VERSION 5.8 ;
BUSBITCHARS "[]" ;
DIVIDERCHAR "/" ;
UNITS
    DATABASE MICRONS 1000 ;
END UNITS

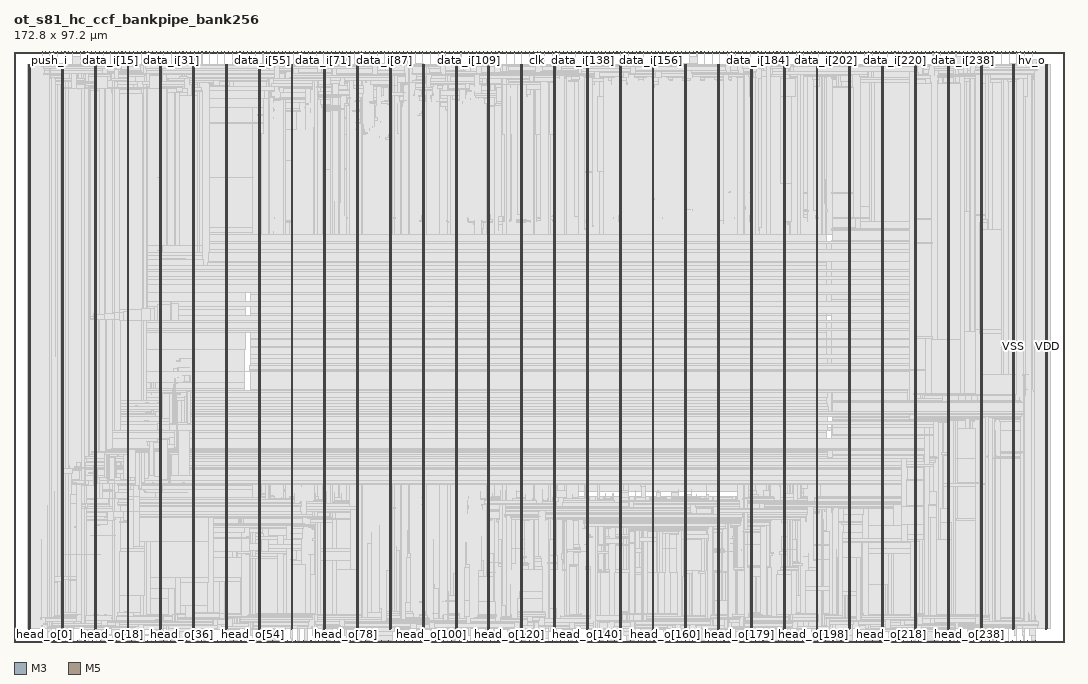
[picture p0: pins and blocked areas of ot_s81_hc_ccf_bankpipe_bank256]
MACRO ot_s81_hc_ccf_bankpipe_bank256
  FOREIGN ot_s81_hc_ccf_bankpipe_bank256 0 0 ;
  CLASS BLOCK ;
  SIZE 172.8 BY 97.2 ;
  PIN clk
    DIRECTION INPUT ;
    USE SIGNAL ;
    PORT
      LAYER M3 ;
        RECT  86.076 97.056 86.094 97.2 ;
    END
  END clk
  PIN data_i[0]
    DIRECTION INPUT ;
    USE SIGNAL ;
    PORT
      LAYER M5 ;
        RECT  6.48 97.008 6.504 97.2 ;
    END
  END data_i[0]
  PIN data_i[100]
    DIRECTION INPUT ;
    USE SIGNAL ;
    PORT
      LAYER M5 ;
        RECT  69.168 97.008 69.192 97.2 ;
    END
  END data_i[100]
  PIN data_i[101]
    DIRECTION INPUT ;
    USE SIGNAL ;
    PORT
      LAYER M3 ;
        RECT  69.804 97.056 69.822 97.2 ;
    END
  END data_i[101]
  PIN data_i[102]
    DIRECTION INPUT ;
    USE SIGNAL ;
    PORT
      LAYER M5 ;
        RECT  70.416 97.008 70.44 97.2 ;
    END
  END data_i[102]
  PIN data_i[103]
    DIRECTION INPUT ;
    USE SIGNAL ;
    PORT
      LAYER M3 ;
        RECT  71.028 97.056 71.046 97.2 ;
    END
  END data_i[103]
  PIN data_i[104]
    DIRECTION INPUT ;
    USE SIGNAL ;
    PORT
      LAYER M5 ;
        RECT  71.664 97.008 71.688 97.2 ;
    END
  END data_i[104]
  PIN data_i[105]
    DIRECTION INPUT ;
    USE SIGNAL ;
    PORT
      LAYER M3 ;
        RECT  72.288 97.056 72.306 97.2 ;
    END
  END data_i[105]
  PIN data_i[106]
    DIRECTION INPUT ;
    USE SIGNAL ;
    PORT
      LAYER M5 ;
        RECT  72.912 97.008 72.936 97.2 ;
    END
  END data_i[106]
  PIN data_i[107]
    DIRECTION INPUT ;
    USE SIGNAL ;
    PORT
      LAYER M3 ;
        RECT  73.548 97.056 73.566 97.2 ;
    END
  END data_i[107]
  PIN data_i[108]
    DIRECTION INPUT ;
    USE SIGNAL ;
    PORT
      LAYER M5 ;
        RECT  74.16 97.008 74.184 97.2 ;
    END
  END data_i[108]
  PIN data_i[109]
    DIRECTION INPUT ;
    USE SIGNAL ;
    PORT
      LAYER M3 ;
        RECT  74.808 97.056 74.826 97.2 ;
    END
  END data_i[109]
  PIN data_i[10]
    DIRECTION INPUT ;
    USE SIGNAL ;
    PORT
      LAYER M5 ;
        RECT  12.768 97.008 12.792 97.2 ;
    END
  END data_i[10]
  PIN data_i[110]
    DIRECTION INPUT ;
    USE SIGNAL ;
    PORT
      LAYER M5 ;
        RECT  75.408 97.008 75.432 97.2 ;
    END
  END data_i[110]
  PIN data_i[111]
    DIRECTION INPUT ;
    USE SIGNAL ;
    PORT
      LAYER M3 ;
        RECT  76.068 97.056 76.086 97.2 ;
    END
  END data_i[111]
  PIN data_i[112]
    DIRECTION INPUT ;
    USE SIGNAL ;
    PORT
      LAYER M5 ;
        RECT  76.656 97.008 76.68 97.2 ;
    END
  END data_i[112]
  PIN data_i[113]
    DIRECTION INPUT ;
    USE SIGNAL ;
    PORT
      LAYER M3 ;
        RECT  77.292 97.056 77.31 97.2 ;
    END
  END data_i[113]
  PIN data_i[114]
    DIRECTION INPUT ;
    USE SIGNAL ;
    PORT
      LAYER M5 ;
        RECT  77.952 97.008 77.976 97.2 ;
    END
  END data_i[114]
  PIN data_i[115]
    DIRECTION INPUT ;
    USE SIGNAL ;
    PORT
      LAYER M3 ;
        RECT  78.552 97.056 78.57 97.2 ;
    END
  END data_i[115]
  PIN data_i[116]
    DIRECTION INPUT ;
    USE SIGNAL ;
    PORT
      LAYER M5 ;
        RECT  79.2 97.008 79.224 97.2 ;
    END
  END data_i[116]
  PIN data_i[117]
    DIRECTION INPUT ;
    USE SIGNAL ;
    PORT
      LAYER M3 ;
        RECT  79.812 97.056 79.83 97.2 ;
    END
  END data_i[117]
  PIN data_i[118]
    DIRECTION INPUT ;
    USE SIGNAL ;
    PORT
      LAYER M5 ;
        RECT  80.448 97.008 80.472 97.2 ;
    END
  END data_i[118]
  PIN data_i[119]
    DIRECTION INPUT ;
    USE SIGNAL ;
    PORT
      LAYER M3 ;
        RECT  81.072 97.056 81.09 97.2 ;
    END
  END data_i[119]
  PIN data_i[11]
    DIRECTION INPUT ;
    USE SIGNAL ;
    PORT
      LAYER M3 ;
        RECT  13.392 97.056 13.41 97.2 ;
    END
  END data_i[11]
  PIN data_i[120]
    DIRECTION INPUT ;
    USE SIGNAL ;
    PORT
      LAYER M5 ;
        RECT  81.696 97.008 81.72 97.2 ;
    END
  END data_i[120]
  PIN data_i[121]
    DIRECTION INPUT ;
    USE SIGNAL ;
    PORT
      LAYER M3 ;
        RECT  82.332 97.056 82.35 97.2 ;
    END
  END data_i[121]
  PIN data_i[122]
    DIRECTION INPUT ;
    USE SIGNAL ;
    PORT
      LAYER M5 ;
        RECT  82.944 97.008 82.968 97.2 ;
    END
  END data_i[122]
  PIN data_i[123]
    DIRECTION INPUT ;
    USE SIGNAL ;
    PORT
      LAYER M3 ;
        RECT  83.556 97.056 83.574 97.2 ;
    END
  END data_i[123]
  PIN data_i[124]
    DIRECTION INPUT ;
    USE SIGNAL ;
    PORT
      LAYER M5 ;
        RECT  84.192 97.008 84.216 97.2 ;
    END
  END data_i[124]
  PIN data_i[125]
    DIRECTION INPUT ;
    USE SIGNAL ;
    PORT
      LAYER M3 ;
        RECT  84.816 97.056 84.834 97.2 ;
    END
  END data_i[125]
  PIN data_i[126]
    DIRECTION INPUT ;
    USE SIGNAL ;
    PORT
      LAYER M5 ;
        RECT  85.44 97.008 85.464 97.2 ;
    END
  END data_i[126]
  PIN data_i[127]
    DIRECTION INPUT ;
    USE SIGNAL ;
    PORT
      LAYER M5 ;
        RECT  86.688 97.008 86.712 97.2 ;
    END
  END data_i[127]
  PIN data_i[128]
    DIRECTION INPUT ;
    USE SIGNAL ;
    PORT
      LAYER M3 ;
        RECT  87.336 97.056 87.354 97.2 ;
    END
  END data_i[128]
  PIN data_i[129]
    DIRECTION INPUT ;
    USE SIGNAL ;
    PORT
      LAYER M5 ;
        RECT  87.936 97.008 87.96 97.2 ;
    END
  END data_i[129]
  PIN data_i[12]
    DIRECTION INPUT ;
    USE SIGNAL ;
    PORT
      LAYER M5 ;
        RECT  14.016 97.008 14.04 97.2 ;
    END
  END data_i[12]
  PIN data_i[130]
    DIRECTION INPUT ;
    USE SIGNAL ;
    PORT
      LAYER M3 ;
        RECT  88.596 97.056 88.614 97.2 ;
    END
  END data_i[130]
  PIN data_i[131]
    DIRECTION INPUT ;
    USE SIGNAL ;
    PORT
      LAYER M5 ;
        RECT  89.184 97.008 89.208 97.2 ;
    END
  END data_i[131]
  PIN data_i[132]
    DIRECTION INPUT ;
    USE SIGNAL ;
    PORT
      LAYER M3 ;
        RECT  89.82 97.056 89.838 97.2 ;
    END
  END data_i[132]
  PIN data_i[133]
    DIRECTION INPUT ;
    USE SIGNAL ;
    PORT
      LAYER M5 ;
        RECT  90.48 97.008 90.504 97.2 ;
    END
  END data_i[133]
  PIN data_i[134]
    DIRECTION INPUT ;
    USE SIGNAL ;
    PORT
      LAYER M3 ;
        RECT  91.08 97.056 91.098 97.2 ;
    END
  END data_i[134]
  PIN data_i[135]
    DIRECTION INPUT ;
    USE SIGNAL ;
    PORT
      LAYER M5 ;
        RECT  91.728 97.008 91.752 97.2 ;
    END
  END data_i[135]
  PIN data_i[136]
    DIRECTION INPUT ;
    USE SIGNAL ;
    PORT
      LAYER M3 ;
        RECT  92.34 97.056 92.358 97.2 ;
    END
  END data_i[136]
  PIN data_i[137]
    DIRECTION INPUT ;
    USE SIGNAL ;
    PORT
      LAYER M5 ;
        RECT  92.976 97.008 93 97.2 ;
    END
  END data_i[137]
  PIN data_i[138]
    DIRECTION INPUT ;
    USE SIGNAL ;
    PORT
      LAYER M3 ;
        RECT  93.6 97.056 93.618 97.2 ;
    END
  END data_i[138]
  PIN data_i[139]
    DIRECTION INPUT ;
    USE SIGNAL ;
    PORT
      LAYER M5 ;
        RECT  94.224 97.008 94.248 97.2 ;
    END
  END data_i[139]
  PIN data_i[13]
    DIRECTION INPUT ;
    USE SIGNAL ;
    PORT
      LAYER M3 ;
        RECT  14.652 97.056 14.67 97.2 ;
    END
  END data_i[13]
  PIN data_i[140]
    DIRECTION INPUT ;
    USE SIGNAL ;
    PORT
      LAYER M3 ;
        RECT  94.86 97.056 94.878 97.2 ;
    END
  END data_i[140]
  PIN data_i[141]
    DIRECTION INPUT ;
    USE SIGNAL ;
    PORT
      LAYER M5 ;
        RECT  95.472 97.008 95.496 97.2 ;
    END
  END data_i[141]
  PIN data_i[142]
    DIRECTION INPUT ;
    USE SIGNAL ;
    PORT
      LAYER M3 ;
        RECT  96.12 97.056 96.138 97.2 ;
    END
  END data_i[142]
  PIN data_i[143]
    DIRECTION INPUT ;
    USE SIGNAL ;
    PORT
      LAYER M5 ;
        RECT  96.72 97.008 96.744 97.2 ;
    END
  END data_i[143]
  PIN data_i[144]
    DIRECTION INPUT ;
    USE SIGNAL ;
    PORT
      LAYER M3 ;
        RECT  97.344 97.056 97.362 97.2 ;
    END
  END data_i[144]
  PIN data_i[145]
    DIRECTION INPUT ;
    USE SIGNAL ;
    PORT
      LAYER M5 ;
        RECT  97.968 97.008 97.992 97.2 ;
    END
  END data_i[145]
  PIN data_i[146]
    DIRECTION INPUT ;
    USE SIGNAL ;
    PORT
      LAYER M3 ;
        RECT  98.604 97.056 98.622 97.2 ;
    END
  END data_i[146]
  PIN data_i[147]
    DIRECTION INPUT ;
    USE SIGNAL ;
    PORT
      LAYER M5 ;
        RECT  99.216 97.008 99.24 97.2 ;
    END
  END data_i[147]
  PIN data_i[148]
    DIRECTION INPUT ;
    USE SIGNAL ;
    PORT
      LAYER M3 ;
        RECT  99.864 97.056 99.882 97.2 ;
    END
  END data_i[148]
  PIN data_i[149]
    DIRECTION INPUT ;
    USE SIGNAL ;
    PORT
      LAYER M5 ;
        RECT  100.464 97.008 100.488 97.2 ;
    END
  END data_i[149]
  PIN data_i[14]
    DIRECTION INPUT ;
    USE SIGNAL ;
    PORT
      LAYER M5 ;
        RECT  15.264 97.008 15.288 97.2 ;
    END
  END data_i[14]
  PIN data_i[150]
    DIRECTION INPUT ;
    USE SIGNAL ;
    PORT
      LAYER M3 ;
        RECT  101.124 97.056 101.142 97.2 ;
    END
  END data_i[150]
  PIN data_i[151]
    DIRECTION INPUT ;
    USE SIGNAL ;
    PORT
      LAYER M5 ;
        RECT  101.76 97.008 101.784 97.2 ;
    END
  END data_i[151]
  PIN data_i[152]
    DIRECTION INPUT ;
    USE SIGNAL ;
    PORT
      LAYER M3 ;
        RECT  102.384 97.056 102.402 97.2 ;
    END
  END data_i[152]
  PIN data_i[153]
    DIRECTION INPUT ;
    USE SIGNAL ;
    PORT
      LAYER M5 ;
        RECT  103.008 97.008 103.032 97.2 ;
    END
  END data_i[153]
  PIN data_i[154]
    DIRECTION INPUT ;
    USE SIGNAL ;
    PORT
      LAYER M3 ;
        RECT  103.608 97.056 103.626 97.2 ;
    END
  END data_i[154]
  PIN data_i[155]
    DIRECTION INPUT ;
    USE SIGNAL ;
    PORT
      LAYER M5 ;
        RECT  104.256 97.008 104.28 97.2 ;
    END
  END data_i[155]
  PIN data_i[156]
    DIRECTION INPUT ;
    USE SIGNAL ;
    PORT
      LAYER M3 ;
        RECT  104.868 97.056 104.886 97.2 ;
    END
  END data_i[156]
  PIN data_i[157]
    DIRECTION INPUT ;
    USE SIGNAL ;
    PORT
      LAYER M5 ;
        RECT  105.504 97.008 105.528 97.2 ;
    END
  END data_i[157]
  PIN data_i[158]
    DIRECTION INPUT ;
    USE SIGNAL ;
    PORT
      LAYER M3 ;
        RECT  106.128 97.056 106.146 97.2 ;
    END
  END data_i[158]
  PIN data_i[159]
    DIRECTION INPUT ;
    USE SIGNAL ;
    PORT
      LAYER M5 ;
        RECT  106.752 97.008 106.776 97.2 ;
    END
  END data_i[159]
  PIN data_i[15]
    DIRECTION INPUT ;
    USE SIGNAL ;
    PORT
      LAYER M3 ;
        RECT  15.912 97.056 15.93 97.2 ;
    END
  END data_i[15]
  PIN data_i[160]
    DIRECTION INPUT ;
    USE SIGNAL ;
    PORT
      LAYER M3 ;
        RECT  107.388 97.056 107.406 97.2 ;
    END
  END data_i[160]
  PIN data_i[161]
    DIRECTION INPUT ;
    USE SIGNAL ;
    PORT
      LAYER M5 ;
        RECT  108 97.008 108.024 97.2 ;
    END
  END data_i[161]
  PIN data_i[162]
    DIRECTION INPUT ;
    USE SIGNAL ;
    PORT
      LAYER M3 ;
        RECT  108.648 97.056 108.666 97.2 ;
    END
  END data_i[162]
  PIN data_i[163]
    DIRECTION INPUT ;
    USE SIGNAL ;
    PORT
      LAYER M5 ;
        RECT  109.248 97.008 109.272 97.2 ;
    END
  END data_i[163]
  PIN data_i[164]
    DIRECTION INPUT ;
    USE SIGNAL ;
    PORT
      LAYER M3 ;
        RECT  109.872 97.056 109.89 97.2 ;
    END
  END data_i[164]
  PIN data_i[165]
    DIRECTION INPUT ;
    USE SIGNAL ;
    PORT
      LAYER M5 ;
        RECT  110.496 97.008 110.52 97.2 ;
    END
  END data_i[165]
  PIN data_i[166]
    DIRECTION INPUT ;
    USE SIGNAL ;
    PORT
      LAYER M3 ;
        RECT  111.132 97.056 111.15 97.2 ;
    END
  END data_i[166]
  PIN data_i[167]
    DIRECTION INPUT ;
    USE SIGNAL ;
    PORT
      LAYER M5 ;
        RECT  111.744 97.008 111.768 97.2 ;
    END
  END data_i[167]
  PIN data_i[168]
    DIRECTION INPUT ;
    USE SIGNAL ;
    PORT
      LAYER M3 ;
        RECT  112.392 97.056 112.41 97.2 ;
    END
  END data_i[168]
  PIN data_i[169]
    DIRECTION INPUT ;
    USE SIGNAL ;
    PORT
      LAYER M5 ;
        RECT  113.04 97.008 113.064 97.2 ;
    END
  END data_i[169]
  PIN data_i[16]
    DIRECTION INPUT ;
    USE SIGNAL ;
    PORT
      LAYER M5 ;
        RECT  16.512 97.008 16.536 97.2 ;
    END
  END data_i[16]
  PIN data_i[170]
    DIRECTION INPUT ;
    USE SIGNAL ;
    PORT
      LAYER M3 ;
        RECT  113.652 97.056 113.67 97.2 ;
    END
  END data_i[170]
  PIN data_i[171]
    DIRECTION INPUT ;
    USE SIGNAL ;
    PORT
      LAYER M5 ;
        RECT  114.288 97.008 114.312 97.2 ;
    END
  END data_i[171]
  PIN data_i[172]
    DIRECTION INPUT ;
    USE SIGNAL ;
    PORT
      LAYER M3 ;
        RECT  114.912 97.056 114.93 97.2 ;
    END
  END data_i[172]
  PIN data_i[173]
    DIRECTION INPUT ;
    USE SIGNAL ;
    PORT
      LAYER M5 ;
        RECT  115.536 97.008 115.56 97.2 ;
    END
  END data_i[173]
  PIN data_i[174]
    DIRECTION INPUT ;
    USE SIGNAL ;
    PORT
      LAYER M3 ;
        RECT  116.136 97.056 116.154 97.2 ;
    END
  END data_i[174]
  PIN data_i[175]
    DIRECTION INPUT ;
    USE SIGNAL ;
    PORT
      LAYER M5 ;
        RECT  116.784 97.008 116.808 97.2 ;
    END
  END data_i[175]
  PIN data_i[176]
    DIRECTION INPUT ;
    USE SIGNAL ;
    PORT
      LAYER M3 ;
        RECT  117.396 97.056 117.414 97.2 ;
    END
  END data_i[176]
  PIN data_i[177]
    DIRECTION INPUT ;
    USE SIGNAL ;
    PORT
      LAYER M5 ;
        RECT  118.032 97.008 118.056 97.2 ;
    END
  END data_i[177]
  PIN data_i[178]
    DIRECTION INPUT ;
    USE SIGNAL ;
    PORT
      LAYER M3 ;
        RECT  118.656 97.056 118.674 97.2 ;
    END
  END data_i[178]
  PIN data_i[179]
    DIRECTION INPUT ;
    USE SIGNAL ;
    PORT
      LAYER M5 ;
        RECT  119.28 97.008 119.304 97.2 ;
    END
  END data_i[179]
  PIN data_i[17]
    DIRECTION INPUT ;
    USE SIGNAL ;
    PORT
      LAYER M3 ;
        RECT  17.172 97.056 17.19 97.2 ;
    END
  END data_i[17]
  PIN data_i[180]
    DIRECTION INPUT ;
    USE SIGNAL ;
    PORT
      LAYER M3 ;
        RECT  119.916 97.056 119.934 97.2 ;
    END
  END data_i[180]
  PIN data_i[181]
    DIRECTION INPUT ;
    USE SIGNAL ;
    PORT
      LAYER M5 ;
        RECT  120.528 97.008 120.552 97.2 ;
    END
  END data_i[181]
  PIN data_i[182]
    DIRECTION INPUT ;
    USE SIGNAL ;
    PORT
      LAYER M3 ;
        RECT  121.176 97.056 121.194 97.2 ;
    END
  END data_i[182]
  PIN data_i[183]
    DIRECTION INPUT ;
    USE SIGNAL ;
    PORT
      LAYER M5 ;
        RECT  121.776 97.008 121.8 97.2 ;
    END
  END data_i[183]
  PIN data_i[184]
    DIRECTION INPUT ;
    USE SIGNAL ;
    PORT
      LAYER M3 ;
        RECT  122.436 97.056 122.454 97.2 ;
    END
  END data_i[184]
  PIN data_i[185]
    DIRECTION INPUT ;
    USE SIGNAL ;
    PORT
      LAYER M5 ;
        RECT  123.024 97.008 123.048 97.2 ;
    END
  END data_i[185]
  PIN data_i[186]
    DIRECTION INPUT ;
    USE SIGNAL ;
    PORT
      LAYER M3 ;
        RECT  123.66 97.056 123.678 97.2 ;
    END
  END data_i[186]
  PIN data_i[187]
    DIRECTION INPUT ;
    USE SIGNAL ;
    PORT
      LAYER M5 ;
        RECT  124.272 97.008 124.296 97.2 ;
    END
  END data_i[187]
  PIN data_i[188]
    DIRECTION INPUT ;
    USE SIGNAL ;
    PORT
      LAYER M3 ;
        RECT  124.92 97.056 124.938 97.2 ;
    END
  END data_i[188]
  PIN data_i[189]
    DIRECTION INPUT ;
    USE SIGNAL ;
    PORT
      LAYER M5 ;
        RECT  125.568 97.008 125.592 97.2 ;
    END
  END data_i[189]
  PIN data_i[18]
    DIRECTION INPUT ;
    USE SIGNAL ;
    PORT
      LAYER M5 ;
        RECT  17.76 97.008 17.784 97.2 ;
    END
  END data_i[18]
  PIN data_i[190]
    DIRECTION INPUT ;
    USE SIGNAL ;
    PORT
      LAYER M3 ;
        RECT  126.18 97.056 126.198 97.2 ;
    END
  END data_i[190]
  PIN data_i[191]
    DIRECTION INPUT ;
    USE SIGNAL ;
    PORT
      LAYER M5 ;
        RECT  126.816 97.008 126.84 97.2 ;
    END
  END data_i[191]
  PIN data_i[192]
    DIRECTION INPUT ;
    USE SIGNAL ;
    PORT
      LAYER M3 ;
        RECT  127.44 97.056 127.458 97.2 ;
    END
  END data_i[192]
  PIN data_i[193]
    DIRECTION INPUT ;
    USE SIGNAL ;
    PORT
      LAYER M5 ;
        RECT  128.064 97.008 128.088 97.2 ;
    END
  END data_i[193]
  PIN data_i[194]
    DIRECTION INPUT ;
    USE SIGNAL ;
    PORT
      LAYER M3 ;
        RECT  128.7 97.056 128.718 97.2 ;
    END
  END data_i[194]
  PIN data_i[195]
    DIRECTION INPUT ;
    USE SIGNAL ;
    PORT
      LAYER M5 ;
        RECT  129.312 97.008 129.336 97.2 ;
    END
  END data_i[195]
  PIN data_i[196]
    DIRECTION INPUT ;
    USE SIGNAL ;
    PORT
      LAYER M3 ;
        RECT  129.924 97.056 129.942 97.2 ;
    END
  END data_i[196]
  PIN data_i[197]
    DIRECTION INPUT ;
    USE SIGNAL ;
    PORT
      LAYER M5 ;
        RECT  130.56 97.008 130.584 97.2 ;
    END
  END data_i[197]
  PIN data_i[198]
    DIRECTION INPUT ;
    USE SIGNAL ;
    PORT
      LAYER M3 ;
        RECT  131.184 97.056 131.202 97.2 ;
    END
  END data_i[198]
  PIN data_i[199]
    DIRECTION INPUT ;
    USE SIGNAL ;
    PORT
      LAYER M5 ;
        RECT  131.808 97.008 131.832 97.2 ;
    END
  END data_i[199]
  PIN data_i[19]
    DIRECTION INPUT ;
    USE SIGNAL ;
    PORT
      LAYER M3 ;
        RECT  18.396 97.056 18.414 97.2 ;
    END
  END data_i[19]
  PIN data_i[1]
    DIRECTION INPUT ;
    USE SIGNAL ;
    PORT
      LAYER M3 ;
        RECT  7.128 97.056 7.146 97.2 ;
    END
  END data_i[1]
  PIN data_i[200]
    DIRECTION INPUT ;
    USE SIGNAL ;
    PORT
      LAYER M3 ;
        RECT  132.444 97.056 132.462 97.2 ;
    END
  END data_i[200]
  PIN data_i[201]
    DIRECTION INPUT ;
    USE SIGNAL ;
    PORT
      LAYER M5 ;
        RECT  133.056 97.008 133.08 97.2 ;
    END
  END data_i[201]
  PIN data_i[202]
    DIRECTION INPUT ;
    USE SIGNAL ;
    PORT
      LAYER M3 ;
        RECT  133.704 97.056 133.722 97.2 ;
    END
  END data_i[202]
  PIN data_i[203]
    DIRECTION INPUT ;
    USE SIGNAL ;
    PORT
      LAYER M5 ;
        RECT  134.304 97.008 134.328 97.2 ;
    END
  END data_i[203]
  PIN data_i[204]
    DIRECTION INPUT ;
    USE SIGNAL ;
    PORT
      LAYER M3 ;
        RECT  134.964 97.056 134.982 97.2 ;
    END
  END data_i[204]
  PIN data_i[205]
    DIRECTION INPUT ;
    USE SIGNAL ;
    PORT
      LAYER M5 ;
        RECT  135.552 97.008 135.576 97.2 ;
    END
  END data_i[205]
  PIN data_i[206]
    DIRECTION INPUT ;
    USE SIGNAL ;
    PORT
      LAYER M3 ;
        RECT  136.188 97.056 136.206 97.2 ;
    END
  END data_i[206]
  PIN data_i[207]
    DIRECTION INPUT ;
    USE SIGNAL ;
    PORT
      LAYER M5 ;
        RECT  136.848 97.008 136.872 97.2 ;
    END
  END data_i[207]
  PIN data_i[208]
    DIRECTION INPUT ;
    USE SIGNAL ;
    PORT
      LAYER M3 ;
        RECT  137.448 97.056 137.466 97.2 ;
    END
  END data_i[208]
  PIN data_i[209]
    DIRECTION INPUT ;
    USE SIGNAL ;
    PORT
      LAYER M5 ;
        RECT  138.096 97.008 138.12 97.2 ;
    END
  END data_i[209]
  PIN data_i[20]
    DIRECTION INPUT ;
    USE SIGNAL ;
    PORT
      LAYER M5 ;
        RECT  19.056 97.008 19.08 97.2 ;
    END
  END data_i[20]
  PIN data_i[210]
    DIRECTION INPUT ;
    USE SIGNAL ;
    PORT
      LAYER M3 ;
        RECT  138.708 97.056 138.726 97.2 ;
    END
  END data_i[210]
  PIN data_i[211]
    DIRECTION INPUT ;
    USE SIGNAL ;
    PORT
      LAYER M5 ;
        RECT  139.344 97.008 139.368 97.2 ;
    END
  END data_i[211]
  PIN data_i[212]
    DIRECTION INPUT ;
    USE SIGNAL ;
    PORT
      LAYER M3 ;
        RECT  139.968 97.056 139.986 97.2 ;
    END
  END data_i[212]
  PIN data_i[213]
    DIRECTION INPUT ;
    USE SIGNAL ;
    PORT
      LAYER M5 ;
        RECT  140.592 97.008 140.616 97.2 ;
    END
  END data_i[213]
  PIN data_i[214]
    DIRECTION INPUT ;
    USE SIGNAL ;
    PORT
      LAYER M3 ;
        RECT  141.228 97.056 141.246 97.2 ;
    END
  END data_i[214]
  PIN data_i[215]
    DIRECTION INPUT ;
    USE SIGNAL ;
    PORT
      LAYER M5 ;
        RECT  141.84 97.008 141.864 97.2 ;
    END
  END data_i[215]
  PIN data_i[216]
    DIRECTION INPUT ;
    USE SIGNAL ;
    PORT
      LAYER M3 ;
        RECT  142.452 97.056 142.47 97.2 ;
    END
  END data_i[216]
  PIN data_i[217]
    DIRECTION INPUT ;
    USE SIGNAL ;
    PORT
      LAYER M5 ;
        RECT  143.088 97.008 143.112 97.2 ;
    END
  END data_i[217]
  PIN data_i[218]
    DIRECTION INPUT ;
    USE SIGNAL ;
    PORT
      LAYER M3 ;
        RECT  143.712 97.056 143.73 97.2 ;
    END
  END data_i[218]
  PIN data_i[219]
    DIRECTION INPUT ;
    USE SIGNAL ;
    PORT
      LAYER M5 ;
        RECT  144.336 97.008 144.36 97.2 ;
    END
  END data_i[219]
  PIN data_i[21]
    DIRECTION INPUT ;
    USE SIGNAL ;
    PORT
      LAYER M3 ;
        RECT  19.656 97.056 19.674 97.2 ;
    END
  END data_i[21]
  PIN data_i[220]
    DIRECTION INPUT ;
    USE SIGNAL ;
    PORT
      LAYER M3 ;
        RECT  144.972 97.056 144.99 97.2 ;
    END
  END data_i[220]
  PIN data_i[221]
    DIRECTION INPUT ;
    USE SIGNAL ;
    PORT
      LAYER M5 ;
        RECT  145.584 97.008 145.608 97.2 ;
    END
  END data_i[221]
  PIN data_i[222]
    DIRECTION INPUT ;
    USE SIGNAL ;
    PORT
      LAYER M3 ;
        RECT  146.232 97.056 146.25 97.2 ;
    END
  END data_i[222]
  PIN data_i[223]
    DIRECTION INPUT ;
    USE SIGNAL ;
    PORT
      LAYER M5 ;
        RECT  146.832 97.008 146.856 97.2 ;
    END
  END data_i[223]
  PIN data_i[224]
    DIRECTION INPUT ;
    USE SIGNAL ;
    PORT
      LAYER M3 ;
        RECT  147.492 97.056 147.51 97.2 ;
    END
  END data_i[224]
  PIN data_i[225]
    DIRECTION INPUT ;
    USE SIGNAL ;
    PORT
      LAYER M5 ;
        RECT  148.128 97.008 148.152 97.2 ;
    END
  END data_i[225]
  PIN data_i[226]
    DIRECTION INPUT ;
    USE SIGNAL ;
    PORT
      LAYER M3 ;
        RECT  148.752 97.056 148.77 97.2 ;
    END
  END data_i[226]
  PIN data_i[227]
    DIRECTION INPUT ;
    USE SIGNAL ;
    PORT
      LAYER M5 ;
        RECT  149.376 97.008 149.4 97.2 ;
    END
  END data_i[227]
  PIN data_i[228]
    DIRECTION INPUT ;
    USE SIGNAL ;
    PORT
      LAYER M3 ;
        RECT  149.976 97.056 149.994 97.2 ;
    END
  END data_i[228]
  PIN data_i[229]
    DIRECTION INPUT ;
    USE SIGNAL ;
    PORT
      LAYER M5 ;
        RECT  150.624 97.008 150.648 97.2 ;
    END
  END data_i[229]
  PIN data_i[22]
    DIRECTION INPUT ;
    USE SIGNAL ;
    PORT
      LAYER M5 ;
        RECT  20.304 97.008 20.328 97.2 ;
    END
  END data_i[22]
  PIN data_i[230]
    DIRECTION INPUT ;
    USE SIGNAL ;
    PORT
      LAYER M3 ;
        RECT  151.236 97.056 151.254 97.2 ;
    END
  END data_i[230]
  PIN data_i[231]
    DIRECTION INPUT ;
    USE SIGNAL ;
    PORT
      LAYER M5 ;
        RECT  151.872 97.008 151.896 97.2 ;
    END
  END data_i[231]
  PIN data_i[232]
    DIRECTION INPUT ;
    USE SIGNAL ;
    PORT
      LAYER M3 ;
        RECT  152.496 97.056 152.514 97.2 ;
    END
  END data_i[232]
  PIN data_i[233]
    DIRECTION INPUT ;
    USE SIGNAL ;
    PORT
      LAYER M5 ;
        RECT  153.12 97.008 153.144 97.2 ;
    END
  END data_i[233]
  PIN data_i[234]
    DIRECTION INPUT ;
    USE SIGNAL ;
    PORT
      LAYER M3 ;
        RECT  153.756 97.056 153.774 97.2 ;
    END
  END data_i[234]
  PIN data_i[235]
    DIRECTION INPUT ;
    USE SIGNAL ;
    PORT
      LAYER M5 ;
        RECT  154.368 97.008 154.392 97.2 ;
    END
  END data_i[235]
  PIN data_i[236]
    DIRECTION INPUT ;
    USE SIGNAL ;
    PORT
      LAYER M3 ;
        RECT  155.016 97.056 155.034 97.2 ;
    END
  END data_i[236]
  PIN data_i[237]
    DIRECTION INPUT ;
    USE SIGNAL ;
    PORT
      LAYER M5 ;
        RECT  155.616 97.008 155.64 97.2 ;
    END
  END data_i[237]
  PIN data_i[238]
    DIRECTION INPUT ;
    USE SIGNAL ;
    PORT
      LAYER M3 ;
        RECT  156.24 97.056 156.258 97.2 ;
    END
  END data_i[238]
  PIN data_i[239]
    DIRECTION INPUT ;
    USE SIGNAL ;
    PORT
      LAYER M5 ;
        RECT  156.864 97.008 156.888 97.2 ;
    END
  END data_i[239]
  PIN data_i[23]
    DIRECTION INPUT ;
    USE SIGNAL ;
    PORT
      LAYER M3 ;
        RECT  20.916 97.056 20.934 97.2 ;
    END
  END data_i[23]
  PIN data_i[240]
    DIRECTION INPUT ;
    USE SIGNAL ;
    PORT
      LAYER M3 ;
        RECT  157.5 97.056 157.518 97.2 ;
    END
  END data_i[240]
  PIN data_i[241]
    DIRECTION INPUT ;
    USE SIGNAL ;
    PORT
      LAYER M5 ;
        RECT  158.112 97.008 158.136 97.2 ;
    END
  END data_i[241]
  PIN data_i[242]
    DIRECTION INPUT ;
    USE SIGNAL ;
    PORT
      LAYER M3 ;
        RECT  158.76 97.056 158.778 97.2 ;
    END
  END data_i[242]
  PIN data_i[243]
    DIRECTION INPUT ;
    USE SIGNAL ;
    PORT
      LAYER M5 ;
        RECT  159.36 97.008 159.384 97.2 ;
    END
  END data_i[243]
  PIN data_i[244]
    DIRECTION INPUT ;
    USE SIGNAL ;
    PORT
      LAYER M3 ;
        RECT  160.02 97.056 160.038 97.2 ;
    END
  END data_i[244]
  PIN data_i[245]
    DIRECTION INPUT ;
    USE SIGNAL ;
    PORT
      LAYER M5 ;
        RECT  160.656 97.008 160.68 97.2 ;
    END
  END data_i[245]
  PIN data_i[246]
    DIRECTION INPUT ;
    USE SIGNAL ;
    PORT
      LAYER M3 ;
        RECT  161.28 97.056 161.298 97.2 ;
    END
  END data_i[246]
  PIN data_i[247]
    DIRECTION INPUT ;
    USE SIGNAL ;
    PORT
      LAYER M5 ;
        RECT  161.904 97.008 161.928 97.2 ;
    END
  END data_i[247]
  PIN data_i[248]
    DIRECTION INPUT ;
    USE SIGNAL ;
    PORT
      LAYER M3 ;
        RECT  162.504 97.056 162.522 97.2 ;
    END
  END data_i[248]
  PIN data_i[249]
    DIRECTION INPUT ;
    USE SIGNAL ;
    PORT
      LAYER M5 ;
        RECT  163.152 97.008 163.176 97.2 ;
    END
  END data_i[249]
  PIN data_i[24]
    DIRECTION INPUT ;
    USE SIGNAL ;
    PORT
      LAYER M5 ;
        RECT  21.552 97.008 21.576 97.2 ;
    END
  END data_i[24]
  PIN data_i[250]
    DIRECTION INPUT ;
    USE SIGNAL ;
    PORT
      LAYER M3 ;
        RECT  163.764 97.056 163.782 97.2 ;
    END
  END data_i[250]
  PIN data_i[251]
    DIRECTION INPUT ;
    USE SIGNAL ;
    PORT
      LAYER M5 ;
        RECT  164.4 97.008 164.424 97.2 ;
    END
  END data_i[251]
  PIN data_i[252]
    DIRECTION INPUT ;
    USE SIGNAL ;
    PORT
      LAYER M3 ;
        RECT  165.024 97.056 165.042 97.2 ;
    END
  END data_i[252]
  PIN data_i[253]
    DIRECTION INPUT ;
    USE SIGNAL ;
    PORT
      LAYER M5 ;
        RECT  165.648 97.008 165.672 97.2 ;
    END
  END data_i[253]
  PIN data_i[254]
    DIRECTION INPUT ;
    USE SIGNAL ;
    PORT
      LAYER M3 ;
        RECT  166.284 97.056 166.302 97.2 ;
    END
  END data_i[254]
  PIN data_i[255]
    DIRECTION INPUT ;
    USE SIGNAL ;
    PORT
      LAYER M5 ;
        RECT  166.896 97.008 166.92 97.2 ;
    END
  END data_i[255]
  PIN data_i[25]
    DIRECTION INPUT ;
    USE SIGNAL ;
    PORT
      LAYER M3 ;
        RECT  22.176 97.056 22.194 97.2 ;
    END
  END data_i[25]
  PIN data_i[26]
    DIRECTION INPUT ;
    USE SIGNAL ;
    PORT
      LAYER M5 ;
        RECT  22.8 97.008 22.824 97.2 ;
    END
  END data_i[26]
  PIN data_i[27]
    DIRECTION INPUT ;
    USE SIGNAL ;
    PORT
      LAYER M3 ;
        RECT  23.436 97.056 23.454 97.2 ;
    END
  END data_i[27]
  PIN data_i[28]
    DIRECTION INPUT ;
    USE SIGNAL ;
    PORT
      LAYER M5 ;
        RECT  24.048 97.008 24.072 97.2 ;
    END
  END data_i[28]
  PIN data_i[29]
    DIRECTION INPUT ;
    USE SIGNAL ;
    PORT
      LAYER M3 ;
        RECT  24.66 97.056 24.678 97.2 ;
    END
  END data_i[29]
  PIN data_i[2]
    DIRECTION INPUT ;
    USE SIGNAL ;
    PORT
      LAYER M5 ;
        RECT  7.776 97.008 7.8 97.2 ;
    END
  END data_i[2]
  PIN data_i[30]
    DIRECTION INPUT ;
    USE SIGNAL ;
    PORT
      LAYER M5 ;
        RECT  25.296 97.008 25.32 97.2 ;
    END
  END data_i[30]
  PIN data_i[31]
    DIRECTION INPUT ;
    USE SIGNAL ;
    PORT
      LAYER M3 ;
        RECT  25.92 97.056 25.938 97.2 ;
    END
  END data_i[31]
  PIN data_i[32]
    DIRECTION INPUT ;
    USE SIGNAL ;
    PORT
      LAYER M5 ;
        RECT  26.544 97.008 26.568 97.2 ;
    END
  END data_i[32]
  PIN data_i[33]
    DIRECTION INPUT ;
    USE SIGNAL ;
    PORT
      LAYER M3 ;
        RECT  27.18 97.056 27.198 97.2 ;
    END
  END data_i[33]
  PIN data_i[34]
    DIRECTION INPUT ;
    USE SIGNAL ;
    PORT
      LAYER M5 ;
        RECT  27.792 97.008 27.816 97.2 ;
    END
  END data_i[34]
  PIN data_i[35]
    DIRECTION INPUT ;
    USE SIGNAL ;
    PORT
      LAYER M3 ;
        RECT  28.44 97.056 28.458 97.2 ;
    END
  END data_i[35]
  PIN data_i[36]
    DIRECTION INPUT ;
    USE SIGNAL ;
    PORT
      LAYER M5 ;
        RECT  29.04 97.008 29.064 97.2 ;
    END
  END data_i[36]
  PIN data_i[37]
    DIRECTION INPUT ;
    USE SIGNAL ;
    PORT
      LAYER M3 ;
        RECT  29.7 97.056 29.718 97.2 ;
    END
  END data_i[37]
  PIN data_i[38]
    DIRECTION INPUT ;
    USE SIGNAL ;
    PORT
      LAYER M5 ;
        RECT  30.288 97.008 30.312 97.2 ;
    END
  END data_i[38]
  PIN data_i[39]
    DIRECTION INPUT ;
    USE SIGNAL ;
    PORT
      LAYER M3 ;
        RECT  30.924 97.056 30.942 97.2 ;
    END
  END data_i[39]
  PIN data_i[3]
    DIRECTION INPUT ;
    USE SIGNAL ;
    PORT
      LAYER M3 ;
        RECT  8.388 97.056 8.406 97.2 ;
    END
  END data_i[3]
  PIN data_i[40]
    DIRECTION INPUT ;
    USE SIGNAL ;
    PORT
      LAYER M5 ;
        RECT  31.584 97.008 31.608 97.2 ;
    END
  END data_i[40]
  PIN data_i[41]
    DIRECTION INPUT ;
    USE SIGNAL ;
    PORT
      LAYER M3 ;
        RECT  32.184 97.056 32.202 97.2 ;
    END
  END data_i[41]
  PIN data_i[42]
    DIRECTION INPUT ;
    USE SIGNAL ;
    PORT
      LAYER M5 ;
        RECT  32.832 97.008 32.856 97.2 ;
    END
  END data_i[42]
  PIN data_i[43]
    DIRECTION INPUT ;
    USE SIGNAL ;
    PORT
      LAYER M3 ;
        RECT  33.444 97.056 33.462 97.2 ;
    END
  END data_i[43]
  PIN data_i[44]
    DIRECTION INPUT ;
    USE SIGNAL ;
    PORT
      LAYER M5 ;
        RECT  34.08 97.008 34.104 97.2 ;
    END
  END data_i[44]
  PIN data_i[45]
    DIRECTION INPUT ;
    USE SIGNAL ;
    PORT
      LAYER M3 ;
        RECT  34.704 97.056 34.722 97.2 ;
    END
  END data_i[45]
  PIN data_i[46]
    DIRECTION INPUT ;
    USE SIGNAL ;
    PORT
      LAYER M5 ;
        RECT  35.328 97.008 35.352 97.2 ;
    END
  END data_i[46]
  PIN data_i[47]
    DIRECTION INPUT ;
    USE SIGNAL ;
    PORT
      LAYER M3 ;
        RECT  35.964 97.056 35.982 97.2 ;
    END
  END data_i[47]
  PIN data_i[48]
    DIRECTION INPUT ;
    USE SIGNAL ;
    PORT
      LAYER M5 ;
        RECT  36.576 97.008 36.6 97.2 ;
    END
  END data_i[48]
  PIN data_i[49]
    DIRECTION INPUT ;
    USE SIGNAL ;
    PORT
      LAYER M3 ;
        RECT  37.188 97.056 37.206 97.2 ;
    END
  END data_i[49]
  PIN data_i[4]
    DIRECTION INPUT ;
    USE SIGNAL ;
    PORT
      LAYER M5 ;
        RECT  9.024 97.008 9.048 97.2 ;
    END
  END data_i[4]
  PIN data_i[50]
    DIRECTION INPUT ;
    USE SIGNAL ;
    PORT
      LAYER M5 ;
        RECT  37.824 97.008 37.848 97.2 ;
    END
  END data_i[50]
  PIN data_i[51]
    DIRECTION INPUT ;
    USE SIGNAL ;
    PORT
      LAYER M3 ;
        RECT  38.448 97.056 38.466 97.2 ;
    END
  END data_i[51]
  PIN data_i[52]
    DIRECTION INPUT ;
    USE SIGNAL ;
    PORT
      LAYER M5 ;
        RECT  39.072 97.008 39.096 97.2 ;
    END
  END data_i[52]
  PIN data_i[53]
    DIRECTION INPUT ;
    USE SIGNAL ;
    PORT
      LAYER M3 ;
        RECT  39.708 97.056 39.726 97.2 ;
    END
  END data_i[53]
  PIN data_i[54]
    DIRECTION INPUT ;
    USE SIGNAL ;
    PORT
      LAYER M5 ;
        RECT  40.32 97.008 40.344 97.2 ;
    END
  END data_i[54]
  PIN data_i[55]
    DIRECTION INPUT ;
    USE SIGNAL ;
    PORT
      LAYER M3 ;
        RECT  40.968 97.056 40.986 97.2 ;
    END
  END data_i[55]
  PIN data_i[56]
    DIRECTION INPUT ;
    USE SIGNAL ;
    PORT
      LAYER M5 ;
        RECT  41.568 97.008 41.592 97.2 ;
    END
  END data_i[56]
  PIN data_i[57]
    DIRECTION INPUT ;
    USE SIGNAL ;
    PORT
      LAYER M3 ;
        RECT  42.228 97.056 42.246 97.2 ;
    END
  END data_i[57]
  PIN data_i[58]
    DIRECTION INPUT ;
    USE SIGNAL ;
    PORT
      LAYER M5 ;
        RECT  42.864 97.008 42.888 97.2 ;
    END
  END data_i[58]
  PIN data_i[59]
    DIRECTION INPUT ;
    USE SIGNAL ;
    PORT
      LAYER M3 ;
        RECT  43.488 97.056 43.506 97.2 ;
    END
  END data_i[59]
  PIN data_i[5]
    DIRECTION INPUT ;
    USE SIGNAL ;
    PORT
      LAYER M3 ;
        RECT  9.648 97.056 9.666 97.2 ;
    END
  END data_i[5]
  PIN data_i[60]
    DIRECTION INPUT ;
    USE SIGNAL ;
    PORT
      LAYER M5 ;
        RECT  44.112 97.008 44.136 97.2 ;
    END
  END data_i[60]
  PIN data_i[61]
    DIRECTION INPUT ;
    USE SIGNAL ;
    PORT
      LAYER M3 ;
        RECT  44.712 97.056 44.73 97.2 ;
    END
  END data_i[61]
  PIN data_i[62]
    DIRECTION INPUT ;
    USE SIGNAL ;
    PORT
      LAYER M5 ;
        RECT  45.36 97.008 45.384 97.2 ;
    END
  END data_i[62]
  PIN data_i[63]
    DIRECTION INPUT ;
    USE SIGNAL ;
    PORT
      LAYER M3 ;
        RECT  45.972 97.056 45.99 97.2 ;
    END
  END data_i[63]
  PIN data_i[64]
    DIRECTION INPUT ;
    USE SIGNAL ;
    PORT
      LAYER M5 ;
        RECT  46.608 97.008 46.632 97.2 ;
    END
  END data_i[64]
  PIN data_i[65]
    DIRECTION INPUT ;
    USE SIGNAL ;
    PORT
      LAYER M3 ;
        RECT  47.232 97.056 47.25 97.2 ;
    END
  END data_i[65]
  PIN data_i[66]
    DIRECTION INPUT ;
    USE SIGNAL ;
    PORT
      LAYER M5 ;
        RECT  47.856 97.008 47.88 97.2 ;
    END
  END data_i[66]
  PIN data_i[67]
    DIRECTION INPUT ;
    USE SIGNAL ;
    PORT
      LAYER M3 ;
        RECT  48.492 97.056 48.51 97.2 ;
    END
  END data_i[67]
  PIN data_i[68]
    DIRECTION INPUT ;
    USE SIGNAL ;
    PORT
      LAYER M5 ;
        RECT  49.104 97.008 49.128 97.2 ;
    END
  END data_i[68]
  PIN data_i[69]
    DIRECTION INPUT ;
    USE SIGNAL ;
    PORT
      LAYER M3 ;
        RECT  49.752 97.056 49.77 97.2 ;
    END
  END data_i[69]
  PIN data_i[6]
    DIRECTION INPUT ;
    USE SIGNAL ;
    PORT
      LAYER M5 ;
        RECT  10.272 97.008 10.296 97.2 ;
    END
  END data_i[6]
  PIN data_i[70]
    DIRECTION INPUT ;
    USE SIGNAL ;
    PORT
      LAYER M5 ;
        RECT  50.352 97.008 50.376 97.2 ;
    END
  END data_i[70]
  PIN data_i[71]
    DIRECTION INPUT ;
    USE SIGNAL ;
    PORT
      LAYER M3 ;
        RECT  50.976 97.056 50.994 97.2 ;
    END
  END data_i[71]
  PIN data_i[72]
    DIRECTION INPUT ;
    USE SIGNAL ;
    PORT
      LAYER M5 ;
        RECT  51.6 97.008 51.624 97.2 ;
    END
  END data_i[72]
  PIN data_i[73]
    DIRECTION INPUT ;
    USE SIGNAL ;
    PORT
      LAYER M3 ;
        RECT  52.236 97.056 52.254 97.2 ;
    END
  END data_i[73]
  PIN data_i[74]
    DIRECTION INPUT ;
    USE SIGNAL ;
    PORT
      LAYER M5 ;
        RECT  52.848 97.008 52.872 97.2 ;
    END
  END data_i[74]
  PIN data_i[75]
    DIRECTION INPUT ;
    USE SIGNAL ;
    PORT
      LAYER M3 ;
        RECT  53.496 97.056 53.514 97.2 ;
    END
  END data_i[75]
  PIN data_i[76]
    DIRECTION INPUT ;
    USE SIGNAL ;
    PORT
      LAYER M5 ;
        RECT  54.096 97.008 54.12 97.2 ;
    END
  END data_i[76]
  PIN data_i[77]
    DIRECTION INPUT ;
    USE SIGNAL ;
    PORT
      LAYER M3 ;
        RECT  54.756 97.056 54.774 97.2 ;
    END
  END data_i[77]
  PIN data_i[78]
    DIRECTION INPUT ;
    USE SIGNAL ;
    PORT
      LAYER M5 ;
        RECT  55.392 97.008 55.416 97.2 ;
    END
  END data_i[78]
  PIN data_i[79]
    DIRECTION INPUT ;
    USE SIGNAL ;
    PORT
      LAYER M3 ;
        RECT  56.016 97.056 56.034 97.2 ;
    END
  END data_i[79]
  PIN data_i[7]
    DIRECTION INPUT ;
    USE SIGNAL ;
    PORT
      LAYER M3 ;
        RECT  10.872 97.056 10.89 97.2 ;
    END
  END data_i[7]
  PIN data_i[80]
    DIRECTION INPUT ;
    USE SIGNAL ;
    PORT
      LAYER M5 ;
        RECT  56.64 97.008 56.664 97.2 ;
    END
  END data_i[80]
  PIN data_i[81]
    DIRECTION INPUT ;
    USE SIGNAL ;
    PORT
      LAYER M3 ;
        RECT  57.24 97.056 57.258 97.2 ;
    END
  END data_i[81]
  PIN data_i[82]
    DIRECTION INPUT ;
    USE SIGNAL ;
    PORT
      LAYER M5 ;
        RECT  57.888 97.008 57.912 97.2 ;
    END
  END data_i[82]
  PIN data_i[83]
    DIRECTION INPUT ;
    USE SIGNAL ;
    PORT
      LAYER M3 ;
        RECT  58.5 97.056 58.518 97.2 ;
    END
  END data_i[83]
  PIN data_i[84]
    DIRECTION INPUT ;
    USE SIGNAL ;
    PORT
      LAYER M5 ;
        RECT  59.136 97.008 59.16 97.2 ;
    END
  END data_i[84]
  PIN data_i[85]
    DIRECTION INPUT ;
    USE SIGNAL ;
    PORT
      LAYER M3 ;
        RECT  59.76 97.056 59.778 97.2 ;
    END
  END data_i[85]
  PIN data_i[86]
    DIRECTION INPUT ;
    USE SIGNAL ;
    PORT
      LAYER M5 ;
        RECT  60.384 97.008 60.408 97.2 ;
    END
  END data_i[86]
  PIN data_i[87]
    DIRECTION INPUT ;
    USE SIGNAL ;
    PORT
      LAYER M3 ;
        RECT  61.02 97.056 61.038 97.2 ;
    END
  END data_i[87]
  PIN data_i[88]
    DIRECTION INPUT ;
    USE SIGNAL ;
    PORT
      LAYER M5 ;
        RECT  61.632 97.008 61.656 97.2 ;
    END
  END data_i[88]
  PIN data_i[89]
    DIRECTION INPUT ;
    USE SIGNAL ;
    PORT
      LAYER M3 ;
        RECT  62.28 97.056 62.298 97.2 ;
    END
  END data_i[89]
  PIN data_i[8]
    DIRECTION INPUT ;
    USE SIGNAL ;
    PORT
      LAYER M5 ;
        RECT  11.52 97.008 11.544 97.2 ;
    END
  END data_i[8]
  PIN data_i[90]
    DIRECTION INPUT ;
    USE SIGNAL ;
    PORT
      LAYER M5 ;
        RECT  62.88 97.008 62.904 97.2 ;
    END
  END data_i[90]
  PIN data_i[91]
    DIRECTION INPUT ;
    USE SIGNAL ;
    PORT
      LAYER M3 ;
        RECT  63.504 97.056 63.522 97.2 ;
    END
  END data_i[91]
  PIN data_i[92]
    DIRECTION INPUT ;
    USE SIGNAL ;
    PORT
      LAYER M5 ;
        RECT  64.128 97.008 64.152 97.2 ;
    END
  END data_i[92]
  PIN data_i[93]
    DIRECTION INPUT ;
    USE SIGNAL ;
    PORT
      LAYER M3 ;
        RECT  64.764 97.056 64.782 97.2 ;
    END
  END data_i[93]
  PIN data_i[94]
    DIRECTION INPUT ;
    USE SIGNAL ;
    PORT
      LAYER M5 ;
        RECT  65.376 97.008 65.4 97.2 ;
    END
  END data_i[94]
  PIN data_i[95]
    DIRECTION INPUT ;
    USE SIGNAL ;
    PORT
      LAYER M3 ;
        RECT  66.024 97.056 66.042 97.2 ;
    END
  END data_i[95]
  PIN data_i[96]
    DIRECTION INPUT ;
    USE SIGNAL ;
    PORT
      LAYER M5 ;
        RECT  66.672 97.008 66.696 97.2 ;
    END
  END data_i[96]
  PIN data_i[97]
    DIRECTION INPUT ;
    USE SIGNAL ;
    PORT
      LAYER M3 ;
        RECT  67.284 97.056 67.302 97.2 ;
    END
  END data_i[97]
  PIN data_i[98]
    DIRECTION INPUT ;
    USE SIGNAL ;
    PORT
      LAYER M5 ;
        RECT  67.92 97.008 67.944 97.2 ;
    END
  END data_i[98]
  PIN data_i[99]
    DIRECTION INPUT ;
    USE SIGNAL ;
    PORT
      LAYER M3 ;
        RECT  68.544 97.056 68.562 97.2 ;
    END
  END data_i[99]
  PIN data_i[9]
    DIRECTION INPUT ;
    USE SIGNAL ;
    PORT
      LAYER M3 ;
        RECT  12.132 97.056 12.15 97.2 ;
    END
  END data_i[9]
  PIN head_o[0]
    DIRECTION OUTPUT ;
    USE SIGNAL ;
    PORT
      LAYER M3 ;
        RECT  4.644 0 4.662 0.144 ;
    END
  END head_o[0]
  PIN head_o[100]
    DIRECTION OUTPUT ;
    USE SIGNAL ;
    PORT
      LAYER M3 ;
        RECT  68.76 0 68.778 0.144 ;
    END
  END head_o[100]
  PIN head_o[101]
    DIRECTION OUTPUT ;
    USE SIGNAL ;
    PORT
      LAYER M5 ;
        RECT  69.408 0 69.432 0.192 ;
    END
  END head_o[101]
  PIN head_o[102]
    DIRECTION OUTPUT ;
    USE SIGNAL ;
    PORT
      LAYER M3 ;
        RECT  70.056 0 70.074 0.144 ;
    END
  END head_o[102]
  PIN head_o[103]
    DIRECTION OUTPUT ;
    USE SIGNAL ;
    PORT
      LAYER M5 ;
        RECT  70.656 0 70.68 0.192 ;
    END
  END head_o[103]
  PIN head_o[104]
    DIRECTION OUTPUT ;
    USE SIGNAL ;
    PORT
      LAYER M3 ;
        RECT  71.316 0 71.334 0.144 ;
    END
  END head_o[104]
  PIN head_o[105]
    DIRECTION OUTPUT ;
    USE SIGNAL ;
    PORT
      LAYER M5 ;
        RECT  71.952 0 71.976 0.192 ;
    END
  END head_o[105]
  PIN head_o[106]
    DIRECTION OUTPUT ;
    USE SIGNAL ;
    PORT
      LAYER M3 ;
        RECT  72.612 0 72.63 0.144 ;
    END
  END head_o[106]
  PIN head_o[107]
    DIRECTION OUTPUT ;
    USE SIGNAL ;
    PORT
      LAYER M5 ;
        RECT  73.248 0 73.272 0.192 ;
    END
  END head_o[107]
  PIN head_o[108]
    DIRECTION OUTPUT ;
    USE SIGNAL ;
    PORT
      LAYER M3 ;
        RECT  73.872 0 73.89 0.144 ;
    END
  END head_o[108]
  PIN head_o[109]
    DIRECTION OUTPUT ;
    USE SIGNAL ;
    PORT
      LAYER M5 ;
        RECT  74.544 0 74.568 0.192 ;
    END
  END head_o[109]
  PIN head_o[10]
    DIRECTION OUTPUT ;
    USE SIGNAL ;
    PORT
      LAYER M3 ;
        RECT  11.052 0 11.07 0.144 ;
    END
  END head_o[10]
  PIN head_o[110]
    DIRECTION OUTPUT ;
    USE SIGNAL ;
    PORT
      LAYER M3 ;
        RECT  75.168 0 75.186 0.144 ;
    END
  END head_o[110]
  PIN head_o[111]
    DIRECTION OUTPUT ;
    USE SIGNAL ;
    PORT
      LAYER M5 ;
        RECT  75.792 0 75.816 0.192 ;
    END
  END head_o[111]
  PIN head_o[112]
    DIRECTION OUTPUT ;
    USE SIGNAL ;
    PORT
      LAYER M3 ;
        RECT  76.464 0 76.482 0.144 ;
    END
  END head_o[112]
  PIN head_o[113]
    DIRECTION OUTPUT ;
    USE SIGNAL ;
    PORT
      LAYER M5 ;
        RECT  77.088 0 77.112 0.192 ;
    END
  END head_o[113]
  PIN head_o[114]
    DIRECTION OUTPUT ;
    USE SIGNAL ;
    PORT
      LAYER M3 ;
        RECT  77.724 0 77.742 0.144 ;
    END
  END head_o[114]
  PIN head_o[115]
    DIRECTION OUTPUT ;
    USE SIGNAL ;
    PORT
      LAYER M5 ;
        RECT  78.384 0 78.408 0.192 ;
    END
  END head_o[115]
  PIN head_o[116]
    DIRECTION OUTPUT ;
    USE SIGNAL ;
    PORT
      LAYER M3 ;
        RECT  79.02 0 79.038 0.144 ;
    END
  END head_o[116]
  PIN head_o[117]
    DIRECTION OUTPUT ;
    USE SIGNAL ;
    PORT
      LAYER M5 ;
        RECT  79.632 0 79.656 0.192 ;
    END
  END head_o[117]
  PIN head_o[118]
    DIRECTION OUTPUT ;
    USE SIGNAL ;
    PORT
      LAYER M3 ;
        RECT  80.316 0 80.334 0.144 ;
    END
  END head_o[118]
  PIN head_o[119]
    DIRECTION OUTPUT ;
    USE SIGNAL ;
    PORT
      LAYER M5 ;
        RECT  80.928 0 80.952 0.192 ;
    END
  END head_o[119]
  PIN head_o[11]
    DIRECTION OUTPUT ;
    USE SIGNAL ;
    PORT
      LAYER M5 ;
        RECT  11.664 0 11.688 0.192 ;
    END
  END head_o[11]
  PIN head_o[120]
    DIRECTION OUTPUT ;
    USE SIGNAL ;
    PORT
      LAYER M3 ;
        RECT  81.576 0 81.594 0.144 ;
    END
  END head_o[120]
  PIN head_o[121]
    DIRECTION OUTPUT ;
    USE SIGNAL ;
    PORT
      LAYER M5 ;
        RECT  82.224 0 82.248 0.192 ;
    END
  END head_o[121]
  PIN head_o[122]
    DIRECTION OUTPUT ;
    USE SIGNAL ;
    PORT
      LAYER M3 ;
        RECT  82.872 0 82.89 0.144 ;
    END
  END head_o[122]
  PIN head_o[123]
    DIRECTION OUTPUT ;
    USE SIGNAL ;
    PORT
      LAYER M5 ;
        RECT  83.52 0 83.544 0.192 ;
    END
  END head_o[123]
  PIN head_o[124]
    DIRECTION OUTPUT ;
    USE SIGNAL ;
    PORT
      LAYER M3 ;
        RECT  84.132 0 84.15 0.144 ;
    END
  END head_o[124]
  PIN head_o[125]
    DIRECTION OUTPUT ;
    USE SIGNAL ;
    PORT
      LAYER M5 ;
        RECT  84.768 0 84.792 0.192 ;
    END
  END head_o[125]
  PIN head_o[126]
    DIRECTION OUTPUT ;
    USE SIGNAL ;
    PORT
      LAYER M3 ;
        RECT  85.428 0 85.446 0.144 ;
    END
  END head_o[126]
  PIN head_o[127]
    DIRECTION OUTPUT ;
    USE SIGNAL ;
    PORT
      LAYER M5 ;
        RECT  86.064 0 86.088 0.192 ;
    END
  END head_o[127]
  PIN head_o[128]
    DIRECTION OUTPUT ;
    USE SIGNAL ;
    PORT
      LAYER M3 ;
        RECT  86.724 0 86.742 0.144 ;
    END
  END head_o[128]
  PIN head_o[129]
    DIRECTION OUTPUT ;
    USE SIGNAL ;
    PORT
      LAYER M5 ;
        RECT  87.36 0 87.384 0.192 ;
    END
  END head_o[129]
  PIN head_o[12]
    DIRECTION OUTPUT ;
    USE SIGNAL ;
    PORT
      LAYER M3 ;
        RECT  12.312 0 12.33 0.144 ;
    END
  END head_o[12]
  PIN head_o[130]
    DIRECTION OUTPUT ;
    USE SIGNAL ;
    PORT
      LAYER M3 ;
        RECT  87.984 0 88.002 0.144 ;
    END
  END head_o[130]
  PIN head_o[131]
    DIRECTION OUTPUT ;
    USE SIGNAL ;
    PORT
      LAYER M5 ;
        RECT  88.656 0 88.68 0.192 ;
    END
  END head_o[131]
  PIN head_o[132]
    DIRECTION OUTPUT ;
    USE SIGNAL ;
    PORT
      LAYER M3 ;
        RECT  89.28 0 89.298 0.144 ;
    END
  END head_o[132]
  PIN head_o[133]
    DIRECTION OUTPUT ;
    USE SIGNAL ;
    PORT
      LAYER M5 ;
        RECT  89.904 0 89.928 0.192 ;
    END
  END head_o[133]
  PIN head_o[134]
    DIRECTION OUTPUT ;
    USE SIGNAL ;
    PORT
      LAYER M3 ;
        RECT  90.576 0 90.594 0.144 ;
    END
  END head_o[134]
  PIN head_o[135]
    DIRECTION OUTPUT ;
    USE SIGNAL ;
    PORT
      LAYER M5 ;
        RECT  91.2 0 91.224 0.192 ;
    END
  END head_o[135]
  PIN head_o[136]
    DIRECTION OUTPUT ;
    USE SIGNAL ;
    PORT
      LAYER M3 ;
        RECT  91.836 0 91.854 0.144 ;
    END
  END head_o[136]
  PIN head_o[137]
    DIRECTION OUTPUT ;
    USE SIGNAL ;
    PORT
      LAYER M5 ;
        RECT  92.496 0 92.52 0.192 ;
    END
  END head_o[137]
  PIN head_o[138]
    DIRECTION OUTPUT ;
    USE SIGNAL ;
    PORT
      LAYER M3 ;
        RECT  93.132 0 93.15 0.144 ;
    END
  END head_o[138]
  PIN head_o[139]
    DIRECTION OUTPUT ;
    USE SIGNAL ;
    PORT
      LAYER M5 ;
        RECT  93.744 0 93.768 0.192 ;
    END
  END head_o[139]
  PIN head_o[13]
    DIRECTION OUTPUT ;
    USE SIGNAL ;
    PORT
      LAYER M5 ;
        RECT  12.96 0 12.984 0.192 ;
    END
  END head_o[13]
  PIN head_o[140]
    DIRECTION OUTPUT ;
    USE SIGNAL ;
    PORT
      LAYER M3 ;
        RECT  94.392 0 94.41 0.144 ;
    END
  END head_o[140]
  PIN head_o[141]
    DIRECTION OUTPUT ;
    USE SIGNAL ;
    PORT
      LAYER M5 ;
        RECT  95.04 0 95.064 0.192 ;
    END
  END head_o[141]
  PIN head_o[142]
    DIRECTION OUTPUT ;
    USE SIGNAL ;
    PORT
      LAYER M3 ;
        RECT  95.688 0 95.706 0.144 ;
    END
  END head_o[142]
  PIN head_o[143]
    DIRECTION OUTPUT ;
    USE SIGNAL ;
    PORT
      LAYER M5 ;
        RECT  96.336 0 96.36 0.192 ;
    END
  END head_o[143]
  PIN head_o[144]
    DIRECTION OUTPUT ;
    USE SIGNAL ;
    PORT
      LAYER M3 ;
        RECT  96.984 0 97.002 0.144 ;
    END
  END head_o[144]
  PIN head_o[145]
    DIRECTION OUTPUT ;
    USE SIGNAL ;
    PORT
      LAYER M5 ;
        RECT  97.632 0 97.656 0.192 ;
    END
  END head_o[145]
  PIN head_o[146]
    DIRECTION OUTPUT ;
    USE SIGNAL ;
    PORT
      LAYER M3 ;
        RECT  98.244 0 98.262 0.144 ;
    END
  END head_o[146]
  PIN head_o[147]
    DIRECTION OUTPUT ;
    USE SIGNAL ;
    PORT
      LAYER M5 ;
        RECT  98.88 0 98.904 0.192 ;
    END
  END head_o[147]
  PIN head_o[148]
    DIRECTION OUTPUT ;
    USE SIGNAL ;
    PORT
      LAYER M3 ;
        RECT  99.54 0 99.558 0.144 ;
    END
  END head_o[148]
  PIN head_o[149]
    DIRECTION OUTPUT ;
    USE SIGNAL ;
    PORT
      LAYER M5 ;
        RECT  100.176 0 100.2 0.192 ;
    END
  END head_o[149]
  PIN head_o[14]
    DIRECTION OUTPUT ;
    USE SIGNAL ;
    PORT
      LAYER M3 ;
        RECT  13.608 0 13.626 0.144 ;
    END
  END head_o[14]
  PIN head_o[150]
    DIRECTION OUTPUT ;
    USE SIGNAL ;
    PORT
      LAYER M3 ;
        RECT  100.836 0 100.854 0.144 ;
    END
  END head_o[150]
  PIN head_o[151]
    DIRECTION OUTPUT ;
    USE SIGNAL ;
    PORT
      LAYER M5 ;
        RECT  101.472 0 101.496 0.192 ;
    END
  END head_o[151]
  PIN head_o[152]
    DIRECTION OUTPUT ;
    USE SIGNAL ;
    PORT
      LAYER M3 ;
        RECT  102.096 0 102.114 0.144 ;
    END
  END head_o[152]
  PIN head_o[153]
    DIRECTION OUTPUT ;
    USE SIGNAL ;
    PORT
      LAYER M5 ;
        RECT  102.72 0 102.744 0.192 ;
    END
  END head_o[153]
  PIN head_o[154]
    DIRECTION OUTPUT ;
    USE SIGNAL ;
    PORT
      LAYER M3 ;
        RECT  103.392 0 103.41 0.144 ;
    END
  END head_o[154]
  PIN head_o[155]
    DIRECTION OUTPUT ;
    USE SIGNAL ;
    PORT
      LAYER M5 ;
        RECT  104.016 0 104.04 0.192 ;
    END
  END head_o[155]
  PIN head_o[156]
    DIRECTION OUTPUT ;
    USE SIGNAL ;
    PORT
      LAYER M3 ;
        RECT  104.652 0 104.67 0.144 ;
    END
  END head_o[156]
  PIN head_o[157]
    DIRECTION OUTPUT ;
    USE SIGNAL ;
    PORT
      LAYER M5 ;
        RECT  105.312 0 105.336 0.192 ;
    END
  END head_o[157]
  PIN head_o[158]
    DIRECTION OUTPUT ;
    USE SIGNAL ;
    PORT
      LAYER M3 ;
        RECT  105.948 0 105.966 0.144 ;
    END
  END head_o[158]
  PIN head_o[159]
    DIRECTION OUTPUT ;
    USE SIGNAL ;
    PORT
      LAYER M5 ;
        RECT  106.608 0 106.632 0.192 ;
    END
  END head_o[159]
  PIN head_o[15]
    DIRECTION OUTPUT ;
    USE SIGNAL ;
    PORT
      LAYER M5 ;
        RECT  14.256 0 14.28 0.192 ;
    END
  END head_o[15]
  PIN head_o[160]
    DIRECTION OUTPUT ;
    USE SIGNAL ;
    PORT
      LAYER M3 ;
        RECT  107.244 0 107.262 0.144 ;
    END
  END head_o[160]
  PIN head_o[161]
    DIRECTION OUTPUT ;
    USE SIGNAL ;
    PORT
      LAYER M5 ;
        RECT  107.856 0 107.88 0.192 ;
    END
  END head_o[161]
  PIN head_o[162]
    DIRECTION OUTPUT ;
    USE SIGNAL ;
    PORT
      LAYER M3 ;
        RECT  108.504 0 108.522 0.144 ;
    END
  END head_o[162]
  PIN head_o[163]
    DIRECTION OUTPUT ;
    USE SIGNAL ;
    PORT
      LAYER M5 ;
        RECT  109.152 0 109.176 0.192 ;
    END
  END head_o[163]
  PIN head_o[164]
    DIRECTION OUTPUT ;
    USE SIGNAL ;
    PORT
      LAYER M3 ;
        RECT  109.8 0 109.818 0.144 ;
    END
  END head_o[164]
  PIN head_o[165]
    DIRECTION OUTPUT ;
    USE SIGNAL ;
    PORT
      LAYER M5 ;
        RECT  110.448 0 110.472 0.192 ;
    END
  END head_o[165]
  PIN head_o[166]
    DIRECTION OUTPUT ;
    USE SIGNAL ;
    PORT
      LAYER M3 ;
        RECT  111.096 0 111.114 0.144 ;
    END
  END head_o[166]
  PIN head_o[167]
    DIRECTION OUTPUT ;
    USE SIGNAL ;
    PORT
      LAYER M5 ;
        RECT  111.696 0 111.72 0.192 ;
    END
  END head_o[167]
  PIN head_o[168]
    DIRECTION OUTPUT ;
    USE SIGNAL ;
    PORT
      LAYER M3 ;
        RECT  112.356 0 112.374 0.144 ;
    END
  END head_o[168]
  PIN head_o[169]
    DIRECTION OUTPUT ;
    USE SIGNAL ;
    PORT
      LAYER M5 ;
        RECT  112.992 0 113.016 0.192 ;
    END
  END head_o[169]
  PIN head_o[16]
    DIRECTION OUTPUT ;
    USE SIGNAL ;
    PORT
      LAYER M3 ;
        RECT  14.904 0 14.922 0.144 ;
    END
  END head_o[16]
  PIN head_o[170]
    DIRECTION OUTPUT ;
    USE SIGNAL ;
    PORT
      LAYER M3 ;
        RECT  113.652 0 113.67 0.144 ;
    END
  END head_o[170]
  PIN head_o[171]
    DIRECTION OUTPUT ;
    USE SIGNAL ;
    PORT
      LAYER M5 ;
        RECT  114.288 0 114.312 0.192 ;
    END
  END head_o[171]
  PIN head_o[172]
    DIRECTION OUTPUT ;
    USE SIGNAL ;
    PORT
      LAYER M3 ;
        RECT  114.912 0 114.93 0.144 ;
    END
  END head_o[172]
  PIN head_o[173]
    DIRECTION OUTPUT ;
    USE SIGNAL ;
    PORT
      LAYER M5 ;
        RECT  115.584 0 115.608 0.192 ;
    END
  END head_o[173]
  PIN head_o[174]
    DIRECTION OUTPUT ;
    USE SIGNAL ;
    PORT
      LAYER M3 ;
        RECT  116.208 0 116.226 0.144 ;
    END
  END head_o[174]
  PIN head_o[175]
    DIRECTION OUTPUT ;
    USE SIGNAL ;
    PORT
      LAYER M5 ;
        RECT  116.832 0 116.856 0.192 ;
    END
  END head_o[175]
  PIN head_o[176]
    DIRECTION OUTPUT ;
    USE SIGNAL ;
    PORT
      LAYER M3 ;
        RECT  117.504 0 117.522 0.144 ;
    END
  END head_o[176]
  PIN head_o[177]
    DIRECTION OUTPUT ;
    USE SIGNAL ;
    PORT
      LAYER M5 ;
        RECT  118.128 0 118.152 0.192 ;
    END
  END head_o[177]
  PIN head_o[178]
    DIRECTION OUTPUT ;
    USE SIGNAL ;
    PORT
      LAYER M3 ;
        RECT  118.764 0 118.782 0.144 ;
    END
  END head_o[178]
  PIN head_o[179]
    DIRECTION OUTPUT ;
    USE SIGNAL ;
    PORT
      LAYER M5 ;
        RECT  119.424 0 119.448 0.192 ;
    END
  END head_o[179]
  PIN head_o[17]
    DIRECTION OUTPUT ;
    USE SIGNAL ;
    PORT
      LAYER M5 ;
        RECT  15.552 0 15.576 0.192 ;
    END
  END head_o[17]
  PIN head_o[180]
    DIRECTION OUTPUT ;
    USE SIGNAL ;
    PORT
      LAYER M3 ;
        RECT  120.06 0 120.078 0.144 ;
    END
  END head_o[180]
  PIN head_o[181]
    DIRECTION OUTPUT ;
    USE SIGNAL ;
    PORT
      LAYER M5 ;
        RECT  120.672 0 120.696 0.192 ;
    END
  END head_o[181]
  PIN head_o[182]
    DIRECTION OUTPUT ;
    USE SIGNAL ;
    PORT
      LAYER M3 ;
        RECT  121.356 0 121.374 0.144 ;
    END
  END head_o[182]
  PIN head_o[183]
    DIRECTION OUTPUT ;
    USE SIGNAL ;
    PORT
      LAYER M5 ;
        RECT  121.968 0 121.992 0.192 ;
    END
  END head_o[183]
  PIN head_o[184]
    DIRECTION OUTPUT ;
    USE SIGNAL ;
    PORT
      LAYER M3 ;
        RECT  122.616 0 122.634 0.144 ;
    END
  END head_o[184]
  PIN head_o[185]
    DIRECTION OUTPUT ;
    USE SIGNAL ;
    PORT
      LAYER M5 ;
        RECT  123.264 0 123.288 0.192 ;
    END
  END head_o[185]
  PIN head_o[186]
    DIRECTION OUTPUT ;
    USE SIGNAL ;
    PORT
      LAYER M3 ;
        RECT  123.912 0 123.93 0.144 ;
    END
  END head_o[186]
  PIN head_o[187]
    DIRECTION OUTPUT ;
    USE SIGNAL ;
    PORT
      LAYER M5 ;
        RECT  124.56 0 124.584 0.192 ;
    END
  END head_o[187]
  PIN head_o[188]
    DIRECTION OUTPUT ;
    USE SIGNAL ;
    PORT
      LAYER M3 ;
        RECT  125.172 0 125.19 0.144 ;
    END
  END head_o[188]
  PIN head_o[189]
    DIRECTION OUTPUT ;
    USE SIGNAL ;
    PORT
      LAYER M5 ;
        RECT  125.808 0 125.832 0.192 ;
    END
  END head_o[189]
  PIN head_o[18]
    DIRECTION OUTPUT ;
    USE SIGNAL ;
    PORT
      LAYER M3 ;
        RECT  16.164 0 16.182 0.144 ;
    END
  END head_o[18]
  PIN head_o[190]
    DIRECTION OUTPUT ;
    USE SIGNAL ;
    PORT
      LAYER M3 ;
        RECT  126.468 0 126.486 0.144 ;
    END
  END head_o[190]
  PIN head_o[191]
    DIRECTION OUTPUT ;
    USE SIGNAL ;
    PORT
      LAYER M5 ;
        RECT  127.104 0 127.128 0.192 ;
    END
  END head_o[191]
  PIN head_o[192]
    DIRECTION OUTPUT ;
    USE SIGNAL ;
    PORT
      LAYER M3 ;
        RECT  127.764 0 127.782 0.144 ;
    END
  END head_o[192]
  PIN head_o[193]
    DIRECTION OUTPUT ;
    USE SIGNAL ;
    PORT
      LAYER M5 ;
        RECT  128.4 0 128.424 0.192 ;
    END
  END head_o[193]
  PIN head_o[194]
    DIRECTION OUTPUT ;
    USE SIGNAL ;
    PORT
      LAYER M3 ;
        RECT  129.024 0 129.042 0.144 ;
    END
  END head_o[194]
  PIN head_o[195]
    DIRECTION OUTPUT ;
    USE SIGNAL ;
    PORT
      LAYER M5 ;
        RECT  129.696 0 129.72 0.192 ;
    END
  END head_o[195]
  PIN head_o[196]
    DIRECTION OUTPUT ;
    USE SIGNAL ;
    PORT
      LAYER M3 ;
        RECT  130.32 0 130.338 0.144 ;
    END
  END head_o[196]
  PIN head_o[197]
    DIRECTION OUTPUT ;
    USE SIGNAL ;
    PORT
      LAYER M5 ;
        RECT  130.944 0 130.968 0.192 ;
    END
  END head_o[197]
  PIN head_o[198]
    DIRECTION OUTPUT ;
    USE SIGNAL ;
    PORT
      LAYER M3 ;
        RECT  131.616 0 131.634 0.144 ;
    END
  END head_o[198]
  PIN head_o[199]
    DIRECTION OUTPUT ;
    USE SIGNAL ;
    PORT
      LAYER M5 ;
        RECT  132.24 0 132.264 0.192 ;
    END
  END head_o[199]
  PIN head_o[19]
    DIRECTION OUTPUT ;
    USE SIGNAL ;
    PORT
      LAYER M5 ;
        RECT  16.8 0 16.824 0.192 ;
    END
  END head_o[19]
  PIN head_o[1]
    DIRECTION OUTPUT ;
    USE SIGNAL ;
    PORT
      LAYER M5 ;
        RECT  5.28 0 5.304 0.192 ;
    END
  END head_o[1]
  PIN head_o[200]
    DIRECTION OUTPUT ;
    USE SIGNAL ;
    PORT
      LAYER M3 ;
        RECT  132.876 0 132.894 0.144 ;
    END
  END head_o[200]
  PIN head_o[201]
    DIRECTION OUTPUT ;
    USE SIGNAL ;
    PORT
      LAYER M5 ;
        RECT  133.536 0 133.56 0.192 ;
    END
  END head_o[201]
  PIN head_o[202]
    DIRECTION OUTPUT ;
    USE SIGNAL ;
    PORT
      LAYER M3 ;
        RECT  134.172 0 134.19 0.144 ;
    END
  END head_o[202]
  PIN head_o[203]
    DIRECTION OUTPUT ;
    USE SIGNAL ;
    PORT
      LAYER M5 ;
        RECT  134.784 0 134.808 0.192 ;
    END
  END head_o[203]
  PIN head_o[204]
    DIRECTION OUTPUT ;
    USE SIGNAL ;
    PORT
      LAYER M3 ;
        RECT  135.432 0 135.45 0.144 ;
    END
  END head_o[204]
  PIN head_o[205]
    DIRECTION OUTPUT ;
    USE SIGNAL ;
    PORT
      LAYER M5 ;
        RECT  136.08 0 136.104 0.192 ;
    END
  END head_o[205]
  PIN head_o[206]
    DIRECTION OUTPUT ;
    USE SIGNAL ;
    PORT
      LAYER M3 ;
        RECT  136.728 0 136.746 0.144 ;
    END
  END head_o[206]
  PIN head_o[207]
    DIRECTION OUTPUT ;
    USE SIGNAL ;
    PORT
      LAYER M5 ;
        RECT  137.376 0 137.4 0.192 ;
    END
  END head_o[207]
  PIN head_o[208]
    DIRECTION OUTPUT ;
    USE SIGNAL ;
    PORT
      LAYER M3 ;
        RECT  138.024 0 138.042 0.144 ;
    END
  END head_o[208]
  PIN head_o[209]
    DIRECTION OUTPUT ;
    USE SIGNAL ;
    PORT
      LAYER M5 ;
        RECT  138.672 0 138.696 0.192 ;
    END
  END head_o[209]
  PIN head_o[20]
    DIRECTION OUTPUT ;
    USE SIGNAL ;
    PORT
      LAYER M3 ;
        RECT  17.46 0 17.478 0.144 ;
    END
  END head_o[20]
  PIN head_o[210]
    DIRECTION OUTPUT ;
    USE SIGNAL ;
    PORT
      LAYER M3 ;
        RECT  139.284 0 139.302 0.144 ;
    END
  END head_o[210]
  PIN head_o[211]
    DIRECTION OUTPUT ;
    USE SIGNAL ;
    PORT
      LAYER M5 ;
        RECT  139.92 0 139.944 0.192 ;
    END
  END head_o[211]
  PIN head_o[212]
    DIRECTION OUTPUT ;
    USE SIGNAL ;
    PORT
      LAYER M3 ;
        RECT  140.58 0 140.598 0.144 ;
    END
  END head_o[212]
  PIN head_o[213]
    DIRECTION OUTPUT ;
    USE SIGNAL ;
    PORT
      LAYER M5 ;
        RECT  141.216 0 141.24 0.192 ;
    END
  END head_o[213]
  PIN head_o[214]
    DIRECTION OUTPUT ;
    USE SIGNAL ;
    PORT
      LAYER M3 ;
        RECT  141.876 0 141.894 0.144 ;
    END
  END head_o[214]
  PIN head_o[215]
    DIRECTION OUTPUT ;
    USE SIGNAL ;
    PORT
      LAYER M5 ;
        RECT  142.512 0 142.536 0.192 ;
    END
  END head_o[215]
  PIN head_o[216]
    DIRECTION OUTPUT ;
    USE SIGNAL ;
    PORT
      LAYER M3 ;
        RECT  143.136 0 143.154 0.144 ;
    END
  END head_o[216]
  PIN head_o[217]
    DIRECTION OUTPUT ;
    USE SIGNAL ;
    PORT
      LAYER M5 ;
        RECT  143.76 0 143.784 0.192 ;
    END
  END head_o[217]
  PIN head_o[218]
    DIRECTION OUTPUT ;
    USE SIGNAL ;
    PORT
      LAYER M3 ;
        RECT  144.432 0 144.45 0.144 ;
    END
  END head_o[218]
  PIN head_o[219]
    DIRECTION OUTPUT ;
    USE SIGNAL ;
    PORT
      LAYER M5 ;
        RECT  145.056 0 145.08 0.192 ;
    END
  END head_o[219]
  PIN head_o[21]
    DIRECTION OUTPUT ;
    USE SIGNAL ;
    PORT
      LAYER M5 ;
        RECT  18.096 0 18.12 0.192 ;
    END
  END head_o[21]
  PIN head_o[220]
    DIRECTION OUTPUT ;
    USE SIGNAL ;
    PORT
      LAYER M3 ;
        RECT  145.692 0 145.71 0.144 ;
    END
  END head_o[220]
  PIN head_o[221]
    DIRECTION OUTPUT ;
    USE SIGNAL ;
    PORT
      LAYER M5 ;
        RECT  146.352 0 146.376 0.192 ;
    END
  END head_o[221]
  PIN head_o[222]
    DIRECTION OUTPUT ;
    USE SIGNAL ;
    PORT
      LAYER M3 ;
        RECT  146.988 0 147.006 0.144 ;
    END
  END head_o[222]
  PIN head_o[223]
    DIRECTION OUTPUT ;
    USE SIGNAL ;
    PORT
      LAYER M5 ;
        RECT  147.648 0 147.672 0.192 ;
    END
  END head_o[223]
  PIN head_o[224]
    DIRECTION OUTPUT ;
    USE SIGNAL ;
    PORT
      LAYER M3 ;
        RECT  148.284 0 148.302 0.144 ;
    END
  END head_o[224]
  PIN head_o[225]
    DIRECTION OUTPUT ;
    USE SIGNAL ;
    PORT
      LAYER M5 ;
        RECT  148.896 0 148.92 0.192 ;
    END
  END head_o[225]
  PIN head_o[226]
    DIRECTION OUTPUT ;
    USE SIGNAL ;
    PORT
      LAYER M3 ;
        RECT  149.544 0 149.562 0.144 ;
    END
  END head_o[226]
  PIN head_o[227]
    DIRECTION OUTPUT ;
    USE SIGNAL ;
    PORT
      LAYER M5 ;
        RECT  150.192 0 150.216 0.192 ;
    END
  END head_o[227]
  PIN head_o[228]
    DIRECTION OUTPUT ;
    USE SIGNAL ;
    PORT
      LAYER M3 ;
        RECT  150.84 0 150.858 0.144 ;
    END
  END head_o[228]
  PIN head_o[229]
    DIRECTION OUTPUT ;
    USE SIGNAL ;
    PORT
      LAYER M5 ;
        RECT  151.488 0 151.512 0.192 ;
    END
  END head_o[229]
  PIN head_o[22]
    DIRECTION OUTPUT ;
    USE SIGNAL ;
    PORT
      LAYER M3 ;
        RECT  18.756 0 18.774 0.144 ;
    END
  END head_o[22]
  PIN head_o[230]
    DIRECTION OUTPUT ;
    USE SIGNAL ;
    PORT
      LAYER M3 ;
        RECT  152.136 0 152.154 0.144 ;
    END
  END head_o[230]
  PIN head_o[231]
    DIRECTION OUTPUT ;
    USE SIGNAL ;
    PORT
      LAYER M5 ;
        RECT  152.736 0 152.76 0.192 ;
    END
  END head_o[231]
  PIN head_o[232]
    DIRECTION OUTPUT ;
    USE SIGNAL ;
    PORT
      LAYER M3 ;
        RECT  153.396 0 153.414 0.144 ;
    END
  END head_o[232]
  PIN head_o[233]
    DIRECTION OUTPUT ;
    USE SIGNAL ;
    PORT
      LAYER M5 ;
        RECT  154.032 0 154.056 0.192 ;
    END
  END head_o[233]
  PIN head_o[234]
    DIRECTION OUTPUT ;
    USE SIGNAL ;
    PORT
      LAYER M3 ;
        RECT  154.692 0 154.71 0.144 ;
    END
  END head_o[234]
  PIN head_o[235]
    DIRECTION OUTPUT ;
    USE SIGNAL ;
    PORT
      LAYER M5 ;
        RECT  155.328 0 155.352 0.192 ;
    END
  END head_o[235]
  PIN head_o[236]
    DIRECTION OUTPUT ;
    USE SIGNAL ;
    PORT
      LAYER M3 ;
        RECT  155.952 0 155.97 0.144 ;
    END
  END head_o[236]
  PIN head_o[237]
    DIRECTION OUTPUT ;
    USE SIGNAL ;
    PORT
      LAYER M5 ;
        RECT  156.624 0 156.648 0.192 ;
    END
  END head_o[237]
  PIN head_o[238]
    DIRECTION OUTPUT ;
    USE SIGNAL ;
    PORT
      LAYER M3 ;
        RECT  157.248 0 157.266 0.144 ;
    END
  END head_o[238]
  PIN head_o[239]
    DIRECTION OUTPUT ;
    USE SIGNAL ;
    PORT
      LAYER M5 ;
        RECT  157.872 0 157.896 0.192 ;
    END
  END head_o[239]
  PIN head_o[23]
    DIRECTION OUTPUT ;
    USE SIGNAL ;
    PORT
      LAYER M5 ;
        RECT  19.392 0 19.416 0.192 ;
    END
  END head_o[23]
  PIN head_o[240]
    DIRECTION OUTPUT ;
    USE SIGNAL ;
    PORT
      LAYER M3 ;
        RECT  158.544 0 158.562 0.144 ;
    END
  END head_o[240]
  PIN head_o[241]
    DIRECTION OUTPUT ;
    USE SIGNAL ;
    PORT
      LAYER M5 ;
        RECT  159.168 0 159.192 0.192 ;
    END
  END head_o[241]
  PIN head_o[242]
    DIRECTION OUTPUT ;
    USE SIGNAL ;
    PORT
      LAYER M3 ;
        RECT  159.804 0 159.822 0.144 ;
    END
  END head_o[242]
  PIN head_o[243]
    DIRECTION OUTPUT ;
    USE SIGNAL ;
    PORT
      LAYER M5 ;
        RECT  160.464 0 160.488 0.192 ;
    END
  END head_o[243]
  PIN head_o[244]
    DIRECTION OUTPUT ;
    USE SIGNAL ;
    PORT
      LAYER M3 ;
        RECT  161.1 0 161.118 0.144 ;
    END
  END head_o[244]
  PIN head_o[245]
    DIRECTION OUTPUT ;
    USE SIGNAL ;
    PORT
      LAYER M5 ;
        RECT  161.712 0 161.736 0.192 ;
    END
  END head_o[245]
  PIN head_o[246]
    DIRECTION OUTPUT ;
    USE SIGNAL ;
    PORT
      LAYER M3 ;
        RECT  162.396 0 162.414 0.144 ;
    END
  END head_o[246]
  PIN head_o[247]
    DIRECTION OUTPUT ;
    USE SIGNAL ;
    PORT
      LAYER M5 ;
        RECT  163.008 0 163.032 0.192 ;
    END
  END head_o[247]
  PIN head_o[248]
    DIRECTION OUTPUT ;
    USE SIGNAL ;
    PORT
      LAYER M3 ;
        RECT  163.656 0 163.674 0.144 ;
    END
  END head_o[248]
  PIN head_o[249]
    DIRECTION OUTPUT ;
    USE SIGNAL ;
    PORT
      LAYER M5 ;
        RECT  164.304 0 164.328 0.192 ;
    END
  END head_o[249]
  PIN head_o[24]
    DIRECTION OUTPUT ;
    USE SIGNAL ;
    PORT
      LAYER M3 ;
        RECT  20.016 0 20.034 0.144 ;
    END
  END head_o[24]
  PIN head_o[250]
    DIRECTION OUTPUT ;
    USE SIGNAL ;
    PORT
      LAYER M3 ;
        RECT  164.952 0 164.97 0.144 ;
    END
  END head_o[250]
  PIN head_o[251]
    DIRECTION OUTPUT ;
    USE SIGNAL ;
    PORT
      LAYER M5 ;
        RECT  165.6 0 165.624 0.192 ;
    END
  END head_o[251]
  PIN head_o[252]
    DIRECTION OUTPUT ;
    USE SIGNAL ;
    PORT
      LAYER M3 ;
        RECT  166.212 0 166.23 0.144 ;
    END
  END head_o[252]
  PIN head_o[253]
    DIRECTION OUTPUT ;
    USE SIGNAL ;
    PORT
      LAYER M5 ;
        RECT  166.848 0 166.872 0.192 ;
    END
  END head_o[253]
  PIN head_o[254]
    DIRECTION OUTPUT ;
    USE SIGNAL ;
    PORT
      LAYER M3 ;
        RECT  167.508 0 167.526 0.144 ;
    END
  END head_o[254]
  PIN head_o[255]
    DIRECTION OUTPUT ;
    USE SIGNAL ;
    PORT
      LAYER M5 ;
        RECT  168.144 0 168.168 0.192 ;
    END
  END head_o[255]
  PIN head_o[25]
    DIRECTION OUTPUT ;
    USE SIGNAL ;
    PORT
      LAYER M5 ;
        RECT  20.64 0 20.664 0.192 ;
    END
  END head_o[25]
  PIN head_o[26]
    DIRECTION OUTPUT ;
    USE SIGNAL ;
    PORT
      LAYER M3 ;
        RECT  21.312 0 21.33 0.144 ;
    END
  END head_o[26]
  PIN head_o[27]
    DIRECTION OUTPUT ;
    USE SIGNAL ;
    PORT
      LAYER M5 ;
        RECT  21.936 0 21.96 0.192 ;
    END
  END head_o[27]
  PIN head_o[28]
    DIRECTION OUTPUT ;
    USE SIGNAL ;
    PORT
      LAYER M3 ;
        RECT  22.572 0 22.59 0.144 ;
    END
  END head_o[28]
  PIN head_o[29]
    DIRECTION OUTPUT ;
    USE SIGNAL ;
    PORT
      LAYER M5 ;
        RECT  23.232 0 23.256 0.192 ;
    END
  END head_o[29]
  PIN head_o[2]
    DIRECTION OUTPUT ;
    USE SIGNAL ;
    PORT
      LAYER M3 ;
        RECT  5.904 0 5.922 0.144 ;
    END
  END head_o[2]
  PIN head_o[30]
    DIRECTION OUTPUT ;
    USE SIGNAL ;
    PORT
      LAYER M3 ;
        RECT  23.868 0 23.886 0.144 ;
    END
  END head_o[30]
  PIN head_o[31]
    DIRECTION OUTPUT ;
    USE SIGNAL ;
    PORT
      LAYER M5 ;
        RECT  24.528 0 24.552 0.192 ;
    END
  END head_o[31]
  PIN head_o[32]
    DIRECTION OUTPUT ;
    USE SIGNAL ;
    PORT
      LAYER M3 ;
        RECT  25.164 0 25.182 0.144 ;
    END
  END head_o[32]
  PIN head_o[33]
    DIRECTION OUTPUT ;
    USE SIGNAL ;
    PORT
      LAYER M5 ;
        RECT  25.776 0 25.8 0.192 ;
    END
  END head_o[33]
  PIN head_o[34]
    DIRECTION OUTPUT ;
    USE SIGNAL ;
    PORT
      LAYER M3 ;
        RECT  26.424 0 26.442 0.144 ;
    END
  END head_o[34]
  PIN head_o[35]
    DIRECTION OUTPUT ;
    USE SIGNAL ;
    PORT
      LAYER M5 ;
        RECT  27.072 0 27.096 0.192 ;
    END
  END head_o[35]
  PIN head_o[36]
    DIRECTION OUTPUT ;
    USE SIGNAL ;
    PORT
      LAYER M3 ;
        RECT  27.72 0 27.738 0.144 ;
    END
  END head_o[36]
  PIN head_o[37]
    DIRECTION OUTPUT ;
    USE SIGNAL ;
    PORT
      LAYER M5 ;
        RECT  28.368 0 28.392 0.192 ;
    END
  END head_o[37]
  PIN head_o[38]
    DIRECTION OUTPUT ;
    USE SIGNAL ;
    PORT
      LAYER M3 ;
        RECT  29.016 0 29.034 0.144 ;
    END
  END head_o[38]
  PIN head_o[39]
    DIRECTION OUTPUT ;
    USE SIGNAL ;
    PORT
      LAYER M5 ;
        RECT  29.616 0 29.64 0.192 ;
    END
  END head_o[39]
  PIN head_o[3]
    DIRECTION OUTPUT ;
    USE SIGNAL ;
    PORT
      LAYER M5 ;
        RECT  6.576 0 6.6 0.192 ;
    END
  END head_o[3]
  PIN head_o[40]
    DIRECTION OUTPUT ;
    USE SIGNAL ;
    PORT
      LAYER M3 ;
        RECT  30.276 0 30.294 0.144 ;
    END
  END head_o[40]
  PIN head_o[41]
    DIRECTION OUTPUT ;
    USE SIGNAL ;
    PORT
      LAYER M5 ;
        RECT  30.912 0 30.936 0.192 ;
    END
  END head_o[41]
  PIN head_o[42]
    DIRECTION OUTPUT ;
    USE SIGNAL ;
    PORT
      LAYER M3 ;
        RECT  31.572 0 31.59 0.144 ;
    END
  END head_o[42]
  PIN head_o[43]
    DIRECTION OUTPUT ;
    USE SIGNAL ;
    PORT
      LAYER M5 ;
        RECT  32.208 0 32.232 0.192 ;
    END
  END head_o[43]
  PIN head_o[44]
    DIRECTION OUTPUT ;
    USE SIGNAL ;
    PORT
      LAYER M3 ;
        RECT  32.832 0 32.85 0.144 ;
    END
  END head_o[44]
  PIN head_o[45]
    DIRECTION OUTPUT ;
    USE SIGNAL ;
    PORT
      LAYER M5 ;
        RECT  33.504 0 33.528 0.192 ;
    END
  END head_o[45]
  PIN head_o[46]
    DIRECTION OUTPUT ;
    USE SIGNAL ;
    PORT
      LAYER M3 ;
        RECT  34.128 0 34.146 0.144 ;
    END
  END head_o[46]
  PIN head_o[47]
    DIRECTION OUTPUT ;
    USE SIGNAL ;
    PORT
      LAYER M5 ;
        RECT  34.752 0 34.776 0.192 ;
    END
  END head_o[47]
  PIN head_o[48]
    DIRECTION OUTPUT ;
    USE SIGNAL ;
    PORT
      LAYER M3 ;
        RECT  35.424 0 35.442 0.144 ;
    END
  END head_o[48]
  PIN head_o[49]
    DIRECTION OUTPUT ;
    USE SIGNAL ;
    PORT
      LAYER M5 ;
        RECT  36.048 0 36.072 0.192 ;
    END
  END head_o[49]
  PIN head_o[4]
    DIRECTION OUTPUT ;
    USE SIGNAL ;
    PORT
      LAYER M3 ;
        RECT  7.2 0 7.218 0.144 ;
    END
  END head_o[4]
  PIN head_o[50]
    DIRECTION OUTPUT ;
    USE SIGNAL ;
    PORT
      LAYER M3 ;
        RECT  36.684 0 36.702 0.144 ;
    END
  END head_o[50]
  PIN head_o[51]
    DIRECTION OUTPUT ;
    USE SIGNAL ;
    PORT
      LAYER M5 ;
        RECT  37.344 0 37.368 0.192 ;
    END
  END head_o[51]
  PIN head_o[52]
    DIRECTION OUTPUT ;
    USE SIGNAL ;
    PORT
      LAYER M3 ;
        RECT  37.98 0 37.998 0.144 ;
    END
  END head_o[52]
  PIN head_o[53]
    DIRECTION OUTPUT ;
    USE SIGNAL ;
    PORT
      LAYER M5 ;
        RECT  38.592 0 38.616 0.192 ;
    END
  END head_o[53]
  PIN head_o[54]
    DIRECTION OUTPUT ;
    USE SIGNAL ;
    PORT
      LAYER M3 ;
        RECT  39.276 0 39.294 0.144 ;
    END
  END head_o[54]
  PIN head_o[55]
    DIRECTION OUTPUT ;
    USE SIGNAL ;
    PORT
      LAYER M5 ;
        RECT  39.888 0 39.912 0.192 ;
    END
  END head_o[55]
  PIN head_o[56]
    DIRECTION OUTPUT ;
    USE SIGNAL ;
    PORT
      LAYER M3 ;
        RECT  40.536 0 40.554 0.144 ;
    END
  END head_o[56]
  PIN head_o[57]
    DIRECTION OUTPUT ;
    USE SIGNAL ;
    PORT
      LAYER M5 ;
        RECT  41.184 0 41.208 0.192 ;
    END
  END head_o[57]
  PIN head_o[58]
    DIRECTION OUTPUT ;
    USE SIGNAL ;
    PORT
      LAYER M3 ;
        RECT  41.832 0 41.85 0.144 ;
    END
  END head_o[58]
  PIN head_o[59]
    DIRECTION OUTPUT ;
    USE SIGNAL ;
    PORT
      LAYER M5 ;
        RECT  42.48 0 42.504 0.192 ;
    END
  END head_o[59]
  PIN head_o[5]
    DIRECTION OUTPUT ;
    USE SIGNAL ;
    PORT
      LAYER M5 ;
        RECT  7.824 0 7.848 0.192 ;
    END
  END head_o[5]
  PIN head_o[60]
    DIRECTION OUTPUT ;
    USE SIGNAL ;
    PORT
      LAYER M3 ;
        RECT  43.092 0 43.11 0.144 ;
    END
  END head_o[60]
  PIN head_o[61]
    DIRECTION OUTPUT ;
    USE SIGNAL ;
    PORT
      LAYER M5 ;
        RECT  43.728 0 43.752 0.192 ;
    END
  END head_o[61]
  PIN head_o[62]
    DIRECTION OUTPUT ;
    USE SIGNAL ;
    PORT
      LAYER M3 ;
        RECT  44.388 0 44.406 0.144 ;
    END
  END head_o[62]
  PIN head_o[63]
    DIRECTION OUTPUT ;
    USE SIGNAL ;
    PORT
      LAYER M5 ;
        RECT  45.024 0 45.048 0.192 ;
    END
  END head_o[63]
  PIN head_o[64]
    DIRECTION OUTPUT ;
    USE SIGNAL ;
    PORT
      LAYER M3 ;
        RECT  45.684 0 45.702 0.144 ;
    END
  END head_o[64]
  PIN head_o[65]
    DIRECTION OUTPUT ;
    USE SIGNAL ;
    PORT
      LAYER M5 ;
        RECT  46.32 0 46.344 0.192 ;
    END
  END head_o[65]
  PIN head_o[66]
    DIRECTION OUTPUT ;
    USE SIGNAL ;
    PORT
      LAYER M3 ;
        RECT  46.944 0 46.962 0.144 ;
    END
  END head_o[66]
  PIN head_o[67]
    DIRECTION OUTPUT ;
    USE SIGNAL ;
    PORT
      LAYER M5 ;
        RECT  47.616 0 47.64 0.192 ;
    END
  END head_o[67]
  PIN head_o[68]
    DIRECTION OUTPUT ;
    USE SIGNAL ;
    PORT
      LAYER M3 ;
        RECT  48.24 0 48.258 0.144 ;
    END
  END head_o[68]
  PIN head_o[69]
    DIRECTION OUTPUT ;
    USE SIGNAL ;
    PORT
      LAYER M5 ;
        RECT  48.864 0 48.888 0.192 ;
    END
  END head_o[69]
  PIN head_o[6]
    DIRECTION OUTPUT ;
    USE SIGNAL ;
    PORT
      LAYER M3 ;
        RECT  8.496 0 8.514 0.144 ;
    END
  END head_o[6]
  PIN head_o[70]
    DIRECTION OUTPUT ;
    USE SIGNAL ;
    PORT
      LAYER M3 ;
        RECT  49.536 0 49.554 0.144 ;
    END
  END head_o[70]
  PIN head_o[71]
    DIRECTION OUTPUT ;
    USE SIGNAL ;
    PORT
      LAYER M5 ;
        RECT  50.16 0 50.184 0.192 ;
    END
  END head_o[71]
  PIN head_o[72]
    DIRECTION OUTPUT ;
    USE SIGNAL ;
    PORT
      LAYER M3 ;
        RECT  50.796 0 50.814 0.144 ;
    END
  END head_o[72]
  PIN head_o[73]
    DIRECTION OUTPUT ;
    USE SIGNAL ;
    PORT
      LAYER M5 ;
        RECT  51.456 0 51.48 0.192 ;
    END
  END head_o[73]
  PIN head_o[74]
    DIRECTION OUTPUT ;
    USE SIGNAL ;
    PORT
      LAYER M3 ;
        RECT  52.092 0 52.11 0.144 ;
    END
  END head_o[74]
  PIN head_o[75]
    DIRECTION OUTPUT ;
    USE SIGNAL ;
    PORT
      LAYER M5 ;
        RECT  52.704 0 52.728 0.192 ;
    END
  END head_o[75]
  PIN head_o[76]
    DIRECTION OUTPUT ;
    USE SIGNAL ;
    PORT
      LAYER M3 ;
        RECT  53.352 0 53.37 0.144 ;
    END
  END head_o[76]
  PIN head_o[77]
    DIRECTION OUTPUT ;
    USE SIGNAL ;
    PORT
      LAYER M5 ;
        RECT  54 0 54.024 0.192 ;
    END
  END head_o[77]
  PIN head_o[78]
    DIRECTION OUTPUT ;
    USE SIGNAL ;
    PORT
      LAYER M3 ;
        RECT  54.648 0 54.666 0.144 ;
    END
  END head_o[78]
  PIN head_o[79]
    DIRECTION OUTPUT ;
    USE SIGNAL ;
    PORT
      LAYER M5 ;
        RECT  55.296 0 55.32 0.192 ;
    END
  END head_o[79]
  PIN head_o[7]
    DIRECTION OUTPUT ;
    USE SIGNAL ;
    PORT
      LAYER M5 ;
        RECT  9.12 0 9.144 0.192 ;
    END
  END head_o[7]
  PIN head_o[80]
    DIRECTION OUTPUT ;
    USE SIGNAL ;
    PORT
      LAYER M3 ;
        RECT  55.944 0 55.962 0.144 ;
    END
  END head_o[80]
  PIN head_o[81]
    DIRECTION OUTPUT ;
    USE SIGNAL ;
    PORT
      LAYER M5 ;
        RECT  56.592 0 56.616 0.192 ;
    END
  END head_o[81]
  PIN head_o[82]
    DIRECTION OUTPUT ;
    USE SIGNAL ;
    PORT
      LAYER M3 ;
        RECT  57.204 0 57.222 0.144 ;
    END
  END head_o[82]
  PIN head_o[83]
    DIRECTION OUTPUT ;
    USE SIGNAL ;
    PORT
      LAYER M5 ;
        RECT  57.84 0 57.864 0.192 ;
    END
  END head_o[83]
  PIN head_o[84]
    DIRECTION OUTPUT ;
    USE SIGNAL ;
    PORT
      LAYER M3 ;
        RECT  58.5 0 58.518 0.144 ;
    END
  END head_o[84]
  PIN head_o[85]
    DIRECTION OUTPUT ;
    USE SIGNAL ;
    PORT
      LAYER M5 ;
        RECT  59.136 0 59.16 0.192 ;
    END
  END head_o[85]
  PIN head_o[86]
    DIRECTION OUTPUT ;
    USE SIGNAL ;
    PORT
      LAYER M3 ;
        RECT  59.796 0 59.814 0.144 ;
    END
  END head_o[86]
  PIN head_o[87]
    DIRECTION OUTPUT ;
    USE SIGNAL ;
    PORT
      LAYER M5 ;
        RECT  60.432 0 60.456 0.192 ;
    END
  END head_o[87]
  PIN head_o[88]
    DIRECTION OUTPUT ;
    USE SIGNAL ;
    PORT
      LAYER M3 ;
        RECT  61.056 0 61.074 0.144 ;
    END
  END head_o[88]
  PIN head_o[89]
    DIRECTION OUTPUT ;
    USE SIGNAL ;
    PORT
      LAYER M5 ;
        RECT  61.68 0 61.704 0.192 ;
    END
  END head_o[89]
  PIN head_o[8]
    DIRECTION OUTPUT ;
    USE SIGNAL ;
    PORT
      LAYER M3 ;
        RECT  9.756 0 9.774 0.144 ;
    END
  END head_o[8]
  PIN head_o[90]
    DIRECTION OUTPUT ;
    USE SIGNAL ;
    PORT
      LAYER M3 ;
        RECT  62.352 0 62.37 0.144 ;
    END
  END head_o[90]
  PIN head_o[91]
    DIRECTION OUTPUT ;
    USE SIGNAL ;
    PORT
      LAYER M5 ;
        RECT  62.976 0 63 0.192 ;
    END
  END head_o[91]
  PIN head_o[92]
    DIRECTION OUTPUT ;
    USE SIGNAL ;
    PORT
      LAYER M3 ;
        RECT  63.612 0 63.63 0.144 ;
    END
  END head_o[92]
  PIN head_o[93]
    DIRECTION OUTPUT ;
    USE SIGNAL ;
    PORT
      LAYER M5 ;
        RECT  64.272 0 64.296 0.192 ;
    END
  END head_o[93]
  PIN head_o[94]
    DIRECTION OUTPUT ;
    USE SIGNAL ;
    PORT
      LAYER M3 ;
        RECT  64.908 0 64.926 0.144 ;
    END
  END head_o[94]
  PIN head_o[95]
    DIRECTION OUTPUT ;
    USE SIGNAL ;
    PORT
      LAYER M5 ;
        RECT  65.568 0 65.592 0.192 ;
    END
  END head_o[95]
  PIN head_o[96]
    DIRECTION OUTPUT ;
    USE SIGNAL ;
    PORT
      LAYER M3 ;
        RECT  66.204 0 66.222 0.144 ;
    END
  END head_o[96]
  PIN head_o[97]
    DIRECTION OUTPUT ;
    USE SIGNAL ;
    PORT
      LAYER M5 ;
        RECT  66.816 0 66.84 0.192 ;
    END
  END head_o[97]
  PIN head_o[98]
    DIRECTION OUTPUT ;
    USE SIGNAL ;
    PORT
      LAYER M3 ;
        RECT  67.464 0 67.482 0.144 ;
    END
  END head_o[98]
  PIN head_o[99]
    DIRECTION OUTPUT ;
    USE SIGNAL ;
    PORT
      LAYER M5 ;
        RECT  68.112 0 68.136 0.192 ;
    END
  END head_o[99]
  PIN head_o[9]
    DIRECTION OUTPUT ;
    USE SIGNAL ;
    PORT
      LAYER M5 ;
        RECT  10.416 0 10.44 0.192 ;
    END
  END head_o[9]
  PIN hv_o
    DIRECTION OUTPUT ;
    USE SIGNAL ;
    PORT
      LAYER M3 ;
        RECT  167.544 97.056 167.562 97.2 ;
    END
  END hv_o
  PIN ovf_o
    DIRECTION OUTPUT ;
    USE SIGNAL ;
    PORT
      LAYER M5 ;
        RECT  168.144 97.008 168.168 97.2 ;
    END
  END ovf_o
  PIN pop_i
    DIRECTION INPUT ;
    USE SIGNAL ;
    PORT
      LAYER M5 ;
        RECT  5.232 97.008 5.256 97.2 ;
    END
  END pop_i
  PIN push_i
    DIRECTION INPUT ;
    USE SIGNAL ;
    PORT
      LAYER M3 ;
        RECT  5.868 97.056 5.886 97.2 ;
    END
  END push_i
  PIN srs
    DIRECTION INPUT ;
    USE SIGNAL ;
    PORT
      LAYER M3 ;
        RECT  4.608 97.056 4.626 97.2 ;
    END
  END srs
  PIN VDD
    DIRECTION INOUT ;
    USE POWER ;
    PORT
      LAYER M5 ;
        RECT  169.992 2.151 170.112 95.049 ;
        RECT  164.592 2.151 164.712 95.049 ;
        RECT  159.192 2.151 159.312 95.049 ;
        RECT  153.792 2.151 153.912 95.049 ;
        RECT  148.392 2.151 148.512 95.049 ;
        RECT  142.992 2.151 143.112 95.049 ;
        RECT  137.592 2.151 137.712 95.049 ;
        RECT  132.192 2.151 132.312 95.049 ;
        RECT  126.792 2.151 126.912 95.049 ;
        RECT  121.392 2.151 121.512 95.049 ;
        RECT  115.992 2.151 116.112 95.049 ;
        RECT  110.592 2.151 110.712 95.049 ;
        RECT  105.192 2.151 105.312 95.049 ;
        RECT  99.792 2.151 99.912 95.049 ;
        RECT  94.392 2.151 94.512 95.049 ;
        RECT  88.992 2.151 89.112 95.049 ;
        RECT  83.592 2.151 83.712 95.049 ;
        RECT  78.192 2.151 78.312 95.049 ;
        RECT  72.792 2.151 72.912 95.049 ;
        RECT  67.392 2.151 67.512 95.049 ;
        RECT  61.992 2.151 62.112 95.049 ;
        RECT  56.592 2.151 56.712 95.049 ;
        RECT  51.192 2.151 51.312 95.049 ;
        RECT  45.792 2.151 45.912 95.049 ;
        RECT  40.392 2.151 40.512 95.049 ;
        RECT  34.992 2.151 35.112 95.049 ;
        RECT  29.592 2.151 29.712 95.049 ;
        RECT  24.192 2.151 24.312 95.049 ;
        RECT  18.792 2.151 18.912 95.049 ;
        RECT  13.392 2.151 13.512 95.049 ;
        RECT  7.992 2.151 8.112 95.049 ;
        RECT  2.592 2.151 2.712 95.049 ;
    END
  END VDD
  PIN VSS
    DIRECTION INOUT ;
    USE GROUND ;
    PORT
      LAYER M5 ;
        RECT  169.8 2.137 169.92 95.063 ;
        RECT  164.4 2.137 164.52 95.063 ;
        RECT  159 2.137 159.12 95.063 ;
        RECT  153.6 2.137 153.72 95.063 ;
        RECT  148.2 2.137 148.32 95.063 ;
        RECT  142.8 2.137 142.92 95.063 ;
        RECT  137.4 2.137 137.52 95.063 ;
        RECT  132 2.137 132.12 95.063 ;
        RECT  126.6 2.137 126.72 95.063 ;
        RECT  121.2 2.137 121.32 95.063 ;
        RECT  115.8 2.137 115.92 95.063 ;
        RECT  110.4 2.137 110.52 95.063 ;
        RECT  105 2.137 105.12 95.063 ;
        RECT  99.6 2.137 99.72 95.063 ;
        RECT  94.2 2.137 94.32 95.063 ;
        RECT  88.8 2.137 88.92 95.063 ;
        RECT  83.4 2.137 83.52 95.063 ;
        RECT  78 2.137 78.12 95.063 ;
        RECT  72.6 2.137 72.72 95.063 ;
        RECT  67.2 2.137 67.32 95.063 ;
        RECT  61.8 2.137 61.92 95.063 ;
        RECT  56.4 2.137 56.52 95.063 ;
        RECT  51 2.137 51.12 95.063 ;
        RECT  45.6 2.137 45.72 95.063 ;
        RECT  40.2 2.137 40.32 95.063 ;
        RECT  34.8 2.137 34.92 95.063 ;
        RECT  29.4 2.137 29.52 95.063 ;
        RECT  24 2.137 24.12 95.063 ;
        RECT  18.6 2.137 18.72 95.063 ;
        RECT  13.2 2.137 13.32 95.063 ;
        RECT  7.8 2.137 7.92 95.063 ;
        RECT  2.4 2.137 2.52 95.063 ;
    END
  END VSS
  OBS
    LAYER RVTN ;
     RECT  2.16 2.16 170.64 2.295 ;
     RECT  2.16 2.565 170.64 2.835 ;
     RECT  2.16 3.105 170.64 3.375 ;
     RECT  2.16 3.645 170.64 3.915 ;
     RECT  2.16 4.185 170.64 4.455 ;
     RECT  2.16 4.725 170.64 4.995 ;
     RECT  2.16 5.265 170.64 5.535 ;
     RECT  2.16 5.805 170.64 6.075 ;
     RECT  2.16 6.345 170.64 6.615 ;
     RECT  2.16 6.885 170.64 7.155 ;
     RECT  2.16 7.425 170.64 7.695 ;
     RECT  2.16 7.965 170.64 8.235 ;
     RECT  2.16 8.505 170.64 8.775 ;
     RECT  2.16 9.045 170.64 9.315 ;
     RECT  2.16 9.585 170.64 9.855 ;
     RECT  2.16 10.125 170.64 10.395 ;
     RECT  2.16 10.665 170.64 10.935 ;
     RECT  2.16 11.205 170.64 11.475 ;
     RECT  2.16 11.745 170.64 12.015 ;
     RECT  2.16 12.285 170.64 12.555 ;
     RECT  2.16 12.825 170.64 13.095 ;
     RECT  2.16 13.365 170.64 13.635 ;
     RECT  2.16 13.905 170.64 14.175 ;
     RECT  2.16 14.445 170.64 14.715 ;
     RECT  2.16 14.985 170.64 15.255 ;
     RECT  2.16 15.525 170.64 15.795 ;
     RECT  2.16 16.065 170.64 16.335 ;
     RECT  2.16 16.605 170.64 16.875 ;
     RECT  2.16 17.145 170.64 17.415 ;
     RECT  2.16 17.685 170.64 17.955 ;
     RECT  2.16 18.225 170.64 18.495 ;
     RECT  2.16 18.765 170.64 19.035 ;
     RECT  2.16 19.305 170.64 19.575 ;
     RECT  2.16 19.845 170.64 20.115 ;
     RECT  2.16 20.385 170.64 20.655 ;
     RECT  2.16 20.925 170.64 21.195 ;
     RECT  2.16 21.465 170.64 21.735 ;
     RECT  2.16 22.005 170.64 22.275 ;
     RECT  2.16 22.545 170.64 22.815 ;
     RECT  2.16 23.085 170.64 23.355 ;
     RECT  2.16 23.625 170.64 23.76 ;
     RECT  2.16 23.76 36.828 23.895 ;
     RECT  135.756 23.76 170.64 23.895 ;
     RECT  2.16 24.165 36.828 24.435 ;
     RECT  135.756 24.165 170.64 24.435 ;
     RECT  2.16 24.705 36.828 24.975 ;
     RECT  135.756 24.705 170.64 24.975 ;
     RECT  2.16 25.245 36.828 25.515 ;
     RECT  135.756 25.245 170.64 25.515 ;
     RECT  2.16 25.785 36.828 26.055 ;
     RECT  135.756 25.785 170.64 26.055 ;
     RECT  2.16 26.325 36.828 26.595 ;
     RECT  135.756 26.325 170.64 26.595 ;
     RECT  2.16 26.865 36.828 27.135 ;
     RECT  135.756 26.865 170.64 27.135 ;
     RECT  2.16 27.405 36.828 27.675 ;
     RECT  135.756 27.405 170.64 27.675 ;
     RECT  2.16 27.945 36.828 28.215 ;
     RECT  135.756 27.945 170.64 28.215 ;
     RECT  2.16 28.485 36.828 28.755 ;
     RECT  135.756 28.485 170.64 28.755 ;
     RECT  2.16 29.025 36.828 29.295 ;
     RECT  135.756 29.025 170.64 29.295 ;
     RECT  2.16 29.565 36.828 29.835 ;
     RECT  135.756 29.565 170.64 29.835 ;
     RECT  2.16 30.105 36.828 30.375 ;
     RECT  135.756 30.105 170.64 30.375 ;
     RECT  2.16 30.645 36.828 30.915 ;
     RECT  135.756 30.645 170.64 30.915 ;
     RECT  2.16 31.185 36.828 31.455 ;
     RECT  135.756 31.185 170.64 31.455 ;
     RECT  2.16 31.725 36.828 31.995 ;
     RECT  135.756 31.725 170.64 31.995 ;
     RECT  2.16 32.265 36.828 32.535 ;
     RECT  135.756 32.265 170.64 32.535 ;
     RECT  2.16 32.805 36.828 33.075 ;
     RECT  135.756 32.805 170.64 33.075 ;
     RECT  2.16 33.345 36.828 33.615 ;
     RECT  135.756 33.345 170.64 33.615 ;
     RECT  2.16 33.885 36.828 34.155 ;
     RECT  135.756 33.885 170.64 34.155 ;
     RECT  2.16 34.425 36.828 34.695 ;
     RECT  135.756 34.425 170.64 34.695 ;
     RECT  2.16 34.965 36.828 35.235 ;
     RECT  135.756 34.965 170.64 35.235 ;
     RECT  2.16 35.505 36.828 35.775 ;
     RECT  135.756 35.505 170.64 35.775 ;
     RECT  2.16 36.045 36.828 36.315 ;
     RECT  135.756 36.045 170.64 36.315 ;
     RECT  2.16 36.585 36.828 36.855 ;
     RECT  135.756 36.585 170.64 36.855 ;
     RECT  2.16 37.125 36.828 37.395 ;
     RECT  135.756 37.125 170.64 37.395 ;
     RECT  2.16 37.665 36.828 37.935 ;
     RECT  135.756 37.665 170.64 37.935 ;
     RECT  2.16 38.205 36.828 38.475 ;
     RECT  135.756 38.205 170.64 38.475 ;
     RECT  2.16 38.745 36.828 39.015 ;
     RECT  135.756 38.745 170.64 39.015 ;
     RECT  2.16 39.285 36.828 39.555 ;
     RECT  135.756 39.285 170.64 39.555 ;
     RECT  2.16 39.825 36.828 40.095 ;
     RECT  135.756 39.825 170.64 40.095 ;
     RECT  2.16 40.365 36.828 40.635 ;
     RECT  135.756 40.365 170.64 40.635 ;
     RECT  2.16 40.905 36.828 41.175 ;
     RECT  135.756 40.905 170.64 41.175 ;
     RECT  2.16 41.445 36.828 41.715 ;
     RECT  135.756 41.445 170.64 41.715 ;
     RECT  2.16 41.985 36.828 42.255 ;
     RECT  135.756 41.985 170.64 42.255 ;
     RECT  2.16 42.525 36.828 42.795 ;
     RECT  135.756 42.525 170.64 42.795 ;
     RECT  2.16 43.065 36.828 43.335 ;
     RECT  135.756 43.065 170.64 43.335 ;
     RECT  2.16 43.605 36.828 43.875 ;
     RECT  135.756 43.605 170.64 43.875 ;
     RECT  2.16 44.145 36.828 44.415 ;
     RECT  135.756 44.145 170.64 44.415 ;
     RECT  2.16 44.685 36.828 44.955 ;
     RECT  135.756 44.685 170.64 44.955 ;
     RECT  2.16 45.225 36.828 45.495 ;
     RECT  135.756 45.225 170.64 45.495 ;
     RECT  2.16 45.765 36.828 46.035 ;
     RECT  135.756 45.765 170.64 46.035 ;
     RECT  2.16 46.305 36.828 46.575 ;
     RECT  135.756 46.305 170.64 46.575 ;
     RECT  2.16 46.845 36.828 47.115 ;
     RECT  135.756 46.845 170.64 47.115 ;
     RECT  2.16 47.385 36.828 47.655 ;
     RECT  135.756 47.385 170.64 47.655 ;
     RECT  2.16 47.925 36.828 48.195 ;
     RECT  135.756 47.925 170.64 48.195 ;
     RECT  2.16 48.465 36.828 48.735 ;
     RECT  135.756 48.465 170.64 48.735 ;
     RECT  2.16 49.005 36.828 49.275 ;
     RECT  135.756 49.005 170.64 49.275 ;
     RECT  2.16 49.545 36.828 49.815 ;
     RECT  135.756 49.545 170.64 49.815 ;
     RECT  2.16 50.085 36.828 50.355 ;
     RECT  135.756 50.085 170.64 50.355 ;
     RECT  2.16 50.625 36.828 50.895 ;
     RECT  135.756 50.625 170.64 50.895 ;
     RECT  2.16 51.165 36.828 51.435 ;
     RECT  135.756 51.165 170.64 51.435 ;
     RECT  2.16 51.705 36.828 51.975 ;
     RECT  135.756 51.705 170.64 51.975 ;
     RECT  2.16 52.245 36.828 52.515 ;
     RECT  135.756 52.245 170.64 52.515 ;
     RECT  2.16 52.785 36.828 53.055 ;
     RECT  135.756 52.785 170.64 53.055 ;
     RECT  2.16 53.325 36.828 53.595 ;
     RECT  135.756 53.325 170.64 53.595 ;
     RECT  2.16 53.865 36.828 54.135 ;
     RECT  135.756 53.865 170.64 54.135 ;
     RECT  2.16 54.405 36.828 54.675 ;
     RECT  135.756 54.405 170.64 54.675 ;
     RECT  2.16 54.945 36.828 55.215 ;
     RECT  135.756 54.945 170.64 55.215 ;
     RECT  2.16 55.485 36.828 55.755 ;
     RECT  135.756 55.485 170.64 55.755 ;
     RECT  2.16 56.025 36.828 56.295 ;
     RECT  135.756 56.025 170.64 56.295 ;
     RECT  2.16 56.565 36.828 56.835 ;
     RECT  135.756 56.565 170.64 56.835 ;
     RECT  2.16 57.105 36.828 57.375 ;
     RECT  135.756 57.105 170.64 57.375 ;
     RECT  2.16 57.645 36.828 57.915 ;
     RECT  135.756 57.645 170.64 57.915 ;
     RECT  2.16 58.185 36.828 58.455 ;
     RECT  135.756 58.185 170.64 58.455 ;
     RECT  2.16 58.725 36.828 58.995 ;
     RECT  135.756 58.725 170.64 58.995 ;
     RECT  2.16 59.265 36.828 59.535 ;
     RECT  135.756 59.265 170.64 59.535 ;
     RECT  2.16 59.805 36.828 60.075 ;
     RECT  135.756 59.805 170.64 60.075 ;
     RECT  2.16 60.345 36.828 60.615 ;
     RECT  135.756 60.345 170.64 60.615 ;
     RECT  2.16 60.885 36.828 61.155 ;
     RECT  135.756 60.885 170.64 61.155 ;
     RECT  2.16 61.425 36.828 61.695 ;
     RECT  135.756 61.425 170.64 61.695 ;
     RECT  2.16 61.965 36.828 62.235 ;
     RECT  135.756 61.965 170.64 62.235 ;
     RECT  2.16 62.505 36.828 62.775 ;
     RECT  135.756 62.505 170.64 62.775 ;
     RECT  2.16 63.045 36.828 63.315 ;
     RECT  135.756 63.045 170.64 63.315 ;
     RECT  2.16 63.585 36.828 63.855 ;
     RECT  135.756 63.585 170.64 63.855 ;
     RECT  2.16 64.125 36.828 64.395 ;
     RECT  135.756 64.125 170.64 64.395 ;
     RECT  2.16 64.665 36.828 64.935 ;
     RECT  135.756 64.665 170.64 64.935 ;
     RECT  2.16 65.205 36.828 65.475 ;
     RECT  135.756 65.205 170.64 65.475 ;
     RECT  2.16 65.745 36.828 66.015 ;
     RECT  135.756 65.745 170.64 66.015 ;
     RECT  2.16 66.285 36.828 66.555 ;
     RECT  135.756 66.285 170.64 66.555 ;
     RECT  2.16 66.825 36.828 67.095 ;
     RECT  135.756 66.825 170.64 67.095 ;
     RECT  2.16 67.365 36.828 67.635 ;
     RECT  135.756 67.365 170.64 67.635 ;
     RECT  2.16 67.905 36.828 68.175 ;
     RECT  135.756 67.905 170.64 68.175 ;
     RECT  2.16 68.445 36.828 68.715 ;
     RECT  135.756 68.445 170.64 68.715 ;
     RECT  2.16 68.985 36.828 69.12 ;
     RECT  135.756 68.985 170.64 69.12 ;
     RECT  2.16 69.12 170.64 69.255 ;
     RECT  2.16 69.525 170.64 69.795 ;
     RECT  2.16 70.065 170.64 70.335 ;
     RECT  2.16 70.605 170.64 70.875 ;
     RECT  2.16 71.145 170.64 71.415 ;
     RECT  2.16 71.685 170.64 71.955 ;
     RECT  2.16 72.225 170.64 72.495 ;
     RECT  2.16 72.765 170.64 73.035 ;
     RECT  2.16 73.305 170.64 73.575 ;
     RECT  2.16 73.845 170.64 74.115 ;
     RECT  2.16 74.385 170.64 74.655 ;
     RECT  2.16 74.925 170.64 75.195 ;
     RECT  2.16 75.465 170.64 75.735 ;
     RECT  2.16 76.005 170.64 76.275 ;
     RECT  2.16 76.545 170.64 76.815 ;
     RECT  2.16 77.085 170.64 77.355 ;
     RECT  2.16 77.625 170.64 77.895 ;
     RECT  2.16 78.165 170.64 78.435 ;
     RECT  2.16 78.705 170.64 78.975 ;
     RECT  2.16 79.245 170.64 79.515 ;
     RECT  2.16 79.785 170.64 80.055 ;
     RECT  2.16 80.325 170.64 80.595 ;
     RECT  2.16 80.865 170.64 81.135 ;
     RECT  2.16 81.405 170.64 81.675 ;
     RECT  2.16 81.945 170.64 82.215 ;
     RECT  2.16 82.485 170.64 82.755 ;
     RECT  2.16 83.025 170.64 83.295 ;
     RECT  2.16 83.565 170.64 83.835 ;
     RECT  2.16 84.105 170.64 84.375 ;
     RECT  2.16 84.645 170.64 84.915 ;
     RECT  2.16 85.185 170.64 85.455 ;
     RECT  2.16 85.725 170.64 85.995 ;
     RECT  2.16 86.265 170.64 86.535 ;
     RECT  2.16 86.805 170.64 87.075 ;
     RECT  2.16 87.345 170.64 87.615 ;
     RECT  2.16 87.885 170.64 88.155 ;
     RECT  2.16 88.425 170.64 88.695 ;
     RECT  2.16 88.965 170.64 89.235 ;
     RECT  2.16 89.505 170.64 89.775 ;
     RECT  2.16 90.045 170.64 90.315 ;
     RECT  2.16 90.585 170.64 90.855 ;
     RECT  2.16 91.125 170.64 91.395 ;
     RECT  2.16 91.665 170.64 91.935 ;
     RECT  2.16 92.205 170.64 92.475 ;
     RECT  2.16 92.745 170.64 93.015 ;
     RECT  2.16 93.285 170.64 93.555 ;
     RECT  2.16 93.825 170.64 94.095 ;
     RECT  2.16 94.365 170.64 94.635 ;
     RECT  2.16 94.905 170.64 95.04 ;
    LAYER RVTP ;
     RECT  2.16 2.295 170.64 2.565 ;
     RECT  2.16 2.835 170.64 3.105 ;
     RECT  2.16 3.375 170.64 3.645 ;
     RECT  2.16 3.915 170.64 4.185 ;
     RECT  2.16 4.455 170.64 4.725 ;
     RECT  2.16 4.995 170.64 5.265 ;
     RECT  2.16 5.535 170.64 5.805 ;
     RECT  2.16 6.075 170.64 6.345 ;
     RECT  2.16 6.615 170.64 6.885 ;
     RECT  2.16 7.155 170.64 7.425 ;
     RECT  2.16 7.695 170.64 7.965 ;
     RECT  2.16 8.235 170.64 8.505 ;
     RECT  2.16 8.775 170.64 9.045 ;
     RECT  2.16 9.315 170.64 9.585 ;
     RECT  2.16 9.855 170.64 10.125 ;
     RECT  2.16 10.395 170.64 10.665 ;
     RECT  2.16 10.935 170.64 11.205 ;
     RECT  2.16 11.475 170.64 11.745 ;
     RECT  2.16 12.015 170.64 12.285 ;
     RECT  2.16 12.555 170.64 12.825 ;
     RECT  2.16 13.095 170.64 13.365 ;
     RECT  2.16 13.635 170.64 13.905 ;
     RECT  2.16 14.175 170.64 14.445 ;
     RECT  2.16 14.715 170.64 14.985 ;
     RECT  2.16 15.255 170.64 15.525 ;
     RECT  2.16 15.795 170.64 16.065 ;
     RECT  2.16 16.335 170.64 16.605 ;
     RECT  2.16 16.875 170.64 17.145 ;
     RECT  2.16 17.415 170.64 17.685 ;
     RECT  2.16 17.955 170.64 18.225 ;
     RECT  2.16 18.495 170.64 18.765 ;
     RECT  2.16 19.035 170.64 19.305 ;
     RECT  2.16 19.575 170.64 19.845 ;
     RECT  2.16 20.115 170.64 20.385 ;
     RECT  2.16 20.655 170.64 20.925 ;
     RECT  2.16 21.195 170.64 21.465 ;
     RECT  2.16 21.735 170.64 22.005 ;
     RECT  2.16 22.275 170.64 22.545 ;
     RECT  2.16 22.815 170.64 23.085 ;
     RECT  2.16 23.355 170.64 23.625 ;
     RECT  2.16 23.895 36.828 24.165 ;
     RECT  135.756 23.895 170.64 24.165 ;
     RECT  2.16 24.435 36.828 24.705 ;
     RECT  135.756 24.435 170.64 24.705 ;
     RECT  2.16 24.975 36.828 25.245 ;
     RECT  135.756 24.975 170.64 25.245 ;
     RECT  2.16 25.515 36.828 25.785 ;
     RECT  135.756 25.515 170.64 25.785 ;
     RECT  2.16 26.055 36.828 26.325 ;
     RECT  135.756 26.055 170.64 26.325 ;
     RECT  2.16 26.595 36.828 26.865 ;
     RECT  135.756 26.595 170.64 26.865 ;
     RECT  2.16 27.135 36.828 27.405 ;
     RECT  135.756 27.135 170.64 27.405 ;
     RECT  2.16 27.675 36.828 27.945 ;
     RECT  135.756 27.675 170.64 27.945 ;
     RECT  2.16 28.215 36.828 28.485 ;
     RECT  135.756 28.215 170.64 28.485 ;
     RECT  2.16 28.755 36.828 29.025 ;
     RECT  135.756 28.755 170.64 29.025 ;
     RECT  2.16 29.295 36.828 29.565 ;
     RECT  135.756 29.295 170.64 29.565 ;
     RECT  2.16 29.835 36.828 30.105 ;
     RECT  135.756 29.835 170.64 30.105 ;
     RECT  2.16 30.375 36.828 30.645 ;
     RECT  135.756 30.375 170.64 30.645 ;
     RECT  2.16 30.915 36.828 31.185 ;
     RECT  135.756 30.915 170.64 31.185 ;
     RECT  2.16 31.455 36.828 31.725 ;
     RECT  135.756 31.455 170.64 31.725 ;
     RECT  2.16 31.995 36.828 32.265 ;
     RECT  135.756 31.995 170.64 32.265 ;
     RECT  2.16 32.535 36.828 32.805 ;
     RECT  135.756 32.535 170.64 32.805 ;
     RECT  2.16 33.075 36.828 33.345 ;
     RECT  135.756 33.075 170.64 33.345 ;
     RECT  2.16 33.615 36.828 33.885 ;
     RECT  135.756 33.615 170.64 33.885 ;
     RECT  2.16 34.155 36.828 34.425 ;
     RECT  135.756 34.155 170.64 34.425 ;
     RECT  2.16 34.695 36.828 34.965 ;
     RECT  135.756 34.695 170.64 34.965 ;
     RECT  2.16 35.235 36.828 35.505 ;
     RECT  135.756 35.235 170.64 35.505 ;
     RECT  2.16 35.775 36.828 36.045 ;
     RECT  135.756 35.775 170.64 36.045 ;
     RECT  2.16 36.315 36.828 36.585 ;
     RECT  135.756 36.315 170.64 36.585 ;
     RECT  2.16 36.855 36.828 37.125 ;
     RECT  135.756 36.855 170.64 37.125 ;
     RECT  2.16 37.395 36.828 37.665 ;
     RECT  135.756 37.395 170.64 37.665 ;
     RECT  2.16 37.935 36.828 38.205 ;
     RECT  135.756 37.935 170.64 38.205 ;
     RECT  2.16 38.475 36.828 38.745 ;
     RECT  135.756 38.475 170.64 38.745 ;
     RECT  2.16 39.015 36.828 39.285 ;
     RECT  135.756 39.015 170.64 39.285 ;
     RECT  2.16 39.555 36.828 39.825 ;
     RECT  135.756 39.555 170.64 39.825 ;
     RECT  2.16 40.095 36.828 40.365 ;
     RECT  135.756 40.095 170.64 40.365 ;
     RECT  2.16 40.635 36.828 40.905 ;
     RECT  135.756 40.635 170.64 40.905 ;
     RECT  2.16 41.175 36.828 41.445 ;
     RECT  135.756 41.175 170.64 41.445 ;
     RECT  2.16 41.715 36.828 41.985 ;
     RECT  135.756 41.715 170.64 41.985 ;
     RECT  2.16 42.255 36.828 42.525 ;
     RECT  135.756 42.255 170.64 42.525 ;
     RECT  2.16 42.795 36.828 43.065 ;
     RECT  135.756 42.795 170.64 43.065 ;
     RECT  2.16 43.335 36.828 43.605 ;
     RECT  135.756 43.335 170.64 43.605 ;
     RECT  2.16 43.875 36.828 44.145 ;
     RECT  135.756 43.875 170.64 44.145 ;
     RECT  2.16 44.415 36.828 44.685 ;
     RECT  135.756 44.415 170.64 44.685 ;
     RECT  2.16 44.955 36.828 45.225 ;
     RECT  135.756 44.955 170.64 45.225 ;
     RECT  2.16 45.495 36.828 45.765 ;
     RECT  135.756 45.495 170.64 45.765 ;
     RECT  2.16 46.035 36.828 46.305 ;
     RECT  135.756 46.035 170.64 46.305 ;
     RECT  2.16 46.575 36.828 46.845 ;
     RECT  135.756 46.575 170.64 46.845 ;
     RECT  2.16 47.115 36.828 47.385 ;
     RECT  135.756 47.115 170.64 47.385 ;
     RECT  2.16 47.655 36.828 47.925 ;
     RECT  135.756 47.655 170.64 47.925 ;
     RECT  2.16 48.195 36.828 48.465 ;
     RECT  135.756 48.195 170.64 48.465 ;
     RECT  2.16 48.735 36.828 49.005 ;
     RECT  135.756 48.735 170.64 49.005 ;
     RECT  2.16 49.275 36.828 49.545 ;
     RECT  135.756 49.275 170.64 49.545 ;
     RECT  2.16 49.815 36.828 50.085 ;
     RECT  135.756 49.815 170.64 50.085 ;
     RECT  2.16 50.355 36.828 50.625 ;
     RECT  135.756 50.355 170.64 50.625 ;
     RECT  2.16 50.895 36.828 51.165 ;
     RECT  135.756 50.895 170.64 51.165 ;
     RECT  2.16 51.435 36.828 51.705 ;
     RECT  135.756 51.435 170.64 51.705 ;
     RECT  2.16 51.975 36.828 52.245 ;
     RECT  135.756 51.975 170.64 52.245 ;
     RECT  2.16 52.515 36.828 52.785 ;
     RECT  135.756 52.515 170.64 52.785 ;
     RECT  2.16 53.055 36.828 53.325 ;
     RECT  135.756 53.055 170.64 53.325 ;
     RECT  2.16 53.595 36.828 53.865 ;
     RECT  135.756 53.595 170.64 53.865 ;
     RECT  2.16 54.135 36.828 54.405 ;
     RECT  135.756 54.135 170.64 54.405 ;
     RECT  2.16 54.675 36.828 54.945 ;
     RECT  135.756 54.675 170.64 54.945 ;
     RECT  2.16 55.215 36.828 55.485 ;
     RECT  135.756 55.215 170.64 55.485 ;
     RECT  2.16 55.755 36.828 56.025 ;
     RECT  135.756 55.755 170.64 56.025 ;
     RECT  2.16 56.295 36.828 56.565 ;
     RECT  135.756 56.295 170.64 56.565 ;
     RECT  2.16 56.835 36.828 57.105 ;
     RECT  135.756 56.835 170.64 57.105 ;
     RECT  2.16 57.375 36.828 57.645 ;
     RECT  135.756 57.375 170.64 57.645 ;
     RECT  2.16 57.915 36.828 58.185 ;
     RECT  135.756 57.915 170.64 58.185 ;
     RECT  2.16 58.455 36.828 58.725 ;
     RECT  135.756 58.455 170.64 58.725 ;
     RECT  2.16 58.995 36.828 59.265 ;
     RECT  135.756 58.995 170.64 59.265 ;
     RECT  2.16 59.535 36.828 59.805 ;
     RECT  135.756 59.535 170.64 59.805 ;
     RECT  2.16 60.075 36.828 60.345 ;
     RECT  135.756 60.075 170.64 60.345 ;
     RECT  2.16 60.615 36.828 60.885 ;
     RECT  135.756 60.615 170.64 60.885 ;
     RECT  2.16 61.155 36.828 61.425 ;
     RECT  135.756 61.155 170.64 61.425 ;
     RECT  2.16 61.695 36.828 61.965 ;
     RECT  135.756 61.695 170.64 61.965 ;
     RECT  2.16 62.235 36.828 62.505 ;
     RECT  135.756 62.235 170.64 62.505 ;
     RECT  2.16 62.775 36.828 63.045 ;
     RECT  135.756 62.775 170.64 63.045 ;
     RECT  2.16 63.315 36.828 63.585 ;
     RECT  135.756 63.315 170.64 63.585 ;
     RECT  2.16 63.855 36.828 64.125 ;
     RECT  135.756 63.855 170.64 64.125 ;
     RECT  2.16 64.395 36.828 64.665 ;
     RECT  135.756 64.395 170.64 64.665 ;
     RECT  2.16 64.935 36.828 65.205 ;
     RECT  135.756 64.935 170.64 65.205 ;
     RECT  2.16 65.475 36.828 65.745 ;
     RECT  135.756 65.475 170.64 65.745 ;
     RECT  2.16 66.015 36.828 66.285 ;
     RECT  135.756 66.015 170.64 66.285 ;
     RECT  2.16 66.555 36.828 66.825 ;
     RECT  135.756 66.555 170.64 66.825 ;
     RECT  2.16 67.095 36.828 67.365 ;
     RECT  135.756 67.095 170.64 67.365 ;
     RECT  2.16 67.635 36.828 67.905 ;
     RECT  135.756 67.635 170.64 67.905 ;
     RECT  2.16 68.175 36.828 68.445 ;
     RECT  135.756 68.175 170.64 68.445 ;
     RECT  2.16 68.715 36.828 68.985 ;
     RECT  135.756 68.715 170.64 68.985 ;
     RECT  2.16 69.255 170.64 69.525 ;
     RECT  2.16 69.795 170.64 70.065 ;
     RECT  2.16 70.335 170.64 70.605 ;
     RECT  2.16 70.875 170.64 71.145 ;
     RECT  2.16 71.415 170.64 71.685 ;
     RECT  2.16 71.955 170.64 72.225 ;
     RECT  2.16 72.495 170.64 72.765 ;
     RECT  2.16 73.035 170.64 73.305 ;
     RECT  2.16 73.575 170.64 73.845 ;
     RECT  2.16 74.115 170.64 74.385 ;
     RECT  2.16 74.655 170.64 74.925 ;
     RECT  2.16 75.195 170.64 75.465 ;
     RECT  2.16 75.735 170.64 76.005 ;
     RECT  2.16 76.275 170.64 76.545 ;
     RECT  2.16 76.815 170.64 77.085 ;
     RECT  2.16 77.355 170.64 77.625 ;
     RECT  2.16 77.895 170.64 78.165 ;
     RECT  2.16 78.435 170.64 78.705 ;
     RECT  2.16 78.975 170.64 79.245 ;
     RECT  2.16 79.515 170.64 79.785 ;
     RECT  2.16 80.055 170.64 80.325 ;
     RECT  2.16 80.595 170.64 80.865 ;
     RECT  2.16 81.135 170.64 81.405 ;
     RECT  2.16 81.675 170.64 81.945 ;
     RECT  2.16 82.215 170.64 82.485 ;
     RECT  2.16 82.755 170.64 83.025 ;
     RECT  2.16 83.295 170.64 83.565 ;
     RECT  2.16 83.835 170.64 84.105 ;
     RECT  2.16 84.375 170.64 84.645 ;
     RECT  2.16 84.915 170.64 85.185 ;
     RECT  2.16 85.455 170.64 85.725 ;
     RECT  2.16 85.995 170.64 86.265 ;
     RECT  2.16 86.535 170.64 86.805 ;
     RECT  2.16 87.075 170.64 87.345 ;
     RECT  2.16 87.615 170.64 87.885 ;
     RECT  2.16 88.155 170.64 88.425 ;
     RECT  2.16 88.695 170.64 88.965 ;
     RECT  2.16 89.235 170.64 89.505 ;
     RECT  2.16 89.775 170.64 90.045 ;
     RECT  2.16 90.315 170.64 90.585 ;
     RECT  2.16 90.855 170.64 91.125 ;
     RECT  2.16 91.395 170.64 91.665 ;
     RECT  2.16 91.935 170.64 92.205 ;
     RECT  2.16 92.475 170.64 92.745 ;
     RECT  2.16 93.015 170.64 93.285 ;
     RECT  2.16 93.555 170.64 93.825 ;
     RECT  2.16 94.095 170.64 94.365 ;
     RECT  2.16 94.635 170.64 94.905 ;
    LAYER M1 ;
     RECT  2.16 2.151 170.64 23.769 ;
     RECT  38.88 25.92 133.704 66.984 ;
     RECT  2.16 23.769 36.828 69.111 ;
     RECT  135.756 23.769 170.64 69.111 ;
     RECT  2.16 69.111 170.64 95.049 ;
    LAYER M2 ;
     RECT  2.16 2.151 5.899 95.049 ;
     RECT  5.899 1.728 6.107 95.049 ;
     RECT  6.107 2.151 7.195 95.049 ;
     RECT  7.195 2.106 7.583 95.049 ;
     RECT  7.583 2.151 8.491 95.049 ;
     RECT  8.491 2.106 9.023 95.049 ;
     RECT  9.023 2.151 11.047 95.049 ;
     RECT  11.047 2.106 11.579 95.049 ;
     RECT  11.579 2.151 12.307 95.049 ;
     RECT  12.307 1.728 12.443 95.049 ;
     RECT  12.443 2.151 13.603 95.049 ;
     RECT  13.603 2.106 14.063 95.049 ;
     RECT  14.063 2.151 16.159 95.049 ;
     RECT  16.159 1.728 16.475 95.049 ;
     RECT  16.475 2.151 17.455 95.049 ;
     RECT  17.455 2.106 17.771 95.049 ;
     RECT  17.771 2.151 21.379 95.049 ;
     RECT  21.307 0.144 21.407 0.162 ;
     RECT  21.379 2.106 21.839 95.049 ;
     RECT  21.839 2.151 22.567 95.049 ;
     RECT  22.567 2.106 22.955 95.049 ;
     RECT  22.955 2.151 25.159 95.049 ;
     RECT  25.159 1.728 25.403 95.049 ;
     RECT  25.403 2.151 26.419 95.049 ;
     RECT  26.419 1.728 26.519 95.049 ;
     RECT  26.519 2.151 27.715 95.049 ;
     RECT  27.715 2.106 28.031 95.049 ;
     RECT  28.031 2.151 30.271 95.049 ;
     RECT  30.271 1.728 30.515 95.049 ;
     RECT  30.515 2.151 32.827 95.049 ;
     RECT  32.827 2.106 35.051 95.049 ;
     RECT  35.051 2.151 36.679 95.049 ;
     RECT  36.679 2.106 36.828 95.049 ;
     RECT  36.828 33.012 36.851 34.956 ;
     RECT  36.828 46.746 36.851 48.186 ;
     RECT  36.828 62.82 36.851 64.89 ;
     RECT  36.828 29.61 36.887 31.446 ;
     RECT  36.851 46.746 36.887 46.908 ;
     RECT  36.851 33.246 36.923 34.956 ;
     RECT  36.887 30.078 36.959 31.446 ;
     RECT  36.851 62.82 36.959 64.152 ;
     RECT  36.959 62.901 36.995 64.152 ;
     RECT  36.828 57.276 37.067 60.408 ;
     RECT  36.828 2.106 37.175 28.782 ;
     RECT  37.175 2.151 37.247 28.782 ;
     RECT  37.067 57.276 37.247 57.294 ;
     RECT  36.887 46.746 37.283 46.764 ;
     RECT  36.828 61.506 37.355 61.569 ;
     RECT  36.828 49.284 37.391 50.454 ;
     RECT  36.828 66.636 37.427 95.049 ;
     RECT  37.247 2.151 37.463 28.746 ;
     RECT  36.828 45.036 37.463 45.684 ;
     RECT  37.391 49.284 37.499 49.878 ;
     RECT  36.828 51.606 37.535 51.624 ;
     RECT  36.828 42.192 37.643 42.21 ;
     RECT  36.995 62.982 37.643 64.152 ;
     RECT  37.643 62.982 37.715 63.729 ;
     RECT  37.499 49.284 37.787 49.302 ;
     RECT  37.067 58.158 37.795 60.408 ;
     RECT  37.795 58.158 37.823 60.57 ;
     RECT  37.463 45.036 37.859 45.054 ;
     RECT  36.828 36.252 37.867 36.648 ;
     RECT  36.828 37.476 37.867 38.97 ;
     RECT  36.828 39.996 37.895 41.094 ;
     RECT  37.615 57.006 37.895 57.096 ;
     RECT  37.823 60.318 37.895 60.57 ;
     RECT  36.959 30.456 37.903 31.446 ;
     RECT  37.895 57.006 37.967 57.024 ;
     RECT  37.895 39.996 38.039 40.626 ;
     RECT  36.851 48.168 38.147 48.186 ;
     RECT  37.715 62.982 38.191 63.306 ;
     RECT  36.923 33.246 38.227 33.984 ;
     RECT  37.427 66.726 38.515 95.049 ;
     RECT  37.463 27.576 38.695 28.746 ;
     RECT  37.463 2.151 38.88 26.784 ;
     RECT  38.695 27.576 38.88 28.818 ;
     RECT  37.903 30.15 38.88 31.446 ;
     RECT  38.227 33.048 38.88 33.984 ;
     RECT  36.923 34.938 38.88 34.956 ;
     RECT  37.867 36.252 38.88 38.97 ;
     RECT  38.039 39.996 38.88 40.014 ;
     RECT  38.695 44.622 38.88 44.64 ;
     RECT  36.828 52.722 38.88 52.974 ;
     RECT  36.828 53.766 38.88 53.784 ;
     RECT  37.823 58.158 38.88 59.562 ;
     RECT  37.895 60.318 38.88 60.336 ;
     RECT  37.355 61.551 38.88 61.569 ;
     RECT  38.191 62.676 38.88 63.306 ;
     RECT  37.867 64.98 38.88 64.998 ;
     RECT  38.515 66.681 38.88 95.049 ;
     RECT  38.88 2.151 39.271 95.049 ;
     RECT  39.271 2.106 40.531 95.049 ;
     RECT  40.531 1.728 40.775 95.049 ;
     RECT  40.775 2.151 41.827 95.049 ;
     RECT  41.827 1.728 42.071 95.049 ;
     RECT  42.071 2.151 44.383 95.049 ;
     RECT  44.383 2.106 44.735 95.049 ;
     RECT  45.679 0.144 45.779 0.162 ;
     RECT  44.735 2.151 49.531 95.049 ;
     RECT  49.531 2.106 49.955 95.049 ;
     RECT  49.955 2.151 50.791 95.049 ;
     RECT  50.791 1.728 50.999 95.049 ;
     RECT  50.999 2.151 52.087 95.049 ;
     RECT  52.087 1.728 52.403 95.049 ;
     RECT  52.403 2.151 53.347 95.049 ;
     RECT  53.347 1.728 53.519 95.049 ;
     RECT  53.519 2.151 54.643 95.049 ;
     RECT  54.643 2.106 55.211 95.049 ;
     RECT  55.211 2.151 57.199 95.049 ;
     RECT  57.199 1.728 57.299 95.049 ;
     RECT  57.299 2.151 62.347 95.049 ;
     RECT  62.347 1.728 62.699 95.049 ;
     RECT  62.699 2.151 63.607 95.049 ;
     RECT  63.607 1.728 63.743 95.049 ;
     RECT  63.743 2.151 64.903 95.049 ;
     RECT  64.903 2.106 65.039 95.049 ;
     RECT  65.039 2.151 67.279 95.049 ;
     RECT  67.279 2.151 67.379 95.13 ;
     RECT  67.379 2.151 67.459 95.049 ;
     RECT  67.459 2.106 67.955 95.049 ;
     RECT  67.955 2.151 70.051 95.049 ;
     RECT  70.051 2.106 71.311 95.049 ;
     RECT  71.311 1.728 71.771 95.049 ;
     RECT  71.771 2.151 72.607 95.049 ;
     RECT  72.607 2.07 73.067 95.049 ;
     RECT  73.067 2.151 77.719 95.049 ;
     RECT  77.719 1.728 77.927 95.049 ;
     RECT  77.927 2.151 79.015 95.049 ;
     RECT  79.015 1.728 79.115 95.049 ;
     RECT  79.115 2.151 80.311 95.049 ;
     RECT  80.311 2.106 81.023 95.049 ;
     RECT  81.023 2.151 85.423 95.049 ;
     RECT  85.423 2.106 85.595 95.049 ;
     RECT  85.595 2.151 87.979 95.049 ;
     RECT  87.979 1.728 88.295 95.049 ;
     RECT  88.295 2.151 90.571 95.049 ;
     RECT  90.571 2.106 90.887 95.049 ;
     RECT  90.887 2.151 92.975 95.049 ;
     RECT  92.975 2.151 94.387 23.958 ;
     RECT  94.387 1.728 94.523 23.958 ;
     RECT  94.523 2.151 95.683 23.958 ;
     RECT  95.683 2.106 95.963 23.958 ;
     RECT  95.963 2.151 96.979 23.958 ;
     RECT  96.979 1.728 97.223 23.958 ;
     RECT  97.223 2.151 100.831 23.958 ;
     RECT  100.831 2.106 101.219 23.958 ;
     RECT  101.219 2.151 102.091 23.958 ;
     RECT  102.091 1.728 102.299 23.958 ;
     RECT  102.299 2.151 103.387 23.958 ;
     RECT  103.387 1.728 103.595 23.958 ;
     RECT  103.595 2.151 104.647 23.958 ;
     RECT  104.647 1.728 104.891 23.958 ;
     RECT  104.891 2.151 105.943 23.958 ;
     RECT  105.943 2.106 106.223 23.958 ;
     RECT  106.223 2.151 108.499 23.958 ;
     RECT  108.499 1.728 108.707 23.958 ;
     RECT  108.707 2.151 109.795 23.958 ;
     RECT  109.795 1.728 109.831 23.958 ;
     RECT  109.831 1.728 109.895 23.994 ;
     RECT  109.895 2.151 111.091 23.994 ;
     RECT  111.091 2.106 111.191 23.994 ;
     RECT  111.191 2.151 113.647 23.994 ;
     RECT  113.647 2.106 114.107 23.994 ;
     RECT  114.107 2.151 114.907 23.994 ;
     RECT  114.907 1.728 115.079 23.994 ;
     RECT  115.079 2.151 116.203 23.994 ;
     RECT  116.203 2.106 116.555 23.994 ;
     RECT  116.555 2.151 117.499 23.994 ;
     RECT  117.499 1.728 117.635 23.994 ;
     RECT  117.635 2.151 118.759 23.994 ;
     RECT  118.759 1.728 118.967 23.994 ;
     RECT  118.967 2.151 119.083 23.994 ;
     RECT  92.975 24.786 119.083 95.049 ;
     RECT  119.083 2.151 120.055 95.049 ;
     RECT  120.055 1.728 120.263 95.049 ;
     RECT  120.263 2.151 121.351 95.049 ;
     RECT  121.351 2.106 121.955 95.049 ;
     RECT  121.955 2.151 123.907 95.049 ;
     RECT  123.907 2.106 124.475 95.049 ;
     RECT  124.475 2.151 127.687 95.049 ;
     RECT  127.687 1.728 127.787 95.049 ;
     RECT  127.787 2.151 129.019 95.049 ;
     RECT  129.019 2.106 129.443 95.049 ;
     RECT  129.443 2.151 132.871 95.049 ;
     RECT  132.871 1.728 133.115 95.049 ;
     RECT  133.115 2.151 133.704 95.049 ;
     RECT  133.704 29.466 133.835 33.174 ;
     RECT  133.704 34.776 134.491 35.334 ;
     RECT  133.704 37.566 134.527 52.884 ;
     RECT  133.704 53.676 134.527 65.844 ;
     RECT  134.491 34.776 134.563 35.874 ;
     RECT  134.527 37.566 134.563 65.934 ;
     RECT  133.704 2.151 134.671 27.09 ;
     RECT  133.835 29.466 134.779 29.484 ;
     RECT  134.779 29.466 134.815 29.628 ;
     RECT  133.835 30.42 134.815 33.174 ;
     RECT  134.563 37.566 134.995 66.078 ;
     RECT  133.704 67.032 134.995 95.049 ;
     RECT  134.995 37.566 135.247 95.049 ;
     RECT  135.247 37.026 135.319 95.049 ;
     RECT  134.815 29.466 135.715 33.174 ;
     RECT  134.563 34.056 135.715 35.874 ;
     RECT  134.671 2.151 135.756 27.234 ;
     RECT  135.715 29.466 135.756 35.874 ;
     RECT  135.319 36.792 135.756 95.049 ;
     RECT  135.756 2.151 136.723 95.049 ;
     RECT  136.723 2.106 136.859 95.049 ;
     RECT  136.859 2.151 137.443 95.049 ;
     RECT  137.443 2.151 137.579 95.13 ;
     RECT  137.579 2.151 139.279 95.049 ;
     RECT  139.279 2.106 139.703 95.049 ;
     RECT  139.703 2.151 140.575 95.049 ;
     RECT  140.575 2.106 141.071 95.049 ;
     RECT  141.071 2.151 143.131 95.049 ;
     RECT  143.131 1.728 143.375 95.049 ;
     RECT  143.375 2.151 144.427 95.049 ;
     RECT  144.427 1.728 144.743 95.049 ;
     RECT  144.743 2.151 146.983 95.049 ;
     RECT  146.983 2.106 147.443 95.049 ;
     RECT  147.443 2.151 148.279 95.049 ;
     RECT  148.279 1.728 148.379 95.049 ;
     RECT  148.379 2.151 149.539 95.049 ;
     RECT  149.539 1.728 149.819 95.049 ;
     RECT  149.819 2.151 152.131 95.049 ;
     RECT  152.131 2.106 152.735 95.049 ;
     RECT  152.735 2.151 154.687 95.049 ;
     RECT  154.687 1.728 154.895 95.049 ;
     RECT  154.895 2.151 157.243 95.049 ;
     RECT  157.243 2.106 157.415 95.049 ;
     RECT  157.415 2.151 159.799 95.049 ;
     RECT  159.799 2.106 160.331 95.049 ;
     RECT  160.331 2.151 161.095 95.049 ;
     RECT  161.095 1.728 161.303 95.049 ;
     RECT  161.303 2.151 162.391 95.049 ;
     RECT  162.391 2.106 162.923 95.049 ;
     RECT  163.651 0.144 163.751 0.162 ;
     RECT  162.923 2.151 166.207 95.049 ;
     RECT  166.207 1.728 166.343 95.049 ;
     RECT  166.343 2.151 167.503 95.049 ;
     RECT  167.503 2.106 167.891 95.049 ;
     RECT  167.891 2.151 170.64 95.049 ;
    LAYER M3 ;
     RECT  21.312 0.108 21.33 0.139 ;
     RECT  45.684 0.108 45.702 0.139 ;
     RECT  163.656 0.108 163.674 0.139 ;
     RECT  21.312 0.139 21.402 0.167 ;
     RECT  163.656 0.139 163.746 0.167 ;
     RECT  5.904 0.108 5.922 0.187 ;
     RECT  9.756 0.108 9.774 0.187 ;
     RECT  11.052 0.108 11.07 0.187 ;
     RECT  14.904 0.108 14.922 0.187 ;
     RECT  16.164 0.108 16.182 0.187 ;
     RECT  17.46 0.108 17.478 0.187 ;
     RECT  18.756 0.108 18.774 0.187 ;
     RECT  20.016 0.108 20.034 0.187 ;
     RECT  23.868 0.108 23.886 0.187 ;
     RECT  25.164 0.108 25.182 0.187 ;
     RECT  26.424 0.108 26.442 0.187 ;
     RECT  27.72 0.108 27.738 0.187 ;
     RECT  29.016 0.108 29.034 0.187 ;
     RECT  31.572 0.108 31.59 0.187 ;
     RECT  32.832 0.108 32.85 0.187 ;
     RECT  35.424 0.108 35.442 0.187 ;
     RECT  36.684 0.108 36.702 0.187 ;
     RECT  40.536 0.108 40.554 0.187 ;
     RECT  41.832 0.108 41.85 0.187 ;
     RECT  43.092 0.108 43.11 0.187 ;
     RECT  44.388 0.108 44.406 0.187 ;
     RECT  46.944 0.108 46.962 0.187 ;
     RECT  48.24 0.108 48.258 0.187 ;
     RECT  52.092 0.108 52.11 0.187 ;
     RECT  55.944 0.108 55.962 0.187 ;
     RECT  57.204 0.108 57.222 0.187 ;
     RECT  58.5 0.108 58.518 0.187 ;
     RECT  59.796 0.108 59.814 0.187 ;
     RECT  61.056 0.108 61.074 0.187 ;
     RECT  62.352 0.108 62.37 0.187 ;
     RECT  67.464 0.108 67.482 0.187 ;
     RECT  72.612 0.108 72.63 0.187 ;
     RECT  81.576 0.108 81.594 0.187 ;
     RECT  82.872 0.108 82.89 0.187 ;
     RECT  84.132 0.108 84.15 0.187 ;
     RECT  86.724 0.108 86.742 0.187 ;
     RECT  91.836 0.108 91.854 0.187 ;
     RECT  96.984 0.108 97.002 0.187 ;
     RECT  98.244 0.108 98.262 0.187 ;
     RECT  99.54 0.108 99.558 0.187 ;
     RECT  100.836 0.108 100.854 0.187 ;
     RECT  102.096 0.108 102.114 0.187 ;
     RECT  103.392 0.108 103.41 0.187 ;
     RECT  107.244 0.108 107.262 0.187 ;
     RECT  113.652 0.108 113.67 0.187 ;
     RECT  123.912 0.108 123.93 0.187 ;
     RECT  125.172 0.108 125.19 0.187 ;
     RECT  126.468 0.108 126.486 0.187 ;
     RECT  127.764 0.108 127.782 0.187 ;
     RECT  129.024 0.108 129.042 0.187 ;
     RECT  131.616 0.108 131.634 0.187 ;
     RECT  132.876 0.108 132.894 0.187 ;
     RECT  134.172 0.108 134.19 0.187 ;
     RECT  135.432 0.108 135.45 0.187 ;
     RECT  136.728 0.108 136.746 0.187 ;
     RECT  138.024 0.108 138.042 0.187 ;
     RECT  140.58 0.108 140.598 0.187 ;
     RECT  141.876 0.108 141.894 0.187 ;
     RECT  143.136 0.108 143.154 0.187 ;
     RECT  144.432 0.108 144.45 0.187 ;
     RECT  148.284 0.108 148.302 0.187 ;
     RECT  150.84 0.108 150.858 0.187 ;
     RECT  152.136 0.108 152.154 0.187 ;
     RECT  167.508 0.108 167.526 0.187 ;
     RECT  7.2 0.108 7.218 0.523 ;
     RECT  8.496 0.108 8.514 0.523 ;
     RECT  27.72 0.187 29.034 0.571 ;
     RECT  45.684 0.139 45.774 0.571 ;
     RECT  86.436 0.187 86.742 0.571 ;
     RECT  87.984 0.108 88.002 0.571 ;
     RECT  104.652 0.108 104.67 0.571 ;
     RECT  118.764 0.108 118.782 0.571 ;
     RECT  120.06 0.108 120.078 0.571 ;
     RECT  122.616 0.108 122.634 0.571 ;
     RECT  143.892 0.187 144.45 0.571 ;
     RECT  145.692 0.108 145.71 0.571 ;
     RECT  7.2 0.523 8.514 1.147 ;
     RECT  12.312 0.108 12.33 1.147 ;
     RECT  13.608 0.108 13.626 1.147 ;
     RECT  16.164 0.187 17.478 1.147 ;
     RECT  18.756 0.187 20.034 1.147 ;
     RECT  21.384 0.167 21.402 1.147 ;
     RECT  22.572 0.108 22.59 1.147 ;
     RECT  23.868 0.187 25.182 1.147 ;
     RECT  34.128 0.108 34.146 1.147 ;
     RECT  35.424 0.187 36.702 1.147 ;
     RECT  37.98 0.108 37.998 1.147 ;
     RECT  39.276 0.108 39.294 1.147 ;
     RECT  49.536 0.108 49.554 1.147 ;
     RECT  50.796 0.108 50.814 1.147 ;
     RECT  53.352 0.108 53.37 1.147 ;
     RECT  54.648 0.108 54.666 1.147 ;
     RECT  59.796 0.187 62.37 1.147 ;
     RECT  63.612 0.108 63.63 1.147 ;
     RECT  64.908 0.108 64.926 1.147 ;
     RECT  66.204 0.108 66.222 1.147 ;
     RECT  67.176 0.187 67.482 1.147 ;
     RECT  68.76 0.108 68.778 1.147 ;
     RECT  70.056 0.108 70.074 1.147 ;
     RECT  71.316 0.108 71.334 1.147 ;
     RECT  73.872 0.108 73.89 1.147 ;
     RECT  75.168 0.108 75.186 1.147 ;
     RECT  76.464 0.108 76.482 1.147 ;
     RECT  77.724 0.108 77.742 1.147 ;
     RECT  79.02 0.108 79.038 1.147 ;
     RECT  80.316 0.108 80.334 1.147 ;
     RECT  85.428 0.108 85.446 1.147 ;
     RECT  89.28 0.108 89.298 1.147 ;
     RECT  90.576 0.108 90.594 1.147 ;
     RECT  93.132 0.108 93.15 1.147 ;
     RECT  95.688 0.108 95.706 1.147 ;
     RECT  100.836 0.187 102.114 1.147 ;
     RECT  105.948 0.108 105.966 1.147 ;
     RECT  108.504 0.108 108.522 1.147 ;
     RECT  109.8 0.108 109.818 1.147 ;
     RECT  111.096 0.108 111.114 1.147 ;
     RECT  112.356 0.108 112.374 1.147 ;
     RECT  114.912 0.108 114.93 1.147 ;
     RECT  116.208 0.108 116.226 1.147 ;
     RECT  117.504 0.108 117.522 1.147 ;
     RECT  118.764 0.571 120.078 1.147 ;
     RECT  121.356 0.108 121.374 1.147 ;
     RECT  130.32 0.108 130.338 1.147 ;
     RECT  131.616 0.187 134.19 1.147 ;
     RECT  135.432 0.187 138.042 1.147 ;
     RECT  139.284 0.108 139.302 1.147 ;
     RECT  146.988 0.108 147.006 1.147 ;
     RECT  149.544 0.108 149.562 1.147 ;
     RECT  154.692 0.108 154.71 1.147 ;
     RECT  155.952 0.108 155.97 1.147 ;
     RECT  157.248 0.108 157.266 1.147 ;
     RECT  158.544 0.108 158.562 1.147 ;
     RECT  159.804 0.108 159.822 1.147 ;
     RECT  161.1 0.108 161.118 1.147 ;
     RECT  162.396 0.108 162.414 1.147 ;
     RECT  163.728 0.167 163.746 1.147 ;
     RECT  164.952 0.108 164.97 1.147 ;
     RECT  166.212 0.108 166.23 1.147 ;
     RECT  167.508 0.187 168.174 1.147 ;
     RECT  5.436 0.187 5.922 1.723 ;
     RECT  12.132 1.147 12.33 1.723 ;
     RECT  13.104 1.147 13.626 1.723 ;
     RECT  23.436 1.147 25.182 1.723 ;
     RECT  25.956 0.187 26.442 1.723 ;
     RECT  27.216 0.571 29.034 1.723 ;
     RECT  30.276 0.108 30.294 1.723 ;
     RECT  31.212 0.187 31.59 1.723 ;
     RECT  40.176 0.187 40.554 1.723 ;
     RECT  41.364 0.187 44.406 1.723 ;
     RECT  50.76 1.147 50.814 1.723 ;
     RECT  51.624 0.187 52.11 1.723 ;
     RECT  53.28 1.147 53.37 1.723 ;
     RECT  56.736 0.187 57.222 1.723 ;
     RECT  57.996 0.187 58.518 1.723 ;
     RECT  59.4 1.147 62.37 1.723 ;
     RECT  63.432 1.147 63.63 1.723 ;
     RECT  64.404 1.147 64.926 1.723 ;
     RECT  71.208 1.147 71.334 1.723 ;
     RECT  72.18 0.187 72.63 1.723 ;
     RECT  77.652 1.147 77.742 1.723 ;
     RECT  78.84 1.147 79.038 1.723 ;
     RECT  86.436 0.571 88.002 1.723 ;
     RECT  88.956 1.147 89.298 1.723 ;
     RECT  94.392 0.108 94.41 1.723 ;
     RECT  95.472 1.147 95.706 1.723 ;
     RECT  96.48 0.187 97.002 1.723 ;
     RECT  97.848 0.187 99.558 1.723 ;
     RECT  100.368 1.147 102.114 1.723 ;
     RECT  103.032 0.187 103.41 1.723 ;
     RECT  104.22 0.571 104.67 1.723 ;
     RECT  108.432 1.147 108.522 1.723 ;
     RECT  109.62 1.147 109.818 1.723 ;
     RECT  114.696 1.147 114.93 1.723 ;
     RECT  115.776 1.147 116.226 1.723 ;
     RECT  117.072 1.147 117.522 1.723 ;
     RECT  118.692 1.147 120.078 1.723 ;
     RECT  120.888 1.147 121.374 1.723 ;
     RECT  140.112 0.187 143.154 1.723 ;
     RECT  143.892 0.571 145.71 1.723 ;
     RECT  147.996 0.187 148.302 1.723 ;
     RECT  149.508 1.147 149.562 1.723 ;
     RECT  150.372 0.187 152.154 1.723 ;
     RECT  153.396 0.108 153.414 1.723 ;
     RECT  154.584 1.147 154.71 1.723 ;
     RECT  161.028 1.147 161.118 1.723 ;
     RECT  165.996 1.147 166.23 1.723 ;
     RECT  23.436 1.723 29.034 1.751 ;
     RECT  86.436 1.723 89.298 1.751 ;
     RECT  71.208 1.723 72.63 2.065 ;
     RECT  73.764 1.147 73.89 2.065 ;
     RECT  6.84 1.147 8.514 2.101 ;
     RECT  9.288 0.187 9.774 2.101 ;
     RECT  10.728 0.187 11.07 2.101 ;
     RECT  12.132 1.723 13.626 2.101 ;
     RECT  14.4 0.187 14.922 2.101 ;
     RECT  16.092 1.147 17.478 2.101 ;
     RECT  21.312 1.147 21.402 2.101 ;
     RECT  22.284 1.147 22.59 2.101 ;
     RECT  23.436 1.751 24.534 2.101 ;
     RECT  32.328 0.187 32.85 2.101 ;
     RECT  34.128 1.147 36.702 2.101 ;
     RECT  38.988 1.147 39.294 2.101 ;
     RECT  40.176 1.723 44.406 2.101 ;
     RECT  49.068 1.147 49.554 2.101 ;
     RECT  54.324 1.147 54.666 2.101 ;
     RECT  55.764 0.187 55.962 2.101 ;
     RECT  63.432 1.723 64.926 2.101 ;
     RECT  66.204 1.147 67.482 2.101 ;
     RECT  68.508 1.147 68.778 2.101 ;
     RECT  69.66 1.147 70.074 2.101 ;
     RECT  71.208 2.065 73.89 2.101 ;
     RECT  80.172 1.147 80.334 2.101 ;
     RECT  81.252 0.187 81.594 2.101 ;
     RECT  84.924 1.147 85.446 2.101 ;
     RECT  90.288 1.147 90.594 2.101 ;
     RECT  91.584 0.187 91.854 2.101 ;
     RECT  94.392 1.723 95.706 2.101 ;
     RECT  96.48 1.723 99.558 2.101 ;
     RECT  105.732 1.147 105.966 2.101 ;
     RECT  106.812 0.187 107.262 2.101 ;
     RECT  110.808 1.147 111.114 2.101 ;
     RECT  113.112 0.187 113.67 2.101 ;
     RECT  114.696 1.723 116.226 2.101 ;
     RECT  117.072 1.723 117.63 2.101 ;
     RECT  118.692 1.723 121.374 2.101 ;
     RECT  122.292 0.571 122.634 2.101 ;
     RECT  123.588 0.187 123.93 2.101 ;
     RECT  124.776 0.187 126.486 2.101 ;
     RECT  128.772 0.187 129.042 2.101 ;
     RECT  130.032 1.147 130.338 2.101 ;
     RECT  139.104 1.147 139.302 2.101 ;
     RECT  140.112 1.723 145.71 2.101 ;
     RECT  146.7 1.147 147.006 2.101 ;
     RECT  147.996 1.723 148.374 2.101 ;
     RECT  149.508 1.723 152.154 2.101 ;
     RECT  153.396 1.723 154.89 2.101 ;
     RECT  156.924 1.147 157.266 2.101 ;
     RECT  158.004 1.147 158.562 2.101 ;
     RECT  159.66 1.147 159.822 2.101 ;
     RECT  161.028 1.723 161.298 2.101 ;
     RECT  162.036 1.147 162.414 2.101 ;
     RECT  32.328 2.101 37.17 2.129 ;
     RECT  49.068 2.101 49.95 2.129 ;
     RECT  139.104 2.101 145.71 2.129 ;
     RECT  25.38 1.751 29.034 2.143 ;
     RECT  54.324 2.101 55.962 2.143 ;
     RECT  56.736 1.723 58.518 2.143 ;
     RECT  77.652 1.723 77.922 2.143 ;
     RECT  82.44 0.187 82.89 2.143 ;
     RECT  83.628 0.187 84.15 2.143 ;
     RECT  94.392 2.101 99.558 2.143 ;
     RECT  100.368 1.723 102.294 2.143 ;
     RECT  103.032 1.723 104.886 2.143 ;
     RECT  105.732 2.101 107.262 2.143 ;
     RECT  109.62 1.723 109.89 2.143 ;
     RECT  110.808 2.101 111.186 2.143 ;
     RECT  123.588 2.101 126.486 2.143 ;
     RECT  127.332 0.187 127.782 2.143 ;
     RECT  156.924 2.101 158.562 2.143 ;
     RECT  159.66 2.101 161.298 2.143 ;
     RECT  163.656 1.147 163.746 2.143 ;
     RECT  164.736 1.147 164.97 2.143 ;
     RECT  53.28 1.723 53.514 2.191 ;
     RECT  54.324 2.143 58.518 2.191 ;
     RECT  78.84 1.723 79.11 2.191 ;
     RECT  80.172 2.101 81.594 2.191 ;
     RECT  88.272 1.751 89.298 2.191 ;
     RECT  90.288 2.101 91.854 2.191 ;
     RECT  113.112 2.101 117.63 2.191 ;
     RECT  118.692 2.101 122.634 2.191 ;
     RECT  165.996 1.723 166.338 2.191 ;
     RECT  167.076 1.147 168.174 2.191 ;
     RECT  38.988 2.101 44.73 2.219 ;
     RECT  66.204 2.101 68.778 2.219 ;
     RECT  82.44 2.143 84.15 2.219 ;
     RECT  84.924 2.101 85.59 2.219 ;
     RECT  88.272 2.191 91.854 2.219 ;
     RECT  94.215 2.143 102.294 2.219 ;
     RECT  113.112 2.191 122.634 2.219 ;
     RECT  128.772 2.101 130.338 2.219 ;
     RECT  140.904 2.129 145.71 2.219 ;
     RECT  149.508 2.101 154.89 2.219 ;
     RECT  30.24 1.723 31.59 2.227 ;
     RECT  32.328 2.129 33.426 2.227 ;
     RECT  46.656 0.187 46.962 2.227 ;
     RECT  47.772 0.187 48.258 2.227 ;
     RECT  83.232 2.219 84.15 2.227 ;
     RECT  84.924 2.219 85.554 2.227 ;
     RECT  86.436 1.751 87.39 2.227 ;
     RECT  162.036 2.101 162.918 2.227 ;
     RECT  163.656 2.143 164.97 2.227 ;
     RECT  5.436 1.723 6.102 2.263 ;
     RECT  6.84 2.101 9.774 2.263 ;
     RECT  25.38 2.143 29.505 2.263 ;
     RECT  30.24 2.227 33.426 2.263 ;
     RECT  34.2 2.129 37.17 2.263 ;
     RECT  37.908 1.147 37.998 2.263 ;
     RECT  50.76 1.723 52.398 2.263 ;
     RECT  53.28 2.191 58.518 2.263 ;
     RECT  63.432 2.101 65.034 2.263 ;
     RECT  69.66 2.101 73.89 2.263 ;
     RECT  75.924 1.147 76.482 2.263 ;
     RECT  77.652 2.143 78.105 2.263 ;
     RECT  78.84 2.191 81.594 2.263 ;
     RECT  108.432 1.723 108.702 2.263 ;
     RECT  118.008 2.219 122.634 2.263 ;
     RECT  123.588 2.143 127.782 2.263 ;
     RECT  129.024 2.219 130.338 2.263 ;
     RECT  131.256 1.147 134.19 2.263 ;
     RECT  146.7 2.101 148.374 2.263 ;
     RECT  165.996 2.191 168.174 2.263 ;
     RECT  69.156 2.263 73.89 2.299 ;
     RECT  10.728 2.101 14.922 2.335 ;
     RECT  16.092 2.101 17.766 2.335 ;
     RECT  18.504 1.147 20.034 2.335 ;
     RECT  49.068 2.129 49.086 2.335 ;
     RECT  59.4 1.723 62.694 2.335 ;
     RECT  63.432 2.263 65.178 2.335 ;
     RECT  74.88 1.147 75.186 2.335 ;
     RECT  75.924 2.263 81.594 2.335 ;
     RECT  92.916 1.147 93.15 2.335 ;
     RECT  103.032 2.143 107.262 2.335 ;
     RECT  108.324 2.263 108.702 2.335 ;
     RECT  144.252 2.219 145.71 2.335 ;
     RECT  149.508 2.219 154.746 2.335 ;
     RECT  155.628 1.147 155.97 2.335 ;
     RECT  156.924 2.143 161.298 2.335 ;
     RECT  10.728 2.335 14.958 2.371 ;
     RECT  15.948 2.335 20.034 2.371 ;
     RECT  50.76 2.263 58.518 2.371 ;
     RECT  59.4 2.335 65.178 2.371 ;
     RECT  69.156 2.299 74.106 2.371 ;
     RECT  74.88 2.335 81.594 2.371 ;
     RECT  82.332 2.227 82.35 2.371 ;
     RECT  92.916 2.335 93.222 2.371 ;
     RECT  102.312 2.335 107.262 2.371 ;
     RECT  118.008 2.263 127.782 2.371 ;
     RECT  144.252 2.335 145.746 2.371 ;
     RECT  146.7 2.263 148.554 2.371 ;
     RECT  155.484 2.335 155.97 2.371 ;
     RECT  156.78 2.335 161.298 2.371 ;
     RECT  162.036 2.227 164.97 2.371 ;
     RECT  2.415 2.143 2.505 2.413 ;
     RECT  45.504 0.571 45.774 2.413 ;
     RECT  169.815 2.143 169.905 2.413 ;
     RECT  5.436 2.263 9.774 2.461 ;
     RECT  118.008 2.371 127.89 2.461 ;
     RECT  5.436 2.461 9.918 2.489 ;
     RECT  10.728 2.371 20.034 2.489 ;
     RECT  34.2 2.263 38.538 2.489 ;
     RECT  49.032 2.335 49.086 2.489 ;
     RECT  50.76 2.371 65.178 2.489 ;
     RECT  98.64 2.219 101.466 2.489 ;
     RECT  118.008 2.461 128.142 2.489 ;
     RECT  129.024 2.263 134.19 2.489 ;
     RECT  140.904 2.219 143.442 2.489 ;
     RECT  133.2 2.489 134.19 2.561 ;
     RECT  6.3 2.489 9.918 2.569 ;
     RECT  10.728 2.489 16.686 2.569 ;
     RECT  133.272 2.561 134.19 2.597 ;
     RECT  4.644 0.108 4.662 2.605 ;
     RECT  17.424 2.489 20.034 2.605 ;
     RECT  39.348 2.219 44.73 2.605 ;
     RECT  45.504 2.413 45.897 2.605 ;
     RECT  46.656 2.227 48.258 2.605 ;
     RECT  86.328 2.227 87.39 2.605 ;
     RECT  88.272 2.219 91.458 2.605 ;
     RECT  112.248 1.147 112.374 2.605 ;
     RECT  155.484 2.371 164.97 2.605 ;
     RECT  21.312 2.101 24.534 2.641 ;
     RECT  25.38 2.263 33.426 2.641 ;
     RECT  39.348 2.605 45.897 2.641 ;
     RECT  46.656 2.605 48.546 2.641 ;
     RECT  49.824 2.129 49.95 2.641 ;
     RECT  50.76 2.489 53.694 2.641 ;
     RECT  102.312 2.371 107.586 2.641 ;
     RECT  108.324 2.335 108.81 2.641 ;
     RECT  109.62 2.143 111.186 2.641 ;
     RECT  112.14 2.605 112.374 2.641 ;
     RECT  113.112 2.219 116.946 2.641 ;
     RECT  144.252 2.371 148.554 2.641 ;
     RECT  149.4 2.335 154.746 2.641 ;
     RECT  165.996 2.263 168.39 2.641 ;
     RECT  92.196 2.371 93.222 2.731 ;
     RECT  94.215 2.219 95.346 2.731 ;
     RECT  139.104 2.129 140.13 2.731 ;
     RECT  155.484 2.605 165.006 2.731 ;
     RECT  165.96 2.641 168.57 2.731 ;
     RECT  4.572 2.605 4.662 2.759 ;
     RECT  6.3 2.569 16.686 2.759 ;
     RECT  21.312 2.641 33.426 2.759 ;
     RECT  49.824 2.641 53.694 2.759 ;
     RECT  86.328 2.605 91.458 2.759 ;
     RECT  112.14 2.641 116.946 2.759 ;
     RECT  133.272 2.597 133.47 2.759 ;
     RECT  144.252 2.641 154.746 2.759 ;
     RECT  83.232 2.227 85.554 2.795 ;
     RECT  146.556 2.759 154.746 2.831 ;
     RECT  155.484 2.731 168.57 2.861 ;
     RECT  66.204 2.219 68.418 2.875 ;
     RECT  102.312 2.641 108.81 2.875 ;
     RECT  109.62 2.641 111.33 2.875 ;
     RECT  135.144 1.147 138.042 2.875 ;
     RECT  5.436 2.489 5.49 2.911 ;
     RECT  17.424 2.605 20.538 2.911 ;
     RECT  21.312 2.759 32.67 2.911 ;
     RECT  34.2 2.489 35.19 2.911 ;
     RECT  49.824 2.759 53.622 2.911 ;
     RECT  102.312 2.875 111.33 2.911 ;
     RECT  112.14 2.759 114.678 2.911 ;
     RECT  134.244 2.605 134.334 2.911 ;
     RECT  135.144 2.875 138.186 2.911 ;
     RECT  138.96 2.731 140.13 2.911 ;
     RECT  140.904 2.489 143.406 2.911 ;
     RECT  54.432 2.489 65.178 3.001 ;
     RECT  66.168 2.875 68.418 3.001 ;
     RECT  4.932 2.911 5.49 3.029 ;
     RECT  6.3 2.759 14.454 3.029 ;
     RECT  35.928 2.489 38.538 3.029 ;
     RECT  69.156 2.371 82.35 3.029 ;
     RECT  92.196 2.731 95.346 3.029 ;
     RECT  120.204 2.489 128.142 3.029 ;
     RECT  149.472 2.831 154.746 3.029 ;
     RECT  155.484 2.861 158.202 3.029 ;
     RECT  75.204 3.029 82.35 3.145 ;
     RECT  83.232 2.795 83.754 3.145 ;
     RECT  84.492 2.795 85.554 3.145 ;
     RECT  86.328 2.759 86.382 3.145 ;
     RECT  120.456 3.029 128.142 3.145 ;
     RECT  144.252 2.759 145.818 3.145 ;
     RECT  37.296 3.029 38.538 3.181 ;
     RECT  39.348 2.641 48.546 3.181 ;
     RECT  54.432 3.001 68.418 3.181 ;
     RECT  69.156 3.029 74.394 3.181 ;
     RECT  87.336 2.759 91.458 3.181 ;
     RECT  92.196 3.029 94.497 3.181 ;
     RECT  96.3 2.219 97.722 3.181 ;
     RECT  98.856 2.489 101.466 3.181 ;
     RECT  118.008 2.489 119.466 3.181 ;
     RECT  120.456 3.145 128.178 3.181 ;
     RECT  151.56 3.029 154.746 3.181 ;
     RECT  155.484 3.029 158.166 3.181 ;
     RECT  15.408 2.759 16.686 3.271 ;
     RECT  17.424 2.911 32.67 3.271 ;
     RECT  6.3 3.029 10.998 3.299 ;
     RECT  49.536 2.911 53.622 3.299 ;
     RECT  84.492 3.145 86.382 3.299 ;
     RECT  95.292 3.029 95.346 3.299 ;
     RECT  158.94 2.861 168.57 3.299 ;
     RECT  54.432 3.181 74.394 3.307 ;
     RECT  98.856 3.181 101.502 3.307 ;
     RECT  102.312 2.911 114.678 3.307 ;
     RECT  134.244 2.911 138.186 3.307 ;
     RECT  138.96 2.911 143.406 3.307 ;
     RECT  6.3 3.299 10.458 3.335 ;
     RECT  75.204 3.145 83.754 3.335 ;
     RECT  161.316 3.299 168.354 3.335 ;
     RECT  15.408 3.271 32.67 3.371 ;
     RECT  54.396 3.307 74.394 3.371 ;
     RECT  96.3 3.181 97.938 3.379 ;
     RECT  120.456 3.181 128.286 3.379 ;
     RECT  129.024 2.489 129.978 3.379 ;
     RECT  130.752 2.489 132.297 3.379 ;
     RECT  37.296 3.181 48.546 3.403 ;
     RECT  5.256 3.029 5.49 3.415 ;
     RECT  6.3 3.335 10.206 3.415 ;
     RECT  96.12 3.379 97.938 3.451 ;
     RECT  98.784 3.307 114.678 3.451 ;
     RECT  120.456 3.379 132.354 3.451 ;
     RECT  85.248 3.299 86.382 3.541 ;
     RECT  96.12 3.451 114.678 3.541 ;
     RECT  144.216 3.145 145.818 3.541 ;
     RECT  146.556 2.831 148.698 3.541 ;
     RECT  15.408 3.371 26.154 3.569 ;
     RECT  61.164 3.371 74.394 3.569 ;
     RECT  95.616 3.541 114.678 3.569 ;
     RECT  134.244 3.307 143.406 3.569 ;
     RECT  167.004 3.335 168.354 3.569 ;
     RECT  61.164 3.569 68.31 3.605 ;
     RECT  120.456 3.451 132.39 3.605 ;
     RECT  161.316 3.335 165.978 3.605 ;
     RECT  167.004 3.569 168.138 3.605 ;
     RECT  11.772 3.029 14.454 3.613 ;
     RECT  15.408 3.569 16.182 3.613 ;
     RECT  49.968 3.299 53.622 3.685 ;
     RECT  54.396 3.371 60.426 3.685 ;
     RECT  80.064 3.335 83.754 3.685 ;
     RECT  84.492 3.299 84.51 3.685 ;
     RECT  104.076 3.569 114.678 3.685 ;
     RECT  115.74 2.759 116.946 3.685 ;
     RECT  117.792 3.181 119.466 3.685 ;
     RECT  139.428 3.569 143.406 3.685 ;
     RECT  144.216 3.541 148.698 3.685 ;
     RECT  158.94 3.299 160.578 3.685 ;
     RECT  26.928 3.371 32.67 3.721 ;
     RECT  33.444 2.911 35.19 3.721 ;
     RECT  37.296 3.403 48.582 3.721 ;
     RECT  115.74 3.685 119.466 3.721 ;
     RECT  61.236 3.605 68.31 3.749 ;
     RECT  26.928 3.721 35.262 3.811 ;
     RECT  36.036 3.029 36.234 3.811 ;
     RECT  5.256 3.415 10.206 3.839 ;
     RECT  26.928 3.811 36.234 3.839 ;
     RECT  61.236 3.749 63.666 3.839 ;
     RECT  64.404 3.749 68.31 3.839 ;
     RECT  71.46 3.569 74.394 3.839 ;
     RECT  75.204 3.335 79.29 3.839 ;
     RECT  87.336 3.181 94.497 3.839 ;
     RECT  104.076 3.685 114.858 3.839 ;
     RECT  167.004 3.605 167.166 3.839 ;
     RECT  167.976 3.605 168.138 3.839 ;
     RECT  149.472 3.029 150.822 3.847 ;
     RECT  151.56 3.181 158.166 3.847 ;
     RECT  5.256 3.839 5.562 3.875 ;
     RECT  61.236 3.839 63.594 3.875 ;
     RECT  69.084 3.569 70.722 3.875 ;
     RECT  80.064 3.685 84.51 3.875 ;
     RECT  87.336 3.839 89.262 3.875 ;
     RECT  104.076 3.839 113.886 3.875 ;
     RECT  90 3.839 94.497 3.883 ;
     RECT  114.66 3.839 114.858 3.883 ;
     RECT  115.704 3.721 119.466 3.883 ;
     RECT  134.244 3.569 138.69 3.883 ;
     RECT  162.396 3.605 165.978 3.911 ;
     RECT  133.38 2.759 133.398 3.931 ;
     RECT  134.208 3.883 138.69 3.931 ;
     RECT  80.064 3.875 81.882 3.983 ;
     RECT  114.66 3.883 119.502 3.983 ;
     RECT  161.316 3.605 161.514 3.983 ;
     RECT  162.396 3.911 165.69 3.983 ;
     RECT  37.296 3.721 49.194 3.991 ;
     RECT  85.248 3.541 86.562 3.991 ;
     RECT  87.336 3.875 87.426 3.991 ;
     RECT  4.32 3.721 4.482 4.013 ;
     RECT  6.336 3.839 10.206 4.081 ;
     RECT  34.56 3.839 36.234 4.081 ;
     RECT  36.972 3.991 49.194 4.081 ;
     RECT  128.124 3.605 132.39 4.081 ;
     RECT  5.4 3.875 5.562 4.109 ;
     RECT  6.336 4.081 10.278 4.109 ;
     RECT  26.928 3.839 33.786 4.109 ;
     RECT  49.968 3.685 60.426 4.109 ;
     RECT  64.404 3.839 68.202 4.109 ;
     RECT  75.852 3.839 79.29 4.109 ;
     RECT  114.66 3.983 117.45 4.109 ;
     RECT  120.456 3.605 127.386 4.109 ;
     RECT  133.38 3.931 138.69 4.109 ;
     RECT  139.428 3.685 148.698 4.109 ;
     RECT  158.904 3.685 160.578 4.109 ;
     RECT  162.432 3.983 165.69 4.109 ;
     RECT  74.124 3.839 74.394 4.123 ;
     RECT  6.516 4.109 10.278 4.145 ;
     RECT  16.92 3.569 26.154 4.145 ;
     RECT  34.56 4.081 49.194 4.145 ;
     RECT  80.172 3.983 81.882 4.145 ;
     RECT  74.124 4.123 74.898 4.157 ;
     RECT  90 3.883 94.806 4.217 ;
     RECT  148.215 4.109 148.698 4.225 ;
     RECT  149.472 3.847 158.166 4.225 ;
     RECT  158.904 4.109 160.542 4.225 ;
     RECT  104.076 3.875 113.778 4.253 ;
     RECT  120.888 4.109 127.386 4.253 ;
     RECT  137.232 4.109 138.69 4.253 ;
     RECT  76.356 4.109 79.29 4.261 ;
     RECT  82.908 3.875 84.51 4.261 ;
     RECT  85.248 3.991 87.426 4.261 ;
     RECT  118.188 3.983 119.502 4.261 ;
     RECT  148.215 4.225 148.734 4.261 ;
     RECT  149.472 4.225 160.542 4.261 ;
     RECT  167.004 3.839 167.13 4.261 ;
     RECT  90 4.217 90.018 4.289 ;
     RECT  95.616 3.569 100.098 4.289 ;
     RECT  114.696 4.109 117.45 4.289 ;
     RECT  11.772 3.613 16.182 4.301 ;
     RECT  76.356 4.261 79.362 4.301 ;
     RECT  95.616 4.289 98.01 4.301 ;
     RECT  17.1 4.145 26.154 4.379 ;
     RECT  38.412 4.145 49.194 4.379 ;
     RECT  66.744 4.109 68.058 4.379 ;
     RECT  71.46 3.839 73.386 4.379 ;
     RECT  90.792 4.217 94.806 4.379 ;
     RECT  95.616 4.301 95.742 4.379 ;
     RECT  98.856 4.289 100.098 4.379 ;
     RECT  110.088 4.253 113.778 4.379 ;
     RECT  133.38 4.109 136.386 4.379 ;
     RECT  148.215 4.261 160.542 4.379 ;
     RECT  166.968 4.261 167.13 4.379 ;
     RECT  167.976 3.839 168.102 4.379 ;
     RECT  61.308 3.875 63.594 4.397 ;
     RECT  6.66 4.145 10.278 4.415 ;
     RECT  17.1 4.379 20.934 4.415 ;
     RECT  21.852 4.379 26.154 4.415 ;
     RECT  70.596 3.875 70.722 4.415 ;
     RECT  90.792 4.379 93.366 4.415 ;
     RECT  95.616 4.379 95.634 4.415 ;
     RECT  110.088 4.379 110.79 4.415 ;
     RECT  111.528 4.379 113.778 4.415 ;
     RECT  120.888 4.253 124.614 4.415 ;
     RECT  136.296 4.379 136.386 4.415 ;
     RECT  139.428 4.109 147.474 4.415 ;
     RECT  148.215 4.379 150.966 4.415 ;
     RECT  151.776 4.379 160.47 4.415 ;
     RECT  167.976 4.379 167.994 4.415 ;
     RECT  7.74 4.415 10.278 4.423 ;
     RECT  49.968 4.109 57.186 4.423 ;
     RECT  166.968 4.379 167.058 4.445 ;
     RECT  7.74 4.423 10.458 4.451 ;
     RECT  21.852 4.415 25.362 4.451 ;
     RECT  76.5 4.301 79.362 4.451 ;
     RECT  71.46 4.379 73.35 4.459 ;
     RECT  120.888 4.415 123.21 4.487 ;
     RECT  128.124 4.081 132.462 4.487 ;
     RECT  133.38 4.379 135.486 4.487 ;
     RECT  140.544 4.415 147.474 4.487 ;
     RECT  148.215 4.415 149.706 4.487 ;
     RECT  151.776 4.415 159.297 4.487 ;
     RECT  160.452 4.415 160.47 4.487 ;
     RECT  38.556 4.379 49.194 4.495 ;
     RECT  49.932 4.423 57.186 4.495 ;
     RECT  100.944 3.569 101.25 4.495 ;
     RECT  102.024 3.569 103.338 4.495 ;
     RECT  125.424 4.253 127.386 4.495 ;
     RECT  128.124 4.487 132.297 4.495 ;
     RECT  99.615 4.379 100.098 4.507 ;
     RECT  100.944 4.495 103.338 4.507 ;
     RECT  38.556 4.495 57.186 4.523 ;
     RECT  139.428 4.415 139.806 4.523 ;
     RECT  7.815 4.451 10.458 4.531 ;
     RECT  26.136 4.415 26.154 4.531 ;
     RECT  26.928 4.109 28.242 4.531 ;
     RECT  99.615 4.507 103.338 4.531 ;
     RECT  104.076 4.253 109.134 4.531 ;
     RECT  38.556 4.523 56.754 4.541 ;
     RECT  82.908 4.261 87.426 4.541 ;
     RECT  91.476 4.415 93.366 4.541 ;
     RECT  114.84 4.289 117.45 4.541 ;
     RECT  118.188 4.261 120.15 4.541 ;
     RECT  125.424 4.495 132.297 4.541 ;
     RECT  140.544 4.487 143.946 4.541 ;
     RECT  7.815 4.531 11.178 4.559 ;
     RECT  26.136 4.531 28.242 4.559 ;
     RECT  34.56 4.145 37.494 4.559 ;
     RECT  38.556 4.541 52.398 4.559 ;
     RECT  53.136 4.541 56.754 4.559 ;
     RECT  66.744 4.379 67.914 4.559 ;
     RECT  70.74 4.459 73.35 4.559 ;
     RECT  81.684 4.145 81.882 4.559 ;
     RECT  133.38 4.487 134.226 4.603 ;
     RECT  29.304 4.109 33.786 4.648 ;
     RECT  34.56 4.559 37.206 4.648 ;
     RECT  39.672 4.559 49.626 4.649 ;
     RECT  61.308 4.397 63.486 4.649 ;
     RECT  64.404 4.109 65.718 4.649 ;
     RECT  67.176 4.559 67.842 4.649 ;
     RECT  71.46 4.559 73.35 4.649 ;
     RECT  93.276 4.541 93.366 4.649 ;
     RECT  99.615 4.531 109.134 4.649 ;
     RECT  118.188 4.541 118.314 4.649 ;
     RECT  128.664 4.541 132.297 4.649 ;
     RECT  133.056 4.603 134.226 4.649 ;
     RECT  139.536 4.523 139.806 4.649 ;
     RECT  69.084 3.875 69.822 4.651 ;
     RECT  26.352 4.559 28.242 4.685 ;
     RECT  29.304 4.648 37.206 4.685 ;
     RECT  39.672 4.649 47.934 4.685 ;
     RECT  64.404 4.649 65.61 4.685 ;
     RECT  71.46 4.649 73.278 4.685 ;
     RECT  93.276 4.649 93.294 4.685 ;
     RECT  118.188 4.649 118.206 4.685 ;
     RECT  120.888 4.487 122.886 4.685 ;
     RECT  128.664 4.649 129.402 4.685 ;
     RECT  166.968 4.445 167.022 4.685 ;
     RECT  68.868 4.651 69.822 4.691 ;
     RECT  102.204 4.649 105.297 4.721 ;
     RECT  107.748 4.649 109.134 4.721 ;
     RECT  148.215 4.487 149.67 4.721 ;
     RECT  71.46 4.685 72.99 4.733 ;
     RECT  7.815 4.559 10.278 4.793 ;
     RECT  17.1 4.415 20.898 4.793 ;
     RECT  128.7 4.685 129.402 4.793 ;
     RECT  58.248 4.109 60.426 4.829 ;
     RECT  167.004 4.685 167.022 4.829 ;
     RECT  121.032 4.685 122.886 4.877 ;
     RECT  29.304 4.685 33.786 4.919 ;
     RECT  82.908 4.541 87.39 4.919 ;
     RECT  99.615 4.649 101.25 4.919 ;
     RECT  82.908 4.919 87.282 4.955 ;
     RECT  99.615 4.919 101.142 4.955 ;
     RECT  61.308 4.649 63.378 4.973 ;
     RECT  64.404 4.685 65.574 4.973 ;
     RECT  67.176 4.649 67.77 4.973 ;
     RECT  88.164 3.875 89.262 5.459 ;
     RECT  60.12 4.829 60.426 5.495 ;
     RECT  38.808 4.559 38.862 5.611 ;
     RECT  27.324 4.685 28.242 5.971 ;
     RECT  29.304 4.919 31.914 5.971 ;
     RECT  80.172 4.145 80.838 6.029 ;
     RECT  67.176 4.973 67.497 6.523 ;
     RECT  64.404 4.973 65.178 6.575 ;
     RECT  76.5 4.451 79.254 6.605 ;
     RECT  66.708 6.523 67.497 6.653 ;
     RECT  70.596 6.619 70.614 6.656 ;
     RECT  71.46 4.733 72.897 6.691 ;
     RECT  74.196 4.157 74.898 6.817 ;
     RECT  70.956 6.691 72.897 6.845 ;
     RECT  115.272 4.541 117.45 6.845 ;
     RECT  82.908 4.955 86.922 7.151 ;
     RECT  22.536 4.451 25.362 7.159 ;
     RECT  136.296 4.415 136.35 7.663 ;
     RECT  137.232 4.253 138.654 7.663 ;
     RECT  128.808 4.793 129.402 7.691 ;
     RECT  17.424 4.793 20.898 7.699 ;
     RECT  71.46 6.845 72.897 7.727 ;
     RECT  83.124 7.151 86.922 8.267 ;
     RECT  136.296 7.663 138.654 8.267 ;
     RECT  71.46 7.727 71.478 8.303 ;
     RECT  130.212 4.649 132.297 8.401 ;
     RECT  133.2 4.649 134.226 8.401 ;
     RECT  22.5 7.159 25.362 8.815 ;
     RECT  26.352 4.685 26.37 8.815 ;
     RECT  22.5 8.815 26.37 8.851 ;
     RECT  69.048 4.691 69.822 8.879 ;
     RECT  130.212 8.401 134.226 9.113 ;
     RECT  81.684 4.559 81.702 9.389 ;
     RECT  140.544 4.541 143.097 9.391 ;
     RECT  143.82 4.541 143.946 9.391 ;
     RECT  69.048 8.879 69.174 9.419 ;
     RECT  6.66 4.415 6.678 9.751 ;
     RECT  27.324 5.971 31.914 9.751 ;
     RECT  6.66 9.751 7.074 9.895 ;
     RECT  7.815 4.793 8.097 9.895 ;
     RECT  32.76 4.919 33.786 9.931 ;
     RECT  34.632 4.685 37.206 9.931 ;
     RECT  9.252 4.793 10.278 10.201 ;
     RECT  8.928 10.201 10.278 10.253 ;
     RECT  22.5 8.851 26.55 10.633 ;
     RECT  27.324 9.751 31.986 10.633 ;
     RECT  32.76 9.931 37.206 10.669 ;
     RECT  6.66 9.895 8.097 10.733 ;
     RECT  76.5 6.605 78.93 10.733 ;
     RECT  121.032 4.877 121.497 10.831 ;
     RECT  122.22 4.877 122.886 10.831 ;
     RECT  110.088 4.415 110.754 10.859 ;
     RECT  48.744 4.649 49.626 11.129 ;
     RECT  102.204 4.721 103.338 11.129 ;
     RECT  125.424 4.541 127.926 11.129 ;
     RECT  72.396 7.727 72.897 11.201 ;
     RECT  110.196 10.859 110.754 11.245 ;
     RECT  111.528 4.415 111.726 11.245 ;
     RECT  112.896 4.415 113.778 11.245 ;
     RECT  78.015 10.733 78.93 11.365 ;
     RECT  98.856 4.379 98.874 11.399 ;
     RECT  102.24 11.129 103.338 11.399 ;
     RECT  106.02 4.649 106.974 11.399 ;
     RECT  108.036 4.721 109.134 11.399 ;
     RECT  78.015 11.365 79.254 11.405 ;
     RECT  99.615 4.955 101.106 11.407 ;
     RECT  115.272 6.845 116.37 11.443 ;
     RECT  117.108 6.845 117.45 11.443 ;
     RECT  96.588 4.301 98.01 11.515 ;
     RECT  99.615 11.407 101.25 11.515 ;
     RECT  104.292 4.721 105.297 11.515 ;
     RECT  106.776 11.399 106.974 11.515 ;
     RECT  108.036 11.399 108.99 11.515 ;
     RECT  96.156 11.515 98.01 11.669 ;
     RECT  112.716 11.245 113.778 11.669 ;
     RECT  115.272 11.443 117.45 11.669 ;
     RECT  130.212 9.113 132.297 11.705 ;
     RECT  76.5 10.733 77.238 11.741 ;
     RECT  61.308 4.973 62.097 11.777 ;
     RECT  125.676 11.129 127.926 11.777 ;
     RECT  96.156 11.669 96.606 11.785 ;
     RECT  115.272 11.669 116.406 11.785 ;
     RECT  119.088 4.541 120.15 11.785 ;
     RECT  90.72 11.749 90.738 11.821 ;
     RECT  110.196 11.245 111.726 11.821 ;
     RECT  112.716 11.669 113.166 11.821 ;
     RECT  126.108 11.777 127.926 11.821 ;
     RECT  128.808 7.691 129.15 11.821 ;
     RECT  53.136 4.559 56.697 11.939 ;
     RECT  83.415 8.267 86.922 11.939 ;
     RECT  90.324 11.821 90.738 11.939 ;
     RECT  96.084 11.785 96.606 11.939 ;
     RECT  97.344 11.669 98.01 11.939 ;
     RECT  98.964 11.515 101.25 11.939 ;
     RECT  88.164 5.459 89.097 11.947 ;
     RECT  96.084 11.939 96.174 11.947 ;
     RECT  118.512 11.785 120.15 11.947 ;
     RECT  126.108 11.821 129.15 11.975 ;
     RECT  94.215 4.379 94.806 11.983 ;
     RECT  56.34 11.939 56.697 12.119 ;
     RECT  102.24 11.399 103.302 12.209 ;
     RECT  118.476 11.947 120.15 12.209 ;
     RECT  123.948 4.415 124.614 12.209 ;
     RECT  126.18 11.975 129.15 12.209 ;
     RECT  74.124 6.817 74.898 12.281 ;
     RECT  130.788 11.705 132.297 12.281 ;
     RECT  121.032 10.831 122.886 12.289 ;
     RECT  120.78 12.289 122.886 12.451 ;
     RECT  85.716 11.939 86.922 12.479 ;
     RECT  94.068 11.983 94.806 12.479 ;
     RECT  117.432 11.669 117.45 12.479 ;
     RECT  118.476 12.209 119.106 12.479 ;
     RECT  123.948 12.209 124.398 12.479 ;
     RECT  126.252 12.209 129.15 12.479 ;
     RECT  80.172 6.029 80.19 12.487 ;
     RECT  91.476 4.541 92.502 12.487 ;
     RECT  120.78 12.451 122.922 12.509 ;
     RECT  91.476 12.487 92.61 12.523 ;
     RECT  118.476 12.479 118.53 12.523 ;
     RECT  128.088 12.479 129.15 12.523 ;
     RECT  83.415 11.939 84.69 12.631 ;
     RECT  83.376 12.631 84.69 12.749 ;
     RECT  91.476 12.523 92.862 12.749 ;
     RECT  74.268 12.281 74.898 12.797 ;
     RECT  45.615 4.685 47.934 12.821 ;
     RECT  81.828 11.947 81.846 12.865 ;
     RECT  90.324 11.939 90.342 12.865 ;
     RECT  79.776 12.487 80.19 12.901 ;
     RECT  83.415 12.749 84.69 12.901 ;
     RECT  83.415 12.901 84.798 12.941 ;
     RECT  128.088 12.523 129.726 12.941 ;
     RECT  88.164 11.947 89.406 12.955 ;
     RECT  78.015 11.405 78.93 13.003 ;
     RECT  79.704 12.901 80.19 13.003 ;
     RECT  83.415 12.941 84.582 13.019 ;
     RECT  87.804 12.955 89.406 13.019 ;
     RECT  128.088 12.941 129.51 13.019 ;
     RECT  78.015 13.003 80.19 13.055 ;
     RECT  83.415 13.019 84.438 13.091 ;
     RECT  128.088 13.019 129.366 13.091 ;
     RECT  85.716 12.479 86.886 13.289 ;
     RECT  128.088 13.091 129.15 13.289 ;
     RECT  76.932 11.741 77.238 13.373 ;
     RECT  132.015 12.281 132.297 13.405 ;
     RECT  45.615 12.821 47.25 13.433 ;
     RECT  50.436 4.559 52.398 13.441 ;
     RECT  53.136 11.939 55.422 13.441 ;
     RECT  131.58 13.405 132.297 13.525 ;
     RECT  133.2 9.113 134.226 13.525 ;
     RECT  45.615 13.433 46.458 13.531 ;
     RECT  131.58 13.525 134.226 13.565 ;
     RECT  45.504 13.531 46.458 13.568 ;
     RECT  90.324 12.865 90.378 13.627 ;
     RECT  85.716 13.289 86.778 13.661 ;
     RECT  38.736 5.611 38.862 13.675 ;
     RECT  39.672 4.685 43.434 13.675 ;
     RECT  83.415 13.091 84.078 13.801 ;
     RECT  32.76 10.669 37.386 13.829 ;
     RECT  83.304 13.801 84.078 13.853 ;
     RECT  136.332 8.267 138.654 13.945 ;
     RECT  139.536 4.649 139.554 13.945 ;
     RECT  74.268 12.797 74.394 13.949 ;
     RECT  64.656 6.575 65.178 13.973 ;
     RECT  135.36 4.487 135.486 13.973 ;
     RECT  83.415 13.853 84.078 13.981 ;
     RECT  83.415 13.981 84.402 14.045 ;
     RECT  130.788 12.281 130.806 14.071 ;
     RECT  130.212 14.071 130.806 14.107 ;
     RECT  38.736 13.675 43.434 14.135 ;
     RECT  129.888 14.107 130.806 14.141 ;
     RECT  85.716 13.661 86.706 14.144 ;
     RECT  129.888 14.141 129.906 14.144 ;
     RECT  88.164 13.019 89.406 14.171 ;
     RECT  124.308 12.479 124.398 14.203 ;
     RECT  7.815 10.733 8.097 14.341 ;
     RECT  9.252 10.253 10.278 14.341 ;
     RECT  38.736 14.135 38.862 14.341 ;
     RECT  48.744 11.129 48.762 14.341 ;
     RECT  49.608 11.129 49.626 14.341 ;
     RECT  126.252 12.479 127.35 14.341 ;
     RECT  7.815 14.341 10.278 14.347 ;
     RECT  11.16 4.559 11.178 14.347 ;
     RECT  7.815 14.347 11.178 14.381 ;
     RECT  48.42 14.341 49.626 14.381 ;
     RECT  125.964 14.341 127.35 14.381 ;
     RECT  38.7 14.341 38.862 14.413 ;
     RECT  44.316 4.685 44.766 14.413 ;
     RECT  48.42 14.381 48.438 14.429 ;
     RECT  9.252 14.381 11.178 14.477 ;
     RECT  36.72 13.829 37.386 14.485 ;
     RECT  38.124 14.413 38.862 14.485 ;
     RECT  44.28 14.413 44.766 14.485 ;
     RECT  95.976 11.947 96.174 14.485 ;
     RECT  97.344 11.939 97.902 14.485 ;
     RECT  39.672 14.135 43.434 14.521 ;
     RECT  44.208 14.485 44.766 14.521 ;
     RECT  140.544 9.391 143.946 14.521 ;
     RECT  144.684 4.487 147.474 14.521 ;
     RECT  78.015 13.055 78.93 14.525 ;
     RECT  64.8 13.973 65.178 14.549 ;
     RECT  130.788 14.141 130.806 14.549 ;
     RECT  124.308 14.203 124.902 14.635 ;
     RECT  90.144 13.627 90.378 14.639 ;
     RECT  124.308 14.635 125.046 14.675 ;
     RECT  92.052 12.749 92.862 14.755 ;
     RECT  102.24 12.209 102.258 14.755 ;
     RECT  102.996 12.209 103.302 14.755 ;
     RECT  115.092 11.785 116.406 14.755 ;
     RECT  92.052 14.755 93.15 14.791 ;
     RECT  115.092 14.755 116.874 14.791 ;
     RECT  50.436 13.441 55.422 14.819 ;
     RECT  91.116 14.791 91.134 14.827 ;
     RECT  92.052 14.791 93.258 14.827 ;
     RECT  91.116 14.827 93.258 14.872 ;
     RECT  94.215 12.479 94.497 14.872 ;
     RECT  115.092 14.791 116.946 14.872 ;
     RECT  118.368 12.523 118.53 14.872 ;
     RECT  32.76 13.829 35.982 14.881 ;
     RECT  36.72 14.485 38.862 14.881 ;
     RECT  17.424 7.699 21.402 14.909 ;
     RECT  32.76 14.881 38.862 14.909 ;
     RECT  39.672 14.521 44.766 14.909 ;
     RECT  91.116 14.872 94.497 14.909 ;
     RECT  95.976 14.485 97.902 14.909 ;
     RECT  115.092 14.872 118.53 14.909 ;
     RECT  32.76 14.909 37.962 14.945 ;
     RECT  126 14.381 127.35 14.957 ;
     RECT  38.736 14.909 38.862 15.025 ;
     RECT  39.672 14.909 40.662 15.025 ;
     RECT  115.092 14.909 116.946 15.053 ;
     RECT  45.615 13.568 46.458 15.061 ;
     RECT  47.232 13.433 47.25 15.061 ;
     RECT  63 4.973 63.378 15.089 ;
     RECT  126.252 14.957 127.35 15.151 ;
     RECT  128.088 13.289 128.826 15.151 ;
     RECT  94.215 14.909 94.497 15.163 ;
     RECT  115.092 15.053 116.874 15.179 ;
     RECT  119.7 15.019 119.718 15.179 ;
     RECT  135.36 13.973 135.378 15.179 ;
     RECT  126.252 15.151 128.826 15.197 ;
     RECT  91.116 14.909 93.258 15.215 ;
     RECT  91.116 15.215 93.222 15.245 ;
     RECT  94.215 15.163 94.626 15.293 ;
     RECT  91.548 15.245 93.222 15.296 ;
     RECT  81.828 12.865 82.566 15.331 ;
     RECT  83.415 14.045 84.078 15.331 ;
     RECT  102.24 14.755 103.302 15.341 ;
     RECT  115.092 15.179 116.802 15.341 ;
     RECT  41.832 14.909 44.766 15.355 ;
     RECT  45.615 15.061 47.25 15.355 ;
     RECT  81.828 15.331 84.078 15.389 ;
     RECT  106.776 11.515 107.19 15.403 ;
     RECT  107.928 11.515 108.99 15.403 ;
     RECT  50.436 14.819 55.314 15.437 ;
     RECT  17.496 14.909 21.402 15.449 ;
     RECT  92.052 15.296 93.222 15.449 ;
     RECT  106.776 15.403 108.99 15.449 ;
     RECT  140.544 14.521 147.474 15.449 ;
     RECT  92.052 15.449 93.15 15.485 ;
     RECT  19.656 15.449 21.402 15.719 ;
     RECT  63 15.089 63.018 15.755 ;
     RECT  95.976 14.909 96.606 15.961 ;
     RECT  97.344 14.909 97.902 15.961 ;
     RECT  98.964 11.939 100.278 15.961 ;
     RECT  101.124 11.939 101.142 15.961 ;
     RECT  131.58 13.565 132.297 15.961 ;
     RECT  133.2 13.565 134.226 15.961 ;
     RECT  119.988 15.331 120.006 15.979 ;
     RECT  120.78 12.509 122.886 15.979 ;
     RECT  92.052 15.485 93.078 16.013 ;
     RECT  131.58 15.961 134.226 16.013 ;
     RECT  94.215 15.293 94.497 16.024 ;
     RECT  41.832 15.355 47.25 16.025 ;
     RECT  119.988 15.979 122.886 16.025 ;
     RECT  95.976 15.961 97.902 16.027 ;
     RECT  93.924 16.024 94.497 16.061 ;
     RECT  95.976 16.027 98.01 16.061 ;
     RECT  98.964 15.961 101.142 16.061 ;
     RECT  117.468 16.024 117.486 16.061 ;
     RECT  119.988 16.025 120.006 16.061 ;
     RECT  118.44 14.909 118.53 16.141 ;
     RECT  117.936 16.141 118.53 16.205 ;
     RECT  97.344 16.061 98.01 16.219 ;
     RECT  98.964 16.061 100.278 16.219 ;
     RECT  101.124 16.061 101.142 16.231 ;
     RECT  102.24 15.341 102.258 16.231 ;
     RECT  38.736 15.025 40.662 16.259 ;
     RECT  58.248 4.829 58.914 16.259 ;
     RECT  94.176 16.061 94.497 16.301 ;
     RECT  101.124 16.231 102.258 16.301 ;
     RECT  74.376 13.949 74.394 16.331 ;
     RECT  136.332 13.945 139.554 16.375 ;
     RECT  140.616 15.449 147.474 16.375 ;
     RECT  102.06 16.301 102.258 16.445 ;
     RECT  102.996 15.341 103.302 16.501 ;
     RECT  104.256 11.515 105.786 16.501 ;
     RECT  113.904 11.785 113.922 16.501 ;
     RECT  20.592 15.719 21.402 16.537 ;
     RECT  22.5 10.633 31.986 16.537 ;
     RECT  136.332 16.375 147.474 16.537 ;
     RECT  148.215 4.721 148.986 16.537 ;
     RECT  136.332 16.537 148.986 16.565 ;
     RECT  113.904 16.501 113.994 16.681 ;
     RECT  49.608 14.381 49.626 16.771 ;
     RECT  110.196 11.821 113.166 16.795 ;
     RECT  83.415 15.389 84.078 16.807 ;
     RECT  147.024 16.565 148.986 16.807 ;
     RECT  4.464 4.013 4.482 16.835 ;
     RECT  44.388 16.025 47.25 16.835 ;
     RECT  88.164 14.171 89.334 16.835 ;
     RECT  109.908 16.795 113.166 16.835 ;
     RECT  39.672 16.259 40.662 16.843 ;
     RECT  69.048 9.419 69.066 16.871 ;
     RECT  128.088 15.197 128.826 16.871 ;
     RECT  151.776 4.487 154.206 16.871 ;
     RECT  39.672 16.843 40.806 16.915 ;
     RECT  41.832 16.025 43.434 16.915 ;
     RECT  79.776 13.055 80.19 16.925 ;
     RECT  118.368 16.205 118.53 16.951 ;
     RECT  117.9 16.951 118.53 17.032 ;
     RECT  49.068 16.771 49.626 17.035 ;
     RECT  110.196 16.835 113.166 17.035 ;
     RECT  113.904 16.681 114.282 17.035 ;
     RECT  32.76 14.945 37.386 17.041 ;
     RECT  38.736 16.259 38.862 17.041 ;
     RECT  94.215 16.301 94.497 17.041 ;
     RECT  97.344 16.219 100.278 17.041 ;
     RECT  101.124 16.301 101.142 17.041 ;
     RECT  117.9 17.032 118.566 17.069 ;
     RECT  49.068 17.035 49.698 17.075 ;
     RECT  97.344 17.041 101.142 17.075 ;
     RECT  49.068 17.075 49.626 17.105 ;
     RECT  117.9 17.069 118.53 17.105 ;
     RECT  136.332 16.565 146.034 17.105 ;
     RECT  45.615 16.835 47.25 17.113 ;
     RECT  32.76 17.041 38.862 17.117 ;
     RECT  98.928 17.075 101.142 17.117 ;
     RECT  102.996 16.501 105.786 17.117 ;
     RECT  94.215 17.041 94.626 17.185 ;
     RECT  94.215 17.185 94.95 17.275 ;
     RECT  98.964 17.117 101.142 17.275 ;
     RECT  94.215 17.275 95.13 17.339 ;
     RECT  97.344 17.075 98.082 17.339 ;
     RECT  98.964 17.275 101.286 17.339 ;
     RECT  49.392 17.105 49.626 17.375 ;
     RECT  97.344 17.339 98.01 17.375 ;
     RECT  118.224 17.105 118.53 17.375 ;
     RECT  38.34 17.117 38.862 17.405 ;
     RECT  39.672 16.915 43.434 17.405 ;
     RECT  76.932 13.373 76.95 17.411 ;
     RECT  126.252 15.197 127.35 17.411 ;
     RECT  67.176 6.653 67.497 17.447 ;
     RECT  41.832 17.405 43.434 17.455 ;
     RECT  44.388 16.835 44.766 17.455 ;
     RECT  94.215 17.339 94.95 17.609 ;
     RECT  107.928 15.449 108.99 17.611 ;
     RECT  147.024 16.807 149.598 17.617 ;
     RECT  94.215 17.609 94.806 17.645 ;
     RECT  98.964 17.339 101.142 17.645 ;
     RECT  110.196 17.035 114.282 17.693 ;
     RECT  45.615 17.113 47.43 17.851 ;
     RECT  39.672 17.405 41.022 17.879 ;
     RECT  45.504 17.851 47.43 17.888 ;
     RECT  106.776 15.449 107.19 17.923 ;
     RECT  107.928 17.611 109.314 17.923 ;
     RECT  58.896 16.259 58.914 17.951 ;
     RECT  136.332 17.105 139.662 17.951 ;
     RECT  38.736 17.405 38.862 17.959 ;
     RECT  39.672 17.879 40.878 17.959 ;
     RECT  115.092 15.341 116.406 17.959 ;
     RECT  32.76 17.117 37.386 18.031 ;
     RECT  120.78 16.025 122.886 18.091 ;
     RECT  101.124 17.645 101.142 18.121 ;
     RECT  102.24 16.445 102.258 18.121 ;
     RECT  106.74 17.923 109.314 18.121 ;
     RECT  118.44 17.375 118.53 18.121 ;
     RECT  133.2 16.013 134.226 18.149 ;
     RECT  106.74 18.121 109.458 18.157 ;
     RECT  120.384 18.091 122.886 18.187 ;
     RECT  119.952 18.187 122.886 18.227 ;
     RECT  104.256 17.117 105.786 18.265 ;
     RECT  106.596 18.157 109.458 18.265 ;
     RECT  104.256 18.265 109.458 18.301 ;
     RECT  110.196 17.693 113.958 18.301 ;
     RECT  64.8 14.549 64.818 18.329 ;
     RECT  101.124 18.121 102.258 18.379 ;
     RECT  102.996 17.117 103.302 18.379 ;
     RECT  133.2 18.149 133.686 18.419 ;
     RECT  101.124 18.379 103.302 18.427 ;
     RECT  104.256 18.301 113.958 18.427 ;
     RECT  120.06 18.227 122.886 18.455 ;
     RECT  115.092 17.959 116.658 18.463 ;
     RECT  101.124 18.427 113.958 18.535 ;
     RECT  49.608 17.375 49.626 18.571 ;
     RECT  101.124 18.535 114.102 18.571 ;
     RECT  115.092 18.463 116.694 18.571 ;
     RECT  94.215 17.645 94.497 18.619 ;
     RECT  45.615 17.888 47.43 18.661 ;
     RECT  101.124 18.571 114.174 18.661 ;
     RECT  97.344 17.375 97.902 18.667 ;
     RECT  115.092 18.571 116.766 18.667 ;
     RECT  93.636 18.619 94.497 18.689 ;
     RECT  38.736 17.959 40.878 18.697 ;
     RECT  41.832 17.455 44.766 18.697 ;
     RECT  49.104 18.571 49.626 18.697 ;
     RECT  115.092 18.667 117.45 18.725 ;
     RECT  32.76 18.031 37.926 18.769 ;
     RECT  79.776 16.925 79.794 18.769 ;
     RECT  93.96 18.689 94.497 18.769 ;
     RECT  97.344 18.667 98.226 18.769 ;
     RECT  98.964 17.645 100.278 18.769 ;
     RECT  118.404 18.121 118.53 18.769 ;
     RECT  79.704 18.769 79.794 18.797 ;
     RECT  32.76 18.769 37.962 18.805 ;
     RECT  38.736 18.697 44.766 18.805 ;
     RECT  48.888 18.697 49.626 18.805 ;
     RECT  32.76 18.805 37.998 18.841 ;
     RECT  38.736 18.805 44.874 18.841 ;
     RECT  97.344 18.769 100.278 18.841 ;
     RECT  101.124 18.661 114.246 18.841 ;
     RECT  117.864 18.769 118.53 18.907 ;
     RECT  95.976 16.061 96.174 18.931 ;
     RECT  117.864 18.907 118.962 18.931 ;
     RECT  120.78 18.455 122.886 18.967 ;
     RECT  95.652 18.931 96.174 19.003 ;
     RECT  97.344 18.841 114.246 19.003 ;
     RECT  93.96 18.769 94.626 19.039 ;
     RECT  95.652 19.003 114.246 19.039 ;
     RECT  45.615 18.661 47.718 19.075 ;
     RECT  48.528 18.805 49.626 19.075 ;
     RECT  93.96 19.039 114.246 19.075 ;
     RECT  115.092 18.725 117.09 19.075 ;
     RECT  32.76 18.841 44.874 19.111 ;
     RECT  45.615 19.075 49.626 19.111 ;
     RECT  117.864 18.931 119.25 19.195 ;
     RECT  120.78 18.967 123.498 19.201 ;
     RECT  124.308 14.675 124.398 19.201 ;
     RECT  60.12 5.495 60.138 19.229 ;
     RECT  140.616 17.105 146.034 19.229 ;
     RECT  32.76 19.111 49.626 19.265 ;
     RECT  146.016 19.229 146.034 19.345 ;
     RECT  146.988 17.617 149.598 19.345 ;
     RECT  136.476 17.951 139.662 19.387 ;
     RECT  32.76 19.265 47.826 19.499 ;
     RECT  93.96 19.075 117.09 19.543 ;
     RECT  32.76 19.499 47.43 19.571 ;
     RECT  93.78 19.543 117.09 19.579 ;
     RECT  117.864 19.195 119.502 19.579 ;
     RECT  17.496 15.449 18.897 19.651 ;
     RECT  48.78 19.265 49.626 19.651 ;
     RECT  50.436 15.437 52.398 19.651 ;
     RECT  93.78 19.579 119.502 19.651 ;
     RECT  120.78 19.201 124.398 19.651 ;
     RECT  136.188 19.387 139.662 19.651 ;
     RECT  152.532 16.871 154.206 19.679 ;
     RECT  79.704 18.797 79.722 19.741 ;
     RECT  126.615 17.411 127.35 19.741 ;
     RECT  135.864 19.651 139.662 19.769 ;
     RECT  93.78 19.651 119.61 19.777 ;
     RECT  17.424 19.651 18.897 19.805 ;
     RECT  120.708 19.651 124.398 19.813 ;
     RECT  90.324 14.639 90.378 19.849 ;
     RECT  120.708 19.813 124.47 19.849 ;
     RECT  130.284 19.813 130.302 19.849 ;
     RECT  135.72 19.813 135.738 19.853 ;
     RECT  79.524 19.741 79.722 19.885 ;
     RECT  130.284 19.849 130.41 19.885 ;
     RECT  11.988 4.301 16.182 19.921 ;
     RECT  90.324 19.849 90.918 19.921 ;
     RECT  92.052 16.013 92.862 19.921 ;
     RECT  93.78 19.777 119.682 19.921 ;
     RECT  78.015 14.525 78.297 20.011 ;
     RECT  128.088 16.871 128.574 20.011 ;
     RECT  155.016 4.487 158.166 20.039 ;
     RECT  161.388 3.983 161.514 20.039 ;
     RECT  83.34 16.807 84.078 20.047 ;
     RECT  84.852 20.011 84.87 20.047 ;
     RECT  120.672 19.849 124.47 20.047 ;
     RECT  79.488 19.885 79.722 20.083 ;
     RECT  88.815 16.835 89.334 20.083 ;
     RECT  90.324 19.921 90.954 20.083 ;
     RECT  91.944 19.921 92.862 20.083 ;
     RECT  85.716 14.144 86.274 20.119 ;
     RECT  88.596 20.083 89.334 20.119 ;
     RECT  90.324 20.083 92.862 20.119 ;
     RECT  126.252 19.741 127.35 20.119 ;
     RECT  128.088 20.011 129.258 20.119 ;
     RECT  88.596 20.119 92.862 20.149 ;
     RECT  120.672 20.047 124.614 20.152 ;
     RECT  81.828 15.389 82.566 20.155 ;
     RECT  83.34 20.047 84.87 20.155 ;
     RECT  11.988 19.921 16.362 20.191 ;
     RECT  48.78 19.651 52.398 20.191 ;
     RECT  53.136 15.437 55.314 20.191 ;
     RECT  78.015 20.011 78.57 20.191 ;
     RECT  81.828 20.155 84.87 20.191 ;
     RECT  85.716 20.119 86.31 20.191 ;
     RECT  87.516 20.011 87.534 20.191 ;
     RECT  88.596 20.149 92.934 20.191 ;
     RECT  93.78 19.921 119.718 20.191 ;
     RECT  120.672 20.152 124.974 20.191 ;
     RECT  126.252 20.119 129.258 20.191 ;
     RECT  130.248 19.885 130.41 20.191 ;
     RECT  133.2 18.419 133.218 20.219 ;
     RECT  78.015 20.191 78.75 20.281 ;
     RECT  79.488 20.083 79.938 20.281 ;
     RECT  87.516 20.191 87.822 20.281 ;
     RECT  88.596 20.191 119.718 20.281 ;
     RECT  32.76 19.571 36.954 20.299 ;
     RECT  37.692 19.571 47.43 20.299 ;
     RECT  155.124 20.039 158.166 20.309 ;
     RECT  48.78 20.191 55.314 20.381 ;
     RECT  48.78 20.381 52.254 20.389 ;
     RECT  32.76 20.299 47.43 20.425 ;
     RECT  48.276 20.389 52.254 20.425 ;
     RECT  120.672 20.191 129.474 20.425 ;
     RECT  130.212 20.191 130.41 20.425 ;
     RECT  150.48 4.415 150.786 20.425 ;
     RECT  151.776 16.871 151.794 20.425 ;
     RECT  20.592 16.537 31.986 20.461 ;
     RECT  32.76 20.425 52.254 20.461 ;
     RECT  20.592 20.461 52.254 20.489 ;
     RECT  81.828 20.191 86.31 20.539 ;
     RECT  87.516 20.281 119.718 20.539 ;
     RECT  11.988 20.191 16.65 20.573 ;
     RECT  81.756 20.539 86.31 20.581 ;
     RECT  20.592 20.489 51.93 20.615 ;
     RECT  81.756 20.581 86.67 20.621 ;
     RECT  81.756 20.621 86.31 20.623 ;
     RECT  80.82 20.539 80.838 20.659 ;
     RECT  120.672 20.425 130.41 20.695 ;
     RECT  80.676 20.659 80.838 20.717 ;
     RECT  80.712 20.717 80.838 20.731 ;
     RECT  80.712 20.731 80.982 20.821 ;
     RECT  81.72 20.623 86.31 20.821 ;
     RECT  120.672 20.695 130.446 20.929 ;
     RECT  136.584 19.769 139.662 20.929 ;
     RECT  20.592 20.615 49.158 20.957 ;
     RECT  80.712 20.821 86.31 21.029 ;
     RECT  87.516 20.539 119.934 21.029 ;
     RECT  120.672 20.929 130.59 21.029 ;
     RECT  87.516 21.029 114.858 21.119 ;
     RECT  131.58 16.013 132.297 21.127 ;
     RECT  76.968 21.091 76.986 21.191 ;
     RECT  49.896 20.615 51.93 21.235 ;
     RECT  49.896 21.235 52.002 21.271 ;
     RECT  52.992 20.381 55.314 21.271 ;
     RECT  131.58 21.127 132.426 21.271 ;
     RECT  11.988 20.573 16.182 21.355 ;
     RECT  115.815 21.029 119.934 21.361 ;
     RECT  120.672 21.029 130.518 21.361 ;
     RECT  131.58 21.271 132.534 21.361 ;
     RECT  87.516 21.119 111.546 21.389 ;
     RECT  11.988 21.355 16.722 21.395 ;
     RECT  78.015 20.281 79.938 21.397 ;
     RECT  20.592 20.957 47.358 21.425 ;
     RECT  134.532 21.259 134.55 21.437 ;
     RECT  80.964 21.029 86.31 21.505 ;
     RECT  133.776 21.199 133.794 21.505 ;
     RECT  48.168 20.957 49.158 21.541 ;
     RECT  49.896 21.271 55.314 21.541 ;
     RECT  131.58 21.361 132.606 21.541 ;
     RECT  77.904 21.397 79.938 21.631 ;
     RECT  80.964 21.505 86.526 21.643 ;
     RECT  87.516 21.389 111.366 21.643 ;
     RECT  77.832 21.631 79.938 21.725 ;
     RECT  134.568 21.631 134.586 21.739 ;
     RECT  115.815 21.361 130.518 21.787 ;
     RECT  48.168 21.541 55.314 21.811 ;
     RECT  56.415 12.119 56.697 21.811 ;
     RECT  115.815 21.787 130.554 21.811 ;
     RECT  131.58 21.541 132.642 21.811 ;
     RECT  133.38 21.505 133.794 21.811 ;
     RECT  11.16 14.477 11.178 21.901 ;
     RECT  11.988 21.395 16.182 21.901 ;
     RECT  80.964 21.643 111.366 21.901 ;
     RECT  115.815 21.811 130.662 21.901 ;
     RECT  74.664 21.163 74.682 21.931 ;
     RECT  136.584 20.929 139.77 21.937 ;
     RECT  140.616 19.229 144.81 21.937 ;
     RECT  115.776 21.901 130.662 21.965 ;
     RECT  152.532 19.679 153.897 21.965 ;
     RECT  61.815 11.777 62.097 21.979 ;
     RECT  134.568 21.739 134.838 21.979 ;
     RECT  115.776 21.965 120.006 22.001 ;
     RECT  120.744 21.965 130.662 22.001 ;
     RECT  112.284 21.119 114.858 22.027 ;
     RECT  135.72 21.937 135.738 22.027 ;
     RECT  136.584 21.937 144.81 22.027 ;
     RECT  115.776 22.001 119.322 22.045 ;
     RECT  123.444 22.001 130.662 22.073 ;
     RECT  112.284 22.027 114.894 22.081 ;
     RECT  61.815 21.979 62.73 22.109 ;
     RECT  134.568 21.979 134.91 22.171 ;
     RECT  135.72 22.027 144.81 22.171 ;
     RECT  80.82 21.901 111.366 22.199 ;
     RECT  131.58 21.811 133.794 22.207 ;
     RECT  134.568 22.171 144.81 22.207 ;
     RECT  74.664 21.931 74.754 22.219 ;
     RECT  112.212 22.081 114.894 22.219 ;
     RECT  115.704 22.045 119.322 22.219 ;
     RECT  123.552 22.073 130.662 22.219 ;
     RECT  48.168 21.811 56.697 22.235 ;
     RECT  48.168 22.235 55.278 22.243 ;
     RECT  74.664 22.219 74.79 22.243 ;
     RECT  11.16 21.901 16.182 22.271 ;
     RECT  146.016 19.345 149.598 22.271 ;
     RECT  20.592 21.425 47.178 22.279 ;
     RECT  80.82 22.199 101.142 22.307 ;
     RECT  48.096 22.243 55.278 22.343 ;
     RECT  123.552 22.219 130.806 22.363 ;
     RECT  131.58 22.207 144.81 22.363 ;
     RECT  20.592 22.279 47.322 22.441 ;
     RECT  150.48 20.425 151.794 22.469 ;
     RECT  74.664 22.243 74.862 22.493 ;
     RECT  77.04 21.787 77.058 22.507 ;
     RECT  17.496 19.805 18.897 22.513 ;
     RECT  146.916 22.271 149.598 22.513 ;
     RECT  5.544 4.109 5.562 22.541 ;
     RECT  17.172 22.513 18.897 22.549 ;
     RECT  123.552 22.363 144.81 22.549 ;
     RECT  146.016 22.271 146.034 22.549 ;
     RECT  11.16 22.271 15.714 22.577 ;
     RECT  150.552 22.469 151.794 22.577 ;
     RECT  67.215 17.447 67.497 22.585 ;
     RECT  76.968 22.507 77.058 22.621 ;
     RECT  77.904 21.725 79.938 22.621 ;
     RECT  80.82 22.307 89.298 22.621 ;
     RECT  56.304 22.235 56.697 22.637 ;
     RECT  67.104 22.585 67.497 22.637 ;
     RECT  76.968 22.621 89.298 22.637 ;
     RECT  101.916 22.199 111.366 22.699 ;
     RECT  112.212 22.219 119.322 22.699 ;
     RECT  48.096 22.343 55.206 22.775 ;
     RECT  77.508 22.637 89.298 22.775 ;
     RECT  11.16 22.577 13.497 22.781 ;
     RECT  20.592 22.441 47.358 22.783 ;
     RECT  101.916 22.699 119.322 22.783 ;
     RECT  120.744 22.001 122.634 22.795 ;
     RECT  123.552 22.549 146.034 22.795 ;
     RECT  20.592 22.783 47.394 22.811 ;
     RECT  48.204 22.775 55.206 22.811 ;
     RECT  9.252 14.477 10.278 22.819 ;
     RECT  77.508 22.775 86.094 22.847 ;
     RECT  90.216 22.307 101.142 22.883 ;
     RECT  120.744 22.795 146.034 22.891 ;
     RECT  17.1 22.549 18.897 22.919 ;
     RECT  20.592 22.811 46.242 22.919 ;
     RECT  52.452 22.811 55.206 22.925 ;
     RECT  47.016 22.811 47.394 23.009 ;
     RECT  90.432 22.883 101.142 23.009 ;
     RECT  47.088 23.009 47.394 23.045 ;
     RECT  52.488 22.925 55.206 23.045 ;
     RECT  120.708 22.891 146.034 23.069 ;
     RECT  47.16 23.045 47.394 23.081 ;
     RECT  48.204 22.811 51.354 23.081 ;
     RECT  47.196 23.081 47.358 23.117 ;
     RECT  52.56 23.045 55.206 23.117 ;
     RECT  47.34 23.117 47.358 23.153 ;
     RECT  48.276 23.081 51.354 23.153 ;
     RECT  52.596 23.117 55.206 23.153 ;
     RECT  87.012 22.775 89.298 23.161 ;
     RECT  99.576 23.009 101.142 23.161 ;
     RECT  101.916 22.783 119.394 23.161 ;
     RECT  87.012 23.161 89.658 23.165 ;
     RECT  48.78 23.153 51.354 23.189 ;
     RECT  99.576 23.161 119.394 23.189 ;
     RECT  49.212 23.189 51.354 23.279 ;
     RECT  52.74 23.153 55.206 23.279 ;
     RECT  77.508 22.847 85.95 23.279 ;
     RECT  90.432 23.009 98.838 23.279 ;
     RECT  99.615 23.189 119.394 23.279 ;
     RECT  120.708 23.069 130.626 23.279 ;
     RECT  87.012 23.165 87.966 23.309 ;
     RECT  54.684 23.279 55.062 23.315 ;
     RECT  102.24 23.279 119.394 23.315 ;
     RECT  125.964 23.279 130.626 23.315 ;
     RECT  49.356 23.279 51.354 23.351 ;
     RECT  81.828 23.279 85.878 23.351 ;
     RECT  87.012 23.309 87.93 23.351 ;
     RECT  115.74 23.315 119.394 23.351 ;
     RECT  74.664 22.493 74.682 23.357 ;
     RECT  77.508 23.279 81.09 23.357 ;
     RECT  84.96 23.351 85.878 23.357 ;
     RECT  90.432 23.279 95.202 23.357 ;
     RECT  95.976 23.279 98.766 23.357 ;
     RECT  102.24 23.315 114.966 23.357 ;
     RECT  120.708 23.279 125.154 23.357 ;
     RECT  126 23.315 128.286 23.357 ;
     RECT  19.656 15.719 19.674 23.371 ;
     RECT  20.592 22.919 46.206 23.387 ;
     RECT  49.428 23.351 51.354 23.387 ;
     RECT  87.012 23.351 87.066 23.387 ;
     RECT  17.172 22.919 18.897 23.395 ;
     RECT  19.62 23.371 19.674 23.395 ;
     RECT  49.536 23.387 51.354 23.423 ;
     RECT  85.32 23.357 85.878 23.423 ;
     RECT  115.74 23.351 119.106 23.423 ;
     RECT  77.508 23.357 80.01 23.431 ;
     RECT  87.84 23.351 87.93 23.459 ;
     RECT  95.976 23.357 98.586 23.459 ;
     RECT  104.688 23.357 114.318 23.459 ;
     RECT  56.415 22.637 56.697 23.507 ;
     RECT  61.815 22.109 62.097 23.507 ;
     RECT  67.215 22.637 67.497 23.507 ;
     RECT  72.615 11.201 72.897 23.507 ;
     RECT  11.988 22.781 13.497 23.521 ;
     RECT  14.256 22.577 15.714 23.521 ;
     RECT  76.824 23.431 80.01 23.549 ;
     RECT  82.044 23.351 84.222 23.549 ;
     RECT  85.32 23.423 85.338 23.549 ;
     RECT  95.976 23.459 96.354 23.549 ;
     RECT  108.216 23.459 114.318 23.549 ;
     RECT  118.98 23.423 119.106 23.549 ;
     RECT  104.688 23.459 107.442 23.585 ;
     RECT  119.916 23.371 119.934 23.585 ;
     RECT  11.988 23.521 15.714 23.597 ;
     RECT  76.824 23.549 77.166 23.597 ;
     RECT  77.904 23.549 80.01 23.597 ;
     RECT  90.432 23.357 94.698 23.597 ;
     RECT  120.708 23.357 125.082 23.611 ;
     RECT  129.024 23.315 130.626 23.645 ;
     RECT  42.156 23.387 46.206 23.657 ;
     RECT  87.84 23.459 87.858 23.657 ;
     RECT  43.992 23.657 46.206 23.693 ;
     RECT  90.432 23.597 92.97 23.693 ;
     RECT  97.272 23.459 98.586 23.693 ;
     RECT  119.988 23.611 125.082 23.693 ;
     RECT  129.096 23.645 130.626 23.693 ;
     RECT  131.688 23.069 146.034 23.693 ;
     RECT  88.704 23.165 89.658 23.701 ;
     RECT  90.432 23.693 90.846 23.701 ;
     RECT  52.74 23.279 53.838 23.729 ;
     RECT  104.832 23.585 107.442 23.729 ;
     RECT  108.288 23.549 112.914 23.729 ;
     RECT  115.74 23.423 118.206 23.729 ;
     RECT  120.06 23.693 125.082 23.729 ;
     RECT  131.76 23.693 146.034 23.729 ;
     RECT  43.992 23.693 44.01 23.741 ;
     RECT  93.816 23.597 94.698 23.741 ;
     RECT  104.832 23.729 106.614 23.741 ;
     RECT  107.424 23.729 107.442 23.741 ;
     RECT  120.06 23.729 125.01 23.741 ;
     RECT  51.015 23.423 51.354 23.777 ;
     RECT  61.815 23.507 61.905 23.777 ;
     RECT  72.615 23.507 72.705 23.777 ;
     RECT  78.015 23.597 80.01 23.777 ;
     RECT  82.728 23.549 84.222 23.777 ;
     RECT  93.816 23.741 94.305 23.777 ;
     RECT  99.615 23.279 101.142 23.777 ;
     RECT  105.015 23.741 106.614 23.777 ;
     RECT  115.74 23.729 115.905 23.777 ;
     RECT  126.144 23.357 128.286 23.777 ;
     RECT  132.015 23.729 146.034 23.777 ;
     RECT  91.944 23.693 92.97 23.789 ;
     RECT  98.1 23.693 98.586 23.789 ;
     RECT  45.324 23.693 46.206 23.791 ;
     RECT  56.415 23.507 56.61 23.791 ;
     RECT  67.215 23.507 67.41 23.791 ;
     RECT  129.636 23.693 130.626 23.818 ;
     RECT  20.592 23.387 41.382 23.819 ;
     RECT  102.24 23.357 103.878 23.819 ;
     RECT  120.708 23.741 125.01 23.819 ;
     RECT  40.536 23.819 41.382 23.837 ;
     RECT  56.304 23.791 56.61 23.837 ;
     RECT  67.104 23.791 67.41 23.837 ;
     RECT  88.704 23.701 90.846 23.837 ;
     RECT  20.592 23.819 39.69 23.855 ;
     RECT  105.804 23.777 106.614 23.855 ;
     RECT  108.288 23.729 112.302 23.855 ;
     RECT  116.856 23.729 118.206 23.855 ;
     RECT  40.68 23.837 41.382 23.885 ;
     RECT  42.156 23.657 42.93 23.885 ;
     RECT  45.324 23.791 46.242 23.885 ;
     RECT  116.892 23.855 118.206 23.885 ;
     RECT  45.324 23.885 45.414 23.891 ;
     RECT  74.736 23.629 74.826 23.891 ;
     RECT  78.588 23.777 80.01 23.891 ;
     RECT  117.576 23.885 118.098 23.891 ;
     RECT  120.816 23.819 125.01 23.891 ;
     RECT  42.156 23.885 42.894 23.927 ;
     RECT  45.396 23.891 45.414 23.927 ;
     RECT  74.808 23.891 74.826 23.927 ;
     RECT  78.588 23.891 78.714 23.927 ;
     RECT  120.888 23.891 125.01 23.927 ;
     RECT  129.636 23.818 130.662 23.927 ;
     RECT  132.48 23.777 146.034 23.927 ;
     RECT  17.172 23.395 19.674 23.936 ;
     RECT  79.56 23.891 80.01 23.963 ;
     RECT  118.08 23.891 118.098 23.963 ;
     RECT  49.644 23.423 50.094 23.981 ;
     RECT  129.636 23.927 130.518 23.981 ;
     RECT  108.288 23.855 111.438 23.999 ;
     RECT  42.156 23.927 42.786 24.173 ;
     RECT  113.976 23.549 114.318 24.221 ;
     RECT  9.252 22.819 10.35 24.233 ;
     RECT  92.952 23.789 92.97 24.233 ;
     RECT  119.088 23.549 119.106 24.233 ;
     RECT  40.716 23.885 41.382 24.269 ;
     RECT  91.944 23.789 91.962 24.269 ;
     RECT  112.284 23.855 112.302 24.269 ;
     RECT  120.888 23.927 122.454 24.269 ;
     RECT  84.204 23.777 84.222 24.314 ;
     RECT  120.924 24.269 122.454 24.314 ;
     RECT  110.304 23.999 111.438 24.317 ;
     RECT  80.928 23.357 81.09 24.359 ;
     RECT  78.696 23.927 78.714 24.365 ;
     RECT  97.272 23.693 97.29 24.365 ;
     RECT  126.936 23.777 128.286 24.395 ;
     RECT  49.644 23.981 49.662 24.413 ;
     RECT  98.568 23.789 98.586 24.413 ;
     RECT  53.82 23.729 53.838 24.431 ;
     RECT  46.188 23.885 46.206 24.467 ;
     RECT  40.86 24.269 41.382 24.503 ;
     RECT  52.74 23.729 52.758 24.539 ;
     RECT  99.756 23.777 101.142 24.557 ;
     RECT  105.804 23.855 106.362 24.557 ;
     RECT  108.288 23.999 109.422 24.557 ;
     RECT  110.304 24.317 110.322 24.557 ;
     RECT  129.636 23.981 129.978 24.665 ;
     RECT  51.336 23.777 51.354 24.715 ;
     RECT  82.728 23.777 83.394 24.737 ;
     RECT  14.508 23.597 15.714 24.745 ;
     RECT  108.828 24.557 109.422 24.749 ;
     RECT  76.824 23.597 76.842 24.773 ;
     RECT  14.508 24.745 15.966 24.781 ;
     RECT  6.66 10.733 6.678 24.809 ;
     RECT  51.336 24.715 51.426 24.809 ;
     RECT  150.624 22.577 151.794 24.809 ;
     RECT  89.352 23.837 90.846 24.854 ;
     RECT  123.408 23.927 124.398 24.854 ;
     RECT  14.508 24.781 16.11 24.859 ;
     RECT  80.928 24.359 80.946 24.893 ;
     RECT  99.792 24.557 101.142 24.893 ;
     RECT  14.508 24.859 16.29 24.899 ;
     RECT  90.432 24.854 90.846 24.899 ;
     RECT  120.924 24.314 122.13 24.899 ;
     RECT  123.66 24.854 124.398 24.935 ;
     RECT  90.504 24.899 90.846 24.941 ;
     RECT  102.24 23.819 102.258 24.941 ;
     RECT  14.508 24.899 16.11 24.971 ;
     RECT  79.992 23.963 80.01 24.971 ;
     RECT  90.828 24.941 90.846 24.989 ;
     RECT  105.984 24.557 106.002 24.989 ;
     RECT  82.728 24.737 82.746 25.007 ;
     RECT  87.012 23.387 87.03 25.037 ;
     RECT  109.404 24.749 109.422 25.037 ;
     RECT  20.592 23.855 39.33 25.043 ;
     RECT  44.46 24.811 44.478 25.043 ;
     RECT  17.172 23.936 18.897 25.045 ;
     RECT  19.656 23.936 19.674 25.045 ;
     RECT  17.172 25.045 19.674 25.085 ;
     RECT  111.42 24.317 111.438 25.133 ;
     RECT  20.592 25.043 39.258 25.141 ;
     RECT  14.508 24.971 15.966 25.169 ;
     RECT  129.672 24.665 129.978 25.195 ;
     RECT  103.32 23.819 103.878 25.555 ;
     RECT  126.144 23.777 126.162 25.555 ;
     RECT  152.964 21.965 153.897 25.555 ;
     RECT  155.196 20.309 158.166 25.555 ;
     RECT  19.656 25.085 19.674 25.675 ;
     RECT  20.556 25.141 39.258 25.675 ;
     RECT  160.416 25.675 160.434 25.715 ;
     RECT  17.172 25.085 18.897 25.717 ;
     RECT  11.16 22.781 11.178 25.753 ;
     RECT  11.988 23.597 13.497 25.753 ;
     RECT  158.94 4.487 159.297 25.861 ;
     RECT  19.656 25.675 39.258 25.92 ;
     RECT  41.364 24.503 41.382 25.92 ;
     RECT  42.156 24.173 42.174 25.92 ;
     RECT  47.304 25.555 47.322 25.92 ;
     RECT  89.352 24.854 89.37 25.92 ;
     RECT  93.816 23.777 94.122 25.92 ;
     RECT  96.048 23.549 96.354 25.92 ;
     RECT  100.26 24.893 101.142 25.92 ;
     RECT  103.14 25.555 103.878 25.92 ;
     RECT  113.976 24.221 113.994 25.92 ;
     RECT  115.74 23.777 115.758 25.92 ;
     RECT  120.924 24.899 121.554 25.92 ;
     RECT  124.236 24.935 124.398 25.92 ;
     RECT  125.964 25.555 126.162 25.92 ;
     RECT  126.936 24.395 127.314 25.92 ;
     RECT  128.052 24.395 128.286 25.92 ;
     RECT  129.672 25.195 130.554 25.92 ;
     RECT  132.804 23.927 146.034 25.92 ;
     RECT  9.396 24.233 10.35 25.963 ;
     RECT  11.16 25.753 13.497 25.963 ;
     RECT  16.992 25.717 18.897 25.963 ;
     RECT  19.656 25.92 146.034 25.963 ;
     RECT  158.94 25.861 159.894 25.979 ;
     RECT  152.964 25.555 158.166 26.015 ;
     RECT  155.196 26.015 158.166 26.059 ;
     RECT  158.94 25.979 159.786 26.059 ;
     RECT  155.196 26.059 159.786 26.123 ;
     RECT  9.396 25.963 13.497 26.131 ;
     RECT  14.508 25.169 15.714 26.131 ;
     RECT  16.992 25.963 146.034 26.131 ;
     RECT  155.196 26.123 159.297 26.237 ;
     RECT  9.396 26.131 146.034 26.555 ;
     RECT  9.396 26.555 19.134 26.627 ;
     RECT  146.916 22.513 149.706 26.635 ;
     RECT  9.396 26.627 10.854 26.699 ;
     RECT  146.844 26.635 149.706 26.765 ;
     RECT  161.424 20.039 161.514 26.797 ;
     RECT  19.908 26.555 146.034 27.329 ;
     RECT  11.808 26.627 19.134 27.355 ;
     RECT  19.908 27.329 25.794 27.355 ;
     RECT  7.815 14.381 8.097 27.715 ;
     RECT  7.815 27.715 8.586 27.773 ;
     RECT  9.396 26.699 10.782 28.219 ;
     RECT  11.808 27.355 25.794 28.315 ;
     RECT  26.532 27.329 146.034 28.315 ;
     RECT  9.396 28.219 10.962 28.409 ;
     RECT  10.008 28.409 10.962 28.561 ;
     RECT  11.808 28.315 146.034 28.561 ;
     RECT  10.008 28.561 146.034 28.751 ;
     RECT  146.988 26.765 149.706 28.795 ;
     RECT  146.952 28.795 149.706 28.891 ;
     RECT  150.624 24.809 151.29 28.891 ;
     RECT  10.008 28.751 10.962 28.949 ;
     RECT  9.144 28.507 9.162 28.985 ;
     RECT  11.7 28.751 146.034 28.985 ;
     RECT  146.952 28.891 151.29 29.219 ;
     RECT  10.26 28.949 10.962 29.489 ;
     RECT  11.7 28.985 17.514 29.489 ;
     RECT  150.624 29.219 151.29 29.611 ;
     RECT  146.952 29.219 149.85 29.645 ;
     RECT  11.916 29.489 17.514 29.767 ;
     RECT  18.252 28.985 146.034 29.767 ;
     RECT  150.624 29.611 151.614 29.911 ;
     RECT  161.352 26.797 161.514 30.037 ;
     RECT  155.196 26.237 158.166 30.181 ;
     RECT  161.352 30.037 161.55 30.181 ;
     RECT  155.16 30.181 158.166 30.221 ;
     RECT  11.916 29.767 146.034 30.235 ;
     RECT  146.952 29.645 149.706 30.235 ;
     RECT  150.624 29.911 151.65 30.235 ;
     RECT  161.28 30.181 161.55 30.235 ;
     RECT  162.432 4.109 165.654 30.235 ;
     RECT  11.808 30.235 149.706 30.269 ;
     RECT  150.624 30.235 151.974 30.299 ;
     RECT  161.28 30.235 165.654 30.335 ;
     RECT  160.164 30.427 160.182 30.568 ;
     RECT  150.624 30.299 151.794 30.569 ;
     RECT  161.352 30.335 165.654 30.569 ;
     RECT  11.808 30.269 133.938 30.605 ;
     RECT  150.624 30.569 151.65 30.605 ;
     RECT  160.128 30.568 160.182 30.605 ;
     RECT  134.676 30.269 149.706 30.653 ;
     RECT  161.352 30.569 161.694 30.677 ;
     RECT  152.964 26.015 153.897 30.685 ;
     RECT  160.164 30.605 160.182 30.749 ;
     RECT  161.424 30.677 161.694 30.755 ;
     RECT  134.784 30.653 149.706 30.811 ;
     RECT  152.784 30.685 153.897 30.811 ;
     RECT  12.42 30.605 133.938 30.893 ;
     RECT  162.432 30.569 165.654 30.991 ;
     RECT  152.676 30.811 153.897 31.145 ;
     RECT  12.672 30.893 133.938 31.217 ;
     RECT  162.432 30.991 165.87 31.243 ;
     RECT  12.816 31.217 133.938 31.289 ;
     RECT  162.432 31.243 166.194 31.289 ;
     RECT  162.432 31.289 165.942 31.379 ;
     RECT  13.176 31.289 133.938 31.415 ;
     RECT  162.432 31.379 165.87 31.415 ;
     RECT  14.976 31.415 133.938 31.483 ;
     RECT  134.784 30.811 149.778 31.483 ;
     RECT  14.976 31.483 149.778 31.649 ;
     RECT  15.048 31.649 149.778 31.685 ;
     RECT  15.12 31.685 149.778 31.757 ;
     RECT  15.984 31.757 149.778 31.793 ;
     RECT  16.236 31.793 149.778 33.437 ;
     RECT  134.568 33.437 149.778 34.051 ;
     RECT  150.624 30.605 151.29 34.051 ;
     RECT  134.568 34.051 151.29 34.079 ;
     RECT  134.784 34.079 151.29 34.151 ;
     RECT  16.236 33.437 133.704 34.555 ;
     RECT  15.12 31.757 15.21 34.735 ;
     RECT  16.236 34.555 133.794 34.747 ;
     RECT  161.424 30.755 161.514 34.771 ;
     RECT  162.432 31.415 165.654 34.771 ;
     RECT  16.236 34.747 133.974 34.799 ;
     RECT  158.94 26.237 159.297 34.861 ;
     RECT  161.352 34.771 161.514 34.889 ;
     RECT  155.196 30.221 158.166 35.069 ;
     RECT  157.68 35.069 158.166 35.159 ;
     RECT  134.784 34.151 149.886 35.275 ;
     RECT  150.624 34.151 151.29 35.275 ;
     RECT  17.496 34.799 133.938 35.851 ;
     RECT  134.784 35.275 151.29 35.851 ;
     RECT  152.964 31.145 153.897 36.085 ;
     RECT  152.208 35.947 152.226 36.121 ;
     RECT  152.964 36.085 153.99 36.121 ;
     RECT  161.352 34.889 161.37 36.211 ;
     RECT  17.496 35.851 151.29 36.221 ;
     RECT  134.784 36.221 151.29 36.235 ;
     RECT  152.208 36.121 153.99 36.235 ;
     RECT  157.68 35.159 157.698 36.319 ;
     RECT  162.36 34.771 165.654 36.319 ;
     RECT  157.68 36.319 157.914 36.355 ;
     RECT  134.784 36.235 153.99 36.391 ;
     RECT  157.68 36.355 158.13 36.391 ;
     RECT  134.784 36.391 154.458 36.481 ;
     RECT  155.196 35.069 156.582 36.481 ;
     RECT  134.784 36.481 156.582 36.545 ;
     RECT  161.352 36.211 161.478 36.553 ;
     RECT  162.252 36.319 165.654 36.553 ;
     RECT  157.464 36.391 158.13 36.661 ;
     RECT  158.94 34.861 159.354 36.661 ;
     RECT  161.352 36.553 165.654 36.787 ;
     RECT  148.215 36.545 156.582 36.823 ;
     RECT  157.464 36.661 159.354 36.823 ;
     RECT  161.208 36.787 165.654 36.895 ;
     RECT  148.215 36.823 159.354 36.907 ;
     RECT  161.1 36.895 165.654 36.931 ;
     RECT  134.784 36.545 147.294 36.955 ;
     RECT  160.632 36.931 165.654 37.003 ;
     RECT  148.215 36.907 159.678 37.021 ;
     RECT  17.496 36.221 133.866 37.051 ;
     RECT  134.676 36.955 147.294 37.051 ;
     RECT  160.488 37.003 165.654 37.057 ;
     RECT  148.215 37.021 159.75 37.165 ;
     RECT  160.488 37.057 165.726 37.165 ;
     RECT  17.496 37.051 147.294 37.435 ;
     RECT  148.215 37.165 165.726 37.435 ;
     RECT  17.496 37.435 166.266 37.589 ;
     RECT  17.496 37.589 166.194 37.901 ;
     RECT  17.496 37.901 134.046 38.237 ;
     RECT  17.496 38.237 134.01 38.777 ;
     RECT  17.496 38.777 133.938 39.197 ;
     RECT  134.784 37.901 166.194 39.479 ;
     RECT  134.784 39.479 165.726 39.623 ;
     RECT  153.615 39.623 165.726 39.629 ;
     RECT  17.496 39.197 133.794 39.749 ;
     RECT  134.784 39.623 152.838 39.749 ;
     RECT  153.615 39.629 165.618 39.749 ;
     RECT  153.615 39.749 157.626 39.785 ;
     RECT  158.58 39.749 165.546 39.785 ;
     RECT  156.276 39.785 157.626 39.821 ;
     RECT  148.215 39.749 152.838 40.019 ;
     RECT  165.528 39.785 165.546 40.289 ;
     RECT  21.744 39.749 133.794 40.315 ;
     RECT  149.904 40.019 152.838 40.507 ;
     RECT  153.615 39.785 155.394 40.507 ;
     RECT  149.904 40.507 155.394 40.531 ;
     RECT  149.904 40.531 155.718 40.555 ;
     RECT  156.636 39.821 157.626 40.555 ;
     RECT  149.904 40.555 157.626 40.603 ;
     RECT  158.58 39.785 164.754 40.603 ;
     RECT  149.904 40.603 164.754 40.667 ;
     RECT  166.5 40.531 166.518 40.675 ;
     RECT  166.176 40.675 166.518 40.733 ;
     RECT  148.215 40.019 149.166 40.795 ;
     RECT  148.068 40.795 149.166 40.801 ;
     RECT  149.904 40.667 158.166 40.801 ;
     RECT  159.015 40.667 164.754 40.801 ;
     RECT  148.068 40.801 158.166 40.829 ;
     RECT  148.068 40.829 155.718 40.835 ;
     RECT  148.215 40.835 155.718 40.973 ;
     RECT  21.744 40.315 133.938 41.071 ;
     RECT  134.784 39.749 147.042 41.071 ;
     RECT  21.744 41.071 147.042 41.309 ;
     RECT  167.796 41.251 167.814 41.369 ;
     RECT  21.744 41.309 38.034 41.405 ;
     RECT  166.5 40.733 166.518 41.485 ;
     RECT  166.5 41.485 166.842 41.549 ;
     RECT  38.88 41.309 147.042 41.611 ;
     RECT  21.744 41.405 37.962 41.747 ;
     RECT  23.256 41.747 37.962 41.789 ;
     RECT  21.744 41.747 22.446 42.727 ;
     RECT  23.256 41.789 37.926 42.727 ;
     RECT  166.5 41.549 166.518 43.915 ;
     RECT  165.924 43.915 166.518 43.951 ;
     RECT  159.015 40.801 164.934 43.979 ;
     RECT  165.924 43.951 166.878 44.069 ;
     RECT  165.924 44.069 166.518 44.105 ;
     RECT  21.744 42.727 37.926 44.443 ;
     RECT  38.88 41.611 147.33 44.443 ;
     RECT  21.744 44.443 147.33 44.573 ;
     RECT  38.7 44.573 147.33 44.645 ;
     RECT  38.736 44.645 147.33 44.761 ;
     RECT  148.215 40.973 149.994 44.761 ;
     RECT  38.736 44.761 149.994 44.813 ;
     RECT  38.772 44.813 149.994 44.879 ;
     RECT  38.772 44.879 147.33 45.581 ;
     RECT  38.88 45.581 147.33 45.869 ;
     RECT  38.88 45.869 133.83 46.645 ;
     RECT  134.568 45.869 147.33 46.645 ;
     RECT  38.88 46.645 147.33 47.261 ;
     RECT  21.744 44.573 37.926 48.163 ;
     RECT  38.88 47.261 133.794 48.541 ;
     RECT  134.532 47.261 147.33 48.541 ;
     RECT  38.88 48.541 147.33 48.605 ;
     RECT  38.88 48.605 133.794 49.711 ;
     RECT  134.532 48.605 147.33 49.711 ;
     RECT  150.912 40.973 155.718 49.811 ;
     RECT  148.215 44.879 149.994 49.891 ;
     RECT  150.912 49.811 151.11 49.891 ;
     RECT  38.88 49.711 147.33 49.949 ;
     RECT  148.215 49.891 151.11 50.279 ;
     RECT  159.015 43.979 162.486 50.701 ;
     RECT  21.744 48.163 38.142 50.971 ;
     RECT  38.88 49.949 133.794 50.971 ;
     RECT  156.456 40.829 158.166 51.089 ;
     RECT  21.744 50.971 133.794 51.241 ;
     RECT  134.532 49.949 147.33 51.241 ;
     RECT  158.148 51.089 158.166 51.355 ;
     RECT  158.976 50.701 162.486 51.355 ;
     RECT  158.148 51.355 162.486 51.395 ;
     RECT  21.744 51.241 147.33 51.581 ;
     RECT  21.744 51.581 133.794 52.591 ;
     RECT  134.532 51.581 147.33 52.591 ;
     RECT  21.744 52.591 147.33 52.925 ;
     RECT  17.496 39.749 21.006 52.987 ;
     RECT  17.352 52.987 21.006 53.021 ;
     RECT  13.176 31.415 13.914 53.035 ;
     RECT  12.6 53.035 13.914 53.563 ;
     RECT  15.048 34.735 15.21 53.563 ;
     RECT  14.976 53.563 15.21 53.611 ;
     RECT  14.832 53.611 15.21 53.659 ;
     RECT  21.744 52.925 133.704 53.659 ;
     RECT  14.832 53.659 15.282 53.789 ;
     RECT  21.744 53.659 133.794 53.789 ;
     RECT  14.832 53.789 15.21 53.981 ;
     RECT  38.88 53.789 133.794 54.067 ;
     RECT  134.532 52.925 147.33 54.067 ;
     RECT  16.236 34.799 16.578 54.091 ;
     RECT  14.868 53.981 15.21 54.125 ;
     RECT  17.352 53.021 17.37 54.187 ;
     RECT  18.108 53.021 21.006 54.187 ;
     RECT  16.164 54.091 16.578 54.269 ;
     RECT  21.744 53.789 38.142 54.749 ;
     RECT  17.352 54.187 21.006 54.763 ;
     RECT  21.924 54.749 38.142 55.291 ;
     RECT  38.88 54.067 147.33 55.291 ;
     RECT  21.924 55.291 147.33 56.021 ;
     RECT  21.924 56.021 133.794 56.045 ;
     RECT  134.532 56.021 147.33 56.399 ;
     RECT  38.88 56.045 133.794 57.181 ;
     RECT  134.568 56.399 147.33 57.181 ;
     RECT  21.924 56.045 38.142 57.499 ;
     RECT  38.88 57.181 147.33 57.499 ;
     RECT  21.924 57.499 147.33 58.877 ;
     RECT  21.924 58.877 133.794 59.605 ;
     RECT  134.532 58.877 147.33 59.605 ;
     RECT  21.924 59.605 147.33 60.221 ;
     RECT  21.924 60.221 133.794 61.045 ;
     RECT  134.532 60.221 147.33 61.045 ;
     RECT  21.924 61.045 147.33 61.277 ;
     RECT  21.924 61.277 133.794 61.901 ;
     RECT  31.896 61.901 133.794 62.381 ;
     RECT  32.004 62.381 133.794 62.683 ;
     RECT  134.532 61.277 147.33 62.683 ;
     RECT  21.924 61.901 31.122 63.005 ;
     RECT  21.924 63.005 31.05 63.533 ;
     RECT  21.924 63.533 30.978 64.121 ;
     RECT  32.004 62.683 147.33 64.157 ;
     RECT  32.256 64.157 147.33 64.541 ;
     RECT  21.924 64.121 30.222 65.179 ;
     RECT  30.96 64.121 30.978 65.179 ;
     RECT  21.924 65.179 30.978 65.213 ;
     RECT  21.924 65.213 26.37 65.261 ;
     RECT  27.288 65.213 30.978 65.309 ;
     RECT  148.215 50.279 151.074 65.611 ;
     RECT  32.256 64.541 133.794 65.641 ;
     RECT  134.532 64.541 147.33 65.641 ;
     RECT  148.215 65.611 151.182 65.669 ;
     RECT  32.256 65.641 147.33 65.885 ;
     RECT  134.532 65.885 147.33 65.939 ;
     RECT  134.568 65.939 147.33 66.083 ;
     RECT  32.256 65.885 133.704 66.984 ;
     RECT  32.256 66.984 39.33 67.397 ;
     RECT  42.66 66.984 42.678 67.514 ;
     RECT  122.652 66.984 122.67 67.756 ;
     RECT  134.784 66.083 147.33 67.756 ;
     RECT  158.976 51.395 162.486 67.853 ;
     RECT  134.568 67.756 147.33 67.909 ;
     RECT  134.532 67.909 147.33 68.009 ;
     RECT  134.532 68.009 138.438 68.054 ;
     RECT  93.852 67.819 93.978 68.093 ;
     RECT  77.004 66.984 77.022 68.107 ;
     RECT  134.676 68.054 138.438 68.135 ;
     RECT  122.58 67.756 122.67 68.143 ;
     RECT  32.256 67.397 39.222 68.237 ;
     RECT  90.648 67.819 90.666 68.573 ;
     RECT  95.256 68.395 95.382 68.573 ;
     RECT  79.776 67.771 79.794 68.635 ;
     RECT  75.816 66.984 75.834 68.719 ;
     RECT  83.664 68.059 83.682 68.971 ;
     RECT  75.564 68.719 75.834 69.025 ;
     RECT  76.968 68.107 77.31 69.025 ;
     RECT  158.976 67.853 160.218 69.053 ;
     RECT  44.712 66.984 45.306 69.103 ;
     RECT  76.968 69.025 77.382 69.103 ;
     RECT  78.768 69.025 78.786 69.103 ;
     RECT  82.728 69.025 82.746 69.103 ;
     RECT  83.664 68.971 84.222 69.103 ;
     RECT  93.852 68.093 93.87 69.103 ;
     RECT  127.368 68.719 127.386 69.103 ;
     RECT  44.712 69.103 45.705 69.151 ;
     RECT  56.415 69.103 56.505 69.151 ;
     RECT  67.215 69.103 67.305 69.151 ;
     RECT  88.815 69.103 88.905 69.151 ;
     RECT  99.615 69.103 99.705 69.151 ;
     RECT  110.415 69.103 110.505 69.151 ;
     RECT  121.215 69.103 121.305 69.151 ;
     RECT  132.015 69.103 132.105 69.163 ;
     RECT  71.46 68.971 71.478 69.179 ;
     RECT  74.772 69.025 75.834 69.179 ;
     RECT  81.072 66.984 81.09 69.179 ;
     RECT  74.772 69.179 74.862 69.187 ;
     RECT  82.728 69.103 84.222 69.187 ;
     RECT  84.96 68.971 84.978 69.187 ;
     RECT  139.284 68.009 147.33 69.197 ;
     RECT  79.776 68.635 80.334 69.211 ;
     RECT  76.968 69.103 78.786 69.215 ;
     RECT  76.968 69.215 77.166 69.251 ;
     RECT  79.776 69.211 80.658 69.251 ;
     RECT  67.104 69.151 67.41 69.259 ;
     RECT  71.352 69.223 71.37 69.259 ;
     RECT  126.615 69.103 127.386 69.259 ;
     RECT  74.664 69.187 74.862 69.287 ;
     RECT  75.816 69.179 75.834 69.287 ;
     RECT  71.208 69.259 71.37 69.296 ;
     RECT  77.004 69.251 77.166 69.323 ;
     RECT  85.932 69.259 85.95 69.331 ;
     RECT  66.744 69.259 67.41 69.359 ;
     RECT  71.28 69.296 71.37 69.359 ;
     RECT  77.148 69.323 77.166 69.359 ;
     RECT  82.728 69.187 84.978 69.359 ;
     RECT  40.215 69.103 40.305 69.373 ;
     RECT  44.712 69.151 45.81 69.373 ;
     RECT  51.015 69.103 51.105 69.373 ;
     RECT  56.304 69.151 56.61 69.373 ;
     RECT  61.815 69.103 61.905 69.373 ;
     RECT  67.104 69.359 67.41 69.373 ;
     RECT  72.615 69.103 72.705 69.373 ;
     RECT  88.704 69.151 89.01 69.373 ;
     RECT  93.852 69.103 94.305 69.373 ;
     RECT  99.504 69.151 99.81 69.373 ;
     RECT  105.015 69.103 105.105 69.373 ;
     RECT  110.304 69.151 110.646 69.373 ;
     RECT  115.815 69.103 115.905 69.373 ;
     RECT  116.748 68.923 116.766 69.373 ;
     RECT  121.104 69.151 121.41 69.373 ;
     RECT  132.015 69.163 132.21 69.373 ;
     RECT  81.504 69.211 81.774 69.403 ;
     RECT  77.904 69.215 78.786 69.485 ;
     RECT  82.728 69.359 84.402 69.485 ;
     RECT  77.904 69.485 78.75 69.521 ;
     RECT  83.415 69.485 84.402 69.521 ;
     RECT  77.904 69.521 78.678 69.533 ;
     RECT  81.504 69.403 81.954 69.533 ;
     RECT  159.015 69.053 160.218 69.533 ;
     RECT  88.704 69.373 89.097 69.547 ;
     RECT  83.415 69.521 83.79 69.581 ;
     RECT  148.215 65.669 151.074 69.593 ;
     RECT  148.215 69.593 150.966 69.629 ;
     RECT  61.815 69.373 62.097 69.691 ;
     RECT  85.932 69.331 86.598 69.691 ;
     RECT  110.304 69.373 110.697 69.691 ;
     RECT  130.536 69.163 130.554 69.691 ;
     RECT  132.015 69.373 132.297 69.691 ;
     RECT  134.784 68.135 138.438 69.691 ;
     RECT  139.284 69.197 140.814 69.691 ;
     RECT  74.664 69.287 74.754 69.719 ;
     RECT  54.792 69.691 54.81 69.727 ;
     RECT  56.304 69.373 56.697 69.727 ;
     RECT  98.676 69.691 98.694 69.727 ;
     RECT  99.504 69.373 99.897 69.727 ;
     RECT  131.904 69.691 132.297 69.727 ;
     RECT  42.804 69.691 42.822 69.791 ;
     RECT  54.72 69.727 54.81 69.791 ;
     RECT  61.815 69.691 62.766 69.791 ;
     RECT  85.932 69.691 86.706 69.791 ;
     RECT  98.604 69.727 98.694 69.791 ;
     RECT  106.668 69.691 106.686 69.791 ;
     RECT  110.304 69.691 110.718 69.791 ;
     RECT  118.62 69.691 118.638 69.791 ;
     RECT  130.536 69.691 130.626 69.799 ;
     RECT  54.72 69.791 54.738 69.863 ;
     RECT  56.304 69.727 56.754 69.863 ;
     RECT  98.604 69.791 98.622 69.863 ;
     RECT  99.504 69.727 99.954 69.863 ;
     RECT  131.904 69.727 132.354 69.863 ;
     RECT  134.784 69.691 140.814 69.863 ;
     RECT  74.664 69.719 74.682 69.899 ;
     RECT  77.904 69.533 78.39 69.899 ;
     RECT  79.776 69.251 79.794 70.069 ;
     RECT  80.64 69.251 80.658 70.069 ;
     RECT  92.952 67.819 92.97 70.069 ;
     RECT  79.776 70.069 80.658 70.097 ;
     RECT  88.308 69.547 89.097 70.097 ;
     RECT  51.015 69.373 51.297 70.123 ;
     RECT  158.148 51.395 158.166 70.123 ;
     RECT  159.015 69.533 159.894 70.123 ;
     RECT  56.304 69.863 56.697 70.169 ;
     RECT  67.104 69.373 67.497 70.169 ;
     RECT  77.904 69.899 78.354 70.169 ;
     RECT  88.704 70.097 89.097 70.169 ;
     RECT  99.504 69.863 99.897 70.169 ;
     RECT  110.304 69.791 110.697 70.169 ;
     RECT  121.104 69.373 121.497 70.169 ;
     RECT  131.904 69.863 132.297 70.169 ;
     RECT  50.832 70.123 51.297 70.267 ;
     RECT  158.148 70.123 159.894 70.301 ;
     RECT  83.415 69.581 83.697 70.375 ;
     RECT  129.888 69.799 130.626 70.375 ;
     RECT  50.724 70.267 51.297 70.397 ;
     RECT  78.015 70.169 78.354 70.403 ;
     RECT  129.888 70.375 130.662 70.843 ;
     RECT  133.56 66.984 133.578 70.843 ;
     RECT  156.456 51.089 157.194 70.877 ;
     RECT  132.015 70.169 132.297 70.951 ;
     RECT  129.888 70.843 130.698 70.973 ;
     RECT  111.672 71.041 111.69 71.117 ;
     RECT  110.415 70.169 110.697 71.131 ;
     RECT  129.888 70.973 130.662 71.165 ;
     RECT  133.56 70.843 133.902 71.165 ;
     RECT  110.415 71.131 111.402 71.249 ;
     RECT  120.42 71.131 120.438 71.581 ;
     RECT  120.132 71.581 120.438 71.609 ;
     RECT  139.284 69.863 140.814 71.609 ;
     RECT  120.132 71.609 120.15 71.645 ;
     RECT  133.56 71.165 133.614 72.121 ;
     RECT  52.704 66.984 52.722 72.419 ;
     RECT  105.015 69.373 105.297 72.811 ;
     RECT  105.015 72.811 105.426 72.959 ;
     RECT  106.668 72.907 106.686 72.959 ;
     RECT  129.888 71.165 129.906 73.819 ;
     RECT  130.644 71.165 130.662 73.819 ;
     RECT  134.784 69.863 138.222 73.867 ;
     RECT  119.088 73.819 119.106 73.949 ;
     RECT  129.888 73.819 130.662 73.949 ;
     RECT  117.828 73.915 117.846 74.011 ;
     RECT  121.215 70.169 121.497 74.011 ;
     RECT  134.532 73.867 138.222 74.045 ;
     RECT  117.54 74.011 117.846 74.048 ;
     RECT  121.104 74.011 121.497 74.048 ;
     RECT  117.828 74.048 117.846 74.093 ;
     RECT  126.615 69.259 127.962 75.397 ;
     RECT  133.38 72.121 133.614 76.045 ;
     RECT  32.256 68.237 39.186 76.441 ;
     RECT  32.256 76.441 39.402 76.493 ;
     RECT  93.852 69.373 94.497 77.287 ;
     RECT  95.256 68.573 95.274 77.287 ;
     RECT  93.852 77.287 95.274 77.357 ;
     RECT  96.408 66.984 96.966 77.431 ;
     RECT  51.015 70.397 51.297 77.791 ;
     RECT  54.432 70.123 54.45 77.803 ;
     RECT  51.015 77.791 51.894 77.837 ;
     RECT  54.432 77.803 54.738 77.933 ;
     RECT  53.64 72.391 53.658 77.971 ;
     RECT  53.424 77.971 53.658 78.077 ;
     RECT  44.712 69.373 45.897 79.243 ;
     RECT  61.815 69.791 62.097 82.687 ;
     RECT  61.092 82.687 62.097 82.949 ;
     RECT  60.156 83.101 60.174 83.165 ;
     RECT  54.432 77.933 54.45 83.467 ;
     RECT  61.56 82.949 62.097 83.489 ;
     RECT  88.815 70.169 89.097 83.497 ;
     RECT  80.208 70.097 80.658 83.525 ;
     RECT  85.932 69.791 86.598 83.533 ;
     RECT  57.564 83.533 57.582 83.56 ;
     RECT  81.756 69.533 81.846 83.561 ;
     RECT  54.432 83.467 54.738 83.597 ;
     RECT  40.215 69.373 40.497 83.605 ;
     RECT  57.564 83.56 57.87 83.641 ;
     RECT  63.18 83.605 63.198 83.759 ;
     RECT  57.564 83.641 58.194 83.789 ;
     RECT  56.415 70.169 56.697 84.271 ;
     RECT  56.232 84.271 56.697 84.317 ;
     RECT  57.564 83.789 57.726 84.365 ;
     RECT  44.604 79.243 45.897 84.379 ;
     RECT  58.536 84.145 58.554 84.569 ;
     RECT  49.284 66.984 49.302 84.641 ;
     RECT  58.968 84.685 58.986 84.839 ;
     RECT  57.564 84.365 57.582 85.109 ;
     RECT  32.256 76.493 39.186 85.261 ;
     RECT  40.215 83.605 41.13 85.261 ;
     RECT  56.415 84.317 56.697 85.261 ;
     RECT  32.256 85.261 41.13 85.415 ;
     RECT  56.415 85.261 57.042 85.459 ;
     RECT  56.124 85.459 57.042 85.517 ;
     RECT  60.336 85.531 60.354 85.649 ;
     RECT  59.328 84.883 59.346 85.801 ;
     RECT  56.415 85.517 57.042 85.919 ;
     RECT  54.432 83.597 54.45 86.197 ;
     RECT  54.432 86.197 54.738 86.297 ;
     RECT  59.328 85.801 59.742 86.297 ;
     RECT  42.732 86.197 42.75 86.369 ;
     RECT  59.328 86.297 59.562 86.459 ;
     RECT  66.456 86.575 66.474 86.611 ;
     RECT  67.215 70.169 67.497 86.611 ;
     RECT  66.456 86.611 67.497 86.621 ;
     RECT  51.015 77.837 51.297 86.635 ;
     RECT  40.215 85.415 41.13 86.728 ;
     RECT  40.032 86.728 41.13 86.765 ;
     RECT  42.048 86.809 42.066 86.881 ;
     RECT  47.952 84.379 47.97 86.881 ;
     RECT  41.976 86.881 42.066 86.909 ;
     RECT  47.916 86.881 47.97 86.999 ;
     RECT  66.708 86.621 67.497 86.999 ;
     RECT  67.068 86.999 67.497 87.269 ;
     RECT  50.976 86.635 51.297 87.313 ;
     RECT  52.128 84.613 52.146 87.313 ;
     RECT  53.64 78.077 53.658 87.313 ;
     RECT  44.604 84.379 46.53 87.349 ;
     RECT  56.415 85.919 56.97 87.349 ;
     RECT  42.768 87.349 42.786 87.403 ;
     RECT  50.976 87.313 52.146 87.421 ;
     RECT  44.604 87.349 47.07 87.449 ;
     RECT  50.976 87.421 52.47 87.511 ;
     RECT  53.388 87.313 53.658 87.511 ;
     RECT  55.728 87.349 56.97 87.539 ;
     RECT  42.768 87.403 42.894 87.581 ;
     RECT  50.976 87.511 53.658 87.655 ;
     RECT  54.432 86.297 54.45 87.655 ;
     RECT  56.415 87.539 56.97 87.691 ;
     RECT  71.172 87.511 71.19 87.691 ;
     RECT  47.952 86.999 47.97 87.781 ;
     RECT  50.976 87.655 54.45 87.781 ;
     RECT  41.976 86.909 41.994 87.809 ;
     RECT  44.604 87.449 46.998 87.809 ;
     RECT  48.78 87.151 48.798 87.809 ;
     RECT  50.904 87.781 54.45 87.809 ;
     RECT  50.904 87.809 53.658 87.883 ;
     RECT  47.952 87.781 48.006 87.925 ;
     RECT  32.256 85.415 39.186 87.961 ;
     RECT  40.215 86.765 41.13 87.961 ;
     RECT  47.808 87.925 48.006 87.965 ;
     RECT  42.768 87.581 42.786 87.989 ;
     RECT  50.58 87.883 53.658 88.051 ;
     RECT  78.015 70.403 78.297 88.171 ;
     RECT  70.128 88.123 70.146 88.195 ;
     RECT  70.956 87.691 71.298 88.195 ;
     RECT  54.432 87.809 54.45 88.219 ;
     RECT  80.208 83.525 80.226 88.231 ;
     RECT  78.015 88.171 78.966 88.321 ;
     RECT  79.884 88.231 80.226 88.321 ;
     RECT  50.544 88.051 53.658 88.349 ;
     RECT  78.015 88.321 80.226 88.349 ;
     RECT  54.432 88.219 54.99 88.357 ;
     RECT  59.328 86.459 59.49 88.357 ;
     RECT  47.952 87.965 48.006 88.393 ;
     RECT  50.544 88.349 52.146 88.393 ;
     RECT  61.815 83.489 62.097 88.465 ;
     RECT  61.416 88.465 62.097 88.591 ;
     RECT  61.02 88.591 62.097 88.603 ;
     RECT  47.952 88.393 48.402 88.619 ;
     RECT  54.432 88.357 55.062 88.619 ;
     RECT  63.108 83.911 63.126 88.619 ;
     RECT  79.236 88.349 80.226 88.619 ;
     RECT  78.015 88.349 78.297 88.663 ;
     RECT  54.684 88.619 55.062 88.691 ;
     RECT  59.328 88.357 59.634 88.699 ;
     RECT  63.864 88.159 63.882 88.735 ;
     RECT  58.716 88.699 59.634 88.747 ;
     RECT  44.604 87.809 46.926 88.771 ;
     RECT  47.952 88.619 47.97 88.771 ;
     RECT  58.536 88.747 59.634 88.771 ;
     RECT  70.128 88.195 71.298 88.771 ;
     RECT  58.464 88.771 59.634 88.889 ;
     RECT  73.872 88.699 73.89 88.889 ;
     RECT  79.416 88.619 80.226 88.889 ;
     RECT  56.415 87.691 57.042 88.891 ;
     RECT  70.128 88.771 71.334 88.891 ;
     RECT  72.615 69.373 72.897 88.891 ;
     RECT  60.444 88.603 62.097 88.925 ;
     RECT  56.088 88.891 57.042 88.931 ;
     RECT  69.48 88.891 71.334 88.931 ;
     RECT  63.864 88.735 64.134 88.933 ;
     RECT  56.232 88.931 57.042 88.969 ;
     RECT  67.176 87.269 67.497 88.969 ;
     RECT  68.688 88.933 68.706 89.005 ;
     RECT  42.768 88.771 42.786 89.041 ;
     RECT  63.504 88.933 64.134 89.041 ;
     RECT  72.615 88.891 72.954 89.041 ;
     RECT  59.22 88.889 59.634 89.131 ;
     RECT  67.176 88.969 67.698 89.131 ;
     RECT  56.232 88.969 57.078 89.159 ;
     RECT  61.02 88.925 62.097 89.159 ;
     RECT  63.504 89.041 64.602 89.159 ;
     RECT  50.4 88.393 52.146 89.203 ;
     RECT  42.768 89.041 43.794 89.239 ;
     RECT  42.768 89.239 43.83 89.311 ;
     RECT  44.604 88.771 47.97 89.311 ;
     RECT  72.615 89.041 73.386 89.311 ;
     RECT  68.652 89.005 68.706 89.401 ;
     RECT  77.436 88.663 78.297 89.401 ;
     RECT  32.256 87.961 41.13 89.419 ;
     RECT  42.768 89.311 47.97 89.429 ;
     RECT  70.02 88.931 71.334 89.429 ;
     RECT  75.06 89.239 75.078 89.429 ;
     RECT  32.256 89.419 41.67 89.465 ;
     RECT  42.768 89.429 42.822 89.473 ;
     RECT  54.684 88.691 54.918 89.473 ;
     RECT  74.124 89.437 74.142 89.501 ;
     RECT  42.624 89.473 42.822 89.545 ;
     RECT  50.184 89.203 52.146 89.545 ;
     RECT  56.376 89.159 57.078 89.545 ;
     RECT  76.5 89.437 76.518 89.545 ;
     RECT  77.256 89.401 78.297 89.545 ;
     RECT  76.5 89.545 78.297 89.563 ;
     RECT  59.22 89.131 59.67 89.573 ;
     RECT  50.184 89.545 52.182 89.581 ;
     RECT  53.388 88.349 53.658 89.581 ;
     RECT  76.032 89.563 78.297 89.581 ;
     RECT  79.416 88.889 79.434 89.581 ;
     RECT  43.74 89.429 47.97 89.609 ;
     RECT  54.684 89.473 55.314 89.609 ;
     RECT  41.976 89.545 42.822 89.735 ;
     RECT  66.708 89.131 67.698 89.743 ;
     RECT  166.104 44.105 166.518 89.743 ;
     RECT  81.756 83.561 81.774 89.771 ;
     RECT  96.012 77.431 96.966 89.771 ;
     RECT  121.215 74.048 121.497 89.779 ;
     RECT  41.976 89.735 42.786 89.807 ;
     RECT  50.184 89.581 53.658 89.815 ;
     RECT  126.216 75.397 127.962 89.815 ;
     RECT  63.504 89.159 64.134 89.851 ;
     RECT  50.184 89.815 53.874 89.941 ;
     RECT  54.684 89.609 55.17 89.941 ;
     RECT  61.56 89.159 62.097 89.941 ;
     RECT  63.252 89.851 64.134 89.941 ;
     RECT  27.288 65.309 30.222 89.969 ;
     RECT  41.976 89.807 42.318 89.969 ;
     RECT  66.636 89.743 67.698 89.969 ;
     RECT  68.58 89.401 68.706 89.969 ;
     RECT  65.844 89.941 65.862 89.977 ;
     RECT  70.128 89.429 71.334 89.995 ;
     RECT  72.108 89.311 73.386 89.995 ;
     RECT  60.444 89.815 60.462 90.013 ;
     RECT  67.068 89.969 67.698 90.013 ;
     RECT  76.032 89.581 79.434 90.013 ;
     RECT  50.184 89.941 55.17 90.041 ;
     RECT  65.7 89.977 65.862 90.077 ;
     RECT  74.268 89.509 74.286 90.085 ;
     RECT  84.42 89.743 84.438 90.121 ;
     RECT  16.164 54.269 16.254 90.239 ;
     RECT  17.352 54.763 21.078 90.239 ;
     RECT  68.904 90.013 69.03 90.239 ;
     RECT  75.78 90.013 79.434 90.239 ;
     RECT  56.376 89.545 57.294 90.283 ;
     RECT  16.164 90.239 16.182 90.391 ;
     RECT  61.56 89.941 64.134 90.391 ;
     RECT  25.2 65.261 26.37 90.481 ;
     RECT  27.288 89.969 28.494 90.481 ;
     RECT  43.776 89.609 47.97 90.509 ;
     RECT  61.56 90.391 64.458 90.509 ;
     RECT  50.184 90.041 52.182 90.545 ;
     RECT  75.78 90.239 75.798 90.581 ;
     RECT  29.232 89.969 30.222 90.619 ;
     RECT  30.96 65.309 30.978 90.619 ;
     RECT  42.192 89.969 42.318 90.625 ;
     RECT  74.268 90.085 74.394 90.625 ;
     RECT  75.312 90.589 75.33 90.625 ;
     RECT  74.268 90.625 75.33 90.689 ;
     RECT  12.6 53.563 14.058 90.751 ;
     RECT  32.256 89.465 41.202 90.751 ;
     RECT  42.192 90.625 42.822 90.751 ;
     RECT  67.068 90.013 67.842 90.751 ;
     RECT  68.904 90.239 68.922 90.751 ;
     RECT  29.232 90.619 30.978 90.779 ;
     RECT  53.388 90.041 55.17 90.779 ;
     RECT  65.844 90.077 65.862 90.779 ;
     RECT  70.128 89.995 73.386 90.779 ;
     RECT  74.268 90.689 75.078 90.779 ;
     RECT  77.004 90.239 79.434 90.779 ;
     RECT  53.46 90.779 55.17 90.823 ;
     RECT  67.068 90.751 68.922 90.823 ;
     RECT  48.816 88.771 48.834 90.895 ;
     RECT  66.78 90.823 68.922 90.895 ;
     RECT  71.532 90.779 73.386 90.907 ;
     RECT  74.268 90.779 75.042 90.907 ;
     RECT  43.632 90.661 43.65 90.931 ;
     RECT  84.42 90.121 84.978 90.931 ;
     RECT  85.824 83.533 86.598 90.931 ;
     RECT  17.352 90.239 21.042 90.959 ;
     RECT  53.46 90.823 55.206 90.959 ;
     RECT  59.22 89.573 59.634 90.998 ;
     RECT  10.584 90.931 10.602 91.021 ;
     RECT  14.868 54.125 14.994 91.021 ;
     RECT  16.056 90.391 16.182 91.049 ;
     RECT  25.2 90.481 28.494 91.049 ;
     RECT  71.532 90.907 75.042 91.049 ;
     RECT  44.388 90.509 47.97 91.057 ;
     RECT  48.816 90.895 49.122 91.057 ;
     RECT  56.376 90.283 57.474 91.093 ;
     RECT  70.128 90.779 70.578 91.093 ;
     RECT  17.352 90.959 18.897 91.165 ;
     RECT  21.924 65.261 24.297 91.165 ;
     RECT  25.2 91.049 27.99 91.165 ;
     RECT  105.015 72.959 105.297 91.195 ;
     RECT  134.784 74.045 138.222 91.229 ;
     RECT  60.444 90.013 60.786 91.285 ;
     RECT  61.56 90.509 62.097 91.285 ;
     RECT  50.436 90.545 52.182 91.291 ;
     RECT  79.236 90.779 79.434 91.291 ;
     RECT  80.208 88.889 80.226 91.291 ;
     RECT  19.728 90.959 21.042 91.319 ;
     RECT  29.232 90.779 30.906 91.319 ;
     RECT  66.024 90.895 68.922 91.319 ;
     RECT  43.56 90.931 43.65 91.327 ;
     RECT  44.388 91.057 49.122 91.327 ;
     RECT  49.86 91.291 52.182 91.355 ;
     RECT  10.512 91.021 10.602 91.363 ;
     RECT  68.616 91.319 68.922 91.363 ;
     RECT  32.256 90.751 42.822 91.427 ;
     RECT  10.512 91.363 11.142 91.435 ;
     RECT  36.18 91.427 42.822 91.435 ;
     RECT  43.56 91.327 49.122 91.435 ;
     RECT  10.512 91.435 11.178 91.471 ;
     RECT  12.564 90.751 14.058 91.471 ;
     RECT  14.868 91.021 15.282 91.471 ;
     RECT  21.924 91.165 27.99 91.471 ;
     RECT  59.22 90.998 59.67 91.471 ;
     RECT  60.444 91.285 62.097 91.471 ;
     RECT  131.544 70.951 132.297 91.471 ;
     RECT  36.18 91.435 49.122 91.472 ;
     RECT  134.784 91.229 138.042 91.499 ;
     RECT  59.22 91.471 62.097 91.531 ;
     RECT  63.036 90.509 63.054 91.531 ;
     RECT  77.004 90.779 78.462 91.531 ;
     RECT  10.512 91.471 11.322 91.561 ;
     RECT  12.564 91.471 15.282 91.561 ;
     RECT  69.768 91.093 70.578 91.579 ;
     RECT  16.164 91.049 16.182 91.589 ;
     RECT  32.256 91.427 35.406 91.589 ;
     RECT  53.46 90.959 54.81 91.589 ;
     RECT  59.22 91.531 63.054 91.589 ;
     RECT  75.816 91.435 75.834 91.589 ;
     RECT  63.864 90.509 64.134 91.597 ;
     RECT  55.836 91.093 57.474 91.661 ;
     RECT  59.22 91.589 62.097 91.669 ;
     RECT  76.896 91.531 78.462 91.669 ;
     RECT  79.236 91.291 80.226 91.669 ;
     RECT  82.908 70.375 83.697 91.669 ;
     RECT  84.42 90.931 86.598 91.669 ;
     RECT  68.616 91.363 68.994 91.675 ;
     RECT  69.768 91.579 70.686 91.675 ;
     RECT  17.064 91.165 18.897 91.705 ;
     RECT  19.728 91.319 20.358 91.705 ;
     RECT  29.232 91.319 30.258 91.705 ;
     RECT  50.184 91.355 52.182 91.705 ;
     RECT  68.616 91.675 70.686 91.705 ;
     RECT  71.532 91.049 74.286 91.705 ;
     RECT  76.896 91.669 80.226 91.705 ;
     RECT  81.756 91.201 81.774 91.705 ;
     RECT  82.908 91.669 86.598 91.705 ;
     RECT  76.896 91.705 80.838 91.723 ;
     RECT  81.756 91.705 86.598 91.723 ;
     RECT  17.064 91.705 20.358 91.741 ;
     RECT  21.816 91.471 27.99 91.741 ;
     RECT  32.256 91.589 32.886 91.741 ;
     RECT  75.024 91.049 75.042 91.741 ;
     RECT  76.896 91.723 86.598 91.741 ;
     RECT  76.68 91.741 86.598 91.757 ;
     RECT  50.184 91.705 52.326 91.769 ;
     RECT  6.804 47.011 6.822 91.771 ;
     RECT  7.815 27.773 8.097 91.771 ;
     RECT  95.256 77.357 95.274 91.771 ;
     RECT  105.015 91.195 105.426 91.771 ;
     RECT  63.864 91.597 64.278 91.819 ;
     RECT  63.864 91.819 64.926 91.831 ;
     RECT  42.3 91.472 49.122 91.859 ;
     RECT  66.024 91.319 67.842 91.859 ;
     RECT  76.68 91.757 80.19 91.859 ;
     RECT  148.215 69.629 150.93 91.859 ;
     RECT  151.992 49.811 155.718 91.859 ;
     RECT  159.015 70.301 159.894 91.859 ;
     RECT  68.616 91.705 74.286 91.867 ;
     RECT  75.024 91.741 75.762 91.867 ;
     RECT  151.992 91.859 155.61 91.931 ;
     RECT  76.68 91.859 77.022 91.963 ;
     RECT  32.184 91.741 32.886 91.975 ;
     RECT  52.02 91.769 52.326 91.975 ;
     RECT  53.46 91.589 53.622 91.975 ;
     RECT  54.432 91.589 54.81 91.975 ;
     RECT  10.512 91.561 15.282 91.991 ;
     RECT  9.504 92.005 9.522 92.011 ;
     RECT  10.296 91.991 15.282 92.011 ;
     RECT  31.932 91.975 32.886 92.011 ;
     RECT  54.432 91.975 54.882 92.011 ;
     RECT  63.036 91.589 63.054 92.011 ;
     RECT  63.864 91.831 65.142 92.011 ;
     RECT  66.024 91.859 67.698 92.011 ;
     RECT  81.324 91.757 86.598 92.011 ;
     RECT  88.2 83.497 89.097 92.011 ;
     RECT  161.064 67.853 162.486 92.011 ;
     RECT  28.944 91.705 30.258 92.059 ;
     RECT  31.248 92.011 32.886 92.059 ;
     RECT  139.32 71.609 140.814 92.101 ;
     RECT  141.552 69.197 147.33 92.101 ;
     RECT  63.036 92.011 67.698 92.129 ;
     RECT  100.872 91.771 100.89 92.129 ;
     RECT  150.768 91.859 150.93 92.129 ;
     RECT  153 91.931 155.61 92.129 ;
     RECT  76.536 91.963 77.022 92.237 ;
     RECT  81.324 92.011 86.634 92.237 ;
     RECT  17.028 91.741 20.358 92.245 ;
     RECT  21.204 91.741 27.99 92.245 ;
     RECT  36.18 91.472 41.526 92.245 ;
     RECT  85.68 92.237 86.634 92.245 ;
     RECT  87.804 92.011 89.097 92.245 ;
     RECT  6.804 91.771 8.097 92.281 ;
     RECT  9.504 92.011 15.354 92.281 ;
     RECT  33.84 91.589 35.406 92.281 ;
     RECT  36.18 92.245 41.67 92.281 ;
     RECT  54.432 92.011 54.918 92.281 ;
     RECT  91.332 92.245 91.35 92.281 ;
     RECT  92.304 70.069 92.97 92.281 ;
     RECT  95.256 91.771 95.49 92.281 ;
     RECT  96.408 89.771 96.966 92.281 ;
     RECT  98.28 91.771 98.298 92.281 ;
     RECT  105.015 91.771 106.038 92.281 ;
     RECT  136.116 91.499 138.042 92.281 ;
     RECT  156.456 70.877 156.834 92.281 ;
     RECT  163.728 43.979 164.934 92.281 ;
     RECT  68.616 91.867 75.762 92.309 ;
     RECT  91.332 92.281 92.97 92.333 ;
     RECT  98.28 92.281 98.406 92.347 ;
     RECT  99.615 70.169 99.897 92.347 ;
     RECT  100.8 92.281 100.818 92.347 ;
     RECT  110.415 71.249 110.697 92.347 ;
     RECT  115.815 69.373 116.766 92.347 ;
     RECT  6.804 92.281 15.354 92.371 ;
     RECT  16.524 92.245 27.99 92.371 ;
     RECT  28.944 92.059 32.886 92.371 ;
     RECT  33.84 92.281 41.67 92.371 ;
     RECT  42.624 91.859 49.122 92.371 ;
     RECT  50.184 91.769 51.297 92.371 ;
     RECT  65.556 92.129 67.698 92.399 ;
     RECT  151.992 91.931 152.01 92.399 ;
     RECT  65.664 92.399 67.698 92.435 ;
     RECT  52.02 91.975 53.622 92.443 ;
     RECT  54.432 92.281 54.99 92.443 ;
     RECT  55.836 91.661 57.186 92.443 ;
     RECT  57.924 92.011 57.942 92.443 ;
     RECT  58.716 91.669 62.097 92.443 ;
     RECT  54.432 92.443 57.942 92.479 ;
     RECT  58.716 92.443 62.19 92.479 ;
     RECT  148.215 91.859 149.994 92.515 ;
     RECT  66.024 92.435 67.698 92.543 ;
     RECT  81.324 92.237 84.906 92.551 ;
     RECT  91.692 92.333 92.97 92.551 ;
     RECT  102.78 92.347 102.798 92.551 ;
     RECT  103.536 92.347 103.554 92.551 ;
     RECT  107.856 92.347 108.342 92.551 ;
     RECT  112.968 92.347 113.634 92.551 ;
     RECT  115.632 92.347 116.766 92.551 ;
     RECT  117.72 92.347 118.062 92.551 ;
     RECT  131.544 91.471 132.534 92.551 ;
     RECT  134.784 91.499 135.306 92.551 ;
     RECT  163.584 92.281 164.934 92.551 ;
     RECT  167.616 41.521 167.634 92.551 ;
     RECT  139.32 92.101 147.33 92.641 ;
     RECT  160.668 92.011 162.486 92.641 ;
     RECT  163.584 92.551 165.366 92.641 ;
     RECT  6.804 92.371 27.99 92.669 ;
     RECT  42.624 92.371 51.297 92.669 ;
     RECT  68.616 92.309 71.046 92.669 ;
     RECT  95.256 92.281 96.966 92.669 ;
     RECT  110.016 92.347 111.366 92.669 ;
     RECT  122.58 68.143 123.03 92.669 ;
     RECT  126.216 89.815 128.538 92.669 ;
     RECT  148.14 92.515 149.994 92.669 ;
     RECT  6.804 92.669 10.638 92.677 ;
     RECT  6.768 92.677 10.638 92.713 ;
     RECT  156.456 92.281 157.194 92.713 ;
     RECT  119.088 83.497 119.106 92.749 ;
     RECT  126.216 92.669 126.897 92.749 ;
     RECT  134.712 92.551 135.306 92.749 ;
     RECT  160.668 92.641 165.366 92.749 ;
     RECT  166.104 89.743 166.806 92.749 ;
     RECT  28.944 92.371 41.67 92.785 ;
     RECT  42.624 92.669 42.858 92.785 ;
     RECT  76.608 92.237 77.022 92.785 ;
     RECT  77.796 91.859 80.19 92.785 ;
     RECT  81.18 92.551 84.906 92.785 ;
     RECT  148.176 92.669 149.994 92.785 ;
     RECT  150.768 92.129 150.786 92.785 ;
     RECT  156.384 92.713 157.194 92.785 ;
     RECT  158.148 70.301 158.166 92.785 ;
     RECT  167.616 92.551 167.706 92.785 ;
     RECT  5.976 92.677 5.994 92.821 ;
     RECT  6.732 92.713 10.638 92.821 ;
     RECT  28.944 92.785 42.858 92.821 ;
     RECT  93.852 77.357 94.497 92.821 ;
     RECT  95.256 92.669 95.562 92.821 ;
     RECT  96.408 92.669 96.966 92.821 ;
     RECT  97.812 92.347 98.406 92.821 ;
     RECT  117.648 92.551 118.062 92.821 ;
     RECT  119.088 92.749 119.142 92.821 ;
     RECT  120.06 92.347 120.078 92.821 ;
     RECT  121.068 89.779 121.497 92.821 ;
     RECT  133.38 76.045 133.722 92.821 ;
     RECT  134.568 92.749 135.306 92.821 ;
     RECT  159.015 91.859 159.297 92.821 ;
     RECT  167.58 92.785 167.706 92.821 ;
     RECT  45.288 92.669 51.297 92.909 ;
     RECT  45.615 92.909 51.297 92.911 ;
     RECT  52.02 92.443 53.694 92.911 ;
     RECT  54.432 92.479 62.19 92.911 ;
     RECT  85.68 92.245 89.097 92.911 ;
     RECT  89.82 92.749 89.838 92.911 ;
     RECT  96.408 92.821 98.406 92.911 ;
     RECT  102.78 92.551 103.554 92.911 ;
     RECT  105.015 92.281 106.11 92.911 ;
     RECT  107.784 92.551 108.45 92.911 ;
     RECT  110.016 92.669 110.697 92.911 ;
     RECT  115.344 92.551 116.766 92.911 ;
     RECT  153 92.129 154.602 92.911 ;
     RECT  104.868 92.911 106.11 92.923 ;
     RECT  107.352 92.911 108.45 92.923 ;
     RECT  112.896 92.551 113.634 92.923 ;
     RECT  114.804 92.911 116.766 92.923 ;
     RECT  99.615 92.347 100.818 92.939 ;
     RECT  104.868 92.923 106.614 92.939 ;
     RECT  121.068 92.821 122.13 92.939 ;
     RECT  139.32 92.641 147.402 92.939 ;
     RECT  127.764 92.669 128.538 92.947 ;
     RECT  133.308 92.821 133.722 92.947 ;
     RECT  152.928 92.911 154.602 92.947 ;
     RECT  107.352 92.923 108.99 92.971 ;
     RECT  109.728 92.911 110.697 92.971 ;
     RECT  121.068 92.939 121.698 92.971 ;
     RECT  71.82 92.309 75.762 92.983 ;
     RECT  127.764 92.947 128.718 92.983 ;
     RECT  133.308 92.947 133.794 92.983 ;
     RECT  134.532 92.821 135.306 92.983 ;
     RECT  155.592 92.129 155.61 92.983 ;
     RECT  156.384 92.785 158.166 92.983 ;
     RECT  63.18 92.129 64.422 93.055 ;
     RECT  66.24 92.543 67.698 93.055 ;
     RECT  122.94 92.669 123.03 93.055 ;
     RECT  129.888 73.949 129.906 93.055 ;
     RECT  130.644 73.949 130.662 93.055 ;
     RECT  131.4 92.551 132.534 93.055 ;
     RECT  139.32 92.939 140.49 93.055 ;
     RECT  90.684 92.713 90.702 93.091 ;
     RECT  91.692 92.551 93.042 93.091 ;
     RECT  93.852 92.821 95.562 93.091 ;
     RECT  96.408 92.911 98.802 93.091 ;
     RECT  99.615 92.939 100.314 93.091 ;
     RECT  102.168 92.911 104.13 93.091 ;
     RECT  104.868 92.939 105.57 93.091 ;
     RECT  106.524 92.939 106.614 93.091 ;
     RECT  107.352 92.971 110.697 93.091 ;
     RECT  111.636 92.923 111.654 93.091 ;
     RECT  112.896 92.923 116.766 93.091 ;
     RECT  117.648 92.821 118.134 93.091 ;
     RECT  118.98 92.821 120.078 93.091 ;
     RECT  121.032 92.971 121.698 93.091 ;
     RECT  122.94 93.055 123.714 93.091 ;
     RECT  126.108 92.749 126.897 93.091 ;
     RECT  129.888 93.055 132.534 93.091 ;
     RECT  133.308 92.983 135.306 93.091 ;
     RECT  152.028 92.947 154.602 93.091 ;
     RECT  155.592 92.983 158.166 93.091 ;
     RECT  85.68 92.911 89.838 93.181 ;
     RECT  90.684 93.091 93.042 93.181 ;
     RECT  85.68 93.181 93.042 93.211 ;
     RECT  93.78 93.091 95.562 93.211 ;
     RECT  148.176 92.785 150.786 93.211 ;
     RECT  45.615 92.911 62.19 93.245 ;
     RECT  148.176 93.211 150.858 93.251 ;
     RECT  152.028 93.091 158.166 93.251 ;
     RECT  5.976 92.821 10.638 93.253 ;
     RECT  71.82 92.983 75.798 93.253 ;
     RECT  53.028 93.245 62.19 93.289 ;
     RECT  63.144 93.055 64.422 93.289 ;
     RECT  68.688 92.669 71.046 93.289 ;
     RECT  71.82 93.253 75.834 93.289 ;
     RECT  76.608 92.785 84.906 93.289 ;
     RECT  85.68 93.211 95.562 93.289 ;
     RECT  159.015 92.821 159.426 93.289 ;
     RECT  129.888 93.091 135.306 93.307 ;
     RECT  136.044 92.281 138.042 93.307 ;
     RECT  68.688 93.289 75.834 93.325 ;
     RECT  76.608 93.289 95.562 93.325 ;
     RECT  111.636 93.091 116.766 93.325 ;
     RECT  129.888 93.307 138.042 93.325 ;
     RECT  152.208 93.251 158.166 93.325 ;
     RECT  159.015 93.289 159.462 93.325 ;
     RECT  160.668 92.749 166.806 93.325 ;
     RECT  68.688 93.325 95.562 93.353 ;
     RECT  124.632 93.091 126.897 93.353 ;
     RECT  148.176 93.251 150.57 93.353 ;
     RECT  152.208 93.325 166.806 93.353 ;
     RECT  111.636 93.325 116.91 93.361 ;
     RECT  117.648 93.091 120.078 93.361 ;
     RECT  120.924 93.091 121.698 93.361 ;
     RECT  127.764 92.983 128.934 93.361 ;
     RECT  129.888 93.325 138.222 93.361 ;
     RECT  167.58 92.821 167.742 93.361 ;
     RECT  53.028 93.289 64.422 93.389 ;
     RECT  66.24 93.055 67.806 93.403 ;
     RECT  68.688 93.353 70.29 93.403 ;
     RECT  4.86 93.445 4.878 93.451 ;
     RECT  11.412 92.669 27.558 93.451 ;
     RECT  28.404 92.821 42.858 93.451 ;
     RECT  66.24 93.403 70.29 93.451 ;
     RECT  101.052 92.971 101.178 93.451 ;
     RECT  102.096 93.091 105.57 93.451 ;
     RECT  124.848 93.353 126.897 93.451 ;
     RECT  127.764 93.361 138.33 93.451 ;
     RECT  139.176 93.055 140.49 93.451 ;
     RECT  155.448 93.353 166.806 93.451 ;
     RECT  167.58 93.361 167.814 93.451 ;
     RECT  11.412 93.451 42.858 93.479 ;
     RECT  45.615 93.245 52.254 93.479 ;
     RECT  53.028 93.389 59.022 93.479 ;
     RECT  59.868 93.389 64.422 93.479 ;
     RECT  65.628 93.451 70.29 93.479 ;
     RECT  71.028 93.353 95.562 93.479 ;
     RECT  101.052 93.451 105.57 93.479 ;
     RECT  111.636 93.361 121.698 93.479 ;
     RECT  149.544 93.353 150.534 93.479 ;
     RECT  152.208 93.353 154.674 93.479 ;
     RECT  155.448 93.451 167.958 93.479 ;
     RECT  4.86 93.451 5.022 93.485 ;
     RECT  65.628 93.479 67.497 93.487 ;
     RECT  15.408 93.479 42.858 93.502 ;
     RECT  65.484 93.487 67.497 93.533 ;
     RECT  155.448 93.479 157.41 93.533 ;
     RECT  46.764 93.479 52.254 93.551 ;
     RECT  106.524 93.091 110.697 93.595 ;
     RECT  5.832 93.253 10.638 93.631 ;
     RECT  11.412 93.479 14.49 93.631 ;
     RECT  43.668 92.669 44.514 93.631 ;
     RECT  111.636 93.479 119.286 93.631 ;
     RECT  43.668 93.631 44.622 93.691 ;
     RECT  120.132 93.479 121.698 93.691 ;
     RECT  96.408 93.091 100.314 93.721 ;
     RECT  101.052 93.479 101.394 93.721 ;
     RECT  15.408 93.502 21.114 93.749 ;
     RECT  68.364 93.479 70.29 93.749 ;
     RECT  76.932 93.479 92.682 93.749 ;
     RECT  111.564 93.631 119.286 93.749 ;
     RECT  148.176 93.353 148.806 93.749 ;
     RECT  43.668 93.691 44.838 93.785 ;
     RECT  46.872 93.551 52.254 93.785 ;
     RECT  80.1 93.749 85.878 93.821 ;
     RECT  141.372 92.939 147.402 93.865 ;
     RECT  148.176 93.749 148.698 93.865 ;
     RECT  43.704 93.785 44.838 93.901 ;
     RECT  45.615 93.479 45.99 93.901 ;
     RECT  93.42 93.479 95.562 93.901 ;
     RECT  96.408 93.721 101.394 93.901 ;
     RECT  102.24 93.479 105.57 93.901 ;
     RECT  106.524 93.595 110.754 93.901 ;
     RECT  120.132 93.691 122.022 93.901 ;
     RECT  124.848 93.451 140.49 93.901 ;
     RECT  141.372 93.865 148.698 93.901 ;
     RECT  71.028 93.479 76.194 93.917 ;
     RECT  15.408 93.749 20.934 93.929 ;
     RECT  86.652 93.749 92.682 93.929 ;
     RECT  124.848 93.901 148.698 93.929 ;
     RECT  5.004 93.485 5.022 93.991 ;
     RECT  5.796 93.631 14.49 93.991 ;
     RECT  17.676 93.929 20.934 94.019 ;
     RECT  21.852 93.502 42.858 94.019 ;
     RECT  43.704 93.901 45.99 94.019 ;
     RECT  59.868 93.479 64.314 94.019 ;
     RECT  81.396 93.821 85.878 94.019 ;
     RECT  111.564 93.749 117.234 94.019 ;
     RECT  122.94 93.091 123.858 94.019 ;
     RECT  156.996 93.533 157.41 94.019 ;
     RECT  102.24 93.901 110.754 94.027 ;
     RECT  111.564 94.019 117.126 94.027 ;
     RECT  151.416 93.289 151.434 94.027 ;
     RECT  152.208 93.479 154.602 94.027 ;
     RECT  71.028 93.917 74.25 94.055 ;
     RECT  117.972 93.749 119.286 94.055 ;
     RECT  158.148 93.479 167.958 94.055 ;
     RECT  158.22 94.055 167.958 94.099 ;
     RECT  86.976 93.929 92.682 94.127 ;
     RECT  155.448 93.533 156.186 94.135 ;
     RECT  149.724 93.479 150.534 94.171 ;
     RECT  158.22 94.099 168.426 94.171 ;
     RECT  158.22 94.171 168.462 94.289 ;
     RECT  5.004 93.991 14.49 94.405 ;
     RECT  15.408 93.929 16.83 94.405 ;
     RECT  21.852 94.019 42.102 94.405 ;
     RECT  43.74 94.019 45.99 94.405 ;
     RECT  46.872 93.785 49.878 94.405 ;
     RECT  50.616 93.785 52.254 94.405 ;
     RECT  53.064 93.479 59.022 94.405 ;
     RECT  68.364 93.749 70.218 94.405 ;
     RECT  90.072 94.127 92.682 94.405 ;
     RECT  93.42 93.901 101.394 94.405 ;
     RECT  120.132 93.901 122.202 94.405 ;
     RECT  122.94 94.019 123.39 94.405 ;
     RECT  124.848 93.929 127.53 94.405 ;
     RECT  151.416 94.027 154.602 94.405 ;
     RECT  155.34 94.135 156.186 94.405 ;
     RECT  158.22 94.289 168.426 94.559 ;
     RECT  158.22 94.559 168.318 94.595 ;
     RECT  75.204 93.917 76.194 94.675 ;
     RECT  4.932 94.405 16.83 94.711 ;
     RECT  17.676 94.019 20.754 94.711 ;
     RECT  42.84 94.019 42.858 94.711 ;
     RECT  43.74 94.405 49.878 94.711 ;
     RECT  50.616 94.405 59.022 94.711 ;
     RECT  65.628 93.533 67.497 94.711 ;
     RECT  68.22 94.405 70.218 94.711 ;
     RECT  75.132 94.675 76.194 94.711 ;
     RECT  76.932 93.749 79.038 94.711 ;
     RECT  80.1 93.821 80.37 94.711 ;
     RECT  81.396 94.019 85.806 94.711 ;
     RECT  86.976 94.127 89.334 94.711 ;
     RECT  90.072 94.405 101.466 94.711 ;
     RECT  102.24 94.027 117.126 94.711 ;
     RECT  124.56 94.405 127.53 94.711 ;
     RECT  128.304 93.929 148.698 94.711 ;
     RECT  149.724 94.171 150.606 94.711 ;
     RECT  151.416 94.405 156.186 94.711 ;
     RECT  156.996 94.019 157.338 94.711 ;
     RECT  2.415 2.413 2.697 94.787 ;
     RECT  169.815 2.413 170.097 94.787 ;
     RECT  4.572 94.711 20.754 94.829 ;
     RECT  124.56 94.711 148.878 94.829 ;
     RECT  151.344 94.711 156.186 94.829 ;
     RECT  81.18 94.711 85.806 94.865 ;
     RECT  4.608 94.829 20.754 94.945 ;
     RECT  21.672 94.405 42.102 94.945 ;
     RECT  42.84 94.711 43.002 94.945 ;
     RECT  43.74 94.711 59.022 94.945 ;
     RECT  59.868 94.019 60.246 94.945 ;
     RECT  61.128 94.019 64.314 94.945 ;
     RECT  65.484 94.711 70.218 94.945 ;
     RECT  71.028 94.055 73.926 94.945 ;
     RECT  75.132 94.711 79.038 94.945 ;
     RECT  79.92 94.711 80.37 94.945 ;
     RECT  81.18 94.865 85.734 94.945 ;
     RECT  86.652 94.711 89.334 94.945 ;
     RECT  90.072 94.711 117.126 94.945 ;
     RECT  117.972 94.055 119.106 94.945 ;
     RECT  119.844 94.405 123.39 94.945 ;
     RECT  134.964 94.829 148.878 94.945 ;
     RECT  149.652 94.711 150.606 94.945 ;
     RECT  151.992 94.829 156.186 94.945 ;
     RECT  156.96 94.711 157.338 94.945 ;
     RECT  158.22 94.595 168.246 94.945 ;
     RECT  4.608 94.945 85.734 95.009 ;
     RECT  86.472 94.945 123.678 95.009 ;
     RECT  4.608 95.009 63.882 95.021 ;
     RECT  64.764 95.009 85.482 95.021 ;
     RECT  87.336 95.009 123.678 95.021 ;
     RECT  124.56 94.829 132.93 95.021 ;
     RECT  133.704 94.829 134.226 95.021 ;
     RECT  134.964 94.945 151.254 95.021 ;
     RECT  151.992 94.945 168.246 95.021 ;
     RECT  2.415 94.787 2.505 95.057 ;
     RECT  13.215 95.021 13.41 95.057 ;
     RECT  18.396 95.021 18.705 95.057 ;
     RECT  29.415 95.021 29.718 95.057 ;
     RECT  34.704 95.021 34.905 95.057 ;
     RECT  45.615 95.021 45.99 95.057 ;
     RECT  50.976 95.021 51.105 95.057 ;
     RECT  61.815 95.021 62.298 95.057 ;
     RECT  83.415 95.021 83.574 95.057 ;
     RECT  88.596 95.021 88.905 95.057 ;
     RECT  99.615 95.021 99.882 95.057 ;
     RECT  104.868 95.021 105.105 95.057 ;
     RECT  115.815 95.021 116.154 95.057 ;
     RECT  121.176 95.021 121.305 95.057 ;
     RECT  132.015 95.021 132.462 95.057 ;
     RECT  153.615 95.021 153.774 95.057 ;
     RECT  169.815 94.787 169.905 95.057 ;
     RECT  66.024 95.021 67.374 95.135 ;
     RECT  136.188 95.021 137.574 95.135 ;
     RECT  56.016 95.021 57.258 95.165 ;
     RECT  126.18 95.021 127.458 95.165 ;
     RECT  142.452 95.021 143.73 95.165 ;
     RECT  147.492 95.021 148.77 95.165 ;
     RECT  158.76 95.021 160.038 95.165 ;
     RECT  7.128 95.021 8.406 95.213 ;
     RECT  23.436 95.021 24.678 95.213 ;
     RECT  39.708 95.021 40.986 95.213 ;
     RECT  47.232 95.021 48.51 95.213 ;
     RECT  59.76 95.021 61.038 95.213 ;
     RECT  66.024 95.135 67.302 95.213 ;
     RECT  72.288 95.021 73.566 95.213 ;
     RECT  77.292 95.021 79.83 95.213 ;
     RECT  91.08 95.021 92.358 95.213 ;
     RECT  93.6 95.021 94.878 95.213 ;
     RECT  109.872 95.021 112.41 95.213 ;
     RECT  163.764 95.021 165.042 95.213 ;
     RECT  167.544 95.021 168.246 95.789 ;
     RECT  9.648 95.021 10.89 96.365 ;
     RECT  86.472 95.009 86.49 96.365 ;
     RECT  111.132 95.213 112.41 96.365 ;
     RECT  117.396 95.021 118.674 96.365 ;
     RECT  136.188 95.135 137.466 96.365 ;
     RECT  155.016 95.021 156.258 96.365 ;
     RECT  4.608 95.021 4.626 97.068 ;
     RECT  5.868 95.021 5.886 97.068 ;
     RECT  7.128 95.213 7.146 97.068 ;
     RECT  8.388 95.213 8.406 97.068 ;
     RECT  9.648 96.365 9.666 97.068 ;
     RECT  10.872 96.365 10.89 97.068 ;
     RECT  12.132 95.021 12.15 97.068 ;
     RECT  13.392 95.057 13.41 97.068 ;
     RECT  14.652 95.021 14.67 97.068 ;
     RECT  15.912 95.021 15.93 97.068 ;
     RECT  17.172 95.021 17.19 97.068 ;
     RECT  18.396 95.057 18.414 97.068 ;
     RECT  19.656 95.021 19.674 97.068 ;
     RECT  20.916 95.021 20.934 97.068 ;
     RECT  22.176 95.021 22.194 97.068 ;
     RECT  23.436 95.213 23.454 97.068 ;
     RECT  24.66 95.213 24.678 97.068 ;
     RECT  25.92 95.021 25.938 97.068 ;
     RECT  27.18 95.021 27.198 97.068 ;
     RECT  28.44 95.021 28.458 97.068 ;
     RECT  29.7 95.057 29.718 97.068 ;
     RECT  30.924 95.021 30.942 97.068 ;
     RECT  32.184 95.021 32.202 97.068 ;
     RECT  33.444 95.021 33.462 97.068 ;
     RECT  34.704 95.057 34.722 97.068 ;
     RECT  35.964 95.021 35.982 97.068 ;
     RECT  37.188 95.021 37.206 97.068 ;
     RECT  38.448 95.021 38.466 97.068 ;
     RECT  39.708 95.213 39.726 97.068 ;
     RECT  40.968 95.213 40.986 97.068 ;
     RECT  42.228 95.021 42.246 97.068 ;
     RECT  43.488 95.021 43.506 97.068 ;
     RECT  44.712 95.021 44.73 97.068 ;
     RECT  45.972 95.057 45.99 97.068 ;
     RECT  47.232 95.213 47.25 97.068 ;
     RECT  48.492 95.213 48.51 97.068 ;
     RECT  49.752 95.021 49.77 97.068 ;
     RECT  50.976 95.057 50.994 97.068 ;
     RECT  52.236 95.021 52.254 97.068 ;
     RECT  53.496 95.021 53.514 97.068 ;
     RECT  54.756 95.021 54.774 97.068 ;
     RECT  56.016 95.165 56.034 97.068 ;
     RECT  57.24 95.165 57.258 97.068 ;
     RECT  58.5 95.021 58.518 97.068 ;
     RECT  59.76 95.213 59.778 97.068 ;
     RECT  61.02 95.213 61.038 97.068 ;
     RECT  62.28 95.057 62.298 97.068 ;
     RECT  63.504 95.021 63.522 97.068 ;
     RECT  64.764 95.021 64.782 97.068 ;
     RECT  66.024 95.213 66.042 97.068 ;
     RECT  67.284 95.213 67.302 97.068 ;
     RECT  68.544 95.021 68.562 97.068 ;
     RECT  69.804 95.021 69.822 97.068 ;
     RECT  71.028 95.021 71.046 97.068 ;
     RECT  72.288 95.213 72.306 97.068 ;
     RECT  73.548 95.213 73.566 97.068 ;
     RECT  74.808 95.021 74.826 97.068 ;
     RECT  76.068 95.021 76.086 97.068 ;
     RECT  77.292 95.213 77.31 97.068 ;
     RECT  78.552 95.213 78.57 97.068 ;
     RECT  79.812 95.213 79.83 97.068 ;
     RECT  81.072 95.021 81.09 97.068 ;
     RECT  82.332 95.021 82.35 97.068 ;
     RECT  83.556 95.057 83.574 97.068 ;
     RECT  84.816 95.021 84.834 97.068 ;
     RECT  86.076 96.955 86.094 97.068 ;
     RECT  87.336 95.021 87.354 97.068 ;
     RECT  88.596 95.057 88.614 97.068 ;
     RECT  89.82 95.021 89.838 97.068 ;
     RECT  91.08 95.213 91.098 97.068 ;
     RECT  92.34 95.213 92.358 97.068 ;
     RECT  93.6 95.213 93.618 97.068 ;
     RECT  94.86 95.213 94.878 97.068 ;
     RECT  96.12 95.021 96.138 97.068 ;
     RECT  97.344 95.021 97.362 97.068 ;
     RECT  98.604 95.021 98.622 97.068 ;
     RECT  99.864 95.057 99.882 97.068 ;
     RECT  101.124 95.021 101.142 97.068 ;
     RECT  102.384 95.021 102.402 97.068 ;
     RECT  103.608 95.021 103.626 97.068 ;
     RECT  104.868 95.057 104.886 97.068 ;
     RECT  106.128 95.021 106.146 97.068 ;
     RECT  107.388 95.021 107.406 97.068 ;
     RECT  108.648 95.021 108.666 97.068 ;
     RECT  109.872 95.213 109.89 97.068 ;
     RECT  111.132 96.365 111.15 97.068 ;
     RECT  112.392 96.365 112.41 97.068 ;
     RECT  113.652 95.021 113.67 97.068 ;
     RECT  114.912 95.021 114.93 97.068 ;
     RECT  116.136 95.057 116.154 97.068 ;
     RECT  117.396 96.365 117.414 97.068 ;
     RECT  118.656 96.365 118.674 97.068 ;
     RECT  119.916 95.021 119.934 97.068 ;
     RECT  121.176 95.057 121.194 97.068 ;
     RECT  122.436 95.021 122.454 97.068 ;
     RECT  123.66 95.021 123.678 97.068 ;
     RECT  124.92 95.021 124.938 97.068 ;
     RECT  126.18 95.165 126.198 97.068 ;
     RECT  127.44 95.165 127.458 97.068 ;
     RECT  128.7 95.021 128.718 97.068 ;
     RECT  129.924 95.021 129.942 97.068 ;
     RECT  131.184 95.021 131.202 97.068 ;
     RECT  132.444 95.057 132.462 97.068 ;
     RECT  133.704 95.021 133.722 97.068 ;
     RECT  134.964 95.021 134.982 97.068 ;
     RECT  136.188 96.365 136.206 97.068 ;
     RECT  137.448 96.365 137.466 97.068 ;
     RECT  138.708 95.021 138.726 97.068 ;
     RECT  139.968 95.021 139.986 97.068 ;
     RECT  141.228 95.021 141.246 97.068 ;
     RECT  142.452 95.165 142.47 97.068 ;
     RECT  143.712 95.165 143.73 97.068 ;
     RECT  144.972 95.021 144.99 97.068 ;
     RECT  146.232 95.021 146.25 97.068 ;
     RECT  147.492 95.165 147.51 97.068 ;
     RECT  148.752 95.165 148.77 97.068 ;
     RECT  149.976 95.021 149.994 97.068 ;
     RECT  151.236 95.021 151.254 97.068 ;
     RECT  152.496 95.021 152.514 97.068 ;
     RECT  153.756 95.057 153.774 97.068 ;
     RECT  155.016 96.365 155.034 97.068 ;
     RECT  156.24 96.365 156.258 97.068 ;
     RECT  157.5 95.021 157.518 97.068 ;
     RECT  158.76 95.165 158.778 97.068 ;
     RECT  160.02 95.165 160.038 97.068 ;
     RECT  161.28 95.021 161.298 97.068 ;
     RECT  162.504 95.021 162.522 97.068 ;
     RECT  163.764 95.213 163.782 97.068 ;
     RECT  165.024 95.213 165.042 97.068 ;
     RECT  166.284 95.021 166.302 97.068 ;
     RECT  167.544 95.789 167.562 97.068 ;
    LAYER M4 ;
     RECT  2.408 2.148 2.512 95.052 ;
     RECT  2.512 2.418 2.704 94.782 ;
     RECT  5.221 94.992 5.308 95.016 ;
     RECT  5.269 0.192 5.465 0.216 ;
     RECT  4.849 93.456 5.821 93.48 ;
     RECT  5.821 93.456 5.948 94.248 ;
     RECT  5.948 92.688 6.035 94.248 ;
     RECT  4.309 3.984 6.505 4.008 ;
     RECT  6.505 3.984 6.545 4.104 ;
     RECT  6.469 94.992 6.581 95.016 ;
     RECT  6.565 1.152 6.869 1.176 ;
     RECT  7.405 91.776 7.669 91.8 ;
     RECT  6.545 4.08 7.808 4.104 ;
     RECT  7.369 10.704 7.808 10.728 ;
     RECT  7.669 91.152 7.808 91.8 ;
     RECT  6.035 93.216 7.808 93.336 ;
     RECT  7.724 95.184 7.808 95.208 ;
     RECT  7.808 2.148 7.811 95.208 ;
     RECT  7.765 0.528 7.859 0.552 ;
     RECT  7.811 2.148 7.912 95.052 ;
     RECT  7.912 2.418 8.104 94.782 ;
     RECT  8.104 10.224 9.001 10.728 ;
     RECT  8.917 94.992 9.059 95.016 ;
     RECT  8.104 3.936 9.065 3.96 ;
     RECT  8.104 92.736 9.107 93.528 ;
     RECT  9.109 0.192 9.317 0.216 ;
     RECT  8.104 91.152 9.493 91.176 ;
     RECT  9.107 92.736 9.493 93.48 ;
     RECT  9.596 26.64 9.637 26.664 ;
     RECT  9.637 26.208 9.683 26.664 ;
     RECT  8.104 27.744 9.683 28.536 ;
     RECT  9.877 18.912 9.889 18.936 ;
     RECT  9.745 3.168 9.923 3.192 ;
     RECT  9.205 4.512 9.923 4.536 ;
     RECT  8.104 14.352 10.213 14.376 ;
     RECT  9.001 10.704 10.259 10.728 ;
     RECT  9.889 18.816 10.259 18.936 ;
     RECT  9.683 26.208 10.259 26.232 ;
     RECT  9.683 28.512 10.289 28.536 ;
     RECT  10.213 14.352 10.297 14.808 ;
     RECT  10.177 96.336 10.307 96.36 ;
     RECT  9.493 91.152 10.325 93.48 ;
     RECT  10.325 92.736 10.397 93.432 ;
     RECT  10.405 0.192 10.757 0.216 ;
     RECT  10.297 14.352 10.865 14.472 ;
     RECT  11.401 94.992 11.555 95.016 ;
     RECT  10.933 25.968 11.653 25.992 ;
     RECT  10.325 91.152 11.653 91.752 ;
     RECT  10.397 92.736 11.653 92.76 ;
     RECT  11.653 22.176 11.689 22.2 ;
     RECT  11.653 91.152 11.689 92.76 ;
     RECT  11.689 91.152 11.699 93.48 ;
     RECT  11.653 25.968 11.837 26.808 ;
     RECT  11.701 28.704 11.837 28.728 ;
     RECT  11.701 30.24 11.837 30.264 ;
     RECT  11.756 4.272 11.843 4.296 ;
     RECT  11.689 22.176 12.053 22.776 ;
     RECT  11.837 25.968 12.193 26.616 ;
     RECT  11.699 92.208 12.233 93.48 ;
     RECT  12.193 27.84 12.301 27.864 ;
     RECT  11.699 91.152 12.62 91.176 ;
     RECT  12.589 53.04 12.625 53.064 ;
     RECT  12.625 53.04 13.052 53.304 ;
     RECT  12.301 27.792 13.093 27.864 ;
     RECT  12.193 25.68 13.129 26.616 ;
     RECT  13.093 27.792 13.129 28.008 ;
     RECT  11.653 1.152 13.133 1.176 ;
     RECT  13.129 25.68 13.165 28.008 ;
     RECT  13.129 29.04 13.165 29.064 ;
     RECT  13.093 4.512 13.208 4.536 ;
     RECT  10.865 14.448 13.208 14.472 ;
     RECT  12.661 17.472 13.208 17.496 ;
     RECT  12.053 22.752 13.208 22.776 ;
     RECT  13.165 25.68 13.208 29.064 ;
     RECT  12.409 30.864 13.208 30.888 ;
     RECT  13.052 53.04 13.208 54.12 ;
     RECT  12.62 91.104 13.208 91.176 ;
     RECT  12.233 92.208 13.208 93 ;
     RECT  12.697 94.992 13.208 95.016 ;
     RECT  13.208 2.148 13.312 95.052 ;
     RECT  13.312 2.418 13.504 95.016 ;
     RECT  13.504 53.04 13.619 54.12 ;
     RECT  13.504 26.112 13.745 28.536 ;
     RECT  13.504 4.512 13.955 4.536 ;
     RECT  13.504 19.104 13.996 19.416 ;
     RECT  13.504 94.992 14.051 95.016 ;
     RECT  13.745 26.112 14.099 27.144 ;
     RECT  13.504 14.448 14.243 14.472 ;
     RECT  13.504 17.472 14.284 17.592 ;
     RECT  14.245 0.192 14.429 0.216 ;
     RECT  13.504 30.192 14.821 31.128 ;
     RECT  13.745 28.512 14.849 28.536 ;
     RECT  14.821 29.76 14.849 31.128 ;
     RECT  14.099 27.12 14.857 27.144 ;
     RECT  14.849 28.512 14.857 31.128 ;
     RECT  13.619 53.04 14.857 53.976 ;
     RECT  14.857 27.12 14.915 31.128 ;
     RECT  14.929 20.544 14.965 20.568 ;
     RECT  14.965 20.496 15.145 20.568 ;
     RECT  14.929 4.512 15.203 4.536 ;
     RECT  14.915 27.12 15.289 30.792 ;
     RECT  15.181 94.992 15.299 95.016 ;
     RECT  15.289 26.832 15.361 30.792 ;
     RECT  13.504 91.152 15.365 93.096 ;
     RECT  13.996 19.344 15.397 19.416 ;
     RECT  15.145 20.496 15.397 21.432 ;
     RECT  15.397 19.344 15.443 21.432 ;
     RECT  15.361 26.208 15.473 30.792 ;
     RECT  13.504 22.752 15.587 23.592 ;
     RECT  15.533 25.104 15.617 25.128 ;
     RECT  15.473 26.736 15.689 30.792 ;
     RECT  15.365 92.4 15.925 93.096 ;
     RECT  15.925 92.4 16.012 93.528 ;
     RECT  16.009 3.936 16.093 3.96 ;
     RECT  15.541 1.152 16.121 1.176 ;
     RECT  15.443 19.968 16.373 21.432 ;
     RECT  15.689 26.736 16.469 30.312 ;
     RECT  16.021 24.864 16.547 24.888 ;
     RECT  16.441 94.992 16.547 95.016 ;
     RECT  14.857 53.04 16.549 54.12 ;
     RECT  16.469 26.208 16.553 30.312 ;
     RECT  16.012 92.688 16.597 93.528 ;
     RECT  15.587 23.568 16.693 23.592 ;
     RECT  16.553 27.072 16.697 30.312 ;
     RECT  14.284 17.472 16.739 17.496 ;
     RECT  16.697 27.072 16.805 29.592 ;
     RECT  16.757 0.192 16.841 0.216 ;
     RECT  16.805 27.072 16.949 29.064 ;
     RECT  17.017 30.576 17.089 30.6 ;
     RECT  17.089 30.576 17.125 30.744 ;
     RECT  16.597 92.688 17.129 94.248 ;
     RECT  16.549 53.04 17.341 54.264 ;
     RECT  16.949 27.072 17.521 27.672 ;
     RECT  17.129 94.224 17.665 94.248 ;
     RECT  16.373 20.544 17.941 21.432 ;
     RECT  17.521 26.784 17.941 27.672 ;
     RECT  16.949 28.944 17.941 29.064 ;
     RECT  17.341 52.992 18.025 54.264 ;
     RECT  17.941 26.784 18.085 29.064 ;
     RECT  17.125 30.576 18.085 30.84 ;
     RECT  18.085 1.152 18.533 1.176 ;
     RECT  18.14 5.04 18.608 5.064 ;
     RECT  17.941 19.92 18.608 21.432 ;
     RECT  16.693 23.568 18.608 24.552 ;
     RECT  18.085 26.784 18.608 30.84 ;
     RECT  18.025 52.992 18.608 54.36 ;
     RECT  15.365 91.152 18.608 91.176 ;
     RECT  17.129 92.688 18.608 92.952 ;
     RECT  17.665 94.224 18.608 95.016 ;
     RECT  18.608 2.148 18.712 95.052 ;
     RECT  18.712 2.418 18.904 95.016 ;
     RECT  18.904 94.992 19.132 95.016 ;
     RECT  18.904 25.056 19.235 25.992 ;
     RECT  19.381 0.192 19.469 0.216 ;
     RECT  18.904 4.272 19.667 4.824 ;
     RECT  18.904 23.376 19.693 23.928 ;
     RECT  18.904 37.632 19.757 37.656 ;
     RECT  18.904 91.152 19.957 91.176 ;
     RECT  18.904 92.256 20.003 93.048 ;
     RECT  19.235 25.68 20.005 25.992 ;
     RECT  18.904 27.12 20.005 31.656 ;
     RECT  20.005 25.68 20.051 31.656 ;
     RECT  19.957 91.104 20.081 91.176 ;
     RECT  20.005 37.584 20.092 37.608 ;
     RECT  20.113 2.832 20.197 2.856 ;
     RECT  20.005 38.928 20.261 38.952 ;
     RECT  20.252 94.992 20.339 95.016 ;
     RECT  19.693 23.904 20.435 23.928 ;
     RECT  20.051 25.68 20.677 31.224 ;
     RECT  20.545 37.056 20.771 37.08 ;
     RECT  20.677 25.296 20.909 31.224 ;
     RECT  18.904 52.848 20.941 54.696 ;
     RECT  20.941 52.848 21.049 54.792 ;
     RECT  21.308 24.864 21.395 24.888 ;
     RECT  20.909 26.208 21.395 31.224 ;
     RECT  20.003 92.304 21.517 93.048 ;
     RECT  21.541 94.992 21.628 95.016 ;
     RECT  21.625 37.68 21.685 37.704 ;
     RECT  21.517 39.216 21.685 39.24 ;
     RECT  21.685 39.216 21.731 39.48 ;
     RECT  21.517 92.304 21.805 93.24 ;
     RECT  18.904 21.408 21.827 21.432 ;
     RECT  21.445 24.624 21.827 24.84 ;
     RECT  21.877 33.024 22.021 33.048 ;
     RECT  21.395 26.928 22.061 31.224 ;
     RECT  20.653 4.272 22.067 4.296 ;
     RECT  21.731 39.456 22.133 39.48 ;
     RECT  21.517 36.48 22.211 36.504 ;
     RECT  20.081 91.152 22.237 91.176 ;
     RECT  21.805 92.304 22.237 93.48 ;
     RECT  22.237 91.152 22.277 93.48 ;
     RECT  22.061 27.408 22.345 31.224 ;
     RECT  22.021 32.304 22.345 33.048 ;
     RECT  21.049 52.848 22.489 54.888 ;
     RECT  21.685 37.68 22.597 37.848 ;
     RECT  22.556 35.424 22.643 35.448 ;
     RECT  22.556 40.8 22.643 40.824 ;
     RECT  22.597 37.68 22.889 38.136 ;
     RECT  22.789 94.992 22.889 95.016 ;
     RECT  22.633 3.36 22.931 3.384 ;
     RECT  22.844 26.208 23.027 26.232 ;
     RECT  22.345 27.408 23.027 33.048 ;
     RECT  23.027 27.408 23.033 31.752 ;
     RECT  22.489 52.848 23.173 54.936 ;
     RECT  23.033 27.408 23.18 31.416 ;
     RECT  21.827 24.624 23.221 24.648 ;
     RECT  22.889 37.68 23.269 37.992 ;
     RECT  20.629 1.152 23.465 1.176 ;
     RECT  23.173 52.848 23.641 55.224 ;
     RECT  23.027 32.832 23.677 33.048 ;
     RECT  23.653 35.952 23.677 35.976 ;
     RECT  22.277 91.152 23.893 93.24 ;
     RECT  23.276 3.744 23.965 3.768 ;
     RECT  23.965 3.744 24.008 4.536 ;
     RECT  23.221 23.808 24.008 24.648 ;
     RECT  23.18 27.264 24.008 31.416 ;
     RECT  23.677 32.832 24.008 33.288 ;
     RECT  23.677 34.992 24.008 35.976 ;
     RECT  23.269 37.056 24.008 37.992 ;
     RECT  23.633 39.36 24.008 39.384 ;
     RECT  23.641 52.848 24.008 55.464 ;
     RECT  23.564 64.368 24.008 64.392 ;
     RECT  23.605 76.464 24.008 76.488 ;
     RECT  23.893 91.152 24.008 94.152 ;
     RECT  24.008 2.148 24.037 95.052 ;
     RECT  24.037 2.148 24.112 95.208 ;
     RECT  24.112 2.418 24.185 95.208 ;
     RECT  24.185 2.418 24.304 94.782 ;
     RECT  24.304 3.312 24.419 4.536 ;
     RECT  24.304 34.992 24.419 35.016 ;
     RECT  24.304 64.32 24.419 65.256 ;
     RECT  24.304 92.304 24.473 94.152 ;
     RECT  24.304 24.624 24.515 25.704 ;
     RECT  24.304 36.864 24.515 41.016 ;
     RECT  24.505 0.192 24.589 0.216 ;
     RECT  24.419 3.312 24.659 4.296 ;
     RECT  24.515 25.68 25.085 25.704 ;
     RECT  24.473 92.304 25.091 93.384 ;
     RECT  24.659 3.312 25.229 3.336 ;
     RECT  24.304 26.784 25.229 33.384 ;
     RECT  25.285 94.992 25.372 95.016 ;
     RECT  25.091 92.544 25.373 92.712 ;
     RECT  25.229 26.784 25.477 31.512 ;
     RECT  25.513 34.8 25.541 34.824 ;
     RECT  25.229 32.496 25.585 33.384 ;
     RECT  25.541 34.8 25.585 35.352 ;
     RECT  24.515 36.864 25.585 40.968 ;
     RECT  25.477 26.112 25.589 31.512 ;
     RECT  25.585 34.8 25.625 40.968 ;
     RECT  25.589 26.112 25.763 30.84 ;
     RECT  24.304 52.848 25.765 55.512 ;
     RECT  25.763 27.408 25.841 30.84 ;
     RECT  25.765 0.192 25.985 0.216 ;
     RECT  25.765 52.848 25.985 55.848 ;
     RECT  25.625 35.904 26.125 40.968 ;
     RECT  25.763 26.112 26.129 26.136 ;
     RECT  26.017 44.448 26.195 44.472 ;
     RECT  26.125 35.904 26.245 41.64 ;
     RECT  26.125 4.512 26.339 4.536 ;
     RECT  26.245 35.904 26.341 42.456 ;
     RECT  25.585 32.496 26.377 33.576 ;
     RECT  26.377 31.968 26.413 33.576 ;
     RECT  25.625 34.8 26.413 34.872 ;
     RECT  26.341 35.904 26.449 43.032 ;
     RECT  26.449 35.904 26.579 43.368 ;
     RECT  25.373 92.688 26.593 92.712 ;
     RECT  26.579 42.48 26.627 43.368 ;
     RECT  26.533 94.992 26.633 95.016 ;
     RECT  26.413 31.968 26.701 34.872 ;
     RECT  26.579 35.904 26.701 40.824 ;
     RECT  26.701 31.968 26.705 40.824 ;
     RECT  24.304 91.152 26.773 91.176 ;
     RECT  26.627 42.48 26.893 42.504 ;
     RECT  26.233 44.592 26.953 45.048 ;
     RECT  26.705 31.968 26.957 39.768 ;
     RECT  24.419 65.232 27.025 65.256 ;
     RECT  26.953 44.592 27.037 45.24 ;
     RECT  26.965 43.584 27.052 43.608 ;
     RECT  25.841 27.408 27.097 30.792 ;
     RECT  26.957 31.968 27.097 34.824 ;
     RECT  25.985 52.848 27.133 55.704 ;
     RECT  27.061 0.576 27.245 0.6 ;
     RECT  26.593 92.688 27.277 92.808 ;
     RECT  26.125 93.984 27.281 94.008 ;
     RECT  26.773 46.224 27.313 46.248 ;
     RECT  26.705 40.8 27.347 40.824 ;
     RECT  27.313 46.224 27.425 46.68 ;
     RECT  26.957 36.096 27.497 39.768 ;
     RECT  27.253 3.696 27.533 3.72 ;
     RECT  26.773 90.576 27.677 91.176 ;
     RECT  27.677 91.056 27.724 91.176 ;
     RECT  27.673 4.512 27.757 4.536 ;
     RECT  27.709 94.992 27.827 95.016 ;
     RECT  27.961 41.424 28.067 41.448 ;
     RECT  27.961 42.864 28.069 42.888 ;
     RECT  27.781 43.872 28.069 43.896 ;
     RECT  27.497 36.192 28.105 39.768 ;
     RECT  27.685 26.208 28.109 26.232 ;
     RECT  24.304 63.024 28.177 63.048 ;
     RECT  27.425 46.608 28.217 46.68 ;
     RECT  28.357 0.192 28.441 0.216 ;
     RECT  28.105 36.192 28.465 40.392 ;
     RECT  24.515 24.624 28.537 24.648 ;
     RECT  28.465 36.192 28.549 41.208 ;
     RECT  27.277 92.688 28.604 93 ;
     RECT  27.025 65.184 28.753 65.256 ;
     RECT  27.097 27.408 28.825 34.824 ;
     RECT  27.037 45.216 28.844 45.24 ;
     RECT  28.069 42.864 28.885 43.896 ;
     RECT  26.629 59.712 29.005 59.736 ;
     RECT  28.549 35.952 29.077 41.208 ;
     RECT  29.077 35.952 29.113 41.304 ;
     RECT  28.885 42.72 29.113 43.896 ;
     RECT  28.217 46.608 29.221 46.632 ;
     RECT  28.604 92.688 29.249 93.72 ;
     RECT  28.537 24.624 29.269 25.08 ;
     RECT  28.825 26.88 29.269 34.824 ;
     RECT  29.113 35.952 29.269 43.896 ;
     RECT  29.221 46.608 29.269 46.824 ;
     RECT  29.113 3.936 29.408 3.96 ;
     RECT  29.269 24.384 29.408 25.08 ;
     RECT  29.269 26.112 29.408 43.896 ;
     RECT  28.844 45.216 29.408 45.528 ;
     RECT  29.269 46.608 29.408 47.112 ;
     RECT  25.477 48.72 29.408 48.744 ;
     RECT  28.885 50.16 29.408 50.184 ;
     RECT  27.133 52.848 29.408 56.424 ;
     RECT  29.005 59.712 29.408 60.696 ;
     RECT  28.177 62.496 29.408 63.048 ;
     RECT  28.753 64.656 29.408 65.256 ;
     RECT  24.304 76.464 29.408 76.488 ;
     RECT  27.724 91.056 29.408 91.08 ;
     RECT  29.249 92.304 29.408 93.72 ;
     RECT  28.969 94.992 29.408 95.016 ;
     RECT  29.408 2.148 29.512 95.052 ;
     RECT  29.512 2.148 29.605 95.016 ;
     RECT  29.605 1.728 29.704 95.016 ;
     RECT  29.704 90.576 30.133 93.432 ;
     RECT  29.704 3.744 30.241 4.536 ;
     RECT  29.704 1.728 30.269 1.752 ;
     RECT  30.133 90.624 30.275 93.432 ;
     RECT  29.704 94.992 30.323 95.016 ;
     RECT  29.704 50.592 30.563 50.616 ;
     RECT  30.275 90.624 30.601 90.648 ;
     RECT  30.241 3.744 30.611 3.768 ;
     RECT  30.275 92.064 30.629 93.432 ;
     RECT  29.704 24.624 30.769 41.976 ;
     RECT  29.704 52.848 30.769 56.28 ;
     RECT  30.629 93.216 30.769 93.432 ;
     RECT  30.769 93.216 30.805 93.528 ;
     RECT  29.704 64.656 30.809 65.304 ;
     RECT  30.629 92.064 30.809 92.088 ;
     RECT  30.769 52.848 30.949 56.328 ;
     RECT  29.704 62.496 31.021 63.048 ;
     RECT  29.704 43.584 31.052 47.16 ;
     RECT  31.052 43.344 31.093 47.16 ;
     RECT  30.769 23.904 31.309 41.976 ;
     RECT  31.093 43.152 31.309 47.16 ;
     RECT  31.021 62.496 31.345 63.528 ;
     RECT  31.237 5.04 31.427 5.064 ;
     RECT  31.309 23.904 31.457 47.16 ;
     RECT  31.457 23.904 31.477 40.296 ;
     RECT  30.949 52.848 31.489 56.424 ;
     RECT  31.457 41.472 31.493 47.16 ;
     RECT  31.453 3.408 31.537 3.432 ;
     RECT  30.805 93.216 31.573 94.056 ;
     RECT  31.573 93.216 31.66 95.016 ;
     RECT  31.66 93.216 31.709 94.056 ;
     RECT  31.493 41.472 31.715 42.744 ;
     RECT  31.477 23.856 31.849 40.296 ;
     RECT  31.489 52.56 32.065 56.424 ;
     RECT  31.849 23.232 32.245 40.296 ;
     RECT  31.709 93.216 32.285 93.24 ;
     RECT  30.901 0.192 32.357 0.216 ;
     RECT  32.245 23.136 32.435 40.296 ;
     RECT  32.053 22.08 32.485 22.104 ;
     RECT  29.704 59.712 32.485 60.696 ;
     RECT  32.435 35.52 32.497 40.296 ;
     RECT  31.715 41.472 32.497 42.312 ;
     RECT  31.237 92.016 32.501 92.04 ;
     RECT  32.485 21.936 32.713 22.104 ;
     RECT  32.435 23.136 32.713 34.488 ;
     RECT  32.485 58.752 32.773 60.696 ;
     RECT  32.725 51.168 32.821 51.192 ;
     RECT  32.065 52.56 32.821 56.712 ;
     RECT  32.713 21.36 32.867 34.488 ;
     RECT  32.78 94.992 32.867 95.016 ;
     RECT  32.821 51.168 32.929 56.712 ;
     RECT  32.821 3.936 32.933 3.96 ;
     RECT  32.785 70.128 32.965 70.728 ;
     RECT  32.867 21.936 33.041 34.488 ;
     RECT  32.773 58.704 33.061 60.696 ;
     RECT  33.041 21.936 33.113 32.664 ;
     RECT  32.497 35.52 33.181 42.312 ;
     RECT  31.493 43.872 33.221 47.16 ;
     RECT  33.061 57.84 33.289 60.696 ;
     RECT  31.345 61.872 33.289 63.528 ;
     RECT  33.113 22.032 33.293 32.664 ;
     RECT  32.929 51.168 33.325 56.808 ;
     RECT  33.325 50.88 33.361 56.808 ;
     RECT  33.041 33.744 33.395 34.488 ;
     RECT  32.149 18.192 33.397 18.216 ;
     RECT  33.361 50.64 33.397 56.808 ;
     RECT  33.181 35.52 33.433 42.744 ;
     RECT  33.221 43.872 33.433 46.824 ;
     RECT  33.349 20.736 33.437 20.856 ;
     RECT  32.965 70.128 33.445 71.448 ;
     RECT  33.433 35.52 33.517 46.824 ;
     RECT  33.397 50.112 33.577 56.808 ;
     RECT  32.857 69.024 33.589 69.048 ;
     RECT  33.445 70.032 33.589 71.448 ;
     RECT  33.577 50.112 33.613 56.856 ;
     RECT  33.289 57.84 33.613 63.528 ;
     RECT  33.613 4.512 33.697 4.536 ;
     RECT  29.704 48.72 33.721 48.744 ;
     RECT  33.721 47.904 33.829 48.744 ;
     RECT  33.613 50.112 33.829 63.528 ;
     RECT  33.517 44.016 33.833 46.824 ;
     RECT  33.395 34.032 33.836 34.488 ;
     RECT  33.517 35.52 33.836 42.984 ;
     RECT  32.725 67.824 34.021 67.848 ;
     RECT  33.589 69.024 34.021 71.448 ;
     RECT  33.445 10.128 34.069 10.152 ;
     RECT  33.397 18.192 34.22 18.792 ;
     RECT  33.589 19.776 34.22 19.8 ;
     RECT  33.833 44.064 34.369 46.824 ;
     RECT  33.829 47.904 34.369 63.528 ;
     RECT  34.021 67.824 34.477 71.448 ;
     RECT  34.369 91.344 34.477 91.368 ;
     RECT  34.22 18.192 34.513 19.8 ;
     RECT  33.437 20.832 34.513 20.856 ;
     RECT  33.493 1.728 34.517 1.752 ;
     RECT  32.533 12.768 34.549 12.792 ;
     RECT  32.581 13.92 34.549 13.944 ;
     RECT  33.836 34.032 34.621 42.984 ;
     RECT  34.477 67.296 34.693 71.448 ;
     RECT  33.505 93.408 34.693 93.432 ;
     RECT  33.293 22.032 34.765 32.52 ;
     RECT  34.621 33.6 34.765 42.984 ;
     RECT  34.513 18.192 34.801 20.856 ;
     RECT  34.765 22.032 34.801 42.984 ;
     RECT  34.477 4.656 34.808 4.68 ;
     RECT  34.069 9.36 34.808 10.152 ;
     RECT  34.549 12.768 34.808 13.944 ;
     RECT  34.801 18.192 34.808 42.984 ;
     RECT  34.369 44.064 34.808 63.528 ;
     RECT  30.809 64.656 34.808 65.256 ;
     RECT  34.693 67.056 34.808 71.448 ;
     RECT  29.704 76.464 34.808 76.488 ;
     RECT  34.309 83.328 34.808 83.352 ;
     RECT  34.477 91.344 34.808 91.608 ;
     RECT  34.693 92.688 34.808 93.432 ;
     RECT  34.069 94.992 34.808 95.016 ;
     RECT  34.721 1.152 34.825 1.176 ;
     RECT  34.808 2.148 34.912 95.052 ;
     RECT  34.912 2.418 35.104 95.016 ;
     RECT  35.104 9.36 35.201 10.152 ;
     RECT  35.104 83.328 35.201 83.496 ;
     RECT  35.104 4.656 35.315 4.68 ;
     RECT  35.104 16.896 35.353 42.408 ;
     RECT  35.353 16.896 35.363 42.168 ;
     RECT  35.104 94.992 35.417 95.016 ;
     RECT  35.363 16.896 35.489 42.072 ;
     RECT  35.489 16.896 35.651 41.16 ;
     RECT  35.104 91.056 35.939 92.712 ;
     RECT  35.104 76.464 36.133 76.488 ;
     RECT  36.037 0.192 36.137 0.216 ;
     RECT  35.939 92.304 36.169 92.712 ;
     RECT  35.104 93.744 36.169 93.768 ;
     RECT  36.14 4.272 36.227 4.296 ;
     RECT  35.651 16.896 36.227 40.728 ;
     RECT  35.104 44.064 36.457 65.496 ;
     RECT  36.227 18.432 36.467 40.728 ;
     RECT  36.169 92.304 36.677 93.768 ;
     RECT  36.565 94.992 36.677 95.016 ;
     RECT  36.133 76.368 36.709 76.488 ;
     RECT  35.201 83.472 36.901 83.496 ;
     RECT  36.467 33.6 36.949 40.728 ;
     RECT  35.939 91.056 36.949 91.08 ;
     RECT  36.949 91.056 36.997 91.224 ;
     RECT  36.677 92.304 36.997 93.48 ;
     RECT  36.457 44.064 37.237 65.544 ;
     RECT  36.949 33.6 37.249 41.64 ;
     RECT  37.237 43.104 37.249 65.544 ;
     RECT  36.997 91.056 37.333 93.48 ;
     RECT  36.467 18.432 37.433 32.568 ;
     RECT  37.433 18.816 37.573 32.568 ;
     RECT  37.249 33.6 37.573 65.544 ;
     RECT  37.333 90.624 37.865 93.48 ;
     RECT  37.813 94.992 37.9 95.016 ;
     RECT  37.573 18.816 37.909 65.544 ;
     RECT  35.104 12.768 37.933 14.52 ;
     RECT  37.909 18.816 37.945 65.88 ;
     RECT  37.861 88.08 37.957 88.104 ;
     RECT  35.104 89.424 37.957 89.448 ;
     RECT  37.957 88.08 38.053 89.448 ;
     RECT  35.104 86.736 38.245 86.76 ;
     RECT  38.053 87.936 38.245 89.448 ;
     RECT  37.945 18.912 38.485 65.88 ;
     RECT  37.465 4.512 38.617 4.536 ;
     RECT  38.617 3.936 38.627 4.536 ;
     RECT  38.485 18.912 38.723 65.976 ;
     RECT  35.104 67.056 38.773 71.352 ;
     RECT  38.723 19.296 38.952 65.976 ;
     RECT  38.773 67.008 38.952 71.352 ;
     RECT  37.865 90.624 39.013 92.808 ;
     RECT  38.005 94.032 39.013 94.152 ;
     RECT  37.333 1.152 39.017 1.176 ;
     RECT  39.013 90.624 39.061 94.152 ;
     RECT  36.709 76.368 39.089 77.352 ;
     RECT  39.061 90.624 39.161 95.016 ;
     RECT  36.227 16.896 39.349 17.4 ;
     RECT  39.877 0.192 40.205 0.216 ;
     RECT  38.627 3.936 40.208 4.296 ;
     RECT  35.104 6 40.208 6.6 ;
     RECT  35.201 9.36 40.208 10.056 ;
     RECT  37.933 12.768 40.208 14.856 ;
     RECT  39.349 16.896 40.208 18.168 ;
     RECT  38.952 19.296 40.208 71.352 ;
     RECT  39.089 76.464 40.208 77.352 ;
     RECT  36.901 83.472 40.208 84.312 ;
     RECT  38.245 86.736 40.208 89.448 ;
     RECT  39.161 90.624 40.208 94.152 ;
     RECT  40.208 2.148 40.309 95.052 ;
     RECT  40.309 2.148 40.312 95.208 ;
     RECT  40.312 2.418 40.396 95.208 ;
     RECT  40.396 2.418 40.504 94.782 ;
     RECT  40.504 19.44 41.219 71.352 ;
     RECT  41.173 0.192 41.393 0.216 ;
     RECT  40.504 87.408 41.411 89.928 ;
     RECT  40.504 91.2 41.465 93.768 ;
     RECT  40.504 3.936 41.507 4.296 ;
     RECT  41.465 91.2 41.573 92.712 ;
     RECT  41.516 94.992 41.603 95.016 ;
     RECT  41.507 4.272 41.681 4.296 ;
     RECT  41.411 87.408 41.681 89.448 ;
     RECT  40.504 12.768 41.969 15.384 ;
     RECT  41.219 19.632 42.181 71.352 ;
     RECT  42.181 19.488 42.325 71.352 ;
     RECT  42.469 0.192 42.581 0.216 ;
     RECT  40.504 16.896 42.685 17.88 ;
     RECT  42.325 19.056 42.685 71.352 ;
     RECT  41.465 93.744 42.685 93.768 ;
     RECT  41.681 87.408 42.757 88.776 ;
     RECT  41.573 91.2 42.797 92.472 ;
     RECT  42.793 94.992 42.899 95.016 ;
     RECT  42.757 87.408 42.905 89.496 ;
     RECT  42.685 16.848 42.949 71.352 ;
     RECT  43.004 4.512 43.091 4.536 ;
     RECT  43.045 3.36 43.193 3.384 ;
     RECT  42.949 16.512 43.337 71.352 ;
     RECT  43.337 16.512 43.477 18.696 ;
     RECT  42.797 91.344 43.625 92.472 ;
     RECT  43.477 15.984 43.715 18.696 ;
     RECT  43.625 91.344 43.733 92.328 ;
     RECT  42.685 93.744 43.733 94.008 ;
     RECT  43.685 0.192 43.769 0.216 ;
     RECT  42.905 87.552 43.805 89.496 ;
     RECT  41.969 12.768 44.089 14.76 ;
     RECT  43.715 15.984 44.089 18.264 ;
     RECT  44.101 94.992 44.188 95.016 ;
     RECT  44.089 12.768 44.524 18.264 ;
     RECT  43.573 79.248 44.633 79.272 ;
     RECT  43.733 93.744 44.809 93.768 ;
     RECT  43.733 91.344 45.013 91.992 ;
     RECT  44.809 93.696 45.013 93.768 ;
     RECT  43.337 19.872 45.205 71.352 ;
     RECT  45.205 19.872 45.452 71.4 ;
     RECT  45.452 19.872 45.493 71.832 ;
     RECT  45.385 90 45.493 90.024 ;
     RECT  45.013 91.344 45.493 93.768 ;
     RECT  45.013 0.576 45.533 0.6 ;
     RECT  44.629 3.696 45.608 3.72 ;
     RECT  40.504 6 45.608 6.6 ;
     RECT  40.504 9.36 45.608 10.056 ;
     RECT  44.524 12.768 45.608 15.384 ;
     RECT  44.524 16.896 45.608 18.264 ;
     RECT  45.493 19.344 45.608 71.832 ;
     RECT  40.504 77.328 45.608 77.352 ;
     RECT  40.504 83.472 45.608 84.312 ;
     RECT  43.805 87.552 45.608 88.776 ;
     RECT  45.493 90 45.608 93.768 ;
     RECT  45.308 94.992 45.608 95.016 ;
     RECT  45.608 2.148 45.712 95.052 ;
     RECT  45.712 2.418 45.904 95.016 ;
     RECT  45.904 87.552 46.019 92.184 ;
     RECT  45.904 3.168 46.403 3.192 ;
     RECT  45.904 4.272 46.403 4.296 ;
     RECT  45.904 16.512 46.403 71.4 ;
     RECT  46.403 16.896 46.433 71.4 ;
     RECT  45.904 94.992 46.684 95.016 ;
     RECT  46.019 87.552 46.757 89.832 ;
     RECT  46.757 89.808 46.865 89.832 ;
     RECT  45.904 83.472 46.981 84.312 ;
     RECT  46.019 90.816 47.077 92.184 ;
     RECT  45.904 93.216 47.077 93.768 ;
     RECT  47.077 90.816 47.372 93.768 ;
     RECT  45.904 12.768 47.437 14.52 ;
     RECT  47.372 90.816 47.459 94.008 ;
     RECT  47.459 90.816 47.549 93.768 ;
     RECT  47.437 12.528 47.557 14.52 ;
     RECT  46.433 16.896 47.557 18.744 ;
     RECT  46.433 19.872 47.557 71.4 ;
     RECT  47.113 4.704 47.603 4.728 ;
     RECT  47.557 16.896 47.603 71.4 ;
     RECT  47.549 90.816 47.657 91.896 ;
     RECT  47.557 11.904 47.765 14.52 ;
     RECT  46.309 0.192 47.801 0.216 ;
     RECT  47.603 19.104 47.837 71.4 ;
     RECT  47.845 95.184 47.945 95.208 ;
     RECT  46.981 83.472 47.981 84.408 ;
     RECT  46.757 87.552 48.133 88.776 ;
     RECT  47.113 3.408 48.593 3.432 ;
     RECT  47.657 91.872 48.733 91.896 ;
     RECT  47.765 12.528 49.043 14.52 ;
     RECT  47.837 19.872 49.045 71.4 ;
     RECT  48.853 1.152 49.097 1.176 ;
     RECT  49.045 19.776 49.132 71.4 ;
     RECT  49.052 94.992 49.139 95.016 ;
     RECT  48.984 4.512 49.457 4.536 ;
     RECT  48.733 91.872 49.561 92.232 ;
     RECT  47.549 93.504 49.561 93.768 ;
     RECT  47.657 90.816 49.813 90.84 ;
     RECT  49.561 91.872 49.813 93.768 ;
     RECT  49.813 90.816 49.859 93.768 ;
     RECT  49.859 90.816 49.9 92.232 ;
     RECT  50.149 1.152 50.789 1.176 ;
     RECT  49.132 19.872 50.857 71.4 ;
     RECT  48.133 86.64 50.869 88.776 ;
     RECT  45.904 6 51.008 6.6 ;
     RECT  45.904 9.36 51.008 10.056 ;
     RECT  49.043 12.768 51.008 14.52 ;
     RECT  47.603 16.896 51.008 17.88 ;
     RECT  50.857 19.632 51.008 71.4 ;
     RECT  45.904 77.328 51.008 77.352 ;
     RECT  47.981 83.472 51.008 84.312 ;
     RECT  50.869 86.64 51.008 89.544 ;
     RECT  49.9 90.816 51.008 90.84 ;
     RECT  49.9 91.872 51.008 92.232 ;
     RECT  49.859 93.504 51.008 93.768 ;
     RECT  50.341 94.992 51.008 95.016 ;
     RECT  51.008 2.148 51.112 95.052 ;
     RECT  51.112 2.418 51.304 95.016 ;
     RECT  51.445 0.192 51.653 0.216 ;
     RECT  51.304 94.992 51.689 95.016 ;
     RECT  51.304 87.552 51.797 93.768 ;
     RECT  51.797 89.856 51.923 93.768 ;
     RECT  51.923 90.816 52.553 93.768 ;
     RECT  51.304 4.272 52.837 4.296 ;
     RECT  51.304 16.896 52.883 17.736 ;
     RECT  52.765 94.992 52.883 95.016 ;
     RECT  51.304 19.632 52.931 71.4 ;
     RECT  51.304 9.36 52.933 9.384 ;
     RECT  51.797 87.552 53.057 88.776 ;
     RECT  53.057 87.888 53.237 88.776 ;
     RECT  52.837 4.272 53.413 4.536 ;
     RECT  51.304 77.328 53.413 77.832 ;
     RECT  51.304 12.768 53.453 15.432 ;
     RECT  52.931 19.728 53.459 71.4 ;
     RECT  53.413 77.328 53.497 78.072 ;
     RECT  52.553 90.816 53.737 92.232 ;
     RECT  53.413 3.36 53.795 4.536 ;
     RECT  53.453 12.768 53.795 14.904 ;
     RECT  53.459 19.728 53.836 70.92 ;
     RECT  53.795 3.696 53.849 4.344 ;
     RECT  53.737 90.528 54.037 92.232 ;
     RECT  52.553 93.744 54.037 93.768 ;
     RECT  54.037 90.528 54.083 93.768 ;
     RECT  53.795 12.768 54.131 14.616 ;
     RECT  54.025 94.992 54.131 95.016 ;
     RECT  52.693 1.152 54.353 1.176 ;
     RECT  54.085 11.28 54.373 11.304 ;
     RECT  53.497 77.328 54.709 77.832 ;
     RECT  51.304 83.472 54.749 84.312 ;
     RECT  54.083 90.528 54.857 93.24 ;
     RECT  53.237 88.224 55.001 88.776 ;
     RECT  53.849 4.32 55.069 4.344 ;
     RECT  55.069 4.32 55.109 4.536 ;
     RECT  54.373 11.088 55.253 11.304 ;
     RECT  54.857 90.576 55.283 93.24 ;
     RECT  55.283 90.816 55.397 93.24 ;
     RECT  55.321 94.992 55.427 95.016 ;
     RECT  55.001 88.752 56.077 88.776 ;
     RECT  55.109 4.512 56.408 4.536 ;
     RECT  51.304 6 56.408 6.6 ;
     RECT  52.933 9.36 56.408 10.056 ;
     RECT  55.253 11.088 56.408 11.112 ;
     RECT  54.131 12.768 56.408 14.52 ;
     RECT  52.883 16.896 56.408 16.92 ;
     RECT  53.836 20.64 56.408 70.92 ;
     RECT  54.709 77.328 56.408 77.928 ;
     RECT  54.749 83.568 56.408 84.312 ;
     RECT  56.108 85.488 56.408 85.512 ;
     RECT  56.077 88.752 56.408 88.92 ;
     RECT  55.397 90.816 56.408 92.952 ;
     RECT  56.408 2.148 56.512 95.052 ;
     RECT  56.512 2.418 56.629 95.052 ;
     RECT  56.629 2.418 56.704 95.16 ;
     RECT  56.704 95.136 56.716 95.16 ;
     RECT  55.285 0.192 56.765 0.216 ;
     RECT  56.704 77.328 56.819 77.928 ;
     RECT  56.704 83.568 56.819 85.368 ;
     RECT  56.819 85.344 56.915 85.368 ;
     RECT  56.704 90.576 56.915 92.952 ;
     RECT  56.704 88.752 56.963 88.92 ;
     RECT  56.915 90.72 57.485 92.952 ;
     RECT  56.819 83.568 57.737 84.36 ;
     RECT  57.737 83.568 57.881 83.784 ;
     RECT  57.836 94.992 57.923 95.016 ;
     RECT  56.704 4.128 58.021 4.152 ;
     RECT  57.829 0.192 58.025 0.216 ;
     RECT  58.021 3.168 58.108 4.152 ;
     RECT  57.485 91.296 58.165 92.952 ;
     RECT  57.881 83.76 58.249 83.784 ;
     RECT  58.108 3.984 58.381 4.152 ;
     RECT  56.963 88.752 58.565 88.776 ;
     RECT  58.381 3.984 58.781 4.44 ;
     RECT  59.125 94.992 59.212 95.016 ;
     RECT  58.165 91.296 59.221 93.912 ;
     RECT  59.221 91.2 59.413 93.912 ;
     RECT  59.125 1.152 59.429 1.176 ;
     RECT  59.372 85.824 59.459 85.848 ;
     RECT  59.413 91.008 59.681 93.912 ;
     RECT  59.681 91.2 59.699 93.912 ;
     RECT  59.699 93.504 59.897 93.912 ;
     RECT  60.14 83.136 60.227 83.16 ;
     RECT  60.181 88.608 60.433 88.632 ;
     RECT  60.433 88.608 60.473 88.92 ;
     RECT  60.373 95.184 60.473 95.208 ;
     RECT  60.421 0.192 60.509 0.216 ;
     RECT  59.699 91.2 60.761 92.472 ;
     RECT  60.217 3.12 61.477 3.144 ;
     RECT  58.781 4.416 61.477 4.44 ;
     RECT  56.704 6 61.669 6.6 ;
     RECT  61.657 0.192 61.741 0.216 ;
     RECT  61.477 3.12 61.808 4.44 ;
     RECT  61.669 6 61.808 6.648 ;
     RECT  56.704 9.36 61.808 10.056 ;
     RECT  56.704 12.768 61.808 14.52 ;
     RECT  56.704 16.896 61.808 16.92 ;
     RECT  56.704 20.64 61.808 70.92 ;
     RECT  56.819 77.328 61.808 77.352 ;
     RECT  60.473 88.896 61.808 88.92 ;
     RECT  60.761 91.296 61.808 92.472 ;
     RECT  59.897 93.744 61.808 93.912 ;
     RECT  61.58 94.992 61.808 95.016 ;
     RECT  61.808 2.148 61.912 95.052 ;
     RECT  61.912 2.418 62.104 95.016 ;
     RECT  62.104 88.896 62.291 88.92 ;
     RECT  62.104 89.952 62.332 89.976 ;
     RECT  62.104 91.536 62.741 92.472 ;
     RECT  62.104 93.744 62.741 93.912 ;
     RECT  62.104 3.12 63.205 3.144 ;
     RECT  62.741 91.584 63.205 92.472 ;
     RECT  62.741 93.744 63.205 93.816 ;
     RECT  63.205 3.12 63.245 3.432 ;
     RECT  63.245 3.408 63.457 3.432 ;
     RECT  62.104 4.416 63.457 4.968 ;
     RECT  63.457 3.408 63.497 4.968 ;
     RECT  62.104 94.992 64.163 95.016 ;
     RECT  63.205 91.584 64.253 93.816 ;
     RECT  62.965 1.152 64.433 1.176 ;
     RECT  63.497 4.224 64.541 4.968 ;
     RECT  64.253 93.408 64.979 93.816 ;
     RECT  65.293 94.992 65.411 95.016 ;
     RECT  64.979 93.504 65.513 93.816 ;
     RECT  63.493 90.048 65.729 90.072 ;
     RECT  65.005 3.312 66.373 3.336 ;
     RECT  64.541 4.368 66.373 4.968 ;
     RECT  65.557 1.152 66.557 1.176 ;
     RECT  62.104 6 66.697 6.6 ;
     RECT  66.469 89.136 66.697 89.16 ;
     RECT  66.633 95.184 66.745 95.208 ;
     RECT  65.513 93.792 66.949 93.816 ;
     RECT  66.805 0.192 67.205 0.216 ;
     RECT  66.373 3.312 67.208 4.968 ;
     RECT  66.697 6 67.208 6.648 ;
     RECT  62.104 9.36 67.208 9.384 ;
     RECT  62.104 12.768 67.208 14.52 ;
     RECT  62.104 16.896 67.208 16.92 ;
     RECT  62.104 20.64 67.208 70.92 ;
     RECT  62.104 77.328 67.208 77.352 ;
     RECT  66.445 86.592 67.208 86.616 ;
     RECT  66.697 89.136 67.208 89.496 ;
     RECT  64.253 91.584 67.208 92.184 ;
     RECT  66.949 93.312 67.208 93.816 ;
     RECT  67.208 2.148 67.312 95.052 ;
     RECT  67.312 2.418 67.504 95.016 ;
     RECT  67.504 4.224 67.781 4.968 ;
     RECT  67.504 89.472 67.811 89.496 ;
     RECT  67.504 90.768 67.925 92.136 ;
     RECT  67.504 94.992 67.955 95.016 ;
     RECT  67.504 93.312 68.677 93.912 ;
     RECT  67.781 4.224 68.821 4.392 ;
     RECT  68.821 4.224 68.908 4.68 ;
     RECT  68.908 4.224 69.113 4.392 ;
     RECT  69.157 94.992 69.244 95.016 ;
     RECT  67.925 91.584 69.505 92.136 ;
     RECT  68.677 93.168 69.505 93.912 ;
     RECT  69.505 91.584 69.82 93.912 ;
     RECT  69.469 88.896 70.357 88.92 ;
     RECT  70.364 94.992 70.451 95.016 ;
     RECT  69.82 91.584 70.697 92.376 ;
     RECT  70.697 92.112 70.733 92.376 ;
     RECT  70.357 88.896 70.837 89.88 ;
     RECT  67.504 6 70.901 6.648 ;
     RECT  67.504 9.36 70.933 9.384 ;
     RECT  69.113 4.368 70.979 4.392 ;
     RECT  70.901 6 70.985 6.84 ;
     RECT  70.733 92.208 70.985 92.376 ;
     RECT  70.945 87.744 71.171 87.768 ;
     RECT  70.837 88.896 71.212 90.024 ;
     RECT  68.101 1.152 71.237 1.176 ;
     RECT  69.82 93.888 71.413 93.912 ;
     RECT  71.212 90 71.453 90.024 ;
     RECT  71.845 90.624 72.092 90.648 ;
     RECT  70.985 92.208 72.092 92.232 ;
     RECT  71.941 0.192 72.209 0.216 ;
     RECT  72.241 4.128 72.313 4.152 ;
     RECT  72.313 4.128 72.608 4.44 ;
     RECT  70.985 6 72.608 6.6 ;
     RECT  70.933 8.976 72.608 9.384 ;
     RECT  67.504 12.768 72.608 14.52 ;
     RECT  67.504 16.896 72.608 16.92 ;
     RECT  67.504 20.64 72.608 70.92 ;
     RECT  67.504 77.328 72.608 77.352 ;
     RECT  71.212 88.896 72.608 88.92 ;
     RECT  72.092 90.624 72.608 92.232 ;
     RECT  71.413 93.312 72.608 93.912 ;
     RECT  71.653 94.992 72.608 95.016 ;
     RECT  72.608 2.148 72.712 95.052 ;
     RECT  72.712 2.418 72.901 95.052 ;
     RECT  72.901 2.418 72.904 95.208 ;
     RECT  72.904 88.896 72.965 88.92 ;
     RECT  72.904 95.184 73.001 95.208 ;
     RECT  72.904 93.312 73.037 93.912 ;
     RECT  72.904 90.912 74.005 90.984 ;
     RECT  72.904 92.208 74.005 92.232 ;
     RECT  74.069 89.472 74.153 89.496 ;
     RECT  74.108 94.992 74.195 95.016 ;
     RECT  74.005 90.912 74.245 92.232 ;
     RECT  72.904 12.768 74.297 14.52 ;
     RECT  73.037 93.456 74.325 93.912 ;
     RECT  74.245 90.912 74.333 92.328 ;
     RECT  74.325 93.792 74.693 93.912 ;
     RECT  72.904 4.128 74.729 4.728 ;
     RECT  74.333 90.912 74.837 92.232 ;
     RECT  74.297 12.768 74.909 13.368 ;
     RECT  75.337 94.992 75.443 95.016 ;
     RECT  74.837 91.872 75.697 92.232 ;
     RECT  73.237 1.152 75.953 1.176 ;
     RECT  75.697 91.872 76.021 92.664 ;
     RECT  74.693 93.792 76.021 93.816 ;
     RECT  74.729 4.704 76.345 4.728 ;
     RECT  76.021 89.568 76.489 89.592 ;
     RECT  76.489 89.472 76.529 89.592 ;
     RECT  76.597 94.992 76.691 95.016 ;
     RECT  76.345 4.272 76.777 4.728 ;
     RECT  76.021 91.872 76.844 93.816 ;
     RECT  76.529 89.472 76.931 89.496 ;
     RECT  76.844 91.536 76.931 93.816 ;
     RECT  76.777 3.408 77.425 4.728 ;
     RECT  72.904 6 77.425 6.6 ;
     RECT  77.461 10.896 77.677 10.92 ;
     RECT  76.931 91.872 77.893 93.816 ;
     RECT  77.9 95.184 77.987 95.208 ;
     RECT  77.425 3.408 78.008 6.6 ;
     RECT  72.904 8.976 78.008 9.384 ;
     RECT  77.677 10.704 78.008 10.92 ;
     RECT  74.909 13.344 78.008 13.368 ;
     RECT  74.297 14.496 78.008 14.52 ;
     RECT  72.904 16.896 78.008 16.92 ;
     RECT  72.904 20.64 78.008 70.92 ;
     RECT  72.904 77.328 78.008 77.352 ;
     RECT  77.893 88.176 78.008 88.2 ;
     RECT  77.893 90.96 78.008 93.816 ;
     RECT  78.008 2.148 78.112 95.052 ;
     RECT  78.112 2.418 78.304 94.782 ;
     RECT  78.304 3.936 78.419 6.6 ;
     RECT  78.304 9.36 78.611 11.4 ;
     RECT  78.304 20.016 78.611 70.92 ;
     RECT  78.304 14.496 78.941 14.52 ;
     RECT  78.304 88.176 78.977 88.2 ;
     RECT  78.304 91.44 79.049 92.472 ;
     RECT  78.419 6 79.265 6.6 ;
     RECT  79.189 95.184 79.276 95.208 ;
     RECT  78.611 10.704 79.283 11.4 ;
     RECT  79.049 91.44 79.283 91.464 ;
     RECT  79.049 92.448 79.283 92.472 ;
     RECT  78.304 13.008 79.589 13.032 ;
     RECT  78.419 3.936 79.955 4.296 ;
     RECT  79.868 12.912 79.955 12.936 ;
     RECT  78.304 93.504 80.017 93.912 ;
     RECT  79.955 3.936 80.053 3.96 ;
     RECT  80.053 3.408 80.093 3.96 ;
     RECT  77.077 1.152 80.201 1.176 ;
     RECT  78.304 16.896 80.201 16.92 ;
     RECT  80.396 94.992 80.483 95.016 ;
     RECT  80.093 3.408 80.669 3.432 ;
     RECT  79.265 6 80.849 6.024 ;
     RECT  80.809 91.728 81.385 91.752 ;
     RECT  80.017 93.168 81.385 93.912 ;
     RECT  81.385 91.728 81.677 93.912 ;
     RECT  78.611 9.36 81.713 9.384 ;
     RECT  81.685 94.992 81.772 95.016 ;
     RECT  78.611 20.544 82.069 70.92 ;
     RECT  81.677 91.728 82.289 92.472 ;
     RECT  80.917 0.192 82.469 0.216 ;
     RECT  82.105 15.504 82.885 15.528 ;
     RECT  81.853 4.512 82.94 4.536 ;
     RECT  82.94 4.512 83.408 4.824 ;
     RECT  83.293 13.824 83.408 13.848 ;
     RECT  82.885 15.36 83.408 15.528 ;
     RECT  82.069 20.304 83.408 70.92 ;
     RECT  78.304 77.328 83.408 77.352 ;
     RECT  82.289 92.4 83.408 92.472 ;
     RECT  81.677 93.888 83.408 93.912 ;
     RECT  82.892 94.992 83.408 95.016 ;
     RECT  83.408 2.148 83.512 95.052 ;
     RECT  83.509 0.192 83.657 0.216 ;
     RECT  83.512 2.418 83.704 95.016 ;
     RECT  83.704 94.992 84.268 95.016 ;
     RECT  83.704 13.056 84.419 14.04 ;
     RECT  83.704 15.504 84.419 15.528 ;
     RECT  84.419 13.056 84.757 13.848 ;
     RECT  83.704 20.496 84.757 70.92 ;
     RECT  84.757 12.912 84.844 13.848 ;
     RECT  84.757 20.016 84.881 70.92 ;
     RECT  83.704 92.4 84.913 92.904 ;
     RECT  83.704 93.888 84.913 93.912 ;
     RECT  84.757 1.152 84.953 1.176 ;
     RECT  83.704 4.512 85.205 4.536 ;
     RECT  85.429 94.992 85.516 95.016 ;
     RECT  84.913 92.4 85.885 93.912 ;
     RECT  84.881 20.832 85.909 70.92 ;
     RECT  85.885 92.352 85.969 93.912 ;
     RECT  82.357 96.96 86.105 96.984 ;
     RECT  86.3 4.656 86.341 4.68 ;
     RECT  86.341 4.512 86.387 4.68 ;
     RECT  86.309 3.408 86.393 3.432 ;
     RECT  86.053 0.192 86.465 0.216 ;
     RECT  85.909 20.832 86.629 71.112 ;
     RECT  84.844 13.824 86.677 13.848 ;
     RECT  85.969 92.4 86.717 93.912 ;
     RECT  86.461 96.336 86.723 96.36 ;
     RECT  86.677 13.824 86.749 14.136 ;
     RECT  86.749 13.632 87.397 14.136 ;
     RECT  87.317 0.576 87.401 0.6 ;
     RECT  86.387 4.512 87.443 4.536 ;
     RECT  86.629 20.016 87.587 71.112 ;
     RECT  87.397 12.96 87.833 14.136 ;
     RECT  88.693 3.936 88.808 3.96 ;
     RECT  87.833 13.632 88.808 14.136 ;
     RECT  87.587 20.592 88.808 71.112 ;
     RECT  83.704 77.328 88.808 77.352 ;
     RECT  86.717 92.4 88.808 93.816 ;
     RECT  87.865 94.992 88.808 95.016 ;
     RECT  88.808 2.148 88.912 95.052 ;
     RECT  88.912 2.418 89.104 95.016 ;
     RECT  89.104 3.936 89.219 3.96 ;
     RECT  89.104 94.992 89.219 95.016 ;
     RECT  89.104 13.632 89.245 15.24 ;
     RECT  89.104 20.304 89.273 71.112 ;
     RECT  89.245 13.632 90.173 14.136 ;
     RECT  88.645 1.152 90.317 1.176 ;
     RECT  90.349 94.992 90.515 95.016 ;
     RECT  89.273 20.592 90.86 71.112 ;
     RECT  89.104 92.4 91.093 93.912 ;
     RECT  91.093 92.304 91.361 93.912 ;
     RECT  89.245 15.216 91.537 15.24 ;
     RECT  91.189 0.192 91.613 0.216 ;
     RECT  90.173 14.112 91.753 14.136 ;
     RECT  91.537 15.216 91.753 15.288 ;
     RECT  90.961 4.224 91.765 4.248 ;
     RECT  91.717 95.184 91.804 95.208 ;
     RECT  91.765 3.936 91.811 4.248 ;
     RECT  91.753 14.112 91.837 15.288 ;
     RECT  91.837 15.264 91.861 15.288 ;
     RECT  91.837 14.112 91.907 14.136 ;
     RECT  91.811 3.936 92.117 3.96 ;
     RECT  92.485 1.152 92.945 1.176 ;
     RECT  92.924 94.992 93.011 95.016 ;
     RECT  91.861 15.264 93.121 16.008 ;
     RECT  92.797 3.408 93.161 3.432 ;
     RECT  90.86 20.16 93.541 71.112 ;
     RECT  93.121 14.784 93.913 16.008 ;
     RECT  93.913 14.784 94.069 16.056 ;
     RECT  93.733 1.728 94.208 1.752 ;
     RECT  92.797 4.512 94.208 4.536 ;
     RECT  94.069 14.784 94.208 16.296 ;
     RECT  94.069 17.616 94.208 17.64 ;
     RECT  93.599 18.624 94.208 18.648 ;
     RECT  93.541 20.112 94.208 71.112 ;
     RECT  89.104 77.328 94.208 77.352 ;
     RECT  91.361 92.4 94.208 93.912 ;
     RECT  94.165 95.184 94.208 95.208 ;
     RECT  94.208 1.728 94.259 95.208 ;
     RECT  94.259 1.728 94.312 95.052 ;
     RECT  94.312 1.728 94.504 94.782 ;
     RECT  94.504 19.056 94.691 71.112 ;
     RECT  94.504 4.272 94.717 4.296 ;
     RECT  94.504 1.728 94.781 1.752 ;
     RECT  94.504 17.28 94.817 17.64 ;
     RECT  94.817 17.28 95.141 17.304 ;
     RECT  94.504 77.328 95.213 77.352 ;
     RECT  95.029 1.152 95.501 1.176 ;
     RECT  94.504 91.776 95.501 93.912 ;
     RECT  95.42 94.992 95.507 95.016 ;
     RECT  95.501 92.4 95.573 93.912 ;
     RECT  94.691 20.112 96.037 71.112 ;
     RECT  96.428 3.168 96.469 3.192 ;
     RECT  96.428 4.272 96.469 4.296 ;
     RECT  94.504 15.168 96.469 16.056 ;
     RECT  96.325 0.192 96.509 0.216 ;
     RECT  96.469 3.168 96.515 4.296 ;
     RECT  96.709 94.992 96.796 95.016 ;
     RECT  96.037 19.488 96.853 71.112 ;
     RECT  96.469 14.256 96.899 16.056 ;
     RECT  96.899 14.784 96.94 16.056 ;
     RECT  96.853 19.2 96.94 71.112 ;
     RECT  96.515 3.696 97.265 3.72 ;
     RECT  95.573 93.792 97.441 93.912 ;
     RECT  95.573 92.4 97.669 92.424 ;
     RECT  97.621 0.192 97.877 0.216 ;
     RECT  97.957 94.992 98.057 95.016 ;
     RECT  97.669 92.352 98.101 92.424 ;
     RECT  96.94 19.632 98.197 71.112 ;
     RECT  97.981 17.088 98.204 17.112 ;
     RECT  97.837 4.512 98.291 4.536 ;
     RECT  98.197 18.672 98.291 71.112 ;
     RECT  98.101 91.776 98.309 92.424 ;
     RECT  96.94 15.168 98.629 16.056 ;
     RECT  98.204 17.04 98.629 17.112 ;
     RECT  98.309 92.4 98.773 92.424 ;
     RECT  97.441 93.456 98.773 93.912 ;
     RECT  98.869 0.192 98.993 0.216 ;
     RECT  99.277 18.72 99.493 18.744 ;
     RECT  98.291 19.872 99.493 71.112 ;
     RECT  98.701 3.936 99.608 3.96 ;
     RECT  98.629 15.168 99.608 17.112 ;
     RECT  99.493 18.72 99.608 71.112 ;
     RECT  98.773 92.4 99.608 93.912 ;
     RECT  99.164 94.992 99.608 95.016 ;
     RECT  99.608 2.148 99.712 95.052 ;
     RECT  99.712 2.418 99.904 95.016 ;
     RECT  99.904 3.936 99.965 4.536 ;
     RECT  99.904 19.152 100.355 71.112 ;
     RECT  100.165 1.152 100.397 1.176 ;
     RECT  99.904 94.992 100.499 95.016 ;
     RECT  99.904 15.264 100.643 16.824 ;
     RECT  99.904 91.776 100.901 93.912 ;
     RECT  100.643 15.984 100.933 16.824 ;
     RECT  99.965 4.512 100.94 4.536 ;
     RECT  100.933 15.984 100.981 17.112 ;
     RECT  100.94 4.512 101.009 4.872 ;
     RECT  101.009 4.848 101.027 4.872 ;
     RECT  100.355 19.152 101.413 19.176 ;
     RECT  100.981 15.984 101.459 17.304 ;
     RECT  101.461 0.192 101.585 0.216 ;
     RECT  101.413 18.384 101.749 19.176 ;
     RECT  100.355 20.256 101.749 71.112 ;
     RECT  101.749 18.384 101.795 71.112 ;
     RECT  101.689 94.992 101.795 95.016 ;
     RECT  101.795 18.384 101.836 19.512 ;
     RECT  101.459 15.984 102.037 17.112 ;
     RECT  102.037 15.312 102.083 17.112 ;
     RECT  100.901 92.4 102.197 93.912 ;
     RECT  102.083 15.312 102.557 16.824 ;
     RECT  101.795 20.544 102.707 71.112 ;
     RECT  102.197 92.4 102.725 92.424 ;
     RECT  101.836 18.384 102.851 19.176 ;
     RECT  102.805 14.88 102.889 14.904 ;
     RECT  102.851 19.104 102.949 19.176 ;
     RECT  102.709 0.192 103.061 0.216 ;
     RECT  102.997 94.992 103.097 95.016 ;
     RECT  102.764 4.512 103.169 4.536 ;
     RECT  102.085 3.408 103.205 3.432 ;
     RECT  102.725 92.352 103.667 92.424 ;
     RECT  102.197 93.744 103.705 93.912 ;
     RECT  102.949 19.104 103.765 19.56 ;
     RECT  102.707 20.64 103.765 71.112 ;
     RECT  102.557 15.984 103.957 16.824 ;
     RECT  103.667 92.4 103.957 92.424 ;
     RECT  103.705 93.456 103.957 93.912 ;
     RECT  103.957 92.4 104.137 93.912 ;
     RECT  104.137 92.4 104.204 94.056 ;
     RECT  104.101 4.272 104.245 4.296 ;
     RECT  104.005 0.576 104.249 0.6 ;
     RECT  103.957 15.984 104.677 17.112 ;
     RECT  103.765 19.104 104.78 71.112 ;
     RECT  104.677 15.984 104.821 17.688 ;
     RECT  104.78 18.672 104.821 71.112 ;
     RECT  104.245 4.272 105.008 4.824 ;
     RECT  104.821 15.984 105.008 71.112 ;
     RECT  104.204 92.4 105.008 95.016 ;
     RECT  105.008 2.148 105.112 95.052 ;
     RECT  105.112 2.418 105.304 95.016 ;
     RECT  105.304 3.744 105.443 3.768 ;
     RECT  105.304 15.984 105.484 71.112 ;
     RECT  105.304 93.744 105.581 95.016 ;
     RECT  105.304 91.2 105.587 92.424 ;
     RECT  105.301 1.152 105.761 1.176 ;
     RECT  105.587 91.776 106.093 92.424 ;
     RECT  105.484 18.96 106.157 71.112 ;
     RECT  106.093 92.4 106.585 92.424 ;
     RECT  105.581 93.744 106.585 94.056 ;
     RECT  105.304 72.816 106.652 72.84 ;
     RECT  106.157 20.64 106.693 71.112 ;
     RECT  106.585 92.4 106.7 94.056 ;
     RECT  106.652 72.816 106.739 72.936 ;
     RECT  106.7 92.4 106.739 95.016 ;
     RECT  106.739 92.928 106.787 95.016 ;
     RECT  105.484 15.984 106.837 17.688 ;
     RECT  106.597 0.192 106.841 0.216 ;
     RECT  106.796 4.512 106.883 4.536 ;
     RECT  106.837 15.408 106.979 17.688 ;
     RECT  106.157 18.96 107.084 18.984 ;
     RECT  107.084 18.384 107.171 18.984 ;
     RECT  106.979 15.408 107.273 16.824 ;
     RECT  106.837 3.36 107.345 3.384 ;
     RECT  107.171 18.672 107.773 18.984 ;
     RECT  106.693 20.64 107.773 71.64 ;
     RECT  106.787 92.928 107.845 94.056 ;
     RECT  107.845 92.352 107.989 94.056 ;
     RECT  107.989 92.352 108.076 95.016 ;
     RECT  107.273 15.984 108.349 16.824 ;
     RECT  108.076 92.352 108.397 94.056 ;
     RECT  107.989 3.936 108.707 3.96 ;
     RECT  108.349 15.984 108.997 17.64 ;
     RECT  108.997 15.984 109.148 17.688 ;
     RECT  107.773 18.672 109.148 71.64 ;
     RECT  108.397 92.928 109.181 94.056 ;
     RECT  109.148 15.984 109.235 71.64 ;
     RECT  109.196 94.992 109.283 95.016 ;
     RECT  109.181 92.928 109.957 93.816 ;
     RECT  109.235 15.984 110.197 17.688 ;
     RECT  109.189 3.696 110.408 3.72 ;
     RECT  110.197 15.312 110.408 17.688 ;
     RECT  109.235 18.768 110.408 71.64 ;
     RECT  106.739 72.816 110.408 72.84 ;
     RECT  109.957 92.352 110.408 93.816 ;
     RECT  110.408 2.148 110.485 95.052 ;
     RECT  110.485 2.148 110.512 95.208 ;
     RECT  110.512 2.418 110.585 95.208 ;
     RECT  110.585 2.418 110.704 94.782 ;
     RECT  110.704 14.832 111.125 16.824 ;
     RECT  110.704 18.816 111.491 19.128 ;
     RECT  110.704 3.984 111.593 4.296 ;
     RECT  111.593 4.272 111.635 4.296 ;
     RECT  111.125 14.832 111.635 14.856 ;
     RECT  110.704 92.352 111.709 93.912 ;
     RECT  111.709 92.352 111.779 92.376 ;
     RECT  111.692 96.336 111.779 96.36 ;
     RECT  111.709 93.456 111.809 93.912 ;
     RECT  110.704 20.64 112.093 71.64 ;
     RECT  107.845 1.152 112.277 1.176 ;
     RECT  111.125 15.984 112.561 16.824 ;
     RECT  112.093 19.728 112.883 71.64 ;
     RECT  112.933 92.4 112.957 92.424 ;
     RECT  112.561 15.984 112.993 17.496 ;
     RECT  112.821 18.672 112.993 18.696 ;
     RECT  112.957 92.352 113.069 92.424 ;
     RECT  112.921 94.992 113.075 95.016 ;
     RECT  112.705 3.936 113.101 3.96 ;
     RECT  112.993 15.984 113.125 18.696 ;
     RECT  112.981 0.192 113.141 0.216 ;
     RECT  113.101 3.888 113.185 3.96 ;
     RECT  113.185 3.936 113.267 3.96 ;
     RECT  111.809 93.504 113.413 93.912 ;
     RECT  113.069 92.352 113.645 92.376 ;
     RECT  113.125 15.984 113.852 18.792 ;
     RECT  113.852 15.984 113.939 19.368 ;
     RECT  113.939 15.984 113.987 18.888 ;
     RECT  113.987 15.984 114.005 16.536 ;
     RECT  113.987 18.768 114.005 18.888 ;
     RECT  113.413 93.456 114.037 93.912 ;
     RECT  114.037 92.928 114.181 93.912 ;
     RECT  114.005 18.768 114.257 18.792 ;
     RECT  114.181 92.928 114.323 95.016 ;
     RECT  114.323 92.928 115.405 94.344 ;
     RECT  115.093 14.064 115.477 14.088 ;
     RECT  115.405 92.928 115.621 95.016 ;
     RECT  112.883 20.64 115.729 71.64 ;
     RECT  114.277 1.152 115.805 1.176 ;
     RECT  114.829 4.512 115.808 4.536 ;
     RECT  115.477 14.064 115.808 14.808 ;
     RECT  114.005 15.984 115.808 16.008 ;
     RECT  113.987 17.664 115.808 17.688 ;
     RECT  115.441 18.816 115.808 18.84 ;
     RECT  115.729 20.4 115.808 71.64 ;
     RECT  110.704 72.816 115.808 72.84 ;
     RECT  113.461 74.064 115.808 74.088 ;
     RECT  115.621 92.352 115.808 95.016 ;
     RECT  115.808 2.148 115.912 95.052 ;
     RECT  115.912 2.418 116.104 95.016 ;
     RECT  116.104 14.16 116.243 14.184 ;
     RECT  116.104 18.528 116.243 19.032 ;
     RECT  116.104 91.2 116.387 91.224 ;
     RECT  116.104 93.216 116.819 95.016 ;
     RECT  116.104 20.016 116.867 71.64 ;
     RECT  116.243 19.008 116.921 19.032 ;
     RECT  116.821 1.152 117.101 1.176 ;
     RECT  116.867 20.016 117.443 20.04 ;
     RECT  116.104 15.312 117.457 16.008 ;
     RECT  116.104 74.064 117.529 74.088 ;
     RECT  116.104 4.512 117.637 4.536 ;
     RECT  117.457 15.312 117.637 16.056 ;
     RECT  117.637 3.936 117.683 4.536 ;
     RECT  117.357 18.672 117.683 18.696 ;
     RECT  116.819 93.216 117.709 94.344 ;
     RECT  117.637 14.88 117.721 16.056 ;
     RECT  117.529 74.016 117.817 74.088 ;
     RECT  117.817 73.92 117.857 74.088 ;
     RECT  117.721 15.312 117.884 16.056 ;
     RECT  117.884 15.312 117.925 16.2 ;
     RECT  117.925 15.312 117.971 17.16 ;
     RECT  117.961 96.336 118.067 96.36 ;
     RECT  117.971 17.04 118.253 17.16 ;
     RECT  117.709 92.352 118.259 94.344 ;
     RECT  118.393 18.144 118.652 18.168 ;
     RECT  116.867 21.264 118.717 71.64 ;
     RECT  118.117 1.152 118.721 1.176 ;
     RECT  117.683 3.936 118.892 3.96 ;
     RECT  118.652 18.144 118.897 18.936 ;
     RECT  117.733 19.968 118.897 19.992 ;
     RECT  118.897 18.144 118.973 19.992 ;
     RECT  118.892 3.936 118.979 4.536 ;
     RECT  118.253 17.04 118.979 17.064 ;
     RECT  118.717 21.12 119.005 71.64 ;
     RECT  117.857 73.92 119.077 74.04 ;
     RECT  118.973 19.2 119.153 19.32 ;
     RECT  118.259 93.216 119.185 94.344 ;
     RECT  119.185 93.216 119.315 95.016 ;
     RECT  119.413 0.576 119.513 0.6 ;
     RECT  119.153 19.2 119.513 19.224 ;
     RECT  117.971 15.984 119.689 16.056 ;
     RECT  119.005 21.072 119.905 71.64 ;
     RECT  119.905 20.544 119.941 71.64 ;
     RECT  118.973 18.144 119.989 18.216 ;
     RECT  119.948 4.272 120.035 4.296 ;
     RECT  119.989 18.096 120.049 18.216 ;
     RECT  119.315 93.216 120.049 94.104 ;
     RECT  120.049 92.352 120.133 94.104 ;
     RECT  119.941 20.304 120.161 71.64 ;
     RECT  120.133 92.976 120.517 94.104 ;
     RECT  119.689 15.024 120.805 16.056 ;
     RECT  120.661 1.152 120.917 1.176 ;
     RECT  120.049 18.096 121.052 18.264 ;
     RECT  120.161 20.304 121.093 71.16 ;
     RECT  120.877 4.656 121.208 4.68 ;
     RECT  120.805 15.024 121.208 16.2 ;
     RECT  121.052 18.096 121.208 18.696 ;
     RECT  121.093 19.776 121.208 71.16 ;
     RECT  116.104 72.816 121.208 72.84 ;
     RECT  119.077 73.824 121.208 74.04 ;
     RECT  120.517 92.976 121.208 95.016 ;
     RECT  121.208 2.148 121.312 95.052 ;
     RECT  121.312 2.418 121.504 95.016 ;
     RECT  121.504 4.224 121.619 4.872 ;
     RECT  121.504 14.592 121.715 16.008 ;
     RECT  121.504 94.992 121.852 95.016 ;
     RECT  121.715 14.592 122.003 15.048 ;
     RECT  121.504 92.976 122.003 93.912 ;
     RECT  121.504 20.304 122.099 71.256 ;
     RECT  121.957 0.576 122.321 0.6 ;
     RECT  121.504 13.056 122.645 13.08 ;
     RECT  121.619 4.224 122.684 4.248 ;
     RECT  122.684 3.312 122.771 4.248 ;
     RECT  122.684 19.2 122.771 19.224 ;
     RECT  122.771 3.696 123.02 4.248 ;
     RECT  122.929 94.992 123.059 95.016 ;
     RECT  123.02 3.696 123.107 4.296 ;
     RECT  122.725 12.48 123.107 12.504 ;
     RECT  123.107 3.696 123.401 3.864 ;
     RECT  122.099 20.304 123.901 71.112 ;
     RECT  124.261 94.992 124.589 95.016 ;
     RECT  122.003 15.024 124.837 15.048 ;
     RECT  122.003 93.216 124.873 93.912 ;
     RECT  124.837 14.112 124.883 15.048 ;
     RECT  123.401 3.84 125.228 3.864 ;
     RECT  125.228 3.36 125.269 3.864 ;
     RECT  125.269 3.36 125.315 4.296 ;
     RECT  123.253 0.192 125.849 0.216 ;
     RECT  124.883 14.112 125.989 14.808 ;
     RECT  123.901 20.16 126.241 71.112 ;
     RECT  125.315 4.272 126.608 4.296 ;
     RECT  125.989 14.112 126.608 14.952 ;
     RECT  121.504 18.144 126.608 18.168 ;
     RECT  126.241 19.776 126.608 71.112 ;
     RECT  121.504 72.816 126.608 72.84 ;
     RECT  121.504 73.92 126.608 74.04 ;
     RECT  124.873 93.12 126.608 93.912 ;
     RECT  125.557 94.992 126.608 95.016 ;
     RECT  126.608 2.148 126.712 95.052 ;
     RECT  126.712 2.418 126.745 95.052 ;
     RECT  126.745 2.418 126.851 95.16 ;
     RECT  126.851 2.418 126.904 94.782 ;
     RECT  126.904 3.36 127.235 3.384 ;
     RECT  127.093 0.192 127.361 0.216 ;
     RECT  126.904 14.112 127.475 15.192 ;
     RECT  126.904 19.776 127.475 71.112 ;
     RECT  127.475 20.256 127.516 71.112 ;
     RECT  128.053 94.992 128.153 95.016 ;
     RECT  126.904 93.216 128.293 93.912 ;
     RECT  128.293 93.216 128.621 94.056 ;
     RECT  128.389 0.192 128.801 0.216 ;
     RECT  127.516 20.304 129.229 71.112 ;
     RECT  129.301 94.992 129.388 95.016 ;
     RECT  129.337 13.056 129.685 13.08 ;
     RECT  126.904 4.512 129.692 4.536 ;
     RECT  129.685 12.912 129.697 13.08 ;
     RECT  129.229 20.016 129.731 71.112 ;
     RECT  129.692 4.272 129.733 4.536 ;
     RECT  129.733 3.696 129.779 4.536 ;
     RECT  129.697 12.528 129.781 13.08 ;
     RECT  129.779 3.696 130.097 3.72 ;
     RECT  129.781 13.056 130.165 13.08 ;
     RECT  127.475 14.112 130.165 14.952 ;
     RECT  130.165 13.056 130.211 14.952 ;
     RECT  130.211 13.056 130.252 14.664 ;
     RECT  126.904 73.92 130.525 74.04 ;
     RECT  129.731 20.304 130.561 71.112 ;
     RECT  130.549 94.992 130.637 95.016 ;
     RECT  129.685 1.152 131.285 1.176 ;
     RECT  131.029 4.128 132.008 4.152 ;
     RECT  130.252 13.056 132.008 13.56 ;
     RECT  130.252 14.64 132.008 14.664 ;
     RECT  126.904 18.144 132.008 18.168 ;
     RECT  130.561 20.304 132.008 71.16 ;
     RECT  126.904 72.816 132.008 72.84 ;
     RECT  130.525 73.824 132.008 74.04 ;
     RECT  128.621 93.216 132.008 93.912 ;
     RECT  131.713 94.992 132.008 95.016 ;
     RECT  132.008 2.148 132.112 95.052 ;
     RECT  132.112 2.418 132.304 95.016 ;
     RECT  132.229 0.192 132.329 0.216 ;
     RECT  132.304 9.072 132.625 9.096 ;
     RECT  132.304 15.984 132.625 16.008 ;
     RECT  132.304 13.056 132.869 13.56 ;
     RECT  132.304 93.216 133.013 93.912 ;
     RECT  132.304 4.128 133.091 4.632 ;
     RECT  132.304 94.992 133.091 95.016 ;
     RECT  133.013 93.312 133.409 93.912 ;
     RECT  133.513 0.192 133.597 0.216 ;
     RECT  132.304 20.304 133.632 71.16 ;
     RECT  133.632 20.304 133.805 65.88 ;
     RECT  132.304 73.824 133.859 74.04 ;
     RECT  133.632 67.056 133.913 71.16 ;
     RECT  133.805 26.736 133.949 65.88 ;
     RECT  133.091 4.224 134.053 4.248 ;
     RECT  133.805 20.304 134.053 25.752 ;
     RECT  132.869 13.056 134.099 13.08 ;
     RECT  134.012 16.176 134.099 16.2 ;
     RECT  134.053 3.936 134.147 4.248 ;
     RECT  134.06 8.88 134.147 8.904 ;
     RECT  133.949 26.736 134.237 65.784 ;
     RECT  133.913 67.056 134.291 70.92 ;
     RECT  134.197 94.992 134.339 95.016 ;
     RECT  134.237 26.784 134.435 65.784 ;
     RECT  133.409 93.456 134.485 93.912 ;
     RECT  134.435 28.416 134.525 65.784 ;
     RECT  134.053 19.824 134.561 25.752 ;
     RECT  133.859 73.872 134.561 74.04 ;
     RECT  134.525 64.8 134.597 65.784 ;
     RECT  134.147 4.224 134.633 4.248 ;
     RECT  134.525 28.416 134.633 58.104 ;
     RECT  134.525 59.136 134.633 62.712 ;
     RECT  134.633 29.088 134.669 58.104 ;
     RECT  134.435 26.784 134.675 27.384 ;
     RECT  134.633 59.232 134.741 62.712 ;
     RECT  134.669 29.088 135.065 56.76 ;
     RECT  135.065 29.088 135.101 55.32 ;
     RECT  135.065 56.736 135.101 56.76 ;
     RECT  134.669 57.792 135.101 58.104 ;
     RECT  134.741 59.232 135.101 62.04 ;
     RECT  134.561 21.408 135.107 25.752 ;
     RECT  135.101 29.088 135.137 55.128 ;
     RECT  134.773 1.152 135.173 1.176 ;
     RECT  134.675 26.784 135.203 27.288 ;
     RECT  135.137 29.088 135.353 46.488 ;
     RECT  134.485 93.312 135.389 93.912 ;
     RECT  135.541 94.992 135.628 95.016 ;
     RECT  135.137 47.904 135.749 55.128 ;
     RECT  135.749 50.688 135.785 55.128 ;
     RECT  135.353 29.088 135.821 38.424 ;
     RECT  135.353 39.456 135.965 46.488 ;
     RECT  135.785 50.688 135.965 53.784 ;
     RECT  135.785 55.104 135.965 55.128 ;
     RECT  134.561 19.824 135.973 20.328 ;
     RECT  135.965 50.832 136.001 53.784 ;
     RECT  134.597 65.184 136.001 65.784 ;
     RECT  135.821 29.712 136.019 38.424 ;
     RECT  136.019 29.952 136.037 38.424 ;
     RECT  136.037 30.912 136.073 38.424 ;
     RECT  136.001 53.232 136.073 53.784 ;
     RECT  136.001 65.184 136.073 65.208 ;
     RECT  135.277 3.936 136.105 3.96 ;
     RECT  135.997 26.736 136.145 26.76 ;
     RECT  136.069 0.192 136.153 0.216 ;
     RECT  136.105 3.312 136.165 3.96 ;
     RECT  135.965 41.184 136.181 46.488 ;
     RECT  135.749 47.904 136.181 49.656 ;
     RECT  136.165 3.312 136.211 4.296 ;
     RECT  135.973 19.392 136.217 20.328 ;
     RECT  136.181 48.912 136.217 49.656 ;
     RECT  136.211 3.936 136.252 4.296 ;
     RECT  136.181 47.904 136.289 47.928 ;
     RECT  136.261 28.416 136.348 28.44 ;
     RECT  136.073 31.056 136.348 38.424 ;
     RECT  136.348 31.2 136.357 38.424 ;
     RECT  135.965 39.456 136.357 40.152 ;
     RECT  136.001 50.832 136.397 52.056 ;
     RECT  135.107 21.408 136.433 25.656 ;
     RECT  135.101 57.792 136.501 58.008 ;
     RECT  136.645 27.984 136.7 28.008 ;
     RECT  136.501 57.6 136.753 58.008 ;
     RECT  136.753 57.6 136.825 58.728 ;
     RECT  136.753 96.336 136.883 96.36 ;
     RECT  136.825 56.448 137.069 56.472 ;
     RECT  136.433 25.056 137.113 25.656 ;
     RECT  137.036 30.192 137.173 30.216 ;
     RECT  137.069 55.872 137.221 56.472 ;
     RECT  135.389 93.744 137.269 93.912 ;
     RECT  136.252 3.936 137.408 3.96 ;
     RECT  132.304 14.64 137.408 14.664 ;
     RECT  132.304 18.144 137.408 18.168 ;
     RECT  136.217 20.304 137.408 20.328 ;
     RECT  136.433 21.408 137.408 23.736 ;
     RECT  137.113 25.056 137.408 25.848 ;
     RECT  136.7 27.312 137.408 28.008 ;
     RECT  137.173 29.568 137.408 30.216 ;
     RECT  136.357 31.2 137.408 40.152 ;
     RECT  136.181 41.184 137.408 45.72 ;
     RECT  136.217 48.912 137.408 48.936 ;
     RECT  136.397 50.832 137.408 51.48 ;
     RECT  136.073 53.232 137.408 53.496 ;
     RECT  137.221 55.44 137.408 56.472 ;
     RECT  136.825 57.552 137.408 58.728 ;
     RECT  134.291 67.056 137.408 70.872 ;
     RECT  132.304 72.816 137.408 72.84 ;
     RECT  134.561 73.872 137.408 73.896 ;
     RECT  137.269 93.744 137.408 94.296 ;
     RECT  137.365 0.192 137.449 0.216 ;
     RECT  137.408 2.148 137.512 95.052 ;
     RECT  137.512 2.418 137.704 95.016 ;
     RECT  137.704 93.744 137.765 93.912 ;
     RECT  137.704 55.44 137.801 55.464 ;
     RECT  137.704 24.24 137.843 24.264 ;
     RECT  137.704 44.352 137.843 45.192 ;
     RECT  137.704 46.224 137.891 46.776 ;
     RECT  137.704 30.192 137.909 42.792 ;
     RECT  137.704 14.64 137.939 14.664 ;
     RECT  137.704 50.16 137.939 51.48 ;
     RECT  137.704 20.496 137.98 23.112 ;
     RECT  137.909 42 137.981 42.792 ;
     RECT  137.704 25.248 137.987 29.208 ;
     RECT  137.939 50.16 138.017 51.384 ;
     RECT  137.981 42 138.083 42.024 ;
     RECT  137.843 44.832 138.083 45.192 ;
     RECT  137.987 25.248 138.125 25.752 ;
     RECT  137.704 94.992 138.131 95.016 ;
     RECT  138.083 45.168 138.179 45.192 ;
     RECT  138.125 25.296 138.197 25.752 ;
     RECT  137.704 3.936 138.241 4.536 ;
     RECT  137.909 30.192 138.485 40.536 ;
     RECT  137.987 26.736 138.515 29.208 ;
     RECT  138.241 4.512 138.707 4.536 ;
     RECT  137.704 61.008 138.757 61.032 ;
     RECT  137.891 46.752 138.803 46.776 ;
     RECT  137.704 73.872 138.803 73.896 ;
     RECT  137.704 18.144 138.899 18.168 ;
     RECT  138.757 61.008 138.899 61.32 ;
     RECT  138.899 61.296 138.995 61.32 ;
     RECT  138.949 48.672 139.129 48.696 ;
     RECT  138.661 1.152 139.133 1.176 ;
     RECT  137.98 21.408 139.241 23.112 ;
     RECT  139.129 48.672 139.283 49.032 ;
     RECT  138.485 30.24 139.379 40.536 ;
     RECT  139.241 23.088 139.385 23.112 ;
     RECT  139.333 94.992 139.421 95.016 ;
     RECT  139.285 53.184 139.427 53.208 ;
     RECT  137.704 72.816 139.427 72.84 ;
     RECT  138.515 26.736 139.475 27.24 ;
     RECT  138.515 28.464 139.489 29.208 ;
     RECT  139.379 30.24 139.493 40.008 ;
     RECT  139.493 30.432 139.601 40.008 ;
     RECT  139.601 30.432 139.637 31.176 ;
     RECT  139.196 43.296 139.667 43.32 ;
     RECT  139.601 32.496 139.709 40.008 ;
     RECT  139.561 4.272 139.715 4.296 ;
     RECT  139.628 24.096 139.715 24.12 ;
     RECT  139.633 40.992 139.907 41.016 ;
     RECT  139.861 42.72 139.948 42.792 ;
     RECT  139.709 32.736 140.003 40.008 ;
     RECT  139.637 30.72 140.033 31.176 ;
     RECT  139.909 0.192 140.141 0.216 ;
     RECT  139.489 27.264 140.141 29.208 ;
     RECT  137.765 93.888 140.209 93.912 ;
     RECT  140.003 32.736 140.387 39.816 ;
     RECT  140.141 27.264 140.393 28.968 ;
     RECT  138.197 25.728 140.533 25.752 ;
     RECT  140.393 27.264 140.533 28.872 ;
     RECT  140.54 94.992 140.627 95.016 ;
     RECT  139.948 42.768 140.681 42.792 ;
     RECT  140.533 25.104 140.723 25.752 ;
     RECT  140.641 4.512 140.725 4.536 ;
     RECT  140.033 30.72 140.749 31.128 ;
     RECT  140.533 27.168 140.789 28.872 ;
     RECT  140.749 30 140.861 31.128 ;
     RECT  140.789 27.168 140.965 28.68 ;
     RECT  140.893 3.936 141.011 3.96 ;
     RECT  140.965 27.072 141.113 28.68 ;
     RECT  140.965 43.344 141.257 43.368 ;
     RECT  140.387 33.504 141.293 39.816 ;
     RECT  141.205 0.192 141.329 0.216 ;
     RECT  141.109 31.68 141.577 31.704 ;
     RECT  141.548 40.8 141.635 40.824 ;
     RECT  140.861 30 141.644 30.024 ;
     RECT  141.113 27.072 141.731 28.488 ;
     RECT  141.644 29.904 141.865 30.024 ;
     RECT  141.865 29.904 141.973 30.36 ;
     RECT  141.577 31.68 141.973 32.52 ;
     RECT  141.731 27.072 142.297 27.624 ;
     RECT  140.209 93.456 142.297 93.912 ;
     RECT  141.829 94.992 142.297 95.016 ;
     RECT  141.937 40.704 142.369 40.728 ;
     RECT  141.293 33.504 142.405 38.808 ;
     RECT  142.369 39.792 142.405 40.728 ;
     RECT  141.973 29.904 142.412 32.52 ;
     RECT  142.405 33.504 142.412 40.728 ;
     RECT  142.297 93.456 142.453 95.016 ;
     RECT  142.44 0.192 142.561 0.216 ;
     RECT  142.412 29.904 142.597 40.728 ;
     RECT  142.597 29.904 142.652 40.824 ;
     RECT  141.589 45.024 142.693 45.048 ;
     RECT  141.98 4.512 142.808 4.536 ;
     RECT  139.241 21.408 142.808 21.432 ;
     RECT  140.389 23.04 142.808 23.064 ;
     RECT  140.723 25.728 142.808 25.752 ;
     RECT  142.297 26.832 142.808 27.624 ;
     RECT  142.652 28.944 142.808 40.824 ;
     RECT  142.501 42.768 142.808 42.792 ;
     RECT  142.693 44.16 142.808 45.048 ;
     RECT  142.693 46.224 142.808 46.248 ;
     RECT  139.283 48.672 142.808 48.696 ;
     RECT  138.017 50.832 142.808 51.384 ;
     RECT  137.704 67.056 142.808 70.872 ;
     RECT  142.453 93.216 142.808 95.016 ;
     RECT  142.808 2.148 142.912 95.052 ;
     RECT  142.912 2.418 143.036 95.052 ;
     RECT  143.036 2.418 143.104 95.16 ;
     RECT  143.104 95.136 143.123 95.16 ;
     RECT  143.104 25.728 143.603 27.624 ;
     RECT  143.104 28.992 143.603 29.016 ;
     RECT  143.104 3.936 143.749 4.536 ;
     RECT  143.104 30.672 143.795 40.584 ;
     RECT  143.795 30.672 143.813 39.816 ;
     RECT  143.749 0.192 143.921 0.216 ;
     RECT  143.813 30.672 144.245 39.192 ;
     RECT  144.325 94.992 144.412 95.016 ;
     RECT  144.245 30.672 144.563 35.16 ;
     RECT  144.563 30.672 144.565 31.8 ;
     RECT  143.749 3.936 144.613 3.96 ;
     RECT  144.38 44.256 144.707 44.28 ;
     RECT  144.563 32.976 144.857 35.16 ;
     RECT  144.857 32.976 144.893 34.728 ;
     RECT  143.104 93.12 145.069 93.912 ;
     RECT  144.565 30.144 145.105 31.8 ;
     RECT  145.033 0.576 145.117 0.6 ;
     RECT  144.421 46.176 145.141 46.2 ;
     RECT  145.1 4.848 145.187 4.872 ;
     RECT  144.853 44.304 145.187 44.328 ;
     RECT  145.141 45.408 145.253 46.2 ;
     RECT  144.997 40.176 145.381 40.2 ;
     RECT  144.245 36.336 145.393 39.192 ;
     RECT  145.381 40.176 145.393 40.44 ;
     RECT  145.34 42.096 145.427 42.12 ;
     RECT  145.532 94.992 145.619 95.016 ;
     RECT  143.104 67.824 145.685 70.872 ;
     RECT  145.393 36.336 145.753 40.44 ;
     RECT  145.105 30.048 145.789 31.8 ;
     RECT  145.069 92.304 145.907 93.912 ;
     RECT  145.789 30.048 145.964 31.944 ;
     RECT  144.893 32.976 145.964 34.68 ;
     RECT  145.753 36.336 146.005 40.536 ;
     RECT  145.964 30.048 146.041 34.68 ;
     RECT  146.041 30.048 146.051 34.968 ;
     RECT  146.005 35.952 146.189 40.536 ;
     RECT  146.051 32.976 146.195 34.968 ;
     RECT  146.195 34.56 146.329 34.968 ;
     RECT  146.189 35.952 146.329 39.864 ;
     RECT  146.051 30.048 146.333 31.944 ;
     RECT  146.333 30.048 146.339 31.608 ;
     RECT  145.253 46.176 146.405 46.2 ;
     RECT  145.609 3.408 146.437 3.432 ;
     RECT  146.329 34.56 146.513 39.864 ;
     RECT  146.339 30.048 146.531 31.56 ;
     RECT  146.341 1.152 146.729 1.176 ;
     RECT  146.821 94.992 146.908 95.016 ;
     RECT  146.869 44.448 146.953 44.472 ;
     RECT  145.907 93.12 147.049 93.912 ;
     RECT  146.401 41.76 147.059 41.784 ;
     RECT  146.437 3.408 147.068 3.576 ;
     RECT  147.068 3.408 147.109 4.296 ;
     RECT  143.603 25.728 147.109 25.752 ;
     RECT  143.603 26.736 147.109 27.624 ;
     RECT  147.109 3.36 147.155 4.296 ;
     RECT  147.109 25.728 147.197 27.624 ;
     RECT  147.197 26.736 147.241 27.624 ;
     RECT  146.513 34.56 147.733 39.576 ;
     RECT  146.195 32.976 147.836 33.576 ;
     RECT  147.733 34.56 147.836 39.72 ;
     RECT  147.836 32.976 147.877 39.72 ;
     RECT  147.637 0.192 148.025 0.216 ;
     RECT  148.117 95.136 148.204 95.16 ;
     RECT  147.155 3.36 148.208 3.384 ;
     RECT  143.104 23.04 148.208 23.064 ;
     RECT  147.197 25.728 148.208 25.752 ;
     RECT  147.241 27.6 148.208 27.624 ;
     RECT  146.531 30.048 148.208 31.368 ;
     RECT  147.877 32.448 148.208 39.72 ;
     RECT  148.028 40.8 148.208 40.824 ;
     RECT  143.104 48.672 148.208 48.696 ;
     RECT  143.104 50.832 148.208 51.384 ;
     RECT  145.685 67.824 148.208 67.848 ;
     RECT  145.685 69.024 148.208 70.872 ;
     RECT  147.049 93.12 148.208 94.104 ;
     RECT  148.208 2.148 148.312 95.052 ;
     RECT  148.312 2.418 148.504 94.782 ;
     RECT  148.504 33.552 148.643 34.104 ;
     RECT  148.504 35.424 148.781 38.376 ;
     RECT  148.504 4.512 148.883 4.536 ;
     RECT  148.504 22.752 149.075 23.736 ;
     RECT  148.504 30.048 149.075 31.368 ;
     RECT  148.504 25.728 149.321 25.752 ;
     RECT  148.504 93.312 149.365 94.782 ;
     RECT  149.365 93.312 149.465 95.016 ;
     RECT  148.885 1.152 149.537 1.176 ;
     RECT  148.781 35.568 149.605 38.376 ;
     RECT  148.504 39.504 149.605 40.488 ;
     RECT  149.605 35.568 149.651 40.488 ;
     RECT  148.643 33.552 149.756 33.576 ;
     RECT  149.797 28.896 149.821 28.92 ;
     RECT  149.075 30.048 149.821 30.6 ;
     RECT  149.756 33.552 149.843 34.104 ;
     RECT  149.651 35.568 149.861 39.864 ;
     RECT  149.465 93.312 149.893 94.104 ;
     RECT  149.861 35.76 149.969 39.864 ;
     RECT  149.969 35.76 150.077 35.784 ;
     RECT  149.969 36.768 150.113 39.864 ;
     RECT  150.284 4.272 150.325 4.296 ;
     RECT  150.325 3.36 150.371 4.296 ;
     RECT  149.821 28.896 150.371 30.6 ;
     RECT  150.181 0.192 150.401 0.216 ;
     RECT  148.504 27.6 150.515 27.624 ;
     RECT  149.893 93.216 150.613 94.104 ;
     RECT  150.371 3.36 150.653 3.384 ;
     RECT  150.613 93.216 150.725 95.016 ;
     RECT  150.113 38.88 150.757 39.864 ;
     RECT  149.075 22.752 150.853 23.064 ;
     RECT  150.469 25.68 150.899 25.704 ;
     RECT  149.605 65.664 151.148 65.688 ;
     RECT  149.843 33.552 151.235 33.576 ;
     RECT  151.148 65.616 151.235 65.688 ;
     RECT  150.113 36.768 151.441 37.896 ;
     RECT  150.757 38.88 151.441 40.824 ;
     RECT  148.504 48.672 151.481 48.696 ;
     RECT  151.477 0.192 151.561 0.216 ;
     RECT  150.371 29.616 151.625 30.6 ;
     RECT  151.58 3.84 151.667 3.864 ;
     RECT  150.725 93.216 151.861 94.056 ;
     RECT  151.441 36.768 151.868 40.824 ;
     RECT  151.868 36.24 151.877 40.824 ;
     RECT  151.877 36.24 151.955 39.48 ;
     RECT  151.877 40.512 151.955 40.824 ;
     RECT  151.861 93.216 152.021 95.016 ;
     RECT  152.021 93.216 152.057 94.056 ;
     RECT  152.057 93.504 152.129 94.056 ;
     RECT  151.955 36.24 152.197 39.288 ;
     RECT  151.625 30.24 152.665 30.6 ;
     RECT  152.665 30.24 152.725 30.84 ;
     RECT  152.413 3.312 152.828 3.336 ;
     RECT  152.129 93.504 153.313 93.816 ;
     RECT  152.725 1.728 153.608 1.752 ;
     RECT  152.828 3.312 153.608 4.296 ;
     RECT  150.853 22.752 153.608 23.592 ;
     RECT  152.725 30.144 153.608 30.84 ;
     RECT  152.197 35.952 153.608 39.288 ;
     RECT  151.955 40.512 153.608 40.536 ;
     RECT  152.972 48.816 153.608 48.84 ;
     RECT  148.504 50.832 153.608 51.384 ;
     RECT  151.235 65.664 153.608 65.688 ;
     RECT  148.504 67.824 153.608 67.848 ;
     RECT  148.504 69.024 153.608 70.872 ;
     RECT  153.313 93.312 153.608 93.816 ;
     RECT  153.061 94.992 153.608 95.016 ;
     RECT  153.608 1.728 153.712 95.052 ;
     RECT  153.712 1.728 153.904 95.016 ;
     RECT  153.904 1.728 153.965 1.752 ;
     RECT  153.904 94.992 154.403 95.016 ;
     RECT  153.904 93.312 154.469 93.912 ;
     RECT  153.904 36.768 154.505 39.96 ;
     RECT  153.904 4.272 154.835 4.296 ;
     RECT  153.904 25.68 154.835 25.992 ;
     RECT  154.505 36.816 154.835 39.96 ;
     RECT  154.835 36.816 154.937 39.48 ;
     RECT  154.937 38.832 154.973 39.48 ;
     RECT  154.973 38.832 155.225 39.288 ;
     RECT  154.937 36.816 155.545 37.704 ;
     RECT  155.545 96.336 155.651 96.36 ;
     RECT  154.469 93.744 155.689 93.912 ;
     RECT  155.545 36.768 156.085 37.704 ;
     RECT  155.225 38.832 156.085 38.856 ;
     RECT  154.835 25.968 156.193 25.992 ;
     RECT  156.085 36.768 156.265 38.856 ;
     RECT  155.077 40.56 156.265 40.584 ;
     RECT  153.904 22.752 156.409 23.592 ;
     RECT  156.193 25.968 156.421 26.232 ;
     RECT  156.013 3.36 156.445 3.384 ;
     RECT  156.265 36.768 156.449 40.584 ;
     RECT  156.449 36.768 156.467 39.816 ;
     RECT  156.445 3.36 156.563 4.296 ;
     RECT  153.904 30.144 156.737 30.6 ;
     RECT  156.421 25.92 156.769 26.232 ;
     RECT  156.769 94.992 156.899 95.016 ;
     RECT  156.467 36.912 156.989 39.816 ;
     RECT  155.689 93.504 157.021 93.912 ;
     RECT  153.904 69.024 157.205 70.872 ;
     RECT  156.409 22.224 157.429 23.592 ;
     RECT  156.989 36.912 157.457 39.432 ;
     RECT  156.769 25.68 157.475 26.232 ;
     RECT  157.457 36.912 157.565 39.288 ;
     RECT  157.429 22.224 157.667 23.736 ;
     RECT  157.597 21.072 157.681 21.096 ;
     RECT  157.565 36.912 157.777 39.096 ;
     RECT  157.597 40.464 157.811 40.488 ;
     RECT  157.777 36.48 157.853 39.096 ;
     RECT  157.475 25.968 157.997 26.232 ;
     RECT  157.916 29.424 158.003 29.448 ;
     RECT  157.853 36.48 158.003 38.616 ;
     RECT  157.021 93.504 158.029 94.056 ;
     RECT  154.021 1.152 158.033 1.176 ;
     RECT  158.245 2.832 159.008 2.856 ;
     RECT  156.913 4.512 159.008 4.536 ;
     RECT  157.667 22.224 159.008 22.776 ;
     RECT  157.997 26.064 159.008 26.232 ;
     RECT  156.737 30.432 159.008 30.6 ;
     RECT  158.003 36.864 159.008 38.616 ;
     RECT  153.904 50.832 159.008 51.384 ;
     RECT  153.904 67.824 159.008 67.848 ;
     RECT  157.205 69.024 159.008 70.824 ;
     RECT  158.029 93.504 159.008 95.016 ;
     RECT  159.008 2.148 159.112 95.052 ;
     RECT  159.112 2.418 159.304 95.052 ;
     RECT  159.304 50.832 159.365 50.856 ;
     RECT  159.308 95.136 159.395 95.16 ;
     RECT  159.304 22.224 159.443 22.776 ;
     RECT  159.304 36.912 159.509 38.088 ;
     RECT  159.509 36.912 159.689 37.032 ;
     RECT  159.304 26.064 159.797 26.088 ;
     RECT  159.304 39.984 160.067 40.152 ;
     RECT  159.509 38.064 160.108 38.088 ;
     RECT  159.304 30.432 160.193 30.744 ;
     RECT  159.304 69.504 160.229 70.824 ;
     RECT  160.364 25.68 160.547 25.704 ;
     RECT  159.689 37.008 160.547 37.032 ;
     RECT  159.304 93.84 160.621 94.056 ;
     RECT  160.621 93.744 160.645 94.056 ;
     RECT  160.645 93.744 160.732 95.016 ;
     RECT  159.304 67.824 160.877 67.848 ;
     RECT  161.053 38.928 161.089 38.952 ;
     RECT  160.067 40.128 161.089 40.152 ;
     RECT  160.981 37.152 161.161 37.944 ;
     RECT  161.089 38.928 161.161 40.152 ;
     RECT  159.304 4.272 161.305 4.44 ;
     RECT  160.193 30.72 161.365 30.744 ;
     RECT  160.732 93.744 161.377 94.056 ;
     RECT  161.305 3.936 161.411 4.44 ;
     RECT  161.161 37.152 161.449 40.152 ;
     RECT  161.449 37.152 161.489 40.44 ;
     RECT  161.365 30.24 161.521 30.744 ;
     RECT  160.229 70.272 161.597 70.824 ;
     RECT  161.489 37.152 161.633 37.944 ;
     RECT  161.489 38.928 161.633 40.44 ;
     RECT  161.633 37.152 161.845 37.848 ;
     RECT  161.377 93.456 161.893 94.056 ;
     RECT  161.597 70.272 161.957 70.296 ;
     RECT  161.893 93.456 161.989 95.016 ;
     RECT  161.989 93.072 161.993 95.016 ;
     RECT  161.845 37.056 162.493 37.848 ;
     RECT  161.633 39.024 162.497 40.44 ;
     RECT  162.493 36.816 162.605 37.848 ;
     RECT  162.605 37.152 162.641 37.848 ;
     RECT  161.993 93.072 162.677 94.056 ;
     RECT  161.411 4.416 162.812 4.44 ;
     RECT  162.497 39.024 162.821 39.048 ;
     RECT  162.277 3.36 162.899 3.384 ;
     RECT  162.812 4.416 163.001 4.536 ;
     RECT  162.677 93.456 163.141 94.056 ;
     RECT  163.141 93.456 163.253 95.016 ;
     RECT  163.253 93.456 163.325 94.056 ;
     RECT  162.641 37.584 163.525 37.848 ;
     RECT  163.525 37.584 163.933 38.568 ;
     RECT  159.443 22.752 164.252 22.776 ;
     RECT  163.001 4.512 164.293 4.536 ;
     RECT  164.293 4.416 164.408 4.536 ;
     RECT  164.252 22.176 164.408 22.776 ;
     RECT  161.521 30.048 164.408 30.744 ;
     RECT  163.933 37.584 164.408 38.664 ;
     RECT  162.497 40.416 164.408 40.44 ;
     RECT  163.753 41.616 164.408 41.64 ;
     RECT  163.325 93.792 164.408 94.056 ;
     RECT  164.348 95.184 164.408 95.208 ;
     RECT  164.408 2.148 164.435 95.208 ;
     RECT  164.435 2.148 164.512 95.052 ;
     RECT  164.512 2.418 164.704 94.782 ;
     RECT  164.704 30.048 164.819 30.072 ;
     RECT  164.704 38.736 164.873 39.624 ;
     RECT  164.704 93.792 165.554 94.782 ;
     RECT  165.554 93.792 165.733 94.008 ;
     RECT  165.637 94.992 165.737 95.016 ;
     RECT  164.704 4.416 165.805 4.44 ;
     RECT  165.805 3.696 165.877 4.44 ;
     RECT  164.704 31.344 165.881 31.368 ;
     RECT  165.913 43.92 165.997 43.944 ;
     RECT  165.925 41.52 166.124 41.544 ;
     RECT  165.877 2.832 166.211 4.44 ;
     RECT  166.124 31.248 166.211 31.272 ;
     RECT  164.704 37.584 166.211 37.608 ;
     RECT  164.873 39.6 166.211 39.624 ;
     RECT  166.124 40.704 166.211 41.544 ;
     RECT  165.733 93.072 166.781 94.008 ;
     RECT  166.781 93.792 166.817 94.008 ;
     RECT  166.211 41.52 166.853 41.544 ;
     RECT  166.211 2.832 166.957 3.432 ;
     RECT  166.885 94.992 166.972 95.016 ;
     RECT  166.211 4.416 167.069 4.44 ;
     RECT  166.957 2.688 167.075 3.432 ;
     RECT  159.157 1.152 167.105 1.176 ;
     RECT  167.075 3.408 167.105 3.432 ;
     RECT  166.817 93.792 167.501 93.816 ;
     RECT  168.101 0.192 168.185 0.216 ;
     RECT  168.133 95.76 168.257 95.784 ;
     RECT  169.808 2.148 169.912 95.052 ;
     RECT  169.912 2.418 170.104 94.782 ;
    LAYER M5 ;
     RECT  5.28 0.144 5.304 0.227 ;
     RECT  9.12 0.144 9.144 0.227 ;
     RECT  10.416 0.144 10.44 0.227 ;
     RECT  14.256 0.144 14.28 0.227 ;
     RECT  16.8 0.144 16.824 0.227 ;
     RECT  19.392 0.144 19.416 0.227 ;
     RECT  24.528 0.144 24.552 0.227 ;
     RECT  25.776 0.144 25.8 0.227 ;
     RECT  28.368 0.144 28.392 0.227 ;
     RECT  30.912 0.144 30.936 0.227 ;
     RECT  32.208 0.144 32.232 0.227 ;
     RECT  36.048 0.144 36.072 0.227 ;
     RECT  39.888 0.144 39.912 0.227 ;
     RECT  41.184 0.144 41.208 0.227 ;
     RECT  42.48 0.144 42.504 0.227 ;
     RECT  43.728 0.144 43.752 0.227 ;
     RECT  46.32 0.144 46.344 0.227 ;
     RECT  47.616 0.144 47.64 0.227 ;
     RECT  51.456 0.144 51.48 0.227 ;
     RECT  55.296 0.144 55.32 0.227 ;
     RECT  56.592 0.144 56.616 0.227 ;
     RECT  57.84 0.144 57.864 0.227 ;
     RECT  60.432 0.144 60.456 0.227 ;
     RECT  61.68 0.144 61.704 0.227 ;
     RECT  66.816 0.144 66.84 0.227 ;
     RECT  71.952 0.144 71.976 0.227 ;
     RECT  80.928 0.144 80.952 0.227 ;
     RECT  82.224 0.144 82.248 0.227 ;
     RECT  83.52 0.144 83.544 0.227 ;
     RECT  86.064 0.144 86.088 0.227 ;
     RECT  91.2 0.144 91.224 0.227 ;
     RECT  96.336 0.144 96.36 0.227 ;
     RECT  97.632 0.144 97.656 0.227 ;
     RECT  98.88 0.144 98.904 0.227 ;
     RECT  101.472 0.144 101.496 0.227 ;
     RECT  102.72 0.144 102.744 0.227 ;
     RECT  106.608 0.144 106.632 0.227 ;
     RECT  112.992 0.144 113.016 0.227 ;
     RECT  123.264 0.144 123.288 0.227 ;
     RECT  124.56 0.144 124.584 0.227 ;
     RECT  125.808 0.144 125.832 0.227 ;
     RECT  127.104 0.144 127.128 0.227 ;
     RECT  128.4 0.144 128.424 0.227 ;
     RECT  132.24 0.144 132.264 0.227 ;
     RECT  133.536 0.144 133.56 0.227 ;
     RECT  136.08 0.144 136.104 0.227 ;
     RECT  137.376 0.144 137.4 0.227 ;
     RECT  139.92 0.144 139.944 0.227 ;
     RECT  141.216 0.144 141.24 0.227 ;
     RECT  142.512 0.144 142.536 0.227 ;
     RECT  143.76 0.144 143.784 0.227 ;
     RECT  147.648 0.144 147.672 0.227 ;
     RECT  150.192 0.144 150.216 0.227 ;
     RECT  151.488 0.144 151.512 0.227 ;
     RECT  168.144 0.144 168.168 0.227 ;
     RECT  7.824 0.144 7.848 0.563 ;
     RECT  27.072 0.144 27.096 0.611 ;
     RECT  45.024 0.144 45.048 0.611 ;
     RECT  87.36 0.144 87.384 0.611 ;
     RECT  104.016 0.144 104.04 0.611 ;
     RECT  119.424 0.144 119.448 0.611 ;
     RECT  121.968 0.144 121.992 0.611 ;
     RECT  145.056 0.144 145.08 0.611 ;
     RECT  6.576 0.144 6.6 1.187 ;
     RECT  11.664 0.144 11.688 1.187 ;
     RECT  12.96 0.144 12.984 1.187 ;
     RECT  15.552 0.144 15.576 1.187 ;
     RECT  18.096 0.144 18.12 1.187 ;
     RECT  20.64 0.144 20.664 1.187 ;
     RECT  21.936 0.144 21.96 1.187 ;
     RECT  23.232 0.144 23.256 1.187 ;
     RECT  34.752 0.144 34.776 1.187 ;
     RECT  37.344 0.144 37.368 1.187 ;
     RECT  38.592 0.144 38.616 1.187 ;
     RECT  48.864 0.144 48.888 1.187 ;
     RECT  50.16 0.144 50.184 1.187 ;
     RECT  52.704 0.144 52.728 1.187 ;
     RECT  54 0.144 54.024 1.187 ;
     RECT  59.136 0.144 59.16 1.187 ;
     RECT  62.976 0.144 63 1.187 ;
     RECT  64.272 0.144 64.296 1.187 ;
     RECT  65.568 0.144 65.592 1.187 ;
     RECT  68.112 0.144 68.136 1.187 ;
     RECT  69.408 0.144 69.432 1.187 ;
     RECT  70.656 0.144 70.68 1.187 ;
     RECT  73.248 0.144 73.272 1.187 ;
     RECT  74.544 0.144 74.568 1.187 ;
     RECT  75.792 0.144 75.816 1.187 ;
     RECT  77.088 0.144 77.112 1.187 ;
     RECT  78.384 0.144 78.408 1.187 ;
     RECT  79.632 0.144 79.656 1.187 ;
     RECT  84.768 0.144 84.792 1.187 ;
     RECT  88.656 0.144 88.68 1.187 ;
     RECT  89.904 0.144 89.928 1.187 ;
     RECT  92.496 0.144 92.52 1.187 ;
     RECT  95.04 0.144 95.064 1.187 ;
     RECT  100.176 0.144 100.2 1.187 ;
     RECT  105.312 0.144 105.336 1.187 ;
     RECT  107.856 0.144 107.88 1.187 ;
     RECT  109.152 0.144 109.176 1.187 ;
     RECT  111.696 0.144 111.72 1.187 ;
     RECT  114.288 0.144 114.312 1.187 ;
     RECT  115.584 0.144 115.608 1.187 ;
     RECT  116.832 0.144 116.856 1.187 ;
     RECT  118.128 0.144 118.152 1.187 ;
     RECT  120.672 0.144 120.696 1.187 ;
     RECT  129.696 0.144 129.72 1.187 ;
     RECT  130.944 0.144 130.968 1.187 ;
     RECT  134.784 0.144 134.808 1.187 ;
     RECT  138.672 0.144 138.696 1.187 ;
     RECT  146.352 0.144 146.376 1.187 ;
     RECT  148.896 0.144 148.92 1.187 ;
     RECT  154.032 0.144 154.056 1.187 ;
     RECT  155.328 0.144 155.352 1.187 ;
     RECT  156.624 0.144 156.648 1.187 ;
     RECT  157.872 0.144 157.896 1.187 ;
     RECT  159.168 0.144 159.192 1.187 ;
     RECT  160.464 0.144 160.488 1.187 ;
     RECT  161.712 0.144 161.736 1.187 ;
     RECT  163.008 0.144 163.032 1.187 ;
     RECT  164.304 0.144 164.328 1.187 ;
     RECT  165.6 0.144 165.624 1.187 ;
     RECT  166.848 0.144 166.872 1.187 ;
     RECT  33.504 0.144 33.528 1.763 ;
     RECT  93.744 0.144 93.768 1.763 ;
     RECT  152.736 0.144 152.76 1.763 ;
     RECT  29.616 0.144 29.64 2.137 ;
     RECT  110.448 0.144 110.472 2.137 ;
     RECT  2.4 2.137 2.52 2.151 ;
     RECT  7.8 2.137 7.92 2.151 ;
     RECT  13.2 2.137 13.32 2.151 ;
     RECT  18.6 2.137 18.72 2.151 ;
     RECT  24 2.137 24.12 2.151 ;
     RECT  29.4 2.137 29.64 2.151 ;
     RECT  34.8 2.137 34.92 2.151 ;
     RECT  40.2 2.137 40.32 2.151 ;
     RECT  45.6 2.137 45.72 2.151 ;
     RECT  51 2.137 51.12 2.151 ;
     RECT  56.4 2.137 56.52 2.151 ;
     RECT  61.8 2.137 61.92 2.151 ;
     RECT  67.2 2.137 67.32 2.151 ;
     RECT  72.6 2.137 72.72 2.151 ;
     RECT  78 2.137 78.12 2.151 ;
     RECT  83.4 2.137 83.52 2.151 ;
     RECT  88.8 2.137 88.92 2.151 ;
     RECT  94.2 2.137 94.32 2.151 ;
     RECT  99.6 2.137 99.72 2.151 ;
     RECT  105 2.137 105.12 2.151 ;
     RECT  110.4 2.137 110.52 2.151 ;
     RECT  115.8 2.137 115.92 2.151 ;
     RECT  121.2 2.137 121.32 2.151 ;
     RECT  126.6 2.137 126.72 2.151 ;
     RECT  132 2.137 132.12 2.151 ;
     RECT  137.4 2.137 137.52 2.151 ;
     RECT  142.8 2.137 142.92 2.151 ;
     RECT  148.2 2.137 148.32 2.151 ;
     RECT  153.6 2.137 153.72 2.151 ;
     RECT  159 2.137 159.12 2.151 ;
     RECT  164.4 2.137 164.52 2.151 ;
     RECT  169.8 2.137 169.92 2.151 ;
     RECT  159 2.151 159.312 2.821 ;
     RECT  45.6 2.151 45.912 3.157 ;
     RECT  24 2.151 24.312 3.301 ;
     RECT  153.6 2.151 153.912 3.301 ;
     RECT  126.6 2.151 126.912 3.349 ;
     RECT  147.12 3.349 147.144 3.397 ;
     RECT  167.04 2.677 167.064 3.443 ;
     RECT  45.6 3.157 46.392 3.685 ;
     RECT  165.888 2.821 165.912 3.685 ;
     RECT  165.888 3.685 166.2 3.731 ;
     RECT  22.896 3.349 22.92 3.733 ;
     RECT  24 3.301 24.648 3.733 ;
     RECT  29.4 2.151 29.712 3.733 ;
     RECT  31.488 3.397 31.512 3.733 ;
     RECT  105 2.151 105.312 3.733 ;
     RECT  7.8 2.151 8.112 3.925 ;
     RECT  9.888 3.157 9.912 3.925 ;
     RECT  29.4 3.733 31.512 3.925 ;
     RECT  40.2 2.151 40.512 3.925 ;
     RECT  88.8 2.151 89.112 3.925 ;
     RECT  99.6 2.151 99.912 3.925 ;
     RECT  109.2 3.685 109.224 3.925 ;
     RECT  113.136 3.877 113.16 3.925 ;
     RECT  136.176 3.301 136.2 3.925 ;
     RECT  137.4 2.151 137.712 3.925 ;
     RECT  142.8 2.151 143.112 3.925 ;
     RECT  132 2.151 132.312 4.117 ;
     RECT  58.032 3.157 58.056 4.163 ;
     RECT  122.736 3.301 122.76 4.259 ;
     RECT  18.6 2.151 18.912 4.261 ;
     RECT  20.16 2.821 20.184 4.261 ;
     RECT  22.896 3.733 24.648 4.261 ;
     RECT  53.76 3.349 53.784 4.261 ;
     RECT  94.2 2.151 94.512 4.261 ;
     RECT  105 3.733 105.432 4.261 ;
     RECT  110.4 2.151 110.712 4.261 ;
     RECT  125.28 3.349 125.304 4.261 ;
     RECT  126.6 3.349 127.224 4.261 ;
     RECT  152.88 3.301 153.912 4.261 ;
     RECT  161.376 3.925 161.4 4.261 ;
     RECT  125.28 4.261 127.224 4.307 ;
     RECT  158.256 2.821 159.312 4.405 ;
     RECT  164.4 2.151 164.712 4.405 ;
     RECT  13.2 2.151 13.512 4.501 ;
     RECT  16.032 3.925 16.056 4.501 ;
     RECT  27.264 3.685 27.288 4.501 ;
     RECT  32.832 3.925 32.856 4.501 ;
     RECT  39.552 3.925 41.496 4.501 ;
     RECT  56.4 2.151 56.712 4.501 ;
     RECT  94.2 4.261 94.68 4.501 ;
     RECT  115.8 2.151 116.112 4.501 ;
     RECT  125.76 4.307 127.224 4.501 ;
     RECT  136.176 3.925 138.216 4.501 ;
     RECT  140.976 3.925 141 4.501 ;
     RECT  142.8 3.925 143.592 4.501 ;
     RECT  144.576 3.925 144.6 4.501 ;
     RECT  148.2 2.151 148.512 4.501 ;
     RECT  158.256 4.405 159.432 4.501 ;
     RECT  157.968 4.501 159.432 4.547 ;
     RECT  132 4.117 133.08 4.643 ;
     RECT  34.8 2.151 35.112 4.645 ;
     RECT  36.192 4.261 36.216 4.645 ;
     RECT  68.832 4.213 68.856 4.691 ;
     RECT  86.352 3.397 86.376 4.691 ;
     RECT  78 2.151 78.312 4.693 ;
     RECT  83.4 2.151 83.712 4.789 ;
     RECT  121.2 2.151 121.512 4.837 ;
     RECT  142.032 4.501 144.6 4.837 ;
     RECT  18.6 4.261 20.184 5.029 ;
     RECT  77.088 4.693 78.312 5.029 ;
     RECT  61.8 2.151 62.112 6.613 ;
     RECT  70.944 4.357 70.968 9.011 ;
     RECT  77.088 5.029 78.408 9.011 ;
     RECT  132 4.643 132.312 9.061 ;
     RECT  32.832 4.501 33.672 9.349 ;
     RECT  34.8 4.645 36.216 9.349 ;
     RECT  77.472 9.011 78.408 10.261 ;
     RECT  7.8 3.925 9.912 10.693 ;
     RECT  77.472 10.261 78.6 10.693 ;
     RECT  79.92 3.925 79.944 10.693 ;
     RECT  77.472 10.693 79.944 10.931 ;
     RECT  52.896 4.261 53.784 11.077 ;
     RECT  56.304 4.501 56.712 11.123 ;
     RECT  123.072 4.261 123.096 12.469 ;
     RECT  122.736 12.469 123.096 12.515 ;
     RECT  49.056 4.501 49.08 12.517 ;
     RECT  129.744 3.685 129.768 12.563 ;
     RECT  32.832 9.349 36.216 12.757 ;
     RECT  87.408 4.501 87.432 12.949 ;
     RECT  87.408 12.949 87.576 12.995 ;
     RECT  78 10.931 79.944 13.043 ;
     RECT  82.992 4.789 83.712 13.045 ;
     RECT  84.768 4.501 84.792 13.045 ;
     RECT  121.2 4.837 121.608 13.045 ;
     RECT  122.736 12.515 122.76 13.045 ;
     RECT  134.112 3.925 134.136 13.045 ;
     RECT  52.896 11.077 54.408 13.477 ;
     RECT  38.592 4.501 41.496 13.525 ;
     RECT  129.696 12.901 129.72 13.525 ;
     RECT  51 2.151 51.312 13.621 ;
     RECT  115.104 4.501 116.112 14.099 ;
     RECT  91.776 3.925 91.8 14.101 ;
     RECT  125.76 4.501 127.464 14.101 ;
     RECT  61.68 6.613 62.112 14.147 ;
     RECT  115.488 14.099 116.112 14.149 ;
     RECT  96.48 3.157 96.504 14.245 ;
     RECT  96.48 14.245 96.888 14.291 ;
     RECT  49.008 12.517 49.08 14.341 ;
     RECT  49.008 14.341 49.416 14.387 ;
     RECT  51 13.621 51.432 14.435 ;
     RECT  13.2 4.501 13.944 14.437 ;
     RECT  15.168 4.501 16.056 14.437 ;
     RECT  121.2 13.045 122.76 14.627 ;
     RECT  43.056 3.349 43.08 14.725 ;
     RECT  37.872 13.525 41.496 14.867 ;
     RECT  110.4 4.261 111.624 14.867 ;
     RECT  129.696 13.525 130.2 14.963 ;
     RECT  124.848 14.101 127.464 15.059 ;
     RECT  120 4.261 120.024 15.061 ;
     RECT  121.2 14.627 121.704 15.061 ;
     RECT  99.504 3.925 99.912 15.253 ;
     RECT  100.992 4.837 101.016 15.253 ;
     RECT  102.816 4.501 102.84 15.301 ;
     RECT  110.4 14.867 111.48 15.301 ;
     RECT  117.648 4.501 117.672 15.301 ;
     RECT  82.992 13.045 84.792 15.349 ;
     RECT  98.256 4.501 98.28 15.349 ;
     RECT  99.504 15.253 101.016 15.349 ;
     RECT  106.848 3.349 106.872 15.397 ;
     RECT  106.848 15.397 107.16 15.443 ;
     RECT  82.896 15.349 84.792 15.539 ;
     RECT  118.944 3.925 118.968 15.973 ;
     RECT  120 15.061 121.704 15.973 ;
     RECT  43.056 14.725 43.512 16.019 ;
     RECT  91.776 14.101 91.896 16.019 ;
     RECT  118.944 15.973 121.704 16.019 ;
     RECT  132 9.061 132.6 16.019 ;
     RECT  44.688 3.685 46.392 16.165 ;
     RECT  98.256 15.349 101.016 16.259 ;
     RECT  43.056 16.019 43.08 16.501 ;
     RECT  42.96 16.501 43.08 16.547 ;
     RECT  99.504 16.259 101.016 16.835 ;
     RECT  44.448 16.165 46.392 16.883 ;
     RECT  108.672 3.925 109.224 17.029 ;
     RECT  117.648 15.301 117.96 17.029 ;
     RECT  118.944 16.019 121.512 17.029 ;
     RECT  39.84 14.867 41.496 17.075 ;
     RECT  117.648 17.029 121.512 17.075 ;
     RECT  32.544 12.757 36.216 17.077 ;
     RECT  49.056 14.387 49.416 17.123 ;
     RECT  102.048 15.301 102.84 17.123 ;
     RECT  117.648 17.075 118.728 17.171 ;
     RECT  100.992 16.835 101.016 17.269 ;
     RECT  100.992 17.269 101.448 17.315 ;
     RECT  13.2 14.437 16.056 17.461 ;
     RECT  113.136 3.925 113.256 17.461 ;
     RECT  108.48 17.029 109.224 17.605 ;
     RECT  110.208 15.301 111.48 17.605 ;
     RECT  106.944 15.443 107.16 17.699 ;
     RECT  115.488 14.149 116.232 17.699 ;
     RECT  52.848 13.477 54.408 17.747 ;
     RECT  37.872 14.867 38.712 18.133 ;
     RECT  39.84 17.075 41.208 18.133 ;
     RECT  136.176 4.501 138.696 18.133 ;
     RECT  139.68 4.261 139.704 18.133 ;
     RECT  29.184 3.925 31.512 18.181 ;
     RECT  32.544 17.077 36.744 18.181 ;
     RECT  119.712 17.075 121.512 18.227 ;
     RECT  42.96 16.547 42.984 18.229 ;
     RECT  44.688 16.883 46.392 18.275 ;
     RECT  119.952 18.227 121.512 18.275 ;
     RECT  101.424 17.315 101.448 18.373 ;
     RECT  102.816 17.123 102.84 18.373 ;
     RECT  42.96 18.229 43.704 18.419 ;
     RECT  101.424 18.373 102.84 18.419 ;
     RECT  115.8 17.699 116.232 18.563 ;
     RECT  93.744 4.501 94.68 18.613 ;
     RECT  113.136 17.461 113.976 18.661 ;
     RECT  117.648 17.171 117.672 18.661 ;
     RECT  117.408 18.661 117.672 18.707 ;
     RECT  112.848 18.661 113.976 18.803 ;
     RECT  108.48 17.605 111.48 18.851 ;
     RECT  113.904 18.803 113.976 18.899 ;
     RECT  29.184 18.181 36.744 18.901 ;
     RECT  37.872 18.133 41.208 18.901 ;
     RECT  7.8 10.693 10.248 18.947 ;
     RECT  29.184 18.901 41.208 18.947 ;
     RECT  118.704 17.171 118.728 18.947 ;
     RECT  47.568 4.693 47.592 19.093 ;
     RECT  104.256 4.261 105.432 19.093 ;
     RECT  47.568 19.093 47.688 19.139 ;
     RECT  103.776 19.093 105.432 19.139 ;
     RECT  99.504 16.835 99.912 19.141 ;
     RECT  45.6 18.275 46.392 19.333 ;
     RECT  105 19.139 105.432 19.333 ;
     RECT  136.176 18.133 139.704 19.381 ;
     RECT  13.2 17.461 16.728 19.427 ;
     RECT  108.48 18.851 111.192 19.427 ;
     RECT  135.984 19.381 139.704 19.427 ;
     RECT  96.864 14.291 96.888 19.477 ;
     RECT  96.576 19.477 96.888 19.523 ;
     RECT  52.896 17.747 54.408 19.621 ;
     RECT  98.256 16.259 98.28 19.621 ;
     RECT  97.728 19.621 98.28 19.667 ;
     RECT  112.848 18.803 112.872 19.717 ;
     RECT  52.608 19.621 54.408 19.763 ;
     RECT  112.368 19.717 112.872 19.763 ;
     RECT  45.504 19.333 46.392 19.811 ;
     RECT  49.056 17.123 49.08 19.811 ;
     RECT  134.064 13.045 134.136 19.859 ;
     RECT  18.192 5.029 20.184 19.909 ;
     RECT  45.504 19.811 45.912 19.909 ;
     RECT  108.48 19.427 108.888 19.909 ;
     RECT  117.408 18.707 117.432 19.957 ;
     RECT  108.288 19.909 108.888 20.003 ;
     RECT  87.552 12.995 87.576 20.005 ;
     RECT  84.768 15.539 84.792 20.051 ;
     RECT  86.64 20.005 87.576 20.051 ;
     RECT  93.648 18.613 94.68 20.101 ;
     RECT  91.776 16.019 91.8 20.149 ;
     RECT  93.552 20.101 94.68 20.149 ;
     RECT  90.912 20.149 91.8 20.195 ;
     RECT  125.664 15.059 127.464 20.195 ;
     RECT  99.504 19.141 100.344 20.245 ;
     RECT  101.76 18.419 102.696 20.245 ;
     RECT  99.504 20.245 102.696 20.291 ;
     RECT  82.896 15.539 83.712 20.293 ;
     RECT  115.8 18.563 116.112 20.389 ;
     RECT  15.168 19.427 16.728 20.485 ;
     RECT  82.08 20.293 83.712 20.485 ;
     RECT  14.976 20.485 16.728 20.531 ;
     RECT  39.36 18.947 41.208 20.533 ;
     RECT  42.192 19.477 42.216 20.533 ;
     RECT  78 13.043 78.6 20.533 ;
     RECT  39.36 20.533 42.216 20.579 ;
     RECT  79.92 13.043 79.944 20.579 ;
     RECT  102.672 20.291 102.696 20.579 ;
     RECT  108.288 20.003 108.312 20.579 ;
     RECT  112.368 19.763 112.392 20.579 ;
     RECT  119.952 18.275 120.024 20.579 ;
     RECT  122.736 14.627 122.76 20.579 ;
     RECT  115.8 20.389 116.232 20.821 ;
     RECT  117.408 19.957 117.768 20.821 ;
     RECT  51 14.435 51.312 21.061 ;
     RECT  157.968 4.547 157.992 21.061 ;
     RECT  107.136 17.699 107.16 21.109 ;
     RECT  40.2 20.579 42.216 21.155 ;
     RECT  47.664 19.139 47.688 21.155 ;
     RECT  49.008 20.293 49.032 21.155 ;
     RECT  112.752 21.061 112.872 21.203 ;
     RECT  126.6 20.195 127.464 21.347 ;
     RECT  29.184 18.947 37.896 21.445 ;
     RECT  115.8 20.821 117.768 21.491 ;
     RECT  135.984 19.427 136.008 21.493 ;
     RECT  52.608 19.763 53.304 21.635 ;
     RECT  113.904 18.899 113.928 21.637 ;
     RECT  43.68 18.419 43.704 21.683 ;
     RECT  93.456 20.149 94.68 21.683 ;
     RECT  119.952 20.579 119.976 21.683 ;
     RECT  129.696 14.963 129.72 21.683 ;
     RECT  132 16.019 132.312 21.685 ;
     RECT  134.112 19.859 134.136 21.731 ;
     RECT  78 20.533 78.792 21.781 ;
     RECT  107.136 21.109 107.256 21.781 ;
     RECT  113.904 21.637 114.072 21.829 ;
     RECT  88.8 3.925 89.208 21.971 ;
     RECT  54.384 19.763 54.408 22.021 ;
     RECT  76.944 21.925 76.968 22.067 ;
     RECT  106.464 21.781 107.256 22.067 ;
     RECT  53.28 21.635 53.304 22.163 ;
     RECT  11.808 4.261 11.832 22.165 ;
     RECT  11.664 22.165 11.832 22.211 ;
     RECT  82.08 20.485 84.408 22.211 ;
     RECT  90.912 20.195 90.936 22.211 ;
     RECT  40.2 21.155 41.016 22.213 ;
     RECT  42.144 21.155 42.216 22.213 ;
     RECT  50.88 21.061 51.312 22.213 ;
     RECT  54.384 22.021 54.456 22.213 ;
     RECT  78 21.781 79.032 22.213 ;
     RECT  108.528 21.301 108.552 22.213 ;
     RECT  119.904 21.781 119.928 22.213 ;
     RECT  131.616 21.685 132.312 22.213 ;
     RECT  40.2 22.213 42.216 22.259 ;
     RECT  159 4.547 159.432 22.259 ;
     RECT  119.328 22.213 119.928 22.355 ;
     RECT  131.616 22.213 132.984 22.355 ;
     RECT  54.384 22.213 54.552 22.403 ;
     RECT  78 22.213 79.56 22.403 ;
     RECT  74.688 22.309 74.808 22.451 ;
     RECT  78 22.403 78.792 22.451 ;
     RECT  112.752 21.203 112.776 22.451 ;
     RECT  54.384 22.403 54.408 22.453 ;
     RECT  108.528 22.213 108.84 22.453 ;
     RECT  110.16 19.427 111.192 22.453 ;
     RECT  126.6 21.347 127.128 22.453 ;
     RECT  50.736 22.213 51.312 22.547 ;
     RECT  74.784 22.451 74.808 22.547 ;
     RECT  135.36 21.493 136.008 22.549 ;
     RECT  137.088 19.427 139.704 22.549 ;
     RECT  54.096 22.453 54.408 22.595 ;
     RECT  108.528 22.453 108.888 22.595 ;
     RECT  50.88 22.547 51.312 22.643 ;
     RECT  54.192 22.595 54.408 22.691 ;
     RECT  14.976 20.531 15 22.741 ;
     RECT  16.032 20.531 16.728 22.741 ;
     RECT  82.08 22.211 84.216 22.741 ;
     RECT  96.576 19.523 96.6 22.741 ;
     RECT  100.992 20.291 101.016 22.741 ;
     RECT  110.16 22.453 111.288 22.741 ;
     RECT  113.856 21.829 114.072 22.741 ;
     RECT  115.8 21.491 117.72 22.741 ;
     RECT  86.64 20.051 86.664 22.787 ;
     RECT  126.6 22.453 127.32 22.789 ;
     RECT  54.384 22.691 54.408 22.835 ;
     RECT  131.616 22.355 132.696 22.835 ;
     RECT  40.2 22.259 41.736 23.029 ;
     RECT  52.656 22.741 52.68 23.029 ;
     RECT  135.36 22.549 139.704 23.029 ;
     RECT  140.688 4.501 141 23.029 ;
     RECT  39.984 23.029 41.736 23.075 ;
     RECT  85.488 22.789 85.512 23.123 ;
     RECT  90.624 22.309 90.744 23.123 ;
     RECT  126.6 22.789 127.512 23.123 ;
     RECT  115.632 22.741 117.72 23.125 ;
     RECT  134.208 22.741 134.232 23.125 ;
     RECT  135.36 23.029 141 23.125 ;
     RECT  124.656 23.029 124.68 23.171 ;
     RECT  105 19.333 105.48 23.173 ;
     RECT  39.984 23.075 40.512 23.219 ;
     RECT  90.624 23.123 90.648 23.219 ;
     RECT  41.712 23.075 41.736 23.315 ;
     RECT  132 22.835 132.696 23.315 ;
     RECT  44.736 19.909 45.912 23.317 ;
     RECT  81.504 22.741 84.216 23.317 ;
     RECT  93.456 21.683 94.512 23.317 ;
     RECT  96.576 22.741 96.744 23.317 ;
     RECT  97.728 19.667 97.752 23.317 ;
     RECT  99.504 20.291 99.912 23.317 ;
     RECT  100.992 22.741 101.16 23.317 ;
     RECT  102.144 22.741 102.168 23.317 ;
     RECT  103.776 19.139 103.8 23.317 ;
     RECT  107.232 22.067 107.256 23.317 ;
     RECT  108.528 22.595 108.552 23.317 ;
     RECT  110.16 22.741 111.672 23.317 ;
     RECT  112.944 22.741 114.072 23.317 ;
     RECT  115.632 23.125 117.912 23.317 ;
     RECT  107.232 23.317 108.552 23.363 ;
     RECT  119.904 22.355 119.928 23.411 ;
     RECT  121.104 18.275 121.512 23.411 ;
     RECT  107.232 23.363 107.88 23.555 ;
     RECT  150.336 3.349 150.36 23.557 ;
     RECT  151.632 3.829 151.656 23.557 ;
     RECT  134.208 23.125 141 23.653 ;
     RECT  103.776 23.317 103.992 23.701 ;
     RECT  105 23.173 105.576 23.701 ;
     RECT  148.2 4.501 148.872 23.701 ;
     RECT  156.528 3.349 156.552 23.701 ;
     RECT  157.632 21.061 157.992 23.701 ;
     RECT  42.768 23.365 42.792 23.749 ;
     RECT  43.872 23.317 45.912 23.749 ;
     RECT  93.36 23.317 95.208 23.749 ;
     RECT  96.288 23.317 97.752 23.749 ;
     RECT  98.784 23.317 101.16 23.749 ;
     RECT  102.144 23.317 102.792 23.749 ;
     RECT  103.776 23.701 105.576 23.749 ;
     RECT  109.728 23.317 111.672 23.749 ;
     RECT  42.768 23.749 45.912 23.795 ;
     RECT  112.944 23.317 117.912 23.845 ;
     RECT  17.952 19.909 20.184 23.893 ;
     RECT  21.36 4.261 24.648 23.893 ;
     RECT  42.816 23.795 45.912 23.987 ;
     RECT  96.288 23.749 101.16 24.517 ;
     RECT  102.144 23.749 105.576 24.517 ;
     RECT  107.424 23.555 107.88 24.517 ;
     RECT  109.008 23.749 111.672 24.517 ;
     RECT  121.2 23.411 121.512 24.517 ;
     RECT  14.976 22.741 16.728 24.563 ;
     RECT  133.872 23.653 141 24.757 ;
     RECT  81.504 23.317 84.984 24.803 ;
     RECT  80.496 23.317 80.52 24.853 ;
     RECT  81.504 24.803 82.392 24.853 ;
     RECT  26.304 4.501 27.72 25.045 ;
     RECT  29.184 21.445 38.664 25.045 ;
     RECT  96.288 24.517 111.672 25.093 ;
     RECT  14.976 24.563 16.536 25.139 ;
     RECT  26.304 25.045 38.664 25.237 ;
     RECT  17.952 23.893 24.648 25.715 ;
     RECT  150.336 23.557 151.656 25.715 ;
     RECT  156.528 23.701 157.992 25.715 ;
     RECT  160.416 4.261 161.4 25.715 ;
     RECT  156.528 25.715 156.552 25.909 ;
     RECT  156.432 25.909 156.552 25.955 ;
     RECT  13.2 19.427 13.944 26.101 ;
     RECT  14.976 25.139 15 26.101 ;
     RECT  26.304 25.237 38.76 26.101 ;
     RECT  7.8 18.947 8.952 26.197 ;
     RECT  10.224 18.947 10.248 26.197 ;
     RECT  7.8 26.197 10.248 26.243 ;
     RECT  16.512 25.139 16.536 26.243 ;
     RECT  17.952 25.715 24.504 26.243 ;
     RECT  25.728 26.101 38.76 26.243 ;
     RECT  13.2 26.101 15 26.725 ;
     RECT  146.352 3.397 147.144 26.725 ;
     RECT  11.664 22.211 11.688 26.819 ;
     RECT  20.688 26.243 24.504 27.061 ;
     RECT  17.952 26.243 19.656 27.205 ;
     RECT  20.688 27.061 24.6 27.205 ;
     RECT  133.776 24.757 141 27.301 ;
     RECT  142.032 4.837 145.176 27.301 ;
     RECT  17.952 27.205 24.6 27.445 ;
     RECT  150.336 25.715 150.504 27.635 ;
     RECT  17.088 27.445 24.6 27.683 ;
     RECT  17.952 27.683 24.6 27.731 ;
     RECT  7.8 26.243 9.672 27.779 ;
     RECT  13.2 26.725 15.72 27.877 ;
     RECT  25.728 26.243 27.288 27.877 ;
     RECT  28.56 26.243 38.76 27.877 ;
     RECT  17.952 27.731 19.032 28.451 ;
     RECT  7.8 27.779 8.616 28.547 ;
     RECT  9.648 27.779 9.672 28.547 ;
     RECT  25.728 27.877 38.76 28.597 ;
     RECT  25.728 28.597 38.808 28.691 ;
     RECT  28.56 28.691 38.808 28.739 ;
     RECT  28.752 28.739 38.808 28.787 ;
     RECT  148.2 23.701 149.064 28.885 ;
     RECT  150.336 27.635 150.36 28.885 ;
     RECT  148.2 28.885 150.36 28.931 ;
     RECT  18.096 28.451 19.032 28.979 ;
     RECT  20.016 27.731 24.6 29.027 ;
     RECT  23.232 29.027 24.6 29.221 ;
     RECT  25.728 28.691 27.288 29.221 ;
     RECT  20.016 29.027 22.056 29.459 ;
     RECT  23.232 29.221 27.288 29.651 ;
     RECT  18.096 28.979 18.912 29.699 ;
     RECT  23.232 29.651 24.6 29.747 ;
     RECT  18.6 29.699 18.912 30.037 ;
     RECT  20.016 29.459 20.76 30.037 ;
     RECT  22.032 29.459 22.056 30.037 ;
     RECT  164.304 4.405 164.712 30.037 ;
     RECT  146.352 26.725 147.192 30.133 ;
     RECT  148.2 28.931 149.832 30.133 ;
     RECT  152.88 4.261 154.824 30.133 ;
     RECT  133.776 27.301 145.176 30.179 ;
     RECT  152.736 30.133 154.824 30.181 ;
     RECT  162.864 3.349 162.888 30.181 ;
     RECT  162.672 30.181 162.888 30.227 ;
     RECT  151.632 25.715 151.656 30.229 ;
     RECT  152.736 30.181 155.208 30.229 ;
     RECT  160.512 25.715 161.4 30.229 ;
     RECT  162.672 30.227 162.696 30.229 ;
     RECT  11.712 28.693 11.736 30.275 ;
     RECT  151.632 30.229 155.208 30.275 ;
     RECT  160.512 30.229 162.696 30.275 ;
     RECT  13.104 27.877 15.72 30.323 ;
     RECT  151.92 30.275 155.208 30.467 ;
     RECT  146.352 30.133 149.832 30.709 ;
     RECT  151.92 30.467 154.824 30.851 ;
     RECT  13.104 30.323 14.904 30.899 ;
     RECT  14.88 30.899 14.904 31.139 ;
     RECT  22.032 30.037 22.776 31.237 ;
     RECT  24 29.747 24.6 31.237 ;
     RECT  25.728 29.651 27.288 31.285 ;
     RECT  28.752 28.787 38.76 31.285 ;
     RECT  146.304 30.709 149.832 31.379 ;
     RECT  164.304 30.037 164.808 31.379 ;
     RECT  134.784 30.179 145.176 31.811 ;
     RECT  146.304 31.379 148.632 31.909 ;
     RECT  146.16 31.909 148.632 32.005 ;
     RECT  133.776 30.179 133.8 32.245 ;
     RECT  134.784 31.811 145.032 32.245 ;
     RECT  22.032 31.237 24.6 32.339 ;
     RECT  133.776 32.245 145.032 32.435 ;
     RECT  25.728 31.285 27.336 32.531 ;
     RECT  28.656 31.285 38.76 33.013 ;
     RECT  26.112 32.531 27.336 33.253 ;
     RECT  28.56 33.013 38.76 33.347 ;
     RECT  151.92 30.851 151.944 33.541 ;
     RECT  134.784 32.435 145.032 33.971 ;
     RECT  26.112 33.253 27.384 34.595 ;
     RECT  146.016 32.005 148.632 34.931 ;
     RECT  134.784 33.971 141.72 35.269 ;
     RECT  142.704 33.971 145.032 35.269 ;
     RECT  26.112 34.595 27.336 35.317 ;
     RECT  149.808 31.379 149.832 35.557 ;
     RECT  149.712 35.557 149.832 35.603 ;
     RECT  134.784 35.269 145.032 35.891 ;
     RECT  151.2 33.541 151.944 35.941 ;
     RECT  152.976 30.851 154.824 35.941 ;
     RECT  28.56 33.347 38.664 35.987 ;
     RECT  146.016 34.931 147.192 35.987 ;
     RECT  146.16 35.987 147.192 36.035 ;
     RECT  148.2 34.931 148.632 36.229 ;
     RECT  18.6 30.037 20.76 36.469 ;
     RECT  22.176 32.339 24.6 36.469 ;
     RECT  157.968 25.715 157.992 36.515 ;
     RECT  148.08 36.229 148.632 36.613 ;
     RECT  149.712 35.603 149.736 36.613 ;
     RECT  28.752 35.987 38.664 36.805 ;
     RECT  148.08 36.613 149.736 36.899 ;
     RECT  151.2 35.941 154.824 36.947 ;
     RECT  28.752 36.805 38.808 36.995 ;
     RECT  159 22.259 159.312 36.997 ;
     RECT  160.512 30.275 160.536 36.997 ;
     RECT  159 36.997 160.536 37.043 ;
     RECT  18.6 36.469 24.6 37.091 ;
     RECT  25.584 35.317 27.336 37.091 ;
     RECT  161.856 30.275 162.696 37.091 ;
     RECT  28.752 36.995 38.664 37.093 ;
     RECT  28.608 37.093 38.664 37.283 ;
     RECT  162.672 37.091 162.696 37.573 ;
     RECT  164.304 31.379 164.712 37.573 ;
     RECT  162.672 37.573 164.808 37.619 ;
     RECT  166.176 3.731 166.2 37.619 ;
     RECT  18.6 37.091 20.04 37.667 ;
     RECT  133.776 32.435 133.8 37.957 ;
     RECT  134.784 35.891 141.624 37.957 ;
     RECT  151.2 36.947 154.488 38.149 ;
     RECT  133.776 37.957 141.624 38.243 ;
     RECT  156.432 25.955 156.456 38.243 ;
     RECT  134.784 38.243 141.624 38.437 ;
     RECT  142.608 35.891 145.032 38.437 ;
     RECT  26.16 37.091 27.336 38.533 ;
     RECT  28.752 37.283 38.664 38.533 ;
     RECT  134.784 38.437 145.032 38.723 ;
     RECT  161.328 37.573 161.352 38.819 ;
     RECT  20.016 37.667 20.04 38.963 ;
     RECT  149.712 36.899 149.736 39.301 ;
     RECT  149.616 39.301 149.736 39.347 ;
     RECT  23.664 37.091 24.6 39.395 ;
     RECT  146.16 36.035 147.048 39.395 ;
     RECT  21.696 37.091 22.632 39.491 ;
     RECT  133.776 38.243 133.8 39.635 ;
     RECT  163.536 37.619 164.808 39.635 ;
     RECT  151.2 38.149 154.824 39.971 ;
     RECT  134.784 38.723 141.624 40.019 ;
     RECT  159 37.043 160.056 40.163 ;
     RECT  142.608 38.723 145.032 40.165 ;
     RECT  142.608 40.165 145.176 40.405 ;
     RECT  161.712 39.301 161.736 40.451 ;
     RECT  163.536 39.635 164.712 40.451 ;
     RECT  149.616 39.347 149.64 40.499 ;
     RECT  157.776 37.477 157.8 40.499 ;
     RECT  151.2 39.971 153.912 40.547 ;
     RECT  24 39.395 24.6 40.595 ;
     RECT  142.608 40.405 145.416 40.595 ;
     RECT  156.384 39.109 156.408 40.595 ;
     RECT  140.64 40.019 141.624 40.693 ;
     RECT  142.608 40.595 143.112 40.693 ;
     RECT  22.608 39.491 22.632 40.835 ;
     RECT  26.16 38.533 38.664 40.835 ;
     RECT  148.08 36.899 148.512 40.835 ;
     RECT  151.2 40.547 151.944 40.835 ;
     RECT  134.784 40.019 139.656 40.981 ;
     RECT  140.64 40.693 143.112 40.981 ;
     RECT  24 40.595 24.504 41.027 ;
     RECT  134.784 40.981 143.112 41.173 ;
     RECT  28.032 40.835 38.664 41.459 ;
     RECT  133.92 41.173 143.112 41.509 ;
     RECT  166.176 39.589 166.2 41.509 ;
     RECT  133.776 41.509 143.112 41.555 ;
     RECT  165.936 41.509 166.2 41.555 ;
     RECT  163.968 40.451 164.712 41.651 ;
     RECT  147.024 39.395 147.048 41.749 ;
     RECT  146.88 41.749 147.048 41.795 ;
     RECT  28.896 41.459 38.664 42.083 ;
     RECT  26.16 40.835 26.856 42.515 ;
     RECT  134.784 41.555 143.112 42.755 ;
     RECT  140.64 42.755 143.112 42.803 ;
     RECT  28.896 42.083 38.568 43.331 ;
     RECT  134.784 42.755 139.656 43.331 ;
     RECT  134.784 43.331 139.32 43.379 ;
     RECT  140.976 42.803 141.624 43.379 ;
     RECT  134.832 43.379 139.32 43.475 ;
     RECT  26.16 42.515 26.808 43.573 ;
     RECT  134.832 43.475 135.528 43.955 ;
     RECT  165.936 41.555 165.96 43.955 ;
     RECT  28.896 43.331 38.424 44.003 ;
     RECT  135.072 43.955 135.528 44.051 ;
     RECT  144.672 40.595 145.416 44.245 ;
     RECT  26.16 43.573 27 44.483 ;
     RECT  146.88 41.795 146.904 44.483 ;
     RECT  26.352 44.483 27 44.627 ;
     RECT  26.352 44.627 26.808 45.059 ;
     RECT  38.4 44.003 38.424 45.059 ;
     RECT  135.072 44.051 135.432 45.059 ;
     RECT  141.6 43.379 141.624 45.059 ;
     RECT  28.896 44.003 37.416 45.155 ;
     RECT  135.408 45.059 135.432 45.301 ;
     RECT  136.512 43.475 139.32 45.301 ;
     RECT  28.896 45.155 36.84 45.587 ;
     RECT  32.016 45.587 36.84 45.635 ;
     RECT  135.408 45.301 139.32 45.635 ;
     RECT  133.776 41.555 133.8 45.829 ;
     RECT  32.496 45.635 36.84 46.165 ;
     RECT  144.432 44.245 145.416 46.211 ;
     RECT  26.784 45.059 26.808 46.259 ;
     RECT  142.704 42.803 143.112 46.259 ;
     RECT  32.496 46.165 37.416 46.837 ;
     RECT  38.448 45.781 38.472 46.837 ;
     RECT  28.896 45.587 30.408 47.125 ;
     RECT  32.496 46.837 38.472 47.939 ;
     RECT  32.496 47.939 33.096 48.949 ;
     RECT  34.08 47.939 38.472 48.949 ;
     RECT  32.496 48.949 38.472 49.045 ;
     RECT  32.496 49.045 38.52 49.813 ;
     RECT  28.896 47.125 30.552 50.195 ;
     RECT  136.08 45.635 139.32 50.195 ;
     RECT  32.496 49.813 38.568 50.197 ;
     RECT  133.776 45.829 133.896 50.821 ;
     RECT  133.776 50.821 134.232 51.349 ;
     RECT  136.08 50.195 137.832 51.349 ;
     RECT  138.864 50.195 139.32 51.349 ;
     RECT  136.08 51.349 139.32 51.491 ;
     RECT  13.104 30.899 13.656 53.075 ;
     RECT  138.864 51.491 139.32 53.173 ;
     RECT  13.104 53.075 13.608 54.131 ;
     RECT  136.08 51.491 137.712 58.739 ;
     RECT  32.496 50.197 38.664 58.787 ;
     RECT  32.736 58.787 38.664 59.029 ;
     RECT  32.736 59.029 38.76 59.219 ;
     RECT  138.864 53.173 139.416 61.285 ;
     RECT  32.736 59.219 38.664 62.725 ;
     RECT  24 41.027 24.408 64.357 ;
     RECT  153.024 40.547 153.912 65.699 ;
     RECT  32.736 62.725 38.76 66.997 ;
     RECT  52.608 23.029 52.68 67.141 ;
     RECT  52.512 67.141 52.68 67.187 ;
     RECT  43.872 23.987 45.912 67.237 ;
     RECT  47.184 22.885 47.208 67.237 ;
     RECT  48.336 22.741 48.36 67.237 ;
     RECT  43.584 67.237 45.912 67.283 ;
     RECT  47.184 67.237 48.36 67.283 ;
     RECT  49.536 23.317 49.56 67.283 ;
     RECT  96.288 25.093 111.768 67.283 ;
     RECT  74.64 23.509 74.664 67.571 ;
     RECT  45.168 67.283 45.912 67.811 ;
     RECT  52.512 67.187 52.632 67.811 ;
     RECT  80.496 24.853 82.392 67.811 ;
     RECT  32.736 66.997 38.808 67.859 ;
     RECT  92.592 23.749 95.208 67.859 ;
     RECT  136.08 58.739 136.104 68.051 ;
     RECT  47.184 67.283 48.168 68.101 ;
     RECT  46.992 68.101 48.168 68.147 ;
     RECT  32.832 67.859 38.808 68.291 ;
     RECT  112.944 23.845 118.248 68.963 ;
     RECT  78 22.451 78.504 69.011 ;
     RECT  83.4 24.803 84.984 69.011 ;
     RECT  80.496 67.811 80.52 69.251 ;
     RECT  78 69.011 78.312 69.253 ;
     RECT  32.832 68.291 38.712 69.491 ;
     RECT  81.504 67.811 82.392 69.539 ;
     RECT  87.792 23.029 87.816 69.587 ;
     RECT  32.832 69.491 38.616 69.779 ;
     RECT  52.512 67.811 52.536 69.829 ;
     RECT  34.8 69.779 38.616 69.875 ;
     RECT  52.512 69.829 52.632 69.875 ;
     RECT  52.608 69.875 52.632 70.163 ;
     RECT  54.528 70.117 54.552 70.261 ;
     RECT  54.528 70.261 54.648 70.307 ;
     RECT  54.624 70.307 54.648 70.403 ;
     RECT  121.2 24.517 121.992 70.693 ;
     RECT  32.832 69.779 33.576 70.739 ;
     RECT  32.976 70.739 33.576 70.883 ;
     RECT  133.776 51.349 134.28 70.883 ;
     RECT  133.824 70.883 134.28 70.931 ;
     RECT  133.824 70.931 133.896 71.123 ;
     RECT  34.8 69.875 38.424 71.221 ;
     RECT  121.2 70.693 122.088 71.267 ;
     RECT  32.976 70.883 33 71.459 ;
     RECT  45.6 67.811 45.912 71.797 ;
     RECT  138.768 61.285 139.416 72.851 ;
     RECT  133.824 71.123 133.848 73.859 ;
     RECT  138.768 72.851 138.792 73.907 ;
     RECT  40.2 23.219 40.512 76.453 ;
     RECT  23.616 64.357 24.408 76.499 ;
     RECT  56.4 11.123 56.712 77.893 ;
     RECT  43.584 67.283 43.608 79.283 ;
     RECT  34.32 71.221 38.424 83.363 ;
     RECT  56.4 77.893 56.808 84.229 ;
     RECT  46.992 68.147 47.016 84.419 ;
     RECT  56.4 84.229 56.904 85.477 ;
     RECT  60.192 83.125 60.216 85.813 ;
     RECT  67.2 2.151 67.512 86.581 ;
     RECT  48.144 68.147 48.168 86.675 ;
     RECT  34.8 83.363 38.424 87.443 ;
     RECT  34.8 87.443 38.28 87.587 ;
     RECT  42.768 87.541 42.792 87.683 ;
     RECT  49.824 87.925 49.944 88.067 ;
     RECT  34.8 87.587 38.136 88.259 ;
     RECT  39.408 76.453 40.512 88.309 ;
     RECT  45.504 71.797 45.912 88.309 ;
     RECT  51 22.643 51.312 88.309 ;
     RECT  39.408 88.309 41.064 88.499 ;
     RECT  59.424 85.813 60.216 88.643 ;
     RECT  34.8 88.259 37.992 88.787 ;
     RECT  56.16 85.477 56.904 88.885 ;
     RECT  61.8 14.147 62.112 88.885 ;
     RECT  71.136 87.733 71.16 88.885 ;
     RECT  72.6 2.151 72.912 88.885 ;
     RECT  66.48 86.581 67.512 89.171 ;
     RECT  71.136 88.885 72.912 89.411 ;
     RECT  67.2 89.171 67.512 89.461 ;
     RECT  77.136 69.253 78.312 89.461 ;
     RECT  50.88 88.309 51.312 89.555 ;
     RECT  51 89.555 51.312 89.845 ;
     RECT  40.2 88.499 41.064 89.893 ;
     RECT  56.16 88.885 56.952 90.565 ;
     RECT  29.4 50.195 30.552 90.659 ;
     RECT  71.856 89.411 72.912 90.659 ;
     RECT  45.504 88.309 46.584 90.851 ;
     RECT  74.112 89.461 74.136 90.947 ;
     RECT  53.424 71.365 53.448 91.091 ;
     RECT  13.2 54.131 13.512 91.093 ;
     RECT  7.8 28.547 8.112 91.141 ;
     RECT  55.248 90.565 56.952 91.187 ;
     RECT  59.424 88.643 59.448 91.189 ;
     RECT  112.944 68.963 116.376 91.235 ;
     RECT  59.232 91.189 59.448 91.331 ;
     RECT  76.896 89.461 78.312 91.429 ;
     RECT  43.344 89.461 43.368 91.475 ;
     RECT  61.8 88.885 62.28 91.525 ;
     RECT  34.8 88.787 37.416 91.619 ;
     RECT  24 76.499 24.408 91.717 ;
     RECT  40.2 89.893 41.4 91.717 ;
     RECT  70.368 89.845 70.392 91.717 ;
     RECT  69.744 91.717 70.392 91.763 ;
     RECT  7.68 91.141 8.112 91.811 ;
     RECT  34.8 91.619 37.032 91.811 ;
     RECT  94.2 67.859 95.208 91.811 ;
     RECT  97.68 67.283 111.768 91.811 ;
     RECT  59.664 91.573 60.408 91.907 ;
     RECT  45.6 90.851 46.584 92.099 ;
     RECT  12.672 91.093 13.512 92.243 ;
     RECT  23.376 91.717 24.408 92.293 ;
     RECT  29.4 90.659 30.264 92.293 ;
     RECT  40.2 91.717 41.592 92.387 ;
     RECT  85.92 71.077 85.944 92.387 ;
     RECT  97.68 91.811 97.704 92.387 ;
     RECT  98.784 91.811 105.312 92.387 ;
     RECT  106.608 91.811 111.768 92.387 ;
     RECT  117.888 68.963 118.248 92.387 ;
     RECT  120.096 23.701 120.12 92.387 ;
     RECT  11.664 91.621 11.688 92.435 ;
     RECT  112.944 91.235 116.112 92.435 ;
     RECT  82.368 69.539 82.392 92.437 ;
     RECT  59.664 91.907 59.832 92.483 ;
     RECT  76.896 91.429 79.272 92.483 ;
     RECT  34.8 91.811 36.408 92.579 ;
     RECT  49.824 88.067 49.848 92.675 ;
     RECT  76.896 92.483 78.696 92.675 ;
     RECT  40.2 92.387 41.4 92.677 ;
     RECT  7.8 91.811 8.112 92.725 ;
     RECT  27.648 91.141 27.672 92.819 ;
     RECT  45.6 92.099 45.912 92.869 ;
     RECT  15.936 92.389 15.96 92.917 ;
     RECT  29.28 92.293 30.264 92.917 ;
     RECT  19.968 91.093 19.992 92.963 ;
     RECT  39.312 92.677 41.4 92.963 ;
     RECT  56.16 91.187 56.952 92.963 ;
     RECT  98.784 92.387 99.912 92.963 ;
     RECT  101.136 92.387 102.168 92.963 ;
     RECT  103.968 92.387 105.312 92.963 ;
     RECT  106.608 92.387 107.448 92.963 ;
     RECT  109.008 92.387 111.672 92.963 ;
     RECT  113.472 92.435 116.112 92.963 ;
     RECT  23.376 92.293 25.08 93.011 ;
     RECT  101.136 92.963 101.16 93.011 ;
     RECT  121.2 71.267 121.992 93.011 ;
     RECT  69.744 91.763 69.768 93.157 ;
     RECT  69.264 93.157 69.768 93.203 ;
     RECT  77.424 92.675 78.696 93.203 ;
     RECT  142.8 46.259 143.112 93.205 ;
     RECT  91.104 92.293 91.128 93.251 ;
     RECT  72.144 90.659 72.912 93.347 ;
     RECT  23.904 93.011 25.08 93.395 ;
     RECT  28.656 92.917 30.264 93.443 ;
     RECT  67.2 89.461 67.8 93.443 ;
     RECT  117.936 92.387 117.96 93.443 ;
     RECT  113.472 92.963 113.496 93.445 ;
     RECT  121.2 93.011 121.512 93.445 ;
     RECT  74.256 90.949 74.28 93.491 ;
     RECT  7.8 92.725 9.096 93.539 ;
     RECT  15.936 92.917 16.632 93.539 ;
     RECT  39.312 92.963 41.016 93.539 ;
     RECT  51 89.845 51.912 93.539 ;
     RECT  59.664 92.483 59.688 93.539 ;
     RECT  64.944 90.037 64.968 93.539 ;
     RECT  69.264 93.203 69.288 93.539 ;
     RECT  78 93.203 78.696 93.539 ;
     RECT  81.456 92.437 82.392 93.539 ;
     RECT  151.2 40.835 151.224 93.539 ;
     RECT  113.424 93.445 113.496 93.587 ;
     RECT  110.4 92.963 110.808 93.635 ;
     RECT  28.656 93.443 29.712 93.731 ;
     RECT  45.024 92.869 45.912 93.731 ;
     RECT  145.872 92.293 145.896 93.731 ;
     RECT  34.8 92.579 35.928 93.779 ;
     RECT  54.048 92.101 54.072 93.779 ;
     RECT  61.8 91.525 62.664 93.779 ;
     RECT  113.424 93.587 113.448 93.779 ;
     RECT  147.168 93.301 147.192 93.779 ;
     RECT  137.4 58.739 137.712 93.781 ;
     RECT  58.176 83.749 58.2 93.923 ;
     RECT  47.424 92.917 47.448 94.019 ;
     RECT  30.816 93.493 30.84 94.067 ;
     RECT  120.24 93.445 121.512 94.115 ;
     RECT  149.856 93.445 149.88 94.115 ;
     RECT  23.904 93.395 24.312 94.163 ;
     RECT  39.312 93.539 40.512 94.163 ;
     RECT  6 92.677 6.024 94.259 ;
     RECT  16.608 93.539 16.632 94.259 ;
     RECT  137.28 93.781 137.712 94.307 ;
     RECT  7.8 93.539 8.112 94.981 ;
     RECT  13.2 92.243 13.512 94.981 ;
     RECT  18.6 37.667 18.912 94.981 ;
     RECT  29.4 93.731 29.712 94.981 ;
     RECT  34.8 93.779 35.112 94.981 ;
     RECT  45.6 93.731 45.912 94.981 ;
     RECT  51 93.539 51.312 94.981 ;
     RECT  61.8 93.779 62.112 94.981 ;
     RECT  67.2 93.443 67.512 94.981 ;
     RECT  72.6 93.347 72.912 94.981 ;
     RECT  82.368 93.539 82.392 94.981 ;
     RECT  83.4 69.011 83.712 94.981 ;
     RECT  88.8 21.971 89.112 94.981 ;
     RECT  94.2 91.811 94.512 94.981 ;
     RECT  99.6 92.963 99.912 94.981 ;
     RECT  105 92.963 105.312 94.981 ;
     RECT  115.8 92.963 116.112 94.981 ;
     RECT  120.528 94.115 121.512 94.981 ;
     RECT  132 23.315 132.312 94.981 ;
     RECT  137.4 94.307 137.712 94.981 ;
     RECT  142.464 93.205 143.112 94.981 ;
     RECT  148.2 40.835 148.512 94.981 ;
     RECT  153.6 65.699 153.912 94.981 ;
     RECT  159 40.163 159.312 94.981 ;
     RECT  164.4 41.651 164.712 94.981 ;
     RECT  2.4 2.151 2.712 95.049 ;
     RECT  7.8 94.981 9.048 95.049 ;
     RECT  24 94.163 24.312 95.049 ;
     RECT  40.2 94.163 40.512 95.049 ;
     RECT  56.4 92.963 56.712 95.049 ;
     RECT  78 93.539 78.312 95.049 ;
     RECT  94.2 94.981 95.496 95.049 ;
     RECT  110.4 93.635 110.712 95.049 ;
     RECT  126.6 23.123 126.912 95.049 ;
     RECT  148.2 94.981 149.4 95.049 ;
     RECT  164.4 94.981 165.672 95.049 ;
     RECT  169.8 2.151 170.112 95.049 ;
     RECT  2.4 95.049 2.52 95.063 ;
     RECT  7.8 95.049 7.92 95.063 ;
     RECT  12.768 94.981 14.04 95.063 ;
     RECT  17.76 94.981 19.08 95.063 ;
     RECT  24 95.049 24.12 95.063 ;
     RECT  29.04 94.981 30.312 95.063 ;
     RECT  34.08 94.981 35.352 95.063 ;
     RECT  40.2 95.049 40.344 95.063 ;
     RECT  45.36 94.981 46.632 95.063 ;
     RECT  50.352 94.981 51.624 95.063 ;
     RECT  56.4 95.049 56.664 95.063 ;
     RECT  61.632 94.981 62.904 95.063 ;
     RECT  67.2 94.981 67.944 95.063 ;
     RECT  71.664 94.981 72.912 95.063 ;
     RECT  78 95.049 78.12 95.063 ;
     RECT  81.696 94.981 84.216 95.063 ;
     RECT  87.936 94.981 89.208 95.063 ;
     RECT  94.2 95.049 94.32 95.063 ;
     RECT  99.216 94.981 100.488 95.063 ;
     RECT  104.256 94.981 105.528 95.063 ;
     RECT  110.4 95.049 110.52 95.063 ;
     RECT  115.536 94.981 116.808 95.063 ;
     RECT  120.528 94.981 121.8 95.063 ;
     RECT  126.6 95.049 126.84 95.063 ;
     RECT  131.808 94.981 133.08 95.063 ;
     RECT  137.4 94.981 138.12 95.063 ;
     RECT  141.84 94.981 143.112 95.063 ;
     RECT  148.2 95.049 148.32 95.063 ;
     RECT  153.12 94.981 154.392 95.063 ;
     RECT  158.112 94.981 159.312 95.063 ;
     RECT  164.4 95.049 164.52 95.063 ;
     RECT  169.8 95.049 169.92 95.063 ;
     RECT  81.696 95.063 82.968 96.995 ;
     RECT  5.232 94.981 5.256 97.04 ;
     RECT  6.48 94.981 6.504 97.04 ;
     RECT  7.776 95.173 7.8 97.04 ;
     RECT  9.024 95.049 9.048 97.04 ;
     RECT  10.272 96.325 10.296 97.04 ;
     RECT  11.52 94.981 11.544 97.04 ;
     RECT  12.768 95.063 12.792 97.04 ;
     RECT  14.016 95.063 14.04 97.04 ;
     RECT  15.264 94.981 15.288 97.04 ;
     RECT  16.512 94.981 16.536 97.04 ;
     RECT  17.76 95.063 17.784 97.04 ;
     RECT  19.056 95.063 19.08 97.04 ;
     RECT  20.304 94.981 20.328 97.04 ;
     RECT  21.552 94.981 21.576 97.04 ;
     RECT  22.8 94.981 22.824 97.04 ;
     RECT  24.048 95.063 24.072 97.04 ;
     RECT  25.296 94.981 25.32 97.04 ;
     RECT  26.544 94.981 26.568 97.04 ;
     RECT  27.792 94.981 27.816 97.04 ;
     RECT  29.04 95.063 29.064 97.04 ;
     RECT  30.288 95.063 30.312 97.04 ;
     RECT  31.584 94.981 31.608 97.04 ;
     RECT  32.832 94.981 32.856 97.04 ;
     RECT  34.08 95.063 34.104 97.04 ;
     RECT  35.328 95.063 35.352 97.04 ;
     RECT  36.576 94.981 36.6 97.04 ;
     RECT  37.824 94.981 37.848 97.04 ;
     RECT  39.072 94.981 39.096 97.04 ;
     RECT  40.32 95.063 40.344 97.04 ;
     RECT  41.568 94.981 41.592 97.04 ;
     RECT  42.864 94.981 42.888 97.04 ;
     RECT  44.112 94.981 44.136 97.04 ;
     RECT  45.36 95.063 45.384 97.04 ;
     RECT  46.608 95.063 46.632 97.04 ;
     RECT  47.856 95.173 47.88 97.04 ;
     RECT  49.104 94.981 49.128 97.04 ;
     RECT  50.352 95.063 50.376 97.04 ;
     RECT  51.6 95.063 51.624 97.04 ;
     RECT  52.848 94.981 52.872 97.04 ;
     RECT  54.096 94.981 54.12 97.04 ;
     RECT  55.392 94.981 55.416 97.04 ;
     RECT  56.64 95.063 56.664 97.04 ;
     RECT  57.888 94.981 57.912 97.04 ;
     RECT  59.136 94.981 59.16 97.04 ;
     RECT  60.384 95.173 60.408 97.04 ;
     RECT  61.632 95.063 61.656 97.04 ;
     RECT  62.88 95.063 62.904 97.04 ;
     RECT  64.128 94.981 64.152 97.04 ;
     RECT  65.376 94.981 65.4 97.04 ;
     RECT  66.672 95.173 66.696 97.04 ;
     RECT  67.92 95.063 67.944 97.04 ;
     RECT  69.168 94.981 69.192 97.04 ;
     RECT  70.416 94.981 70.44 97.04 ;
     RECT  71.664 95.063 71.688 97.04 ;
     RECT  72.912 95.173 72.936 97.04 ;
     RECT  74.16 94.981 74.184 97.04 ;
     RECT  75.408 94.981 75.432 97.04 ;
     RECT  76.656 94.981 76.68 97.04 ;
     RECT  77.952 95.173 77.976 97.04 ;
     RECT  79.2 95.173 79.224 97.04 ;
     RECT  80.448 94.981 80.472 97.04 ;
     RECT  81.696 96.995 81.72 97.04 ;
     RECT  82.944 96.995 82.968 97.04 ;
     RECT  84.192 95.063 84.216 97.04 ;
     RECT  85.44 94.981 85.464 97.04 ;
     RECT  86.688 96.325 86.712 97.04 ;
     RECT  87.936 95.063 87.96 97.04 ;
     RECT  89.184 95.063 89.208 97.04 ;
     RECT  90.48 94.981 90.504 97.04 ;
     RECT  91.728 95.173 91.752 97.04 ;
     RECT  92.976 94.981 93 97.04 ;
     RECT  94.224 95.063 94.248 97.04 ;
     RECT  95.472 95.049 95.496 97.04 ;
     RECT  96.72 94.981 96.744 97.04 ;
     RECT  97.968 94.981 97.992 97.04 ;
     RECT  99.216 95.063 99.24 97.04 ;
     RECT  100.464 95.063 100.488 97.04 ;
     RECT  101.76 94.981 101.784 97.04 ;
     RECT  103.008 94.981 103.032 97.04 ;
     RECT  104.256 95.063 104.28 97.04 ;
     RECT  105.504 95.063 105.528 97.04 ;
     RECT  106.752 94.981 106.776 97.04 ;
     RECT  108 94.981 108.024 97.04 ;
     RECT  109.248 94.981 109.272 97.04 ;
     RECT  110.496 95.063 110.52 97.04 ;
     RECT  111.744 96.325 111.768 97.04 ;
     RECT  113.04 94.981 113.064 97.04 ;
     RECT  114.288 94.981 114.312 97.04 ;
     RECT  115.536 95.063 115.56 97.04 ;
     RECT  116.784 95.063 116.808 97.04 ;
     RECT  118.032 96.325 118.056 97.04 ;
     RECT  119.28 94.981 119.304 97.04 ;
     RECT  120.528 95.063 120.552 97.04 ;
     RECT  121.776 95.063 121.8 97.04 ;
     RECT  123.024 94.981 123.048 97.04 ;
     RECT  124.272 94.981 124.296 97.04 ;
     RECT  125.568 94.981 125.592 97.04 ;
     RECT  126.816 95.063 126.84 97.04 ;
     RECT  128.064 94.981 128.088 97.04 ;
     RECT  129.312 94.981 129.336 97.04 ;
     RECT  130.56 94.981 130.584 97.04 ;
     RECT  131.808 95.063 131.832 97.04 ;
     RECT  133.056 95.063 133.08 97.04 ;
     RECT  134.304 94.981 134.328 97.04 ;
     RECT  135.552 94.981 135.576 97.04 ;
     RECT  136.848 96.325 136.872 97.04 ;
     RECT  138.096 95.063 138.12 97.04 ;
     RECT  139.344 94.981 139.368 97.04 ;
     RECT  140.592 94.981 140.616 97.04 ;
     RECT  141.84 95.063 141.864 97.04 ;
     RECT  143.088 95.063 143.112 97.04 ;
     RECT  144.336 94.981 144.36 97.04 ;
     RECT  145.584 94.981 145.608 97.04 ;
     RECT  146.832 94.981 146.856 97.04 ;
     RECT  148.128 95.125 148.152 97.04 ;
     RECT  149.376 95.049 149.4 97.04 ;
     RECT  150.624 94.981 150.648 97.04 ;
     RECT  151.872 94.981 151.896 97.04 ;
     RECT  153.12 95.063 153.144 97.04 ;
     RECT  154.368 95.063 154.392 97.04 ;
     RECT  155.616 96.325 155.64 97.04 ;
     RECT  156.864 94.981 156.888 97.04 ;
     RECT  158.112 95.063 158.136 97.04 ;
     RECT  159.36 95.125 159.384 97.04 ;
     RECT  160.656 94.981 160.68 97.04 ;
     RECT  161.904 94.981 161.928 97.04 ;
     RECT  163.152 94.981 163.176 97.04 ;
     RECT  164.4 95.063 164.424 97.04 ;
     RECT  165.648 95.049 165.672 97.04 ;
     RECT  166.896 94.981 166.92 97.04 ;
     RECT  168.144 95.749 168.168 97.04 ;
  END
END ot_s81_hc_ccf_bankpipe_bank256
END LIBRARY
